VERSION 5.8 ;
BUSBITCHARS "[]" ;
DIVIDERCHAR "/" ;
UNITS
    DATABASE MICRONS 1000 ;
END UNITS

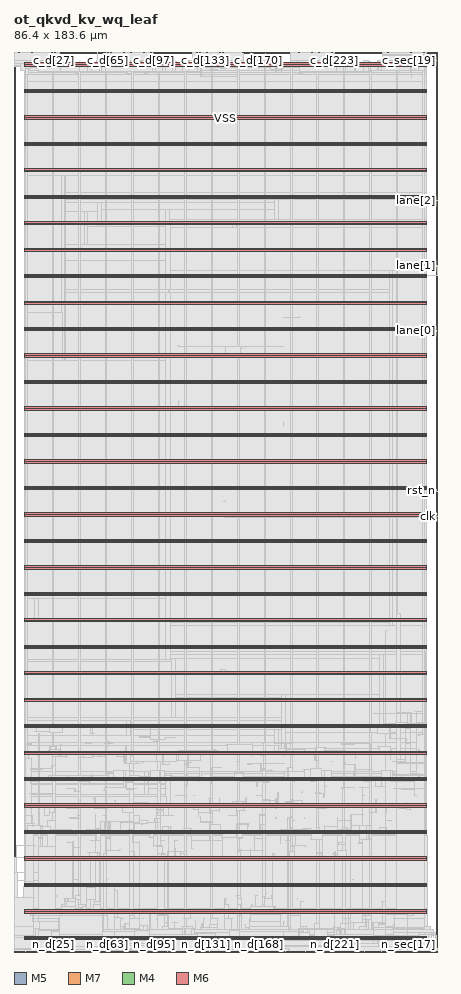
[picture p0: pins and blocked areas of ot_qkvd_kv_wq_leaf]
MACRO ot_qkvd_kv_wq_leaf
  FOREIGN ot_qkvd_kv_wq_leaf 0 0 ;
  CLASS BLOCK ;
  SIZE 86.4 BY 183.6 ;
  PIN c_d[0]
    DIRECTION INPUT ;
    USE SIGNAL ;
    PORT
      LAYER M5 ;
        RECT  0.144 183.516 0.168 183.6 ;
    END
  END c_d[0]
  PIN c_d[100]
    DIRECTION INPUT ;
    USE SIGNAL ;
    PORT
      LAYER M7 ;
        RECT  29.44 183.53 29.472 183.6 ;
    END
  END c_d[100]
  PIN c_d[101]
    DIRECTION INPUT ;
    USE SIGNAL ;
    PORT
      LAYER M7 ;
        RECT  29.696 183.53 29.728 183.6 ;
    END
  END c_d[101]
  PIN c_d[102]
    DIRECTION INPUT ;
    USE SIGNAL ;
    PORT
      LAYER M7 ;
        RECT  30.016 183.53 30.048 183.6 ;
    END
  END c_d[102]
  PIN c_d[103]
    DIRECTION INPUT ;
    USE SIGNAL ;
    PORT
      LAYER M7 ;
        RECT  30.272 183.53 30.304 183.6 ;
    END
  END c_d[103]
  PIN c_d[104]
    DIRECTION INPUT ;
    USE SIGNAL ;
    PORT
      LAYER M7 ;
        RECT  30.592 183.53 30.624 183.6 ;
    END
  END c_d[104]
  PIN c_d[105]
    DIRECTION INPUT ;
    USE SIGNAL ;
    PORT
      LAYER M7 ;
        RECT  30.912 183.53 30.944 183.6 ;
    END
  END c_d[105]
  PIN c_d[106]
    DIRECTION INPUT ;
    USE SIGNAL ;
    PORT
      LAYER M7 ;
        RECT  31.168 183.53 31.2 183.6 ;
    END
  END c_d[106]
  PIN c_d[107]
    DIRECTION INPUT ;
    USE SIGNAL ;
    PORT
      LAYER M7 ;
        RECT  31.488 183.53 31.52 183.6 ;
    END
  END c_d[107]
  PIN c_d[108]
    DIRECTION INPUT ;
    USE SIGNAL ;
    PORT
      LAYER M7 ;
        RECT  31.744 183.53 31.776 183.6 ;
    END
  END c_d[108]
  PIN c_d[109]
    DIRECTION INPUT ;
    USE SIGNAL ;
    PORT
      LAYER M7 ;
        RECT  32.064 183.53 32.096 183.6 ;
    END
  END c_d[109]
  PIN c_d[10]
    DIRECTION INPUT ;
    USE SIGNAL ;
    PORT
      LAYER M5 ;
        RECT  3.072 183.516 3.096 183.6 ;
    END
  END c_d[10]
  PIN c_d[110]
    DIRECTION INPUT ;
    USE SIGNAL ;
    PORT
      LAYER M7 ;
        RECT  32.32 183.53 32.352 183.6 ;
    END
  END c_d[110]
  PIN c_d[111]
    DIRECTION INPUT ;
    USE SIGNAL ;
    PORT
      LAYER M7 ;
        RECT  32.64 183.53 32.672 183.6 ;
    END
  END c_d[111]
  PIN c_d[112]
    DIRECTION INPUT ;
    USE SIGNAL ;
    PORT
      LAYER M7 ;
        RECT  32.96 183.53 32.992 183.6 ;
    END
  END c_d[112]
  PIN c_d[113]
    DIRECTION INPUT ;
    USE SIGNAL ;
    PORT
      LAYER M7 ;
        RECT  33.216 183.53 33.248 183.6 ;
    END
  END c_d[113]
  PIN c_d[114]
    DIRECTION INPUT ;
    USE SIGNAL ;
    PORT
      LAYER M7 ;
        RECT  33.536 183.53 33.568 183.6 ;
    END
  END c_d[114]
  PIN c_d[115]
    DIRECTION INPUT ;
    USE SIGNAL ;
    PORT
      LAYER M7 ;
        RECT  33.792 183.53 33.824 183.6 ;
    END
  END c_d[115]
  PIN c_d[116]
    DIRECTION INPUT ;
    USE SIGNAL ;
    PORT
      LAYER M7 ;
        RECT  34.112 183.53 34.144 183.6 ;
    END
  END c_d[116]
  PIN c_d[117]
    DIRECTION INPUT ;
    USE SIGNAL ;
    PORT
      LAYER M7 ;
        RECT  34.368 183.53 34.4 183.6 ;
    END
  END c_d[117]
  PIN c_d[118]
    DIRECTION INPUT ;
    USE SIGNAL ;
    PORT
      LAYER M7 ;
        RECT  34.688 183.53 34.72 183.6 ;
    END
  END c_d[118]
  PIN c_d[119]
    DIRECTION INPUT ;
    USE SIGNAL ;
    PORT
      LAYER M7 ;
        RECT  35.008 183.53 35.04 183.6 ;
    END
  END c_d[119]
  PIN c_d[11]
    DIRECTION INPUT ;
    USE SIGNAL ;
    PORT
      LAYER M5 ;
        RECT  3.36 183.516 3.384 183.6 ;
    END
  END c_d[11]
  PIN c_d[120]
    DIRECTION INPUT ;
    USE SIGNAL ;
    PORT
      LAYER M7 ;
        RECT  35.264 183.53 35.296 183.6 ;
    END
  END c_d[120]
  PIN c_d[121]
    DIRECTION INPUT ;
    USE SIGNAL ;
    PORT
      LAYER M7 ;
        RECT  35.584 183.53 35.616 183.6 ;
    END
  END c_d[121]
  PIN c_d[122]
    DIRECTION INPUT ;
    USE SIGNAL ;
    PORT
      LAYER M7 ;
        RECT  35.84 183.53 35.872 183.6 ;
    END
  END c_d[122]
  PIN c_d[123]
    DIRECTION INPUT ;
    USE SIGNAL ;
    PORT
      LAYER M7 ;
        RECT  36.16 183.53 36.192 183.6 ;
    END
  END c_d[123]
  PIN c_d[124]
    DIRECTION INPUT ;
    USE SIGNAL ;
    PORT
      LAYER M7 ;
        RECT  36.48 183.53 36.512 183.6 ;
    END
  END c_d[124]
  PIN c_d[125]
    DIRECTION INPUT ;
    USE SIGNAL ;
    PORT
      LAYER M7 ;
        RECT  36.736 183.53 36.768 183.6 ;
    END
  END c_d[125]
  PIN c_d[126]
    DIRECTION INPUT ;
    USE SIGNAL ;
    PORT
      LAYER M7 ;
        RECT  37.056 183.53 37.088 183.6 ;
    END
  END c_d[126]
  PIN c_d[127]
    DIRECTION INPUT ;
    USE SIGNAL ;
    PORT
      LAYER M7 ;
        RECT  37.312 183.53 37.344 183.6 ;
    END
  END c_d[127]
  PIN c_d[128]
    DIRECTION INPUT ;
    USE SIGNAL ;
    PORT
      LAYER M5 ;
        RECT  37.632 183.516 37.656 183.6 ;
    END
  END c_d[128]
  PIN c_d[129]
    DIRECTION INPUT ;
    USE SIGNAL ;
    PORT
      LAYER M5 ;
        RECT  37.92 183.516 37.944 183.6 ;
    END
  END c_d[129]
  PIN c_d[12]
    DIRECTION INPUT ;
    USE SIGNAL ;
    PORT
      LAYER M5 ;
        RECT  3.648 183.516 3.672 183.6 ;
    END
  END c_d[12]
  PIN c_d[130]
    DIRECTION INPUT ;
    USE SIGNAL ;
    PORT
      LAYER M5 ;
        RECT  38.208 183.516 38.232 183.6 ;
    END
  END c_d[130]
  PIN c_d[131]
    DIRECTION INPUT ;
    USE SIGNAL ;
    PORT
      LAYER M5 ;
        RECT  38.496 183.516 38.52 183.6 ;
    END
  END c_d[131]
  PIN c_d[132]
    DIRECTION INPUT ;
    USE SIGNAL ;
    PORT
      LAYER M5 ;
        RECT  38.784 183.516 38.808 183.6 ;
    END
  END c_d[132]
  PIN c_d[133]
    DIRECTION INPUT ;
    USE SIGNAL ;
    PORT
      LAYER M5 ;
        RECT  39.072 183.516 39.096 183.6 ;
    END
  END c_d[133]
  PIN c_d[134]
    DIRECTION INPUT ;
    USE SIGNAL ;
    PORT
      LAYER M5 ;
        RECT  39.36 183.516 39.384 183.6 ;
    END
  END c_d[134]
  PIN c_d[135]
    DIRECTION INPUT ;
    USE SIGNAL ;
    PORT
      LAYER M5 ;
        RECT  39.696 183.516 39.72 183.6 ;
    END
  END c_d[135]
  PIN c_d[136]
    DIRECTION INPUT ;
    USE SIGNAL ;
    PORT
      LAYER M5 ;
        RECT  39.984 183.516 40.008 183.6 ;
    END
  END c_d[136]
  PIN c_d[137]
    DIRECTION INPUT ;
    USE SIGNAL ;
    PORT
      LAYER M5 ;
        RECT  40.272 183.516 40.296 183.6 ;
    END
  END c_d[137]
  PIN c_d[138]
    DIRECTION INPUT ;
    USE SIGNAL ;
    PORT
      LAYER M5 ;
        RECT  40.56 183.516 40.584 183.6 ;
    END
  END c_d[138]
  PIN c_d[139]
    DIRECTION INPUT ;
    USE SIGNAL ;
    PORT
      LAYER M5 ;
        RECT  40.848 183.516 40.872 183.6 ;
    END
  END c_d[139]
  PIN c_d[13]
    DIRECTION INPUT ;
    USE SIGNAL ;
    PORT
      LAYER M5 ;
        RECT  3.936 183.516 3.96 183.6 ;
    END
  END c_d[13]
  PIN c_d[140]
    DIRECTION INPUT ;
    USE SIGNAL ;
    PORT
      LAYER M5 ;
        RECT  41.136 183.516 41.16 183.6 ;
    END
  END c_d[140]
  PIN c_d[141]
    DIRECTION INPUT ;
    USE SIGNAL ;
    PORT
      LAYER M5 ;
        RECT  41.424 183.516 41.448 183.6 ;
    END
  END c_d[141]
  PIN c_d[142]
    DIRECTION INPUT ;
    USE SIGNAL ;
    PORT
      LAYER M5 ;
        RECT  41.712 183.516 41.736 183.6 ;
    END
  END c_d[142]
  PIN c_d[143]
    DIRECTION INPUT ;
    USE SIGNAL ;
    PORT
      LAYER M5 ;
        RECT  42 183.516 42.024 183.6 ;
    END
  END c_d[143]
  PIN c_d[144]
    DIRECTION INPUT ;
    USE SIGNAL ;
    PORT
      LAYER M5 ;
        RECT  42.288 183.516 42.312 183.6 ;
    END
  END c_d[144]
  PIN c_d[145]
    DIRECTION INPUT ;
    USE SIGNAL ;
    PORT
      LAYER M5 ;
        RECT  42.624 183.516 42.648 183.6 ;
    END
  END c_d[145]
  PIN c_d[146]
    DIRECTION INPUT ;
    USE SIGNAL ;
    PORT
      LAYER M5 ;
        RECT  42.912 183.516 42.936 183.6 ;
    END
  END c_d[146]
  PIN c_d[147]
    DIRECTION INPUT ;
    USE SIGNAL ;
    PORT
      LAYER M5 ;
        RECT  43.2 183.516 43.224 183.6 ;
    END
  END c_d[147]
  PIN c_d[148]
    DIRECTION INPUT ;
    USE SIGNAL ;
    PORT
      LAYER M5 ;
        RECT  43.488 183.516 43.512 183.6 ;
    END
  END c_d[148]
  PIN c_d[149]
    DIRECTION INPUT ;
    USE SIGNAL ;
    PORT
      LAYER M5 ;
        RECT  43.776 183.516 43.8 183.6 ;
    END
  END c_d[149]
  PIN c_d[14]
    DIRECTION INPUT ;
    USE SIGNAL ;
    PORT
      LAYER M5 ;
        RECT  4.224 183.516 4.248 183.6 ;
    END
  END c_d[14]
  PIN c_d[150]
    DIRECTION INPUT ;
    USE SIGNAL ;
    PORT
      LAYER M5 ;
        RECT  44.064 183.516 44.088 183.6 ;
    END
  END c_d[150]
  PIN c_d[151]
    DIRECTION INPUT ;
    USE SIGNAL ;
    PORT
      LAYER M5 ;
        RECT  44.352 183.516 44.376 183.6 ;
    END
  END c_d[151]
  PIN c_d[152]
    DIRECTION INPUT ;
    USE SIGNAL ;
    PORT
      LAYER M5 ;
        RECT  44.64 183.516 44.664 183.6 ;
    END
  END c_d[152]
  PIN c_d[153]
    DIRECTION INPUT ;
    USE SIGNAL ;
    PORT
      LAYER M5 ;
        RECT  44.928 183.516 44.952 183.6 ;
    END
  END c_d[153]
  PIN c_d[154]
    DIRECTION INPUT ;
    USE SIGNAL ;
    PORT
      LAYER M5 ;
        RECT  45.216 183.516 45.24 183.6 ;
    END
  END c_d[154]
  PIN c_d[155]
    DIRECTION INPUT ;
    USE SIGNAL ;
    PORT
      LAYER M5 ;
        RECT  45.552 183.516 45.576 183.6 ;
    END
  END c_d[155]
  PIN c_d[156]
    DIRECTION INPUT ;
    USE SIGNAL ;
    PORT
      LAYER M5 ;
        RECT  45.84 183.516 45.864 183.6 ;
    END
  END c_d[156]
  PIN c_d[157]
    DIRECTION INPUT ;
    USE SIGNAL ;
    PORT
      LAYER M5 ;
        RECT  46.128 183.516 46.152 183.6 ;
    END
  END c_d[157]
  PIN c_d[158]
    DIRECTION INPUT ;
    USE SIGNAL ;
    PORT
      LAYER M5 ;
        RECT  46.416 183.516 46.44 183.6 ;
    END
  END c_d[158]
  PIN c_d[159]
    DIRECTION INPUT ;
    USE SIGNAL ;
    PORT
      LAYER M5 ;
        RECT  46.704 183.516 46.728 183.6 ;
    END
  END c_d[159]
  PIN c_d[15]
    DIRECTION INPUT ;
    USE SIGNAL ;
    PORT
      LAYER M5 ;
        RECT  4.512 183.516 4.536 183.6 ;
    END
  END c_d[15]
  PIN c_d[160]
    DIRECTION INPUT ;
    USE SIGNAL ;
    PORT
      LAYER M7 ;
        RECT  46.976 183.53 47.008 183.6 ;
    END
  END c_d[160]
  PIN c_d[161]
    DIRECTION INPUT ;
    USE SIGNAL ;
    PORT
      LAYER M7 ;
        RECT  47.296 183.53 47.328 183.6 ;
    END
  END c_d[161]
  PIN c_d[162]
    DIRECTION INPUT ;
    USE SIGNAL ;
    PORT
      LAYER M7 ;
        RECT  47.552 183.53 47.584 183.6 ;
    END
  END c_d[162]
  PIN c_d[163]
    DIRECTION INPUT ;
    USE SIGNAL ;
    PORT
      LAYER M7 ;
        RECT  47.872 183.53 47.904 183.6 ;
    END
  END c_d[163]
  PIN c_d[164]
    DIRECTION INPUT ;
    USE SIGNAL ;
    PORT
      LAYER M7 ;
        RECT  48.192 183.53 48.224 183.6 ;
    END
  END c_d[164]
  PIN c_d[165]
    DIRECTION INPUT ;
    USE SIGNAL ;
    PORT
      LAYER M7 ;
        RECT  48.448 183.53 48.48 183.6 ;
    END
  END c_d[165]
  PIN c_d[166]
    DIRECTION INPUT ;
    USE SIGNAL ;
    PORT
      LAYER M7 ;
        RECT  48.768 183.53 48.8 183.6 ;
    END
  END c_d[166]
  PIN c_d[167]
    DIRECTION INPUT ;
    USE SIGNAL ;
    PORT
      LAYER M7 ;
        RECT  49.024 183.53 49.056 183.6 ;
    END
  END c_d[167]
  PIN c_d[168]
    DIRECTION INPUT ;
    USE SIGNAL ;
    PORT
      LAYER M7 ;
        RECT  49.344 183.53 49.376 183.6 ;
    END
  END c_d[168]
  PIN c_d[169]
    DIRECTION INPUT ;
    USE SIGNAL ;
    PORT
      LAYER M7 ;
        RECT  49.6 183.53 49.632 183.6 ;
    END
  END c_d[169]
  PIN c_d[16]
    DIRECTION INPUT ;
    USE SIGNAL ;
    PORT
      LAYER M5 ;
        RECT  4.8 183.516 4.824 183.6 ;
    END
  END c_d[16]
  PIN c_d[170]
    DIRECTION INPUT ;
    USE SIGNAL ;
    PORT
      LAYER M7 ;
        RECT  49.92 183.53 49.952 183.6 ;
    END
  END c_d[170]
  PIN c_d[171]
    DIRECTION INPUT ;
    USE SIGNAL ;
    PORT
      LAYER M7 ;
        RECT  50.24 183.53 50.272 183.6 ;
    END
  END c_d[171]
  PIN c_d[172]
    DIRECTION INPUT ;
    USE SIGNAL ;
    PORT
      LAYER M7 ;
        RECT  50.496 183.53 50.528 183.6 ;
    END
  END c_d[172]
  PIN c_d[173]
    DIRECTION INPUT ;
    USE SIGNAL ;
    PORT
      LAYER M7 ;
        RECT  50.816 183.53 50.848 183.6 ;
    END
  END c_d[173]
  PIN c_d[174]
    DIRECTION INPUT ;
    USE SIGNAL ;
    PORT
      LAYER M7 ;
        RECT  51.072 183.53 51.104 183.6 ;
    END
  END c_d[174]
  PIN c_d[175]
    DIRECTION INPUT ;
    USE SIGNAL ;
    PORT
      LAYER M7 ;
        RECT  51.392 183.53 51.424 183.6 ;
    END
  END c_d[175]
  PIN c_d[176]
    DIRECTION INPUT ;
    USE SIGNAL ;
    PORT
      LAYER M7 ;
        RECT  51.648 183.53 51.68 183.6 ;
    END
  END c_d[176]
  PIN c_d[177]
    DIRECTION INPUT ;
    USE SIGNAL ;
    PORT
      LAYER M7 ;
        RECT  51.968 183.53 52 183.6 ;
    END
  END c_d[177]
  PIN c_d[178]
    DIRECTION INPUT ;
    USE SIGNAL ;
    PORT
      LAYER M7 ;
        RECT  52.288 183.53 52.32 183.6 ;
    END
  END c_d[178]
  PIN c_d[179]
    DIRECTION INPUT ;
    USE SIGNAL ;
    PORT
      LAYER M7 ;
        RECT  52.544 183.53 52.576 183.6 ;
    END
  END c_d[179]
  PIN c_d[17]
    DIRECTION INPUT ;
    USE SIGNAL ;
    PORT
      LAYER M5 ;
        RECT  5.136 183.516 5.16 183.6 ;
    END
  END c_d[17]
  PIN c_d[180]
    DIRECTION INPUT ;
    USE SIGNAL ;
    PORT
      LAYER M7 ;
        RECT  52.864 183.53 52.896 183.6 ;
    END
  END c_d[180]
  PIN c_d[181]
    DIRECTION INPUT ;
    USE SIGNAL ;
    PORT
      LAYER M7 ;
        RECT  53.12 183.53 53.152 183.6 ;
    END
  END c_d[181]
  PIN c_d[182]
    DIRECTION INPUT ;
    USE SIGNAL ;
    PORT
      LAYER M7 ;
        RECT  53.44 183.53 53.472 183.6 ;
    END
  END c_d[182]
  PIN c_d[183]
    DIRECTION INPUT ;
    USE SIGNAL ;
    PORT
      LAYER M7 ;
        RECT  53.76 183.53 53.792 183.6 ;
    END
  END c_d[183]
  PIN c_d[184]
    DIRECTION INPUT ;
    USE SIGNAL ;
    PORT
      LAYER M7 ;
        RECT  54.016 183.53 54.048 183.6 ;
    END
  END c_d[184]
  PIN c_d[185]
    DIRECTION INPUT ;
    USE SIGNAL ;
    PORT
      LAYER M7 ;
        RECT  54.336 183.53 54.368 183.6 ;
    END
  END c_d[185]
  PIN c_d[186]
    DIRECTION INPUT ;
    USE SIGNAL ;
    PORT
      LAYER M7 ;
        RECT  54.592 183.53 54.624 183.6 ;
    END
  END c_d[186]
  PIN c_d[187]
    DIRECTION INPUT ;
    USE SIGNAL ;
    PORT
      LAYER M7 ;
        RECT  54.912 183.53 54.944 183.6 ;
    END
  END c_d[187]
  PIN c_d[188]
    DIRECTION INPUT ;
    USE SIGNAL ;
    PORT
      LAYER M7 ;
        RECT  55.168 183.53 55.2 183.6 ;
    END
  END c_d[188]
  PIN c_d[189]
    DIRECTION INPUT ;
    USE SIGNAL ;
    PORT
      LAYER M7 ;
        RECT  55.488 183.53 55.52 183.6 ;
    END
  END c_d[189]
  PIN c_d[18]
    DIRECTION INPUT ;
    USE SIGNAL ;
    PORT
      LAYER M5 ;
        RECT  5.424 183.516 5.448 183.6 ;
    END
  END c_d[18]
  PIN c_d[190]
    DIRECTION INPUT ;
    USE SIGNAL ;
    PORT
      LAYER M7 ;
        RECT  55.808 183.53 55.84 183.6 ;
    END
  END c_d[190]
  PIN c_d[191]
    DIRECTION INPUT ;
    USE SIGNAL ;
    PORT
      LAYER M7 ;
        RECT  56.064 183.53 56.096 183.6 ;
    END
  END c_d[191]
  PIN c_d[192]
    DIRECTION INPUT ;
    USE SIGNAL ;
    PORT
      LAYER M5 ;
        RECT  56.352 183.516 56.376 183.6 ;
    END
  END c_d[192]
  PIN c_d[193]
    DIRECTION INPUT ;
    USE SIGNAL ;
    PORT
      LAYER M5 ;
        RECT  56.64 183.516 56.664 183.6 ;
    END
  END c_d[193]
  PIN c_d[194]
    DIRECTION INPUT ;
    USE SIGNAL ;
    PORT
      LAYER M5 ;
        RECT  56.976 183.516 57 183.6 ;
    END
  END c_d[194]
  PIN c_d[195]
    DIRECTION INPUT ;
    USE SIGNAL ;
    PORT
      LAYER M5 ;
        RECT  57.264 183.516 57.288 183.6 ;
    END
  END c_d[195]
  PIN c_d[196]
    DIRECTION INPUT ;
    USE SIGNAL ;
    PORT
      LAYER M5 ;
        RECT  57.552 183.516 57.576 183.6 ;
    END
  END c_d[196]
  PIN c_d[197]
    DIRECTION INPUT ;
    USE SIGNAL ;
    PORT
      LAYER M5 ;
        RECT  57.84 183.516 57.864 183.6 ;
    END
  END c_d[197]
  PIN c_d[198]
    DIRECTION INPUT ;
    USE SIGNAL ;
    PORT
      LAYER M5 ;
        RECT  58.128 183.516 58.152 183.6 ;
    END
  END c_d[198]
  PIN c_d[199]
    DIRECTION INPUT ;
    USE SIGNAL ;
    PORT
      LAYER M5 ;
        RECT  58.416 183.516 58.44 183.6 ;
    END
  END c_d[199]
  PIN c_d[19]
    DIRECTION INPUT ;
    USE SIGNAL ;
    PORT
      LAYER M5 ;
        RECT  5.712 183.516 5.736 183.6 ;
    END
  END c_d[19]
  PIN c_d[1]
    DIRECTION INPUT ;
    USE SIGNAL ;
    PORT
      LAYER M5 ;
        RECT  0.432 183.516 0.456 183.6 ;
    END
  END c_d[1]
  PIN c_d[200]
    DIRECTION INPUT ;
    USE SIGNAL ;
    PORT
      LAYER M5 ;
        RECT  58.704 183.516 58.728 183.6 ;
    END
  END c_d[200]
  PIN c_d[201]
    DIRECTION INPUT ;
    USE SIGNAL ;
    PORT
      LAYER M5 ;
        RECT  58.992 183.516 59.016 183.6 ;
    END
  END c_d[201]
  PIN c_d[202]
    DIRECTION INPUT ;
    USE SIGNAL ;
    PORT
      LAYER M5 ;
        RECT  59.28 183.516 59.304 183.6 ;
    END
  END c_d[202]
  PIN c_d[203]
    DIRECTION INPUT ;
    USE SIGNAL ;
    PORT
      LAYER M5 ;
        RECT  59.568 183.516 59.592 183.6 ;
    END
  END c_d[203]
  PIN c_d[204]
    DIRECTION INPUT ;
    USE SIGNAL ;
    PORT
      LAYER M5 ;
        RECT  59.904 183.516 59.928 183.6 ;
    END
  END c_d[204]
  PIN c_d[205]
    DIRECTION INPUT ;
    USE SIGNAL ;
    PORT
      LAYER M5 ;
        RECT  60.192 183.516 60.216 183.6 ;
    END
  END c_d[205]
  PIN c_d[206]
    DIRECTION INPUT ;
    USE SIGNAL ;
    PORT
      LAYER M5 ;
        RECT  60.48 183.516 60.504 183.6 ;
    END
  END c_d[206]
  PIN c_d[207]
    DIRECTION INPUT ;
    USE SIGNAL ;
    PORT
      LAYER M5 ;
        RECT  60.768 183.516 60.792 183.6 ;
    END
  END c_d[207]
  PIN c_d[208]
    DIRECTION INPUT ;
    USE SIGNAL ;
    PORT
      LAYER M5 ;
        RECT  61.056 183.516 61.08 183.6 ;
    END
  END c_d[208]
  PIN c_d[209]
    DIRECTION INPUT ;
    USE SIGNAL ;
    PORT
      LAYER M5 ;
        RECT  61.344 183.516 61.368 183.6 ;
    END
  END c_d[209]
  PIN c_d[20]
    DIRECTION INPUT ;
    USE SIGNAL ;
    PORT
      LAYER M5 ;
        RECT  6 183.516 6.024 183.6 ;
    END
  END c_d[20]
  PIN c_d[210]
    DIRECTION INPUT ;
    USE SIGNAL ;
    PORT
      LAYER M5 ;
        RECT  61.632 183.516 61.656 183.6 ;
    END
  END c_d[210]
  PIN c_d[211]
    DIRECTION INPUT ;
    USE SIGNAL ;
    PORT
      LAYER M5 ;
        RECT  61.92 183.516 61.944 183.6 ;
    END
  END c_d[211]
  PIN c_d[212]
    DIRECTION INPUT ;
    USE SIGNAL ;
    PORT
      LAYER M5 ;
        RECT  62.208 183.516 62.232 183.6 ;
    END
  END c_d[212]
  PIN c_d[213]
    DIRECTION INPUT ;
    USE SIGNAL ;
    PORT
      LAYER M5 ;
        RECT  62.496 183.516 62.52 183.6 ;
    END
  END c_d[213]
  PIN c_d[214]
    DIRECTION INPUT ;
    USE SIGNAL ;
    PORT
      LAYER M5 ;
        RECT  62.832 183.516 62.856 183.6 ;
    END
  END c_d[214]
  PIN c_d[215]
    DIRECTION INPUT ;
    USE SIGNAL ;
    PORT
      LAYER M5 ;
        RECT  63.12 183.516 63.144 183.6 ;
    END
  END c_d[215]
  PIN c_d[216]
    DIRECTION INPUT ;
    USE SIGNAL ;
    PORT
      LAYER M5 ;
        RECT  63.408 183.516 63.432 183.6 ;
    END
  END c_d[216]
  PIN c_d[217]
    DIRECTION INPUT ;
    USE SIGNAL ;
    PORT
      LAYER M5 ;
        RECT  63.696 183.516 63.72 183.6 ;
    END
  END c_d[217]
  PIN c_d[218]
    DIRECTION INPUT ;
    USE SIGNAL ;
    PORT
      LAYER M5 ;
        RECT  63.984 183.516 64.008 183.6 ;
    END
  END c_d[218]
  PIN c_d[219]
    DIRECTION INPUT ;
    USE SIGNAL ;
    PORT
      LAYER M5 ;
        RECT  64.272 183.516 64.296 183.6 ;
    END
  END c_d[219]
  PIN c_d[21]
    DIRECTION INPUT ;
    USE SIGNAL ;
    PORT
      LAYER M5 ;
        RECT  6.288 183.516 6.312 183.6 ;
    END
  END c_d[21]
  PIN c_d[220]
    DIRECTION INPUT ;
    USE SIGNAL ;
    PORT
      LAYER M5 ;
        RECT  64.56 183.516 64.584 183.6 ;
    END
  END c_d[220]
  PIN c_d[221]
    DIRECTION INPUT ;
    USE SIGNAL ;
    PORT
      LAYER M5 ;
        RECT  64.848 183.516 64.872 183.6 ;
    END
  END c_d[221]
  PIN c_d[222]
    DIRECTION INPUT ;
    USE SIGNAL ;
    PORT
      LAYER M5 ;
        RECT  65.136 183.516 65.16 183.6 ;
    END
  END c_d[222]
  PIN c_d[223]
    DIRECTION INPUT ;
    USE SIGNAL ;
    PORT
      LAYER M5 ;
        RECT  65.424 183.516 65.448 183.6 ;
    END
  END c_d[223]
  PIN c_d[224]
    DIRECTION INPUT ;
    USE SIGNAL ;
    PORT
      LAYER M7 ;
        RECT  65.728 183.53 65.76 183.6 ;
    END
  END c_d[224]
  PIN c_d[225]
    DIRECTION INPUT ;
    USE SIGNAL ;
    PORT
      LAYER M7 ;
        RECT  66.048 183.53 66.08 183.6 ;
    END
  END c_d[225]
  PIN c_d[226]
    DIRECTION INPUT ;
    USE SIGNAL ;
    PORT
      LAYER M7 ;
        RECT  66.304 183.53 66.336 183.6 ;
    END
  END c_d[226]
  PIN c_d[227]
    DIRECTION INPUT ;
    USE SIGNAL ;
    PORT
      LAYER M7 ;
        RECT  66.624 183.53 66.656 183.6 ;
    END
  END c_d[227]
  PIN c_d[228]
    DIRECTION INPUT ;
    USE SIGNAL ;
    PORT
      LAYER M7 ;
        RECT  66.88 183.53 66.912 183.6 ;
    END
  END c_d[228]
  PIN c_d[229]
    DIRECTION INPUT ;
    USE SIGNAL ;
    PORT
      LAYER M7 ;
        RECT  67.2 183.53 67.232 183.6 ;
    END
  END c_d[229]
  PIN c_d[22]
    DIRECTION INPUT ;
    USE SIGNAL ;
    PORT
      LAYER M5 ;
        RECT  6.576 183.516 6.6 183.6 ;
    END
  END c_d[22]
  PIN c_d[230]
    DIRECTION INPUT ;
    USE SIGNAL ;
    PORT
      LAYER M7 ;
        RECT  67.52 183.53 67.552 183.6 ;
    END
  END c_d[230]
  PIN c_d[231]
    DIRECTION INPUT ;
    USE SIGNAL ;
    PORT
      LAYER M7 ;
        RECT  67.776 183.53 67.808 183.6 ;
    END
  END c_d[231]
  PIN c_d[232]
    DIRECTION INPUT ;
    USE SIGNAL ;
    PORT
      LAYER M7 ;
        RECT  68.096 183.53 68.128 183.6 ;
    END
  END c_d[232]
  PIN c_d[233]
    DIRECTION INPUT ;
    USE SIGNAL ;
    PORT
      LAYER M7 ;
        RECT  68.352 183.53 68.384 183.6 ;
    END
  END c_d[233]
  PIN c_d[234]
    DIRECTION INPUT ;
    USE SIGNAL ;
    PORT
      LAYER M7 ;
        RECT  68.672 183.53 68.704 183.6 ;
    END
  END c_d[234]
  PIN c_d[235]
    DIRECTION INPUT ;
    USE SIGNAL ;
    PORT
      LAYER M7 ;
        RECT  68.928 183.53 68.96 183.6 ;
    END
  END c_d[235]
  PIN c_d[236]
    DIRECTION INPUT ;
    USE SIGNAL ;
    PORT
      LAYER M7 ;
        RECT  69.248 183.53 69.28 183.6 ;
    END
  END c_d[236]
  PIN c_d[237]
    DIRECTION INPUT ;
    USE SIGNAL ;
    PORT
      LAYER M7 ;
        RECT  69.568 183.53 69.6 183.6 ;
    END
  END c_d[237]
  PIN c_d[238]
    DIRECTION INPUT ;
    USE SIGNAL ;
    PORT
      LAYER M7 ;
        RECT  69.824 183.53 69.856 183.6 ;
    END
  END c_d[238]
  PIN c_d[239]
    DIRECTION INPUT ;
    USE SIGNAL ;
    PORT
      LAYER M7 ;
        RECT  70.144 183.53 70.176 183.6 ;
    END
  END c_d[239]
  PIN c_d[23]
    DIRECTION INPUT ;
    USE SIGNAL ;
    PORT
      LAYER M5 ;
        RECT  6.864 183.516 6.888 183.6 ;
    END
  END c_d[23]
  PIN c_d[240]
    DIRECTION INPUT ;
    USE SIGNAL ;
    PORT
      LAYER M7 ;
        RECT  70.4 183.53 70.432 183.6 ;
    END
  END c_d[240]
  PIN c_d[241]
    DIRECTION INPUT ;
    USE SIGNAL ;
    PORT
      LAYER M7 ;
        RECT  70.72 183.53 70.752 183.6 ;
    END
  END c_d[241]
  PIN c_d[242]
    DIRECTION INPUT ;
    USE SIGNAL ;
    PORT
      LAYER M7 ;
        RECT  71.04 183.53 71.072 183.6 ;
    END
  END c_d[242]
  PIN c_d[243]
    DIRECTION INPUT ;
    USE SIGNAL ;
    PORT
      LAYER M7 ;
        RECT  71.296 183.53 71.328 183.6 ;
    END
  END c_d[243]
  PIN c_d[244]
    DIRECTION INPUT ;
    USE SIGNAL ;
    PORT
      LAYER M7 ;
        RECT  71.616 183.53 71.648 183.6 ;
    END
  END c_d[244]
  PIN c_d[245]
    DIRECTION INPUT ;
    USE SIGNAL ;
    PORT
      LAYER M7 ;
        RECT  71.872 183.53 71.904 183.6 ;
    END
  END c_d[245]
  PIN c_d[246]
    DIRECTION INPUT ;
    USE SIGNAL ;
    PORT
      LAYER M7 ;
        RECT  72.192 183.53 72.224 183.6 ;
    END
  END c_d[246]
  PIN c_d[247]
    DIRECTION INPUT ;
    USE SIGNAL ;
    PORT
      LAYER M7 ;
        RECT  72.448 183.53 72.48 183.6 ;
    END
  END c_d[247]
  PIN c_d[248]
    DIRECTION INPUT ;
    USE SIGNAL ;
    PORT
      LAYER M7 ;
        RECT  72.768 183.53 72.8 183.6 ;
    END
  END c_d[248]
  PIN c_d[249]
    DIRECTION INPUT ;
    USE SIGNAL ;
    PORT
      LAYER M7 ;
        RECT  73.088 183.53 73.12 183.6 ;
    END
  END c_d[249]
  PIN c_d[24]
    DIRECTION INPUT ;
    USE SIGNAL ;
    PORT
      LAYER M5 ;
        RECT  7.152 183.516 7.176 183.6 ;
    END
  END c_d[24]
  PIN c_d[250]
    DIRECTION INPUT ;
    USE SIGNAL ;
    PORT
      LAYER M7 ;
        RECT  73.344 183.53 73.376 183.6 ;
    END
  END c_d[250]
  PIN c_d[251]
    DIRECTION INPUT ;
    USE SIGNAL ;
    PORT
      LAYER M7 ;
        RECT  73.664 183.53 73.696 183.6 ;
    END
  END c_d[251]
  PIN c_d[252]
    DIRECTION INPUT ;
    USE SIGNAL ;
    PORT
      LAYER M7 ;
        RECT  73.92 183.53 73.952 183.6 ;
    END
  END c_d[252]
  PIN c_d[253]
    DIRECTION INPUT ;
    USE SIGNAL ;
    PORT
      LAYER M7 ;
        RECT  74.24 183.53 74.272 183.6 ;
    END
  END c_d[253]
  PIN c_d[254]
    DIRECTION INPUT ;
    USE SIGNAL ;
    PORT
      LAYER M7 ;
        RECT  74.496 183.53 74.528 183.6 ;
    END
  END c_d[254]
  PIN c_d[255]
    DIRECTION INPUT ;
    USE SIGNAL ;
    PORT
      LAYER M7 ;
        RECT  74.816 183.53 74.848 183.6 ;
    END
  END c_d[255]
  PIN c_d[25]
    DIRECTION INPUT ;
    USE SIGNAL ;
    PORT
      LAYER M5 ;
        RECT  7.44 183.516 7.464 183.6 ;
    END
  END c_d[25]
  PIN c_d[26]
    DIRECTION INPUT ;
    USE SIGNAL ;
    PORT
      LAYER M5 ;
        RECT  7.728 183.516 7.752 183.6 ;
    END
  END c_d[26]
  PIN c_d[27]
    DIRECTION INPUT ;
    USE SIGNAL ;
    PORT
      LAYER M5 ;
        RECT  8.064 183.516 8.088 183.6 ;
    END
  END c_d[27]
  PIN c_d[28]
    DIRECTION INPUT ;
    USE SIGNAL ;
    PORT
      LAYER M5 ;
        RECT  8.352 183.516 8.376 183.6 ;
    END
  END c_d[28]
  PIN c_d[29]
    DIRECTION INPUT ;
    USE SIGNAL ;
    PORT
      LAYER M5 ;
        RECT  8.64 183.516 8.664 183.6 ;
    END
  END c_d[29]
  PIN c_d[2]
    DIRECTION INPUT ;
    USE SIGNAL ;
    PORT
      LAYER M5 ;
        RECT  0.72 183.516 0.744 183.6 ;
    END
  END c_d[2]
  PIN c_d[30]
    DIRECTION INPUT ;
    USE SIGNAL ;
    PORT
      LAYER M5 ;
        RECT  8.928 183.516 8.952 183.6 ;
    END
  END c_d[30]
  PIN c_d[31]
    DIRECTION INPUT ;
    USE SIGNAL ;
    PORT
      LAYER M5 ;
        RECT  9.216 183.516 9.24 183.6 ;
    END
  END c_d[31]
  PIN c_d[32]
    DIRECTION INPUT ;
    USE SIGNAL ;
    PORT
      LAYER M7 ;
        RECT  9.472 183.53 9.504 183.6 ;
    END
  END c_d[32]
  PIN c_d[33]
    DIRECTION INPUT ;
    USE SIGNAL ;
    PORT
      LAYER M7 ;
        RECT  9.792 183.53 9.824 183.6 ;
    END
  END c_d[33]
  PIN c_d[34]
    DIRECTION INPUT ;
    USE SIGNAL ;
    PORT
      LAYER M7 ;
        RECT  10.112 183.53 10.144 183.6 ;
    END
  END c_d[34]
  PIN c_d[35]
    DIRECTION INPUT ;
    USE SIGNAL ;
    PORT
      LAYER M7 ;
        RECT  10.368 183.53 10.4 183.6 ;
    END
  END c_d[35]
  PIN c_d[36]
    DIRECTION INPUT ;
    USE SIGNAL ;
    PORT
      LAYER M7 ;
        RECT  10.688 183.53 10.72 183.6 ;
    END
  END c_d[36]
  PIN c_d[37]
    DIRECTION INPUT ;
    USE SIGNAL ;
    PORT
      LAYER M7 ;
        RECT  10.944 183.53 10.976 183.6 ;
    END
  END c_d[37]
  PIN c_d[38]
    DIRECTION INPUT ;
    USE SIGNAL ;
    PORT
      LAYER M7 ;
        RECT  11.264 183.53 11.296 183.6 ;
    END
  END c_d[38]
  PIN c_d[39]
    DIRECTION INPUT ;
    USE SIGNAL ;
    PORT
      LAYER M7 ;
        RECT  11.584 183.53 11.616 183.6 ;
    END
  END c_d[39]
  PIN c_d[3]
    DIRECTION INPUT ;
    USE SIGNAL ;
    PORT
      LAYER M5 ;
        RECT  1.008 183.516 1.032 183.6 ;
    END
  END c_d[3]
  PIN c_d[40]
    DIRECTION INPUT ;
    USE SIGNAL ;
    PORT
      LAYER M7 ;
        RECT  11.84 183.53 11.872 183.6 ;
    END
  END c_d[40]
  PIN c_d[41]
    DIRECTION INPUT ;
    USE SIGNAL ;
    PORT
      LAYER M7 ;
        RECT  12.16 183.53 12.192 183.6 ;
    END
  END c_d[41]
  PIN c_d[42]
    DIRECTION INPUT ;
    USE SIGNAL ;
    PORT
      LAYER M7 ;
        RECT  12.416 183.53 12.448 183.6 ;
    END
  END c_d[42]
  PIN c_d[43]
    DIRECTION INPUT ;
    USE SIGNAL ;
    PORT
      LAYER M7 ;
        RECT  12.736 183.53 12.768 183.6 ;
    END
  END c_d[43]
  PIN c_d[44]
    DIRECTION INPUT ;
    USE SIGNAL ;
    PORT
      LAYER M7 ;
        RECT  12.992 183.53 13.024 183.6 ;
    END
  END c_d[44]
  PIN c_d[45]
    DIRECTION INPUT ;
    USE SIGNAL ;
    PORT
      LAYER M7 ;
        RECT  13.312 183.53 13.344 183.6 ;
    END
  END c_d[45]
  PIN c_d[46]
    DIRECTION INPUT ;
    USE SIGNAL ;
    PORT
      LAYER M7 ;
        RECT  13.632 183.53 13.664 183.6 ;
    END
  END c_d[46]
  PIN c_d[47]
    DIRECTION INPUT ;
    USE SIGNAL ;
    PORT
      LAYER M7 ;
        RECT  13.888 183.53 13.92 183.6 ;
    END
  END c_d[47]
  PIN c_d[48]
    DIRECTION INPUT ;
    USE SIGNAL ;
    PORT
      LAYER M7 ;
        RECT  14.208 183.53 14.24 183.6 ;
    END
  END c_d[48]
  PIN c_d[49]
    DIRECTION INPUT ;
    USE SIGNAL ;
    PORT
      LAYER M7 ;
        RECT  14.464 183.53 14.496 183.6 ;
    END
  END c_d[49]
  PIN c_d[4]
    DIRECTION INPUT ;
    USE SIGNAL ;
    PORT
      LAYER M5 ;
        RECT  1.296 183.516 1.32 183.6 ;
    END
  END c_d[4]
  PIN c_d[50]
    DIRECTION INPUT ;
    USE SIGNAL ;
    PORT
      LAYER M7 ;
        RECT  14.784 183.53 14.816 183.6 ;
    END
  END c_d[50]
  PIN c_d[51]
    DIRECTION INPUT ;
    USE SIGNAL ;
    PORT
      LAYER M7 ;
        RECT  15.04 183.53 15.072 183.6 ;
    END
  END c_d[51]
  PIN c_d[52]
    DIRECTION INPUT ;
    USE SIGNAL ;
    PORT
      LAYER M7 ;
        RECT  15.36 183.53 15.392 183.6 ;
    END
  END c_d[52]
  PIN c_d[53]
    DIRECTION INPUT ;
    USE SIGNAL ;
    PORT
      LAYER M7 ;
        RECT  15.68 183.53 15.712 183.6 ;
    END
  END c_d[53]
  PIN c_d[54]
    DIRECTION INPUT ;
    USE SIGNAL ;
    PORT
      LAYER M7 ;
        RECT  15.936 183.53 15.968 183.6 ;
    END
  END c_d[54]
  PIN c_d[55]
    DIRECTION INPUT ;
    USE SIGNAL ;
    PORT
      LAYER M7 ;
        RECT  16.256 183.53 16.288 183.6 ;
    END
  END c_d[55]
  PIN c_d[56]
    DIRECTION INPUT ;
    USE SIGNAL ;
    PORT
      LAYER M7 ;
        RECT  16.512 183.53 16.544 183.6 ;
    END
  END c_d[56]
  PIN c_d[57]
    DIRECTION INPUT ;
    USE SIGNAL ;
    PORT
      LAYER M7 ;
        RECT  16.832 183.53 16.864 183.6 ;
    END
  END c_d[57]
  PIN c_d[58]
    DIRECTION INPUT ;
    USE SIGNAL ;
    PORT
      LAYER M7 ;
        RECT  17.088 183.53 17.12 183.6 ;
    END
  END c_d[58]
  PIN c_d[59]
    DIRECTION INPUT ;
    USE SIGNAL ;
    PORT
      LAYER M7 ;
        RECT  17.408 183.53 17.44 183.6 ;
    END
  END c_d[59]
  PIN c_d[5]
    DIRECTION INPUT ;
    USE SIGNAL ;
    PORT
      LAYER M5 ;
        RECT  1.584 183.516 1.608 183.6 ;
    END
  END c_d[5]
  PIN c_d[60]
    DIRECTION INPUT ;
    USE SIGNAL ;
    PORT
      LAYER M7 ;
        RECT  17.728 183.53 17.76 183.6 ;
    END
  END c_d[60]
  PIN c_d[61]
    DIRECTION INPUT ;
    USE SIGNAL ;
    PORT
      LAYER M7 ;
        RECT  17.984 183.53 18.016 183.6 ;
    END
  END c_d[61]
  PIN c_d[62]
    DIRECTION INPUT ;
    USE SIGNAL ;
    PORT
      LAYER M7 ;
        RECT  18.304 183.53 18.336 183.6 ;
    END
  END c_d[62]
  PIN c_d[63]
    DIRECTION INPUT ;
    USE SIGNAL ;
    PORT
      LAYER M7 ;
        RECT  18.56 183.53 18.592 183.6 ;
    END
  END c_d[63]
  PIN c_d[64]
    DIRECTION INPUT ;
    USE SIGNAL ;
    PORT
      LAYER M5 ;
        RECT  18.864 183.516 18.888 183.6 ;
    END
  END c_d[64]
  PIN c_d[65]
    DIRECTION INPUT ;
    USE SIGNAL ;
    PORT
      LAYER M5 ;
        RECT  19.152 183.516 19.176 183.6 ;
    END
  END c_d[65]
  PIN c_d[66]
    DIRECTION INPUT ;
    USE SIGNAL ;
    PORT
      LAYER M5 ;
        RECT  19.488 183.516 19.512 183.6 ;
    END
  END c_d[66]
  PIN c_d[67]
    DIRECTION INPUT ;
    USE SIGNAL ;
    PORT
      LAYER M5 ;
        RECT  19.776 183.516 19.8 183.6 ;
    END
  END c_d[67]
  PIN c_d[68]
    DIRECTION INPUT ;
    USE SIGNAL ;
    PORT
      LAYER M5 ;
        RECT  20.064 183.516 20.088 183.6 ;
    END
  END c_d[68]
  PIN c_d[69]
    DIRECTION INPUT ;
    USE SIGNAL ;
    PORT
      LAYER M5 ;
        RECT  20.352 183.516 20.376 183.6 ;
    END
  END c_d[69]
  PIN c_d[6]
    DIRECTION INPUT ;
    USE SIGNAL ;
    PORT
      LAYER M5 ;
        RECT  1.872 183.516 1.896 183.6 ;
    END
  END c_d[6]
  PIN c_d[70]
    DIRECTION INPUT ;
    USE SIGNAL ;
    PORT
      LAYER M5 ;
        RECT  20.64 183.516 20.664 183.6 ;
    END
  END c_d[70]
  PIN c_d[71]
    DIRECTION INPUT ;
    USE SIGNAL ;
    PORT
      LAYER M5 ;
        RECT  20.928 183.516 20.952 183.6 ;
    END
  END c_d[71]
  PIN c_d[72]
    DIRECTION INPUT ;
    USE SIGNAL ;
    PORT
      LAYER M5 ;
        RECT  21.216 183.516 21.24 183.6 ;
    END
  END c_d[72]
  PIN c_d[73]
    DIRECTION INPUT ;
    USE SIGNAL ;
    PORT
      LAYER M5 ;
        RECT  21.504 183.516 21.528 183.6 ;
    END
  END c_d[73]
  PIN c_d[74]
    DIRECTION INPUT ;
    USE SIGNAL ;
    PORT
      LAYER M5 ;
        RECT  21.792 183.516 21.816 183.6 ;
    END
  END c_d[74]
  PIN c_d[75]
    DIRECTION INPUT ;
    USE SIGNAL ;
    PORT
      LAYER M5 ;
        RECT  22.08 183.516 22.104 183.6 ;
    END
  END c_d[75]
  PIN c_d[76]
    DIRECTION INPUT ;
    USE SIGNAL ;
    PORT
      LAYER M5 ;
        RECT  22.416 183.516 22.44 183.6 ;
    END
  END c_d[76]
  PIN c_d[77]
    DIRECTION INPUT ;
    USE SIGNAL ;
    PORT
      LAYER M5 ;
        RECT  22.704 183.516 22.728 183.6 ;
    END
  END c_d[77]
  PIN c_d[78]
    DIRECTION INPUT ;
    USE SIGNAL ;
    PORT
      LAYER M5 ;
        RECT  22.992 183.516 23.016 183.6 ;
    END
  END c_d[78]
  PIN c_d[79]
    DIRECTION INPUT ;
    USE SIGNAL ;
    PORT
      LAYER M5 ;
        RECT  23.28 183.516 23.304 183.6 ;
    END
  END c_d[79]
  PIN c_d[7]
    DIRECTION INPUT ;
    USE SIGNAL ;
    PORT
      LAYER M5 ;
        RECT  2.208 183.516 2.232 183.6 ;
    END
  END c_d[7]
  PIN c_d[80]
    DIRECTION INPUT ;
    USE SIGNAL ;
    PORT
      LAYER M5 ;
        RECT  23.568 183.516 23.592 183.6 ;
    END
  END c_d[80]
  PIN c_d[81]
    DIRECTION INPUT ;
    USE SIGNAL ;
    PORT
      LAYER M5 ;
        RECT  23.856 183.516 23.88 183.6 ;
    END
  END c_d[81]
  PIN c_d[82]
    DIRECTION INPUT ;
    USE SIGNAL ;
    PORT
      LAYER M5 ;
        RECT  24.144 183.516 24.168 183.6 ;
    END
  END c_d[82]
  PIN c_d[83]
    DIRECTION INPUT ;
    USE SIGNAL ;
    PORT
      LAYER M5 ;
        RECT  24.432 183.516 24.456 183.6 ;
    END
  END c_d[83]
  PIN c_d[84]
    DIRECTION INPUT ;
    USE SIGNAL ;
    PORT
      LAYER M5 ;
        RECT  24.72 183.516 24.744 183.6 ;
    END
  END c_d[84]
  PIN c_d[85]
    DIRECTION INPUT ;
    USE SIGNAL ;
    PORT
      LAYER M5 ;
        RECT  25.008 183.516 25.032 183.6 ;
    END
  END c_d[85]
  PIN c_d[86]
    DIRECTION INPUT ;
    USE SIGNAL ;
    PORT
      LAYER M5 ;
        RECT  25.344 183.516 25.368 183.6 ;
    END
  END c_d[86]
  PIN c_d[87]
    DIRECTION INPUT ;
    USE SIGNAL ;
    PORT
      LAYER M5 ;
        RECT  25.632 183.516 25.656 183.6 ;
    END
  END c_d[87]
  PIN c_d[88]
    DIRECTION INPUT ;
    USE SIGNAL ;
    PORT
      LAYER M5 ;
        RECT  25.92 183.516 25.944 183.6 ;
    END
  END c_d[88]
  PIN c_d[89]
    DIRECTION INPUT ;
    USE SIGNAL ;
    PORT
      LAYER M5 ;
        RECT  26.208 183.516 26.232 183.6 ;
    END
  END c_d[89]
  PIN c_d[8]
    DIRECTION INPUT ;
    USE SIGNAL ;
    PORT
      LAYER M5 ;
        RECT  2.496 183.516 2.52 183.6 ;
    END
  END c_d[8]
  PIN c_d[90]
    DIRECTION INPUT ;
    USE SIGNAL ;
    PORT
      LAYER M5 ;
        RECT  26.496 183.516 26.52 183.6 ;
    END
  END c_d[90]
  PIN c_d[91]
    DIRECTION INPUT ;
    USE SIGNAL ;
    PORT
      LAYER M5 ;
        RECT  26.784 183.516 26.808 183.6 ;
    END
  END c_d[91]
  PIN c_d[92]
    DIRECTION INPUT ;
    USE SIGNAL ;
    PORT
      LAYER M5 ;
        RECT  27.072 183.516 27.096 183.6 ;
    END
  END c_d[92]
  PIN c_d[93]
    DIRECTION INPUT ;
    USE SIGNAL ;
    PORT
      LAYER M5 ;
        RECT  27.36 183.516 27.384 183.6 ;
    END
  END c_d[93]
  PIN c_d[94]
    DIRECTION INPUT ;
    USE SIGNAL ;
    PORT
      LAYER M5 ;
        RECT  27.648 183.516 27.672 183.6 ;
    END
  END c_d[94]
  PIN c_d[95]
    DIRECTION INPUT ;
    USE SIGNAL ;
    PORT
      LAYER M5 ;
        RECT  27.936 183.516 27.96 183.6 ;
    END
  END c_d[95]
  PIN c_d[96]
    DIRECTION INPUT ;
    USE SIGNAL ;
    PORT
      LAYER M7 ;
        RECT  28.224 183.53 28.256 183.6 ;
    END
  END c_d[96]
  PIN c_d[97]
    DIRECTION INPUT ;
    USE SIGNAL ;
    PORT
      LAYER M7 ;
        RECT  28.544 183.53 28.576 183.6 ;
    END
  END c_d[97]
  PIN c_d[98]
    DIRECTION INPUT ;
    USE SIGNAL ;
    PORT
      LAYER M7 ;
        RECT  28.864 183.53 28.896 183.6 ;
    END
  END c_d[98]
  PIN c_d[99]
    DIRECTION INPUT ;
    USE SIGNAL ;
    PORT
      LAYER M7 ;
        RECT  29.12 183.53 29.152 183.6 ;
    END
  END c_d[99]
  PIN c_d[9]
    DIRECTION INPUT ;
    USE SIGNAL ;
    PORT
      LAYER M5 ;
        RECT  2.784 183.516 2.808 183.6 ;
    END
  END c_d[9]
  PIN c_lane[0]
    DIRECTION INPUT ;
    USE SIGNAL ;
    PORT
      LAYER M5 ;
        RECT  75.12 183.516 75.144 183.6 ;
    END
  END c_lane[0]
  PIN c_lane[1]
    DIRECTION INPUT ;
    USE SIGNAL ;
    PORT
      LAYER M5 ;
        RECT  75.408 183.516 75.432 183.6 ;
    END
  END c_lane[1]
  PIN c_lane[2]
    DIRECTION INPUT ;
    USE SIGNAL ;
    PORT
      LAYER M5 ;
        RECT  75.696 183.516 75.72 183.6 ;
    END
  END c_lane[2]
  PIN c_sec[0]
    DIRECTION INPUT ;
    USE SIGNAL ;
    PORT
      LAYER M5 ;
        RECT  75.984 183.516 76.008 183.6 ;
    END
  END c_sec[0]
  PIN c_sec[10]
    DIRECTION INPUT ;
    USE SIGNAL ;
    PORT
      LAYER M5 ;
        RECT  78.912 183.516 78.936 183.6 ;
    END
  END c_sec[10]
  PIN c_sec[11]
    DIRECTION INPUT ;
    USE SIGNAL ;
    PORT
      LAYER M5 ;
        RECT  79.2 183.516 79.224 183.6 ;
    END
  END c_sec[11]
  PIN c_sec[12]
    DIRECTION INPUT ;
    USE SIGNAL ;
    PORT
      LAYER M5 ;
        RECT  79.488 183.516 79.512 183.6 ;
    END
  END c_sec[12]
  PIN c_sec[13]
    DIRECTION INPUT ;
    USE SIGNAL ;
    PORT
      LAYER M5 ;
        RECT  79.776 183.516 79.8 183.6 ;
    END
  END c_sec[13]
  PIN c_sec[14]
    DIRECTION INPUT ;
    USE SIGNAL ;
    PORT
      LAYER M5 ;
        RECT  80.112 183.516 80.136 183.6 ;
    END
  END c_sec[14]
  PIN c_sec[15]
    DIRECTION INPUT ;
    USE SIGNAL ;
    PORT
      LAYER M5 ;
        RECT  80.4 183.516 80.424 183.6 ;
    END
  END c_sec[15]
  PIN c_sec[16]
    DIRECTION INPUT ;
    USE SIGNAL ;
    PORT
      LAYER M5 ;
        RECT  80.688 183.516 80.712 183.6 ;
    END
  END c_sec[16]
  PIN c_sec[17]
    DIRECTION INPUT ;
    USE SIGNAL ;
    PORT
      LAYER M5 ;
        RECT  80.976 183.516 81 183.6 ;
    END
  END c_sec[17]
  PIN c_sec[18]
    DIRECTION INPUT ;
    USE SIGNAL ;
    PORT
      LAYER M5 ;
        RECT  81.264 183.516 81.288 183.6 ;
    END
  END c_sec[18]
  PIN c_sec[19]
    DIRECTION INPUT ;
    USE SIGNAL ;
    PORT
      LAYER M5 ;
        RECT  81.552 183.516 81.576 183.6 ;
    END
  END c_sec[19]
  PIN c_sec[1]
    DIRECTION INPUT ;
    USE SIGNAL ;
    PORT
      LAYER M5 ;
        RECT  76.272 183.516 76.296 183.6 ;
    END
  END c_sec[1]
  PIN c_sec[20]
    DIRECTION INPUT ;
    USE SIGNAL ;
    PORT
      LAYER M5 ;
        RECT  81.84 183.516 81.864 183.6 ;
    END
  END c_sec[20]
  PIN c_sec[21]
    DIRECTION INPUT ;
    USE SIGNAL ;
    PORT
      LAYER M5 ;
        RECT  82.128 183.516 82.152 183.6 ;
    END
  END c_sec[21]
  PIN c_sec[22]
    DIRECTION INPUT ;
    USE SIGNAL ;
    PORT
      LAYER M5 ;
        RECT  82.416 183.516 82.44 183.6 ;
    END
  END c_sec[22]
  PIN c_sec[23]
    DIRECTION INPUT ;
    USE SIGNAL ;
    PORT
      LAYER M5 ;
        RECT  82.704 183.516 82.728 183.6 ;
    END
  END c_sec[23]
  PIN c_sec[2]
    DIRECTION INPUT ;
    USE SIGNAL ;
    PORT
      LAYER M5 ;
        RECT  76.56 183.516 76.584 183.6 ;
    END
  END c_sec[2]
  PIN c_sec[3]
    DIRECTION INPUT ;
    USE SIGNAL ;
    PORT
      LAYER M5 ;
        RECT  76.848 183.516 76.872 183.6 ;
    END
  END c_sec[3]
  PIN c_sec[4]
    DIRECTION INPUT ;
    USE SIGNAL ;
    PORT
      LAYER M5 ;
        RECT  77.184 183.516 77.208 183.6 ;
    END
  END c_sec[4]
  PIN c_sec[5]
    DIRECTION INPUT ;
    USE SIGNAL ;
    PORT
      LAYER M5 ;
        RECT  77.472 183.516 77.496 183.6 ;
    END
  END c_sec[5]
  PIN c_sec[6]
    DIRECTION INPUT ;
    USE SIGNAL ;
    PORT
      LAYER M5 ;
        RECT  77.76 183.516 77.784 183.6 ;
    END
  END c_sec[6]
  PIN c_sec[7]
    DIRECTION INPUT ;
    USE SIGNAL ;
    PORT
      LAYER M5 ;
        RECT  78.048 183.516 78.072 183.6 ;
    END
  END c_sec[7]
  PIN c_sec[8]
    DIRECTION INPUT ;
    USE SIGNAL ;
    PORT
      LAYER M5 ;
        RECT  78.336 183.516 78.36 183.6 ;
    END
  END c_sec[8]
  PIN c_sec[9]
    DIRECTION INPUT ;
    USE SIGNAL ;
    PORT
      LAYER M5 ;
        RECT  78.624 183.516 78.648 183.6 ;
    END
  END c_sec[9]
  PIN c_tag[0]
    DIRECTION INPUT ;
    USE SIGNAL ;
    PORT
      LAYER M5 ;
        RECT  83.04 183.516 83.064 183.6 ;
    END
  END c_tag[0]
  PIN c_tag[1]
    DIRECTION INPUT ;
    USE SIGNAL ;
    PORT
      LAYER M5 ;
        RECT  83.328 183.516 83.352 183.6 ;
    END
  END c_tag[1]
  PIN c_tag[2]
    DIRECTION INPUT ;
    USE SIGNAL ;
    PORT
      LAYER M5 ;
        RECT  83.616 183.516 83.64 183.6 ;
    END
  END c_tag[2]
  PIN c_tag[3]
    DIRECTION INPUT ;
    USE SIGNAL ;
    PORT
      LAYER M5 ;
        RECT  83.904 183.516 83.928 183.6 ;
    END
  END c_tag[3]
  PIN c_tag[4]
    DIRECTION INPUT ;
    USE SIGNAL ;
    PORT
      LAYER M5 ;
        RECT  84.192 183.516 84.216 183.6 ;
    END
  END c_tag[4]
  PIN c_tag[5]
    DIRECTION INPUT ;
    USE SIGNAL ;
    PORT
      LAYER M7 ;
        RECT  84.48 183.53 84.512 183.6 ;
    END
  END c_tag[5]
  PIN c_tag[6]
    DIRECTION INPUT ;
    USE SIGNAL ;
    PORT
      LAYER M7 ;
        RECT  84.8 183.53 84.832 183.6 ;
    END
  END c_tag[6]
  PIN c_tag[7]
    DIRECTION INPUT ;
    USE SIGNAL ;
    PORT
      LAYER M7 ;
        RECT  85.056 183.53 85.088 183.6 ;
    END
  END c_tag[7]
  PIN c_tag[8]
    DIRECTION INPUT ;
    USE SIGNAL ;
    PORT
      LAYER M7 ;
        RECT  85.376 183.53 85.408 183.6 ;
    END
  END c_tag[8]
  PIN c_v
    DIRECTION INPUT ;
    USE SIGNAL ;
    PORT
      LAYER M7 ;
        RECT  85.632 183.53 85.664 183.6 ;
    END
  END c_v
  PIN clk
    DIRECTION INPUT ;
    USE SIGNAL ;
    PORT
      LAYER M4 ;
        RECT  86.316 88.752 86.4 88.776 ;
    END
  END clk
  PIN dn_bad
    DIRECTION INPUT ;
    USE SIGNAL ;
    PORT
      LAYER M5 ;
        RECT  0.192 0 0.216 0.084 ;
    END
  END dn_bad
  PIN dn_v
    DIRECTION INPUT ;
    USE SIGNAL ;
    PORT
      LAYER M5 ;
        RECT  0.48 0 0.504 0.084 ;
    END
  END dn_v
  PIN dp_bad
    DIRECTION OUTPUT ;
    USE SIGNAL ;
    PORT
      LAYER M7 ;
        RECT  85.952 183.53 85.984 183.6 ;
    END
  END dp_bad
  PIN dp_v
    DIRECTION OUTPUT ;
    USE SIGNAL ;
    PORT
      LAYER M7 ;
        RECT  86.208 183.53 86.24 183.6 ;
    END
  END dp_v
  PIN lane[0]
    DIRECTION INPUT ;
    USE SIGNAL ;
    PORT
      LAYER M4 ;
        RECT  86.316 126.672 86.4 126.696 ;
    END
  END lane[0]
  PIN lane[1]
    DIRECTION INPUT ;
    USE SIGNAL ;
    PORT
      LAYER M4 ;
        RECT  86.316 139.968 86.4 139.992 ;
    END
  END lane[1]
  PIN lane[2]
    DIRECTION INPUT ;
    USE SIGNAL ;
    PORT
      LAYER M4 ;
        RECT  86.316 153.312 86.4 153.336 ;
    END
  END lane[2]
  PIN n_d[0]
    DIRECTION OUTPUT ;
    USE SIGNAL ;
    PORT
      LAYER M5 ;
        RECT  0.768 0 0.792 0.084 ;
    END
  END n_d[0]
  PIN n_d[100]
    DIRECTION OUTPUT ;
    USE SIGNAL ;
    PORT
      LAYER M7 ;
        RECT  30.016 0 30.048 0.07 ;
    END
  END n_d[100]
  PIN n_d[101]
    DIRECTION OUTPUT ;
    USE SIGNAL ;
    PORT
      LAYER M7 ;
        RECT  30.336 0 30.368 0.07 ;
    END
  END n_d[101]
  PIN n_d[102]
    DIRECTION OUTPUT ;
    USE SIGNAL ;
    PORT
      LAYER M7 ;
        RECT  30.592 0 30.624 0.07 ;
    END
  END n_d[102]
  PIN n_d[103]
    DIRECTION OUTPUT ;
    USE SIGNAL ;
    PORT
      LAYER M7 ;
        RECT  30.912 0 30.944 0.07 ;
    END
  END n_d[103]
  PIN n_d[104]
    DIRECTION OUTPUT ;
    USE SIGNAL ;
    PORT
      LAYER M7 ;
        RECT  31.168 0 31.2 0.07 ;
    END
  END n_d[104]
  PIN n_d[105]
    DIRECTION OUTPUT ;
    USE SIGNAL ;
    PORT
      LAYER M7 ;
        RECT  31.488 0 31.52 0.07 ;
    END
  END n_d[105]
  PIN n_d[106]
    DIRECTION OUTPUT ;
    USE SIGNAL ;
    PORT
      LAYER M7 ;
        RECT  31.744 0 31.776 0.07 ;
    END
  END n_d[106]
  PIN n_d[107]
    DIRECTION OUTPUT ;
    USE SIGNAL ;
    PORT
      LAYER M7 ;
        RECT  32.064 0 32.096 0.07 ;
    END
  END n_d[107]
  PIN n_d[108]
    DIRECTION OUTPUT ;
    USE SIGNAL ;
    PORT
      LAYER M7 ;
        RECT  32.32 0 32.352 0.07 ;
    END
  END n_d[108]
  PIN n_d[109]
    DIRECTION OUTPUT ;
    USE SIGNAL ;
    PORT
      LAYER M7 ;
        RECT  32.64 0 32.672 0.07 ;
    END
  END n_d[109]
  PIN n_d[10]
    DIRECTION OUTPUT ;
    USE SIGNAL ;
    PORT
      LAYER M5 ;
        RECT  3.648 0 3.672 0.084 ;
    END
  END n_d[10]
  PIN n_d[110]
    DIRECTION OUTPUT ;
    USE SIGNAL ;
    PORT
      LAYER M7 ;
        RECT  32.96 0 32.992 0.07 ;
    END
  END n_d[110]
  PIN n_d[111]
    DIRECTION OUTPUT ;
    USE SIGNAL ;
    PORT
      LAYER M7 ;
        RECT  33.216 0 33.248 0.07 ;
    END
  END n_d[111]
  PIN n_d[112]
    DIRECTION OUTPUT ;
    USE SIGNAL ;
    PORT
      LAYER M7 ;
        RECT  33.536 0 33.568 0.07 ;
    END
  END n_d[112]
  PIN n_d[113]
    DIRECTION OUTPUT ;
    USE SIGNAL ;
    PORT
      LAYER M7 ;
        RECT  33.792 0 33.824 0.07 ;
    END
  END n_d[113]
  PIN n_d[114]
    DIRECTION OUTPUT ;
    USE SIGNAL ;
    PORT
      LAYER M7 ;
        RECT  34.112 0 34.144 0.07 ;
    END
  END n_d[114]
  PIN n_d[115]
    DIRECTION OUTPUT ;
    USE SIGNAL ;
    PORT
      LAYER M7 ;
        RECT  34.368 0 34.4 0.07 ;
    END
  END n_d[115]
  PIN n_d[116]
    DIRECTION OUTPUT ;
    USE SIGNAL ;
    PORT
      LAYER M7 ;
        RECT  34.688 0 34.72 0.07 ;
    END
  END n_d[116]
  PIN n_d[117]
    DIRECTION OUTPUT ;
    USE SIGNAL ;
    PORT
      LAYER M7 ;
        RECT  35.008 0 35.04 0.07 ;
    END
  END n_d[117]
  PIN n_d[118]
    DIRECTION OUTPUT ;
    USE SIGNAL ;
    PORT
      LAYER M7 ;
        RECT  35.264 0 35.296 0.07 ;
    END
  END n_d[118]
  PIN n_d[119]
    DIRECTION OUTPUT ;
    USE SIGNAL ;
    PORT
      LAYER M7 ;
        RECT  35.584 0 35.616 0.07 ;
    END
  END n_d[119]
  PIN n_d[11]
    DIRECTION OUTPUT ;
    USE SIGNAL ;
    PORT
      LAYER M5 ;
        RECT  3.936 0 3.96 0.084 ;
    END
  END n_d[11]
  PIN n_d[120]
    DIRECTION OUTPUT ;
    USE SIGNAL ;
    PORT
      LAYER M7 ;
        RECT  35.84 0 35.872 0.07 ;
    END
  END n_d[120]
  PIN n_d[121]
    DIRECTION OUTPUT ;
    USE SIGNAL ;
    PORT
      LAYER M7 ;
        RECT  36.16 0 36.192 0.07 ;
    END
  END n_d[121]
  PIN n_d[122]
    DIRECTION OUTPUT ;
    USE SIGNAL ;
    PORT
      LAYER M7 ;
        RECT  36.48 0 36.512 0.07 ;
    END
  END n_d[122]
  PIN n_d[123]
    DIRECTION OUTPUT ;
    USE SIGNAL ;
    PORT
      LAYER M7 ;
        RECT  36.736 0 36.768 0.07 ;
    END
  END n_d[123]
  PIN n_d[124]
    DIRECTION OUTPUT ;
    USE SIGNAL ;
    PORT
      LAYER M7 ;
        RECT  37.056 0 37.088 0.07 ;
    END
  END n_d[124]
  PIN n_d[125]
    DIRECTION OUTPUT ;
    USE SIGNAL ;
    PORT
      LAYER M7 ;
        RECT  37.312 0 37.344 0.07 ;
    END
  END n_d[125]
  PIN n_d[126]
    DIRECTION OUTPUT ;
    USE SIGNAL ;
    PORT
      LAYER M5 ;
        RECT  37.632 0 37.656 0.084 ;
    END
  END n_d[126]
  PIN n_d[127]
    DIRECTION OUTPUT ;
    USE SIGNAL ;
    PORT
      LAYER M5 ;
        RECT  37.92 0 37.944 0.084 ;
    END
  END n_d[127]
  PIN n_d[128]
    DIRECTION OUTPUT ;
    USE SIGNAL ;
    PORT
      LAYER M5 ;
        RECT  38.208 0 38.232 0.084 ;
    END
  END n_d[128]
  PIN n_d[129]
    DIRECTION OUTPUT ;
    USE SIGNAL ;
    PORT
      LAYER M5 ;
        RECT  38.496 0 38.52 0.084 ;
    END
  END n_d[129]
  PIN n_d[12]
    DIRECTION OUTPUT ;
    USE SIGNAL ;
    PORT
      LAYER M5 ;
        RECT  4.224 0 4.248 0.084 ;
    END
  END n_d[12]
  PIN n_d[130]
    DIRECTION OUTPUT ;
    USE SIGNAL ;
    PORT
      LAYER M5 ;
        RECT  38.784 0 38.808 0.084 ;
    END
  END n_d[130]
  PIN n_d[131]
    DIRECTION OUTPUT ;
    USE SIGNAL ;
    PORT
      LAYER M5 ;
        RECT  39.072 0 39.096 0.084 ;
    END
  END n_d[131]
  PIN n_d[132]
    DIRECTION OUTPUT ;
    USE SIGNAL ;
    PORT
      LAYER M5 ;
        RECT  39.36 0 39.384 0.084 ;
    END
  END n_d[132]
  PIN n_d[133]
    DIRECTION OUTPUT ;
    USE SIGNAL ;
    PORT
      LAYER M5 ;
        RECT  39.696 0 39.72 0.084 ;
    END
  END n_d[133]
  PIN n_d[134]
    DIRECTION OUTPUT ;
    USE SIGNAL ;
    PORT
      LAYER M5 ;
        RECT  39.984 0 40.008 0.084 ;
    END
  END n_d[134]
  PIN n_d[135]
    DIRECTION OUTPUT ;
    USE SIGNAL ;
    PORT
      LAYER M5 ;
        RECT  40.272 0 40.296 0.084 ;
    END
  END n_d[135]
  PIN n_d[136]
    DIRECTION OUTPUT ;
    USE SIGNAL ;
    PORT
      LAYER M5 ;
        RECT  40.56 0 40.584 0.084 ;
    END
  END n_d[136]
  PIN n_d[137]
    DIRECTION OUTPUT ;
    USE SIGNAL ;
    PORT
      LAYER M5 ;
        RECT  40.848 0 40.872 0.084 ;
    END
  END n_d[137]
  PIN n_d[138]
    DIRECTION OUTPUT ;
    USE SIGNAL ;
    PORT
      LAYER M5 ;
        RECT  41.136 0 41.16 0.084 ;
    END
  END n_d[138]
  PIN n_d[139]
    DIRECTION OUTPUT ;
    USE SIGNAL ;
    PORT
      LAYER M5 ;
        RECT  41.424 0 41.448 0.084 ;
    END
  END n_d[139]
  PIN n_d[13]
    DIRECTION OUTPUT ;
    USE SIGNAL ;
    PORT
      LAYER M5 ;
        RECT  4.512 0 4.536 0.084 ;
    END
  END n_d[13]
  PIN n_d[140]
    DIRECTION OUTPUT ;
    USE SIGNAL ;
    PORT
      LAYER M5 ;
        RECT  41.712 0 41.736 0.084 ;
    END
  END n_d[140]
  PIN n_d[141]
    DIRECTION OUTPUT ;
    USE SIGNAL ;
    PORT
      LAYER M5 ;
        RECT  42 0 42.024 0.084 ;
    END
  END n_d[141]
  PIN n_d[142]
    DIRECTION OUTPUT ;
    USE SIGNAL ;
    PORT
      LAYER M5 ;
        RECT  42.288 0 42.312 0.084 ;
    END
  END n_d[142]
  PIN n_d[143]
    DIRECTION OUTPUT ;
    USE SIGNAL ;
    PORT
      LAYER M5 ;
        RECT  42.672 0 42.696 0.084 ;
    END
  END n_d[143]
  PIN n_d[144]
    DIRECTION OUTPUT ;
    USE SIGNAL ;
    PORT
      LAYER M5 ;
        RECT  42.96 0 42.984 0.084 ;
    END
  END n_d[144]
  PIN n_d[145]
    DIRECTION OUTPUT ;
    USE SIGNAL ;
    PORT
      LAYER M5 ;
        RECT  43.248 0 43.272 0.084 ;
    END
  END n_d[145]
  PIN n_d[146]
    DIRECTION OUTPUT ;
    USE SIGNAL ;
    PORT
      LAYER M5 ;
        RECT  43.536 0 43.56 0.084 ;
    END
  END n_d[146]
  PIN n_d[147]
    DIRECTION OUTPUT ;
    USE SIGNAL ;
    PORT
      LAYER M5 ;
        RECT  43.824 0 43.848 0.084 ;
    END
  END n_d[147]
  PIN n_d[148]
    DIRECTION OUTPUT ;
    USE SIGNAL ;
    PORT
      LAYER M5 ;
        RECT  44.112 0 44.136 0.084 ;
    END
  END n_d[148]
  PIN n_d[149]
    DIRECTION OUTPUT ;
    USE SIGNAL ;
    PORT
      LAYER M5 ;
        RECT  44.4 0 44.424 0.084 ;
    END
  END n_d[149]
  PIN n_d[14]
    DIRECTION OUTPUT ;
    USE SIGNAL ;
    PORT
      LAYER M5 ;
        RECT  4.8 0 4.824 0.084 ;
    END
  END n_d[14]
  PIN n_d[150]
    DIRECTION OUTPUT ;
    USE SIGNAL ;
    PORT
      LAYER M5 ;
        RECT  44.688 0 44.712 0.084 ;
    END
  END n_d[150]
  PIN n_d[151]
    DIRECTION OUTPUT ;
    USE SIGNAL ;
    PORT
      LAYER M5 ;
        RECT  44.976 0 45 0.084 ;
    END
  END n_d[151]
  PIN n_d[152]
    DIRECTION OUTPUT ;
    USE SIGNAL ;
    PORT
      LAYER M5 ;
        RECT  45.264 0 45.288 0.084 ;
    END
  END n_d[152]
  PIN n_d[153]
    DIRECTION OUTPUT ;
    USE SIGNAL ;
    PORT
      LAYER M5 ;
        RECT  45.552 0 45.576 0.084 ;
    END
  END n_d[153]
  PIN n_d[154]
    DIRECTION OUTPUT ;
    USE SIGNAL ;
    PORT
      LAYER M5 ;
        RECT  45.84 0 45.864 0.084 ;
    END
  END n_d[154]
  PIN n_d[155]
    DIRECTION OUTPUT ;
    USE SIGNAL ;
    PORT
      LAYER M5 ;
        RECT  46.128 0 46.152 0.084 ;
    END
  END n_d[155]
  PIN n_d[156]
    DIRECTION OUTPUT ;
    USE SIGNAL ;
    PORT
      LAYER M5 ;
        RECT  46.416 0 46.44 0.084 ;
    END
  END n_d[156]
  PIN n_d[157]
    DIRECTION OUTPUT ;
    USE SIGNAL ;
    PORT
      LAYER M5 ;
        RECT  46.704 0 46.728 0.084 ;
    END
  END n_d[157]
  PIN n_d[158]
    DIRECTION OUTPUT ;
    USE SIGNAL ;
    PORT
      LAYER M7 ;
        RECT  46.976 0 47.008 0.07 ;
    END
  END n_d[158]
  PIN n_d[159]
    DIRECTION OUTPUT ;
    USE SIGNAL ;
    PORT
      LAYER M7 ;
        RECT  47.296 0 47.328 0.07 ;
    END
  END n_d[159]
  PIN n_d[15]
    DIRECTION OUTPUT ;
    USE SIGNAL ;
    PORT
      LAYER M5 ;
        RECT  5.136 0 5.16 0.084 ;
    END
  END n_d[15]
  PIN n_d[160]
    DIRECTION OUTPUT ;
    USE SIGNAL ;
    PORT
      LAYER M7 ;
        RECT  47.552 0 47.584 0.07 ;
    END
  END n_d[160]
  PIN n_d[161]
    DIRECTION OUTPUT ;
    USE SIGNAL ;
    PORT
      LAYER M7 ;
        RECT  47.872 0 47.904 0.07 ;
    END
  END n_d[161]
  PIN n_d[162]
    DIRECTION OUTPUT ;
    USE SIGNAL ;
    PORT
      LAYER M7 ;
        RECT  48.192 0 48.224 0.07 ;
    END
  END n_d[162]
  PIN n_d[163]
    DIRECTION OUTPUT ;
    USE SIGNAL ;
    PORT
      LAYER M7 ;
        RECT  48.448 0 48.48 0.07 ;
    END
  END n_d[163]
  PIN n_d[164]
    DIRECTION OUTPUT ;
    USE SIGNAL ;
    PORT
      LAYER M7 ;
        RECT  48.768 0 48.8 0.07 ;
    END
  END n_d[164]
  PIN n_d[165]
    DIRECTION OUTPUT ;
    USE SIGNAL ;
    PORT
      LAYER M7 ;
        RECT  49.024 0 49.056 0.07 ;
    END
  END n_d[165]
  PIN n_d[166]
    DIRECTION OUTPUT ;
    USE SIGNAL ;
    PORT
      LAYER M7 ;
        RECT  49.344 0 49.376 0.07 ;
    END
  END n_d[166]
  PIN n_d[167]
    DIRECTION OUTPUT ;
    USE SIGNAL ;
    PORT
      LAYER M7 ;
        RECT  49.6 0 49.632 0.07 ;
    END
  END n_d[167]
  PIN n_d[168]
    DIRECTION OUTPUT ;
    USE SIGNAL ;
    PORT
      LAYER M7 ;
        RECT  49.92 0 49.952 0.07 ;
    END
  END n_d[168]
  PIN n_d[169]
    DIRECTION OUTPUT ;
    USE SIGNAL ;
    PORT
      LAYER M7 ;
        RECT  50.24 0 50.272 0.07 ;
    END
  END n_d[169]
  PIN n_d[16]
    DIRECTION OUTPUT ;
    USE SIGNAL ;
    PORT
      LAYER M5 ;
        RECT  5.424 0 5.448 0.084 ;
    END
  END n_d[16]
  PIN n_d[170]
    DIRECTION OUTPUT ;
    USE SIGNAL ;
    PORT
      LAYER M7 ;
        RECT  50.496 0 50.528 0.07 ;
    END
  END n_d[170]
  PIN n_d[171]
    DIRECTION OUTPUT ;
    USE SIGNAL ;
    PORT
      LAYER M7 ;
        RECT  50.816 0 50.848 0.07 ;
    END
  END n_d[171]
  PIN n_d[172]
    DIRECTION OUTPUT ;
    USE SIGNAL ;
    PORT
      LAYER M7 ;
        RECT  51.072 0 51.104 0.07 ;
    END
  END n_d[172]
  PIN n_d[173]
    DIRECTION OUTPUT ;
    USE SIGNAL ;
    PORT
      LAYER M7 ;
        RECT  51.392 0 51.424 0.07 ;
    END
  END n_d[173]
  PIN n_d[174]
    DIRECTION OUTPUT ;
    USE SIGNAL ;
    PORT
      LAYER M7 ;
        RECT  51.648 0 51.68 0.07 ;
    END
  END n_d[174]
  PIN n_d[175]
    DIRECTION OUTPUT ;
    USE SIGNAL ;
    PORT
      LAYER M7 ;
        RECT  51.968 0 52 0.07 ;
    END
  END n_d[175]
  PIN n_d[176]
    DIRECTION OUTPUT ;
    USE SIGNAL ;
    PORT
      LAYER M7 ;
        RECT  52.288 0 52.32 0.07 ;
    END
  END n_d[176]
  PIN n_d[177]
    DIRECTION OUTPUT ;
    USE SIGNAL ;
    PORT
      LAYER M7 ;
        RECT  52.544 0 52.576 0.07 ;
    END
  END n_d[177]
  PIN n_d[178]
    DIRECTION OUTPUT ;
    USE SIGNAL ;
    PORT
      LAYER M7 ;
        RECT  52.864 0 52.896 0.07 ;
    END
  END n_d[178]
  PIN n_d[179]
    DIRECTION OUTPUT ;
    USE SIGNAL ;
    PORT
      LAYER M7 ;
        RECT  53.12 0 53.152 0.07 ;
    END
  END n_d[179]
  PIN n_d[17]
    DIRECTION OUTPUT ;
    USE SIGNAL ;
    PORT
      LAYER M5 ;
        RECT  5.712 0 5.736 0.084 ;
    END
  END n_d[17]
  PIN n_d[180]
    DIRECTION OUTPUT ;
    USE SIGNAL ;
    PORT
      LAYER M7 ;
        RECT  53.44 0 53.472 0.07 ;
    END
  END n_d[180]
  PIN n_d[181]
    DIRECTION OUTPUT ;
    USE SIGNAL ;
    PORT
      LAYER M7 ;
        RECT  53.76 0 53.792 0.07 ;
    END
  END n_d[181]
  PIN n_d[182]
    DIRECTION OUTPUT ;
    USE SIGNAL ;
    PORT
      LAYER M7 ;
        RECT  54.016 0 54.048 0.07 ;
    END
  END n_d[182]
  PIN n_d[183]
    DIRECTION OUTPUT ;
    USE SIGNAL ;
    PORT
      LAYER M7 ;
        RECT  54.336 0 54.368 0.07 ;
    END
  END n_d[183]
  PIN n_d[184]
    DIRECTION OUTPUT ;
    USE SIGNAL ;
    PORT
      LAYER M7 ;
        RECT  54.592 0 54.624 0.07 ;
    END
  END n_d[184]
  PIN n_d[185]
    DIRECTION OUTPUT ;
    USE SIGNAL ;
    PORT
      LAYER M7 ;
        RECT  54.912 0 54.944 0.07 ;
    END
  END n_d[185]
  PIN n_d[186]
    DIRECTION OUTPUT ;
    USE SIGNAL ;
    PORT
      LAYER M7 ;
        RECT  55.168 0 55.2 0.07 ;
    END
  END n_d[186]
  PIN n_d[187]
    DIRECTION OUTPUT ;
    USE SIGNAL ;
    PORT
      LAYER M7 ;
        RECT  55.488 0 55.52 0.07 ;
    END
  END n_d[187]
  PIN n_d[188]
    DIRECTION OUTPUT ;
    USE SIGNAL ;
    PORT
      LAYER M7 ;
        RECT  55.808 0 55.84 0.07 ;
    END
  END n_d[188]
  PIN n_d[189]
    DIRECTION OUTPUT ;
    USE SIGNAL ;
    PORT
      LAYER M7 ;
        RECT  56.064 0 56.096 0.07 ;
    END
  END n_d[189]
  PIN n_d[18]
    DIRECTION OUTPUT ;
    USE SIGNAL ;
    PORT
      LAYER M5 ;
        RECT  6 0 6.024 0.084 ;
    END
  END n_d[18]
  PIN n_d[190]
    DIRECTION OUTPUT ;
    USE SIGNAL ;
    PORT
      LAYER M5 ;
        RECT  56.352 0 56.376 0.084 ;
    END
  END n_d[190]
  PIN n_d[191]
    DIRECTION OUTPUT ;
    USE SIGNAL ;
    PORT
      LAYER M5 ;
        RECT  56.64 0 56.664 0.084 ;
    END
  END n_d[191]
  PIN n_d[192]
    DIRECTION OUTPUT ;
    USE SIGNAL ;
    PORT
      LAYER M5 ;
        RECT  57.024 0 57.048 0.084 ;
    END
  END n_d[192]
  PIN n_d[193]
    DIRECTION OUTPUT ;
    USE SIGNAL ;
    PORT
      LAYER M5 ;
        RECT  57.312 0 57.336 0.084 ;
    END
  END n_d[193]
  PIN n_d[194]
    DIRECTION OUTPUT ;
    USE SIGNAL ;
    PORT
      LAYER M5 ;
        RECT  57.6 0 57.624 0.084 ;
    END
  END n_d[194]
  PIN n_d[195]
    DIRECTION OUTPUT ;
    USE SIGNAL ;
    PORT
      LAYER M5 ;
        RECT  57.888 0 57.912 0.084 ;
    END
  END n_d[195]
  PIN n_d[196]
    DIRECTION OUTPUT ;
    USE SIGNAL ;
    PORT
      LAYER M5 ;
        RECT  58.176 0 58.2 0.084 ;
    END
  END n_d[196]
  PIN n_d[197]
    DIRECTION OUTPUT ;
    USE SIGNAL ;
    PORT
      LAYER M5 ;
        RECT  58.464 0 58.488 0.084 ;
    END
  END n_d[197]
  PIN n_d[198]
    DIRECTION OUTPUT ;
    USE SIGNAL ;
    PORT
      LAYER M5 ;
        RECT  58.752 0 58.776 0.084 ;
    END
  END n_d[198]
  PIN n_d[199]
    DIRECTION OUTPUT ;
    USE SIGNAL ;
    PORT
      LAYER M5 ;
        RECT  59.04 0 59.064 0.084 ;
    END
  END n_d[199]
  PIN n_d[19]
    DIRECTION OUTPUT ;
    USE SIGNAL ;
    PORT
      LAYER M5 ;
        RECT  6.288 0 6.312 0.084 ;
    END
  END n_d[19]
  PIN n_d[1]
    DIRECTION OUTPUT ;
    USE SIGNAL ;
    PORT
      LAYER M5 ;
        RECT  1.056 0 1.08 0.084 ;
    END
  END n_d[1]
  PIN n_d[200]
    DIRECTION OUTPUT ;
    USE SIGNAL ;
    PORT
      LAYER M5 ;
        RECT  59.328 0 59.352 0.084 ;
    END
  END n_d[200]
  PIN n_d[201]
    DIRECTION OUTPUT ;
    USE SIGNAL ;
    PORT
      LAYER M5 ;
        RECT  59.616 0 59.64 0.084 ;
    END
  END n_d[201]
  PIN n_d[202]
    DIRECTION OUTPUT ;
    USE SIGNAL ;
    PORT
      LAYER M5 ;
        RECT  59.904 0 59.928 0.084 ;
    END
  END n_d[202]
  PIN n_d[203]
    DIRECTION OUTPUT ;
    USE SIGNAL ;
    PORT
      LAYER M5 ;
        RECT  60.192 0 60.216 0.084 ;
    END
  END n_d[203]
  PIN n_d[204]
    DIRECTION OUTPUT ;
    USE SIGNAL ;
    PORT
      LAYER M5 ;
        RECT  60.48 0 60.504 0.084 ;
    END
  END n_d[204]
  PIN n_d[205]
    DIRECTION OUTPUT ;
    USE SIGNAL ;
    PORT
      LAYER M5 ;
        RECT  60.768 0 60.792 0.084 ;
    END
  END n_d[205]
  PIN n_d[206]
    DIRECTION OUTPUT ;
    USE SIGNAL ;
    PORT
      LAYER M5 ;
        RECT  61.056 0 61.08 0.084 ;
    END
  END n_d[206]
  PIN n_d[207]
    DIRECTION OUTPUT ;
    USE SIGNAL ;
    PORT
      LAYER M5 ;
        RECT  61.344 0 61.368 0.084 ;
    END
  END n_d[207]
  PIN n_d[208]
    DIRECTION OUTPUT ;
    USE SIGNAL ;
    PORT
      LAYER M5 ;
        RECT  61.632 0 61.656 0.084 ;
    END
  END n_d[208]
  PIN n_d[209]
    DIRECTION OUTPUT ;
    USE SIGNAL ;
    PORT
      LAYER M5 ;
        RECT  61.92 0 61.944 0.084 ;
    END
  END n_d[209]
  PIN n_d[20]
    DIRECTION OUTPUT ;
    USE SIGNAL ;
    PORT
      LAYER M5 ;
        RECT  6.576 0 6.6 0.084 ;
    END
  END n_d[20]
  PIN n_d[210]
    DIRECTION OUTPUT ;
    USE SIGNAL ;
    PORT
      LAYER M5 ;
        RECT  62.208 0 62.232 0.084 ;
    END
  END n_d[210]
  PIN n_d[211]
    DIRECTION OUTPUT ;
    USE SIGNAL ;
    PORT
      LAYER M5 ;
        RECT  62.496 0 62.52 0.084 ;
    END
  END n_d[211]
  PIN n_d[212]
    DIRECTION OUTPUT ;
    USE SIGNAL ;
    PORT
      LAYER M5 ;
        RECT  62.832 0 62.856 0.084 ;
    END
  END n_d[212]
  PIN n_d[213]
    DIRECTION OUTPUT ;
    USE SIGNAL ;
    PORT
      LAYER M5 ;
        RECT  63.12 0 63.144 0.084 ;
    END
  END n_d[213]
  PIN n_d[214]
    DIRECTION OUTPUT ;
    USE SIGNAL ;
    PORT
      LAYER M5 ;
        RECT  63.408 0 63.432 0.084 ;
    END
  END n_d[214]
  PIN n_d[215]
    DIRECTION OUTPUT ;
    USE SIGNAL ;
    PORT
      LAYER M5 ;
        RECT  63.696 0 63.72 0.084 ;
    END
  END n_d[215]
  PIN n_d[216]
    DIRECTION OUTPUT ;
    USE SIGNAL ;
    PORT
      LAYER M5 ;
        RECT  63.984 0 64.008 0.084 ;
    END
  END n_d[216]
  PIN n_d[217]
    DIRECTION OUTPUT ;
    USE SIGNAL ;
    PORT
      LAYER M5 ;
        RECT  64.272 0 64.296 0.084 ;
    END
  END n_d[217]
  PIN n_d[218]
    DIRECTION OUTPUT ;
    USE SIGNAL ;
    PORT
      LAYER M5 ;
        RECT  64.56 0 64.584 0.084 ;
    END
  END n_d[218]
  PIN n_d[219]
    DIRECTION OUTPUT ;
    USE SIGNAL ;
    PORT
      LAYER M5 ;
        RECT  64.848 0 64.872 0.084 ;
    END
  END n_d[219]
  PIN n_d[21]
    DIRECTION OUTPUT ;
    USE SIGNAL ;
    PORT
      LAYER M5 ;
        RECT  6.864 0 6.888 0.084 ;
    END
  END n_d[21]
  PIN n_d[220]
    DIRECTION OUTPUT ;
    USE SIGNAL ;
    PORT
      LAYER M5 ;
        RECT  65.136 0 65.16 0.084 ;
    END
  END n_d[220]
  PIN n_d[221]
    DIRECTION OUTPUT ;
    USE SIGNAL ;
    PORT
      LAYER M5 ;
        RECT  65.424 0 65.448 0.084 ;
    END
  END n_d[221]
  PIN n_d[222]
    DIRECTION OUTPUT ;
    USE SIGNAL ;
    PORT
      LAYER M7 ;
        RECT  65.728 0 65.76 0.07 ;
    END
  END n_d[222]
  PIN n_d[223]
    DIRECTION OUTPUT ;
    USE SIGNAL ;
    PORT
      LAYER M7 ;
        RECT  66.048 0 66.08 0.07 ;
    END
  END n_d[223]
  PIN n_d[224]
    DIRECTION OUTPUT ;
    USE SIGNAL ;
    PORT
      LAYER M7 ;
        RECT  66.304 0 66.336 0.07 ;
    END
  END n_d[224]
  PIN n_d[225]
    DIRECTION OUTPUT ;
    USE SIGNAL ;
    PORT
      LAYER M7 ;
        RECT  66.624 0 66.656 0.07 ;
    END
  END n_d[225]
  PIN n_d[226]
    DIRECTION OUTPUT ;
    USE SIGNAL ;
    PORT
      LAYER M7 ;
        RECT  66.88 0 66.912 0.07 ;
    END
  END n_d[226]
  PIN n_d[227]
    DIRECTION OUTPUT ;
    USE SIGNAL ;
    PORT
      LAYER M7 ;
        RECT  67.2 0 67.232 0.07 ;
    END
  END n_d[227]
  PIN n_d[228]
    DIRECTION OUTPUT ;
    USE SIGNAL ;
    PORT
      LAYER M7 ;
        RECT  67.52 0 67.552 0.07 ;
    END
  END n_d[228]
  PIN n_d[229]
    DIRECTION OUTPUT ;
    USE SIGNAL ;
    PORT
      LAYER M7 ;
        RECT  67.776 0 67.808 0.07 ;
    END
  END n_d[229]
  PIN n_d[22]
    DIRECTION OUTPUT ;
    USE SIGNAL ;
    PORT
      LAYER M5 ;
        RECT  7.152 0 7.176 0.084 ;
    END
  END n_d[22]
  PIN n_d[230]
    DIRECTION OUTPUT ;
    USE SIGNAL ;
    PORT
      LAYER M7 ;
        RECT  68.096 0 68.128 0.07 ;
    END
  END n_d[230]
  PIN n_d[231]
    DIRECTION OUTPUT ;
    USE SIGNAL ;
    PORT
      LAYER M7 ;
        RECT  68.352 0 68.384 0.07 ;
    END
  END n_d[231]
  PIN n_d[232]
    DIRECTION OUTPUT ;
    USE SIGNAL ;
    PORT
      LAYER M7 ;
        RECT  68.672 0 68.704 0.07 ;
    END
  END n_d[232]
  PIN n_d[233]
    DIRECTION OUTPUT ;
    USE SIGNAL ;
    PORT
      LAYER M7 ;
        RECT  68.928 0 68.96 0.07 ;
    END
  END n_d[233]
  PIN n_d[234]
    DIRECTION OUTPUT ;
    USE SIGNAL ;
    PORT
      LAYER M7 ;
        RECT  69.248 0 69.28 0.07 ;
    END
  END n_d[234]
  PIN n_d[235]
    DIRECTION OUTPUT ;
    USE SIGNAL ;
    PORT
      LAYER M7 ;
        RECT  69.632 0 69.664 0.07 ;
    END
  END n_d[235]
  PIN n_d[236]
    DIRECTION OUTPUT ;
    USE SIGNAL ;
    PORT
      LAYER M7 ;
        RECT  69.824 0 69.856 0.07 ;
    END
  END n_d[236]
  PIN n_d[237]
    DIRECTION OUTPUT ;
    USE SIGNAL ;
    PORT
      LAYER M7 ;
        RECT  70.208 0 70.24 0.07 ;
    END
  END n_d[237]
  PIN n_d[238]
    DIRECTION OUTPUT ;
    USE SIGNAL ;
    PORT
      LAYER M7 ;
        RECT  70.4 0 70.432 0.07 ;
    END
  END n_d[238]
  PIN n_d[239]
    DIRECTION OUTPUT ;
    USE SIGNAL ;
    PORT
      LAYER M7 ;
        RECT  70.784 0 70.816 0.07 ;
    END
  END n_d[239]
  PIN n_d[23]
    DIRECTION OUTPUT ;
    USE SIGNAL ;
    PORT
      LAYER M5 ;
        RECT  7.44 0 7.464 0.084 ;
    END
  END n_d[23]
  PIN n_d[240]
    DIRECTION OUTPUT ;
    USE SIGNAL ;
    PORT
      LAYER M7 ;
        RECT  71.104 0 71.136 0.07 ;
    END
  END n_d[240]
  PIN n_d[241]
    DIRECTION OUTPUT ;
    USE SIGNAL ;
    PORT
      LAYER M7 ;
        RECT  71.36 0 71.392 0.07 ;
    END
  END n_d[241]
  PIN n_d[242]
    DIRECTION OUTPUT ;
    USE SIGNAL ;
    PORT
      LAYER M7 ;
        RECT  71.68 0 71.712 0.07 ;
    END
  END n_d[242]
  PIN n_d[243]
    DIRECTION OUTPUT ;
    USE SIGNAL ;
    PORT
      LAYER M7 ;
        RECT  71.936 0 71.968 0.07 ;
    END
  END n_d[243]
  PIN n_d[244]
    DIRECTION OUTPUT ;
    USE SIGNAL ;
    PORT
      LAYER M7 ;
        RECT  72.256 0 72.288 0.07 ;
    END
  END n_d[244]
  PIN n_d[245]
    DIRECTION OUTPUT ;
    USE SIGNAL ;
    PORT
      LAYER M7 ;
        RECT  72.512 0 72.544 0.07 ;
    END
  END n_d[245]
  PIN n_d[246]
    DIRECTION OUTPUT ;
    USE SIGNAL ;
    PORT
      LAYER M7 ;
        RECT  72.832 0 72.864 0.07 ;
    END
  END n_d[246]
  PIN n_d[247]
    DIRECTION OUTPUT ;
    USE SIGNAL ;
    PORT
      LAYER M7 ;
        RECT  73.088 0 73.12 0.07 ;
    END
  END n_d[247]
  PIN n_d[248]
    DIRECTION OUTPUT ;
    USE SIGNAL ;
    PORT
      LAYER M7 ;
        RECT  73.408 0 73.44 0.07 ;
    END
  END n_d[248]
  PIN n_d[249]
    DIRECTION OUTPUT ;
    USE SIGNAL ;
    PORT
      LAYER M7 ;
        RECT  73.664 0 73.696 0.07 ;
    END
  END n_d[249]
  PIN n_d[24]
    DIRECTION OUTPUT ;
    USE SIGNAL ;
    PORT
      LAYER M5 ;
        RECT  7.728 0 7.752 0.084 ;
    END
  END n_d[24]
  PIN n_d[250]
    DIRECTION OUTPUT ;
    USE SIGNAL ;
    PORT
      LAYER M7 ;
        RECT  73.92 0 73.952 0.07 ;
    END
  END n_d[250]
  PIN n_d[251]
    DIRECTION OUTPUT ;
    USE SIGNAL ;
    PORT
      LAYER M7 ;
        RECT  74.24 0 74.272 0.07 ;
    END
  END n_d[251]
  PIN n_d[252]
    DIRECTION OUTPUT ;
    USE SIGNAL ;
    PORT
      LAYER M7 ;
        RECT  74.496 0 74.528 0.07 ;
    END
  END n_d[252]
  PIN n_d[253]
    DIRECTION OUTPUT ;
    USE SIGNAL ;
    PORT
      LAYER M7 ;
        RECT  74.816 0 74.848 0.07 ;
    END
  END n_d[253]
  PIN n_d[254]
    DIRECTION OUTPUT ;
    USE SIGNAL ;
    PORT
      LAYER M5 ;
        RECT  75.12 0 75.144 0.084 ;
    END
  END n_d[254]
  PIN n_d[255]
    DIRECTION OUTPUT ;
    USE SIGNAL ;
    PORT
      LAYER M5 ;
        RECT  75.408 0 75.432 0.084 ;
    END
  END n_d[255]
  PIN n_d[25]
    DIRECTION OUTPUT ;
    USE SIGNAL ;
    PORT
      LAYER M5 ;
        RECT  8.064 0 8.088 0.084 ;
    END
  END n_d[25]
  PIN n_d[26]
    DIRECTION OUTPUT ;
    USE SIGNAL ;
    PORT
      LAYER M5 ;
        RECT  8.352 0 8.376 0.084 ;
    END
  END n_d[26]
  PIN n_d[27]
    DIRECTION OUTPUT ;
    USE SIGNAL ;
    PORT
      LAYER M5 ;
        RECT  8.64 0 8.664 0.084 ;
    END
  END n_d[27]
  PIN n_d[28]
    DIRECTION OUTPUT ;
    USE SIGNAL ;
    PORT
      LAYER M5 ;
        RECT  8.928 0 8.952 0.084 ;
    END
  END n_d[28]
  PIN n_d[29]
    DIRECTION OUTPUT ;
    USE SIGNAL ;
    PORT
      LAYER M5 ;
        RECT  9.216 0 9.24 0.084 ;
    END
  END n_d[29]
  PIN n_d[2]
    DIRECTION OUTPUT ;
    USE SIGNAL ;
    PORT
      LAYER M5 ;
        RECT  1.344 0 1.368 0.084 ;
    END
  END n_d[2]
  PIN n_d[30]
    DIRECTION OUTPUT ;
    USE SIGNAL ;
    PORT
      LAYER M7 ;
        RECT  9.472 0 9.504 0.07 ;
    END
  END n_d[30]
  PIN n_d[31]
    DIRECTION OUTPUT ;
    USE SIGNAL ;
    PORT
      LAYER M7 ;
        RECT  9.792 0 9.824 0.07 ;
    END
  END n_d[31]
  PIN n_d[32]
    DIRECTION OUTPUT ;
    USE SIGNAL ;
    PORT
      LAYER M7 ;
        RECT  10.112 0 10.144 0.07 ;
    END
  END n_d[32]
  PIN n_d[33]
    DIRECTION OUTPUT ;
    USE SIGNAL ;
    PORT
      LAYER M7 ;
        RECT  10.368 0 10.4 0.07 ;
    END
  END n_d[33]
  PIN n_d[34]
    DIRECTION OUTPUT ;
    USE SIGNAL ;
    PORT
      LAYER M7 ;
        RECT  10.688 0 10.72 0.07 ;
    END
  END n_d[34]
  PIN n_d[35]
    DIRECTION OUTPUT ;
    USE SIGNAL ;
    PORT
      LAYER M7 ;
        RECT  10.944 0 10.976 0.07 ;
    END
  END n_d[35]
  PIN n_d[36]
    DIRECTION OUTPUT ;
    USE SIGNAL ;
    PORT
      LAYER M7 ;
        RECT  11.264 0 11.296 0.07 ;
    END
  END n_d[36]
  PIN n_d[37]
    DIRECTION OUTPUT ;
    USE SIGNAL ;
    PORT
      LAYER M7 ;
        RECT  11.648 0 11.68 0.07 ;
    END
  END n_d[37]
  PIN n_d[38]
    DIRECTION OUTPUT ;
    USE SIGNAL ;
    PORT
      LAYER M7 ;
        RECT  11.84 0 11.872 0.07 ;
    END
  END n_d[38]
  PIN n_d[39]
    DIRECTION OUTPUT ;
    USE SIGNAL ;
    PORT
      LAYER M7 ;
        RECT  12.224 0 12.256 0.07 ;
    END
  END n_d[39]
  PIN n_d[3]
    DIRECTION OUTPUT ;
    USE SIGNAL ;
    PORT
      LAYER M5 ;
        RECT  1.632 0 1.656 0.084 ;
    END
  END n_d[3]
  PIN n_d[40]
    DIRECTION OUTPUT ;
    USE SIGNAL ;
    PORT
      LAYER M7 ;
        RECT  12.416 0 12.448 0.07 ;
    END
  END n_d[40]
  PIN n_d[41]
    DIRECTION OUTPUT ;
    USE SIGNAL ;
    PORT
      LAYER M7 ;
        RECT  12.8 0 12.832 0.07 ;
    END
  END n_d[41]
  PIN n_d[42]
    DIRECTION OUTPUT ;
    USE SIGNAL ;
    PORT
      LAYER M7 ;
        RECT  12.992 0 13.024 0.07 ;
    END
  END n_d[42]
  PIN n_d[43]
    DIRECTION OUTPUT ;
    USE SIGNAL ;
    PORT
      LAYER M7 ;
        RECT  13.376 0 13.408 0.07 ;
    END
  END n_d[43]
  PIN n_d[44]
    DIRECTION OUTPUT ;
    USE SIGNAL ;
    PORT
      LAYER M7 ;
        RECT  13.696 0 13.728 0.07 ;
    END
  END n_d[44]
  PIN n_d[45]
    DIRECTION OUTPUT ;
    USE SIGNAL ;
    PORT
      LAYER M7 ;
        RECT  13.952 0 13.984 0.07 ;
    END
  END n_d[45]
  PIN n_d[46]
    DIRECTION OUTPUT ;
    USE SIGNAL ;
    PORT
      LAYER M7 ;
        RECT  14.272 0 14.304 0.07 ;
    END
  END n_d[46]
  PIN n_d[47]
    DIRECTION OUTPUT ;
    USE SIGNAL ;
    PORT
      LAYER M7 ;
        RECT  14.528 0 14.56 0.07 ;
    END
  END n_d[47]
  PIN n_d[48]
    DIRECTION OUTPUT ;
    USE SIGNAL ;
    PORT
      LAYER M7 ;
        RECT  14.848 0 14.88 0.07 ;
    END
  END n_d[48]
  PIN n_d[49]
    DIRECTION OUTPUT ;
    USE SIGNAL ;
    PORT
      LAYER M7 ;
        RECT  15.104 0 15.136 0.07 ;
    END
  END n_d[49]
  PIN n_d[4]
    DIRECTION OUTPUT ;
    USE SIGNAL ;
    PORT
      LAYER M5 ;
        RECT  1.92 0 1.944 0.084 ;
    END
  END n_d[4]
  PIN n_d[50]
    DIRECTION OUTPUT ;
    USE SIGNAL ;
    PORT
      LAYER M7 ;
        RECT  15.424 0 15.456 0.07 ;
    END
  END n_d[50]
  PIN n_d[51]
    DIRECTION OUTPUT ;
    USE SIGNAL ;
    PORT
      LAYER M7 ;
        RECT  15.68 0 15.712 0.07 ;
    END
  END n_d[51]
  PIN n_d[52]
    DIRECTION OUTPUT ;
    USE SIGNAL ;
    PORT
      LAYER M7 ;
        RECT  16 0 16.032 0.07 ;
    END
  END n_d[52]
  PIN n_d[53]
    DIRECTION OUTPUT ;
    USE SIGNAL ;
    PORT
      LAYER M7 ;
        RECT  16.256 0 16.288 0.07 ;
    END
  END n_d[53]
  PIN n_d[54]
    DIRECTION OUTPUT ;
    USE SIGNAL ;
    PORT
      LAYER M7 ;
        RECT  16.576 0 16.608 0.07 ;
    END
  END n_d[54]
  PIN n_d[55]
    DIRECTION OUTPUT ;
    USE SIGNAL ;
    PORT
      LAYER M7 ;
        RECT  16.832 0 16.864 0.07 ;
    END
  END n_d[55]
  PIN n_d[56]
    DIRECTION OUTPUT ;
    USE SIGNAL ;
    PORT
      LAYER M7 ;
        RECT  17.152 0 17.184 0.07 ;
    END
  END n_d[56]
  PIN n_d[57]
    DIRECTION OUTPUT ;
    USE SIGNAL ;
    PORT
      LAYER M7 ;
        RECT  17.408 0 17.44 0.07 ;
    END
  END n_d[57]
  PIN n_d[58]
    DIRECTION OUTPUT ;
    USE SIGNAL ;
    PORT
      LAYER M7 ;
        RECT  17.728 0 17.76 0.07 ;
    END
  END n_d[58]
  PIN n_d[59]
    DIRECTION OUTPUT ;
    USE SIGNAL ;
    PORT
      LAYER M7 ;
        RECT  17.984 0 18.016 0.07 ;
    END
  END n_d[59]
  PIN n_d[5]
    DIRECTION OUTPUT ;
    USE SIGNAL ;
    PORT
      LAYER M5 ;
        RECT  2.208 0 2.232 0.084 ;
    END
  END n_d[5]
  PIN n_d[60]
    DIRECTION OUTPUT ;
    USE SIGNAL ;
    PORT
      LAYER M7 ;
        RECT  18.304 0 18.336 0.07 ;
    END
  END n_d[60]
  PIN n_d[61]
    DIRECTION OUTPUT ;
    USE SIGNAL ;
    PORT
      LAYER M7 ;
        RECT  18.56 0 18.592 0.07 ;
    END
  END n_d[61]
  PIN n_d[62]
    DIRECTION OUTPUT ;
    USE SIGNAL ;
    PORT
      LAYER M5 ;
        RECT  18.864 0 18.888 0.084 ;
    END
  END n_d[62]
  PIN n_d[63]
    DIRECTION OUTPUT ;
    USE SIGNAL ;
    PORT
      LAYER M5 ;
        RECT  19.152 0 19.176 0.084 ;
    END
  END n_d[63]
  PIN n_d[64]
    DIRECTION OUTPUT ;
    USE SIGNAL ;
    PORT
      LAYER M5 ;
        RECT  19.488 0 19.512 0.084 ;
    END
  END n_d[64]
  PIN n_d[65]
    DIRECTION OUTPUT ;
    USE SIGNAL ;
    PORT
      LAYER M5 ;
        RECT  19.776 0 19.8 0.084 ;
    END
  END n_d[65]
  PIN n_d[66]
    DIRECTION OUTPUT ;
    USE SIGNAL ;
    PORT
      LAYER M5 ;
        RECT  20.064 0 20.088 0.084 ;
    END
  END n_d[66]
  PIN n_d[67]
    DIRECTION OUTPUT ;
    USE SIGNAL ;
    PORT
      LAYER M5 ;
        RECT  20.352 0 20.376 0.084 ;
    END
  END n_d[67]
  PIN n_d[68]
    DIRECTION OUTPUT ;
    USE SIGNAL ;
    PORT
      LAYER M5 ;
        RECT  20.64 0 20.664 0.084 ;
    END
  END n_d[68]
  PIN n_d[69]
    DIRECTION OUTPUT ;
    USE SIGNAL ;
    PORT
      LAYER M5 ;
        RECT  20.928 0 20.952 0.084 ;
    END
  END n_d[69]
  PIN n_d[6]
    DIRECTION OUTPUT ;
    USE SIGNAL ;
    PORT
      LAYER M5 ;
        RECT  2.496 0 2.52 0.084 ;
    END
  END n_d[6]
  PIN n_d[70]
    DIRECTION OUTPUT ;
    USE SIGNAL ;
    PORT
      LAYER M5 ;
        RECT  21.216 0 21.24 0.084 ;
    END
  END n_d[70]
  PIN n_d[71]
    DIRECTION OUTPUT ;
    USE SIGNAL ;
    PORT
      LAYER M5 ;
        RECT  21.504 0 21.528 0.084 ;
    END
  END n_d[71]
  PIN n_d[72]
    DIRECTION OUTPUT ;
    USE SIGNAL ;
    PORT
      LAYER M5 ;
        RECT  21.792 0 21.816 0.084 ;
    END
  END n_d[72]
  PIN n_d[73]
    DIRECTION OUTPUT ;
    USE SIGNAL ;
    PORT
      LAYER M5 ;
        RECT  22.08 0 22.104 0.084 ;
    END
  END n_d[73]
  PIN n_d[74]
    DIRECTION OUTPUT ;
    USE SIGNAL ;
    PORT
      LAYER M5 ;
        RECT  22.416 0 22.44 0.084 ;
    END
  END n_d[74]
  PIN n_d[75]
    DIRECTION OUTPUT ;
    USE SIGNAL ;
    PORT
      LAYER M5 ;
        RECT  22.704 0 22.728 0.084 ;
    END
  END n_d[75]
  PIN n_d[76]
    DIRECTION OUTPUT ;
    USE SIGNAL ;
    PORT
      LAYER M5 ;
        RECT  22.992 0 23.016 0.084 ;
    END
  END n_d[76]
  PIN n_d[77]
    DIRECTION OUTPUT ;
    USE SIGNAL ;
    PORT
      LAYER M5 ;
        RECT  23.28 0 23.304 0.084 ;
    END
  END n_d[77]
  PIN n_d[78]
    DIRECTION OUTPUT ;
    USE SIGNAL ;
    PORT
      LAYER M5 ;
        RECT  23.568 0 23.592 0.084 ;
    END
  END n_d[78]
  PIN n_d[79]
    DIRECTION OUTPUT ;
    USE SIGNAL ;
    PORT
      LAYER M5 ;
        RECT  23.856 0 23.88 0.084 ;
    END
  END n_d[79]
  PIN n_d[7]
    DIRECTION OUTPUT ;
    USE SIGNAL ;
    PORT
      LAYER M5 ;
        RECT  2.784 0 2.808 0.084 ;
    END
  END n_d[7]
  PIN n_d[80]
    DIRECTION OUTPUT ;
    USE SIGNAL ;
    PORT
      LAYER M5 ;
        RECT  24.144 0 24.168 0.084 ;
    END
  END n_d[80]
  PIN n_d[81]
    DIRECTION OUTPUT ;
    USE SIGNAL ;
    PORT
      LAYER M5 ;
        RECT  24.432 0 24.456 0.084 ;
    END
  END n_d[81]
  PIN n_d[82]
    DIRECTION OUTPUT ;
    USE SIGNAL ;
    PORT
      LAYER M5 ;
        RECT  24.72 0 24.744 0.084 ;
    END
  END n_d[82]
  PIN n_d[83]
    DIRECTION OUTPUT ;
    USE SIGNAL ;
    PORT
      LAYER M5 ;
        RECT  25.008 0 25.032 0.084 ;
    END
  END n_d[83]
  PIN n_d[84]
    DIRECTION OUTPUT ;
    USE SIGNAL ;
    PORT
      LAYER M5 ;
        RECT  25.344 0 25.368 0.084 ;
    END
  END n_d[84]
  PIN n_d[85]
    DIRECTION OUTPUT ;
    USE SIGNAL ;
    PORT
      LAYER M5 ;
        RECT  25.632 0 25.656 0.084 ;
    END
  END n_d[85]
  PIN n_d[86]
    DIRECTION OUTPUT ;
    USE SIGNAL ;
    PORT
      LAYER M5 ;
        RECT  25.92 0 25.944 0.084 ;
    END
  END n_d[86]
  PIN n_d[87]
    DIRECTION OUTPUT ;
    USE SIGNAL ;
    PORT
      LAYER M5 ;
        RECT  26.208 0 26.232 0.084 ;
    END
  END n_d[87]
  PIN n_d[88]
    DIRECTION OUTPUT ;
    USE SIGNAL ;
    PORT
      LAYER M5 ;
        RECT  26.496 0 26.52 0.084 ;
    END
  END n_d[88]
  PIN n_d[89]
    DIRECTION OUTPUT ;
    USE SIGNAL ;
    PORT
      LAYER M5 ;
        RECT  26.784 0 26.808 0.084 ;
    END
  END n_d[89]
  PIN n_d[8]
    DIRECTION OUTPUT ;
    USE SIGNAL ;
    PORT
      LAYER M5 ;
        RECT  3.072 0 3.096 0.084 ;
    END
  END n_d[8]
  PIN n_d[90]
    DIRECTION OUTPUT ;
    USE SIGNAL ;
    PORT
      LAYER M5 ;
        RECT  27.072 0 27.096 0.084 ;
    END
  END n_d[90]
  PIN n_d[91]
    DIRECTION OUTPUT ;
    USE SIGNAL ;
    PORT
      LAYER M5 ;
        RECT  27.36 0 27.384 0.084 ;
    END
  END n_d[91]
  PIN n_d[92]
    DIRECTION OUTPUT ;
    USE SIGNAL ;
    PORT
      LAYER M5 ;
        RECT  27.648 0 27.672 0.084 ;
    END
  END n_d[92]
  PIN n_d[93]
    DIRECTION OUTPUT ;
    USE SIGNAL ;
    PORT
      LAYER M5 ;
        RECT  27.936 0 27.96 0.084 ;
    END
  END n_d[93]
  PIN n_d[94]
    DIRECTION OUTPUT ;
    USE SIGNAL ;
    PORT
      LAYER M7 ;
        RECT  28.224 0 28.256 0.07 ;
    END
  END n_d[94]
  PIN n_d[95]
    DIRECTION OUTPUT ;
    USE SIGNAL ;
    PORT
      LAYER M7 ;
        RECT  28.608 0 28.64 0.07 ;
    END
  END n_d[95]
  PIN n_d[96]
    DIRECTION OUTPUT ;
    USE SIGNAL ;
    PORT
      LAYER M7 ;
        RECT  28.928 0 28.96 0.07 ;
    END
  END n_d[96]
  PIN n_d[97]
    DIRECTION OUTPUT ;
    USE SIGNAL ;
    PORT
      LAYER M7 ;
        RECT  29.184 0 29.216 0.07 ;
    END
  END n_d[97]
  PIN n_d[98]
    DIRECTION OUTPUT ;
    USE SIGNAL ;
    PORT
      LAYER M7 ;
        RECT  29.44 0 29.472 0.07 ;
    END
  END n_d[98]
  PIN n_d[99]
    DIRECTION OUTPUT ;
    USE SIGNAL ;
    PORT
      LAYER M7 ;
        RECT  29.76 0 29.792 0.07 ;
    END
  END n_d[99]
  PIN n_d[9]
    DIRECTION OUTPUT ;
    USE SIGNAL ;
    PORT
      LAYER M5 ;
        RECT  3.36 0 3.384 0.084 ;
    END
  END n_d[9]
  PIN n_lane[0]
    DIRECTION OUTPUT ;
    USE SIGNAL ;
    PORT
      LAYER M5 ;
        RECT  75.696 0 75.72 0.084 ;
    END
  END n_lane[0]
  PIN n_lane[1]
    DIRECTION OUTPUT ;
    USE SIGNAL ;
    PORT
      LAYER M5 ;
        RECT  75.984 0 76.008 0.084 ;
    END
  END n_lane[1]
  PIN n_lane[2]
    DIRECTION OUTPUT ;
    USE SIGNAL ;
    PORT
      LAYER M5 ;
        RECT  76.272 0 76.296 0.084 ;
    END
  END n_lane[2]
  PIN n_sec[0]
    DIRECTION OUTPUT ;
    USE SIGNAL ;
    PORT
      LAYER M5 ;
        RECT  76.56 0 76.584 0.084 ;
    END
  END n_sec[0]
  PIN n_sec[10]
    DIRECTION OUTPUT ;
    USE SIGNAL ;
    PORT
      LAYER M5 ;
        RECT  79.488 0 79.512 0.084 ;
    END
  END n_sec[10]
  PIN n_sec[11]
    DIRECTION OUTPUT ;
    USE SIGNAL ;
    PORT
      LAYER M5 ;
        RECT  79.776 0 79.8 0.084 ;
    END
  END n_sec[11]
  PIN n_sec[12]
    DIRECTION OUTPUT ;
    USE SIGNAL ;
    PORT
      LAYER M5 ;
        RECT  80.112 0 80.136 0.084 ;
    END
  END n_sec[12]
  PIN n_sec[13]
    DIRECTION OUTPUT ;
    USE SIGNAL ;
    PORT
      LAYER M5 ;
        RECT  80.4 0 80.424 0.084 ;
    END
  END n_sec[13]
  PIN n_sec[14]
    DIRECTION OUTPUT ;
    USE SIGNAL ;
    PORT
      LAYER M5 ;
        RECT  80.688 0 80.712 0.084 ;
    END
  END n_sec[14]
  PIN n_sec[15]
    DIRECTION OUTPUT ;
    USE SIGNAL ;
    PORT
      LAYER M5 ;
        RECT  80.976 0 81 0.084 ;
    END
  END n_sec[15]
  PIN n_sec[16]
    DIRECTION OUTPUT ;
    USE SIGNAL ;
    PORT
      LAYER M5 ;
        RECT  81.264 0 81.288 0.084 ;
    END
  END n_sec[16]
  PIN n_sec[17]
    DIRECTION OUTPUT ;
    USE SIGNAL ;
    PORT
      LAYER M5 ;
        RECT  81.552 0 81.576 0.084 ;
    END
  END n_sec[17]
  PIN n_sec[18]
    DIRECTION OUTPUT ;
    USE SIGNAL ;
    PORT
      LAYER M5 ;
        RECT  81.84 0 81.864 0.084 ;
    END
  END n_sec[18]
  PIN n_sec[19]
    DIRECTION OUTPUT ;
    USE SIGNAL ;
    PORT
      LAYER M5 ;
        RECT  82.128 0 82.152 0.084 ;
    END
  END n_sec[19]
  PIN n_sec[1]
    DIRECTION OUTPUT ;
    USE SIGNAL ;
    PORT
      LAYER M5 ;
        RECT  76.848 0 76.872 0.084 ;
    END
  END n_sec[1]
  PIN n_sec[20]
    DIRECTION OUTPUT ;
    USE SIGNAL ;
    PORT
      LAYER M5 ;
        RECT  82.416 0 82.44 0.084 ;
    END
  END n_sec[20]
  PIN n_sec[21]
    DIRECTION OUTPUT ;
    USE SIGNAL ;
    PORT
      LAYER M5 ;
        RECT  82.704 0 82.728 0.084 ;
    END
  END n_sec[21]
  PIN n_sec[22]
    DIRECTION OUTPUT ;
    USE SIGNAL ;
    PORT
      LAYER M5 ;
        RECT  83.04 0 83.064 0.084 ;
    END
  END n_sec[22]
  PIN n_sec[23]
    DIRECTION OUTPUT ;
    USE SIGNAL ;
    PORT
      LAYER M5 ;
        RECT  83.328 0 83.352 0.084 ;
    END
  END n_sec[23]
  PIN n_sec[2]
    DIRECTION OUTPUT ;
    USE SIGNAL ;
    PORT
      LAYER M5 ;
        RECT  77.184 0 77.208 0.084 ;
    END
  END n_sec[2]
  PIN n_sec[3]
    DIRECTION OUTPUT ;
    USE SIGNAL ;
    PORT
      LAYER M5 ;
        RECT  77.472 0 77.496 0.084 ;
    END
  END n_sec[3]
  PIN n_sec[4]
    DIRECTION OUTPUT ;
    USE SIGNAL ;
    PORT
      LAYER M5 ;
        RECT  77.76 0 77.784 0.084 ;
    END
  END n_sec[4]
  PIN n_sec[5]
    DIRECTION OUTPUT ;
    USE SIGNAL ;
    PORT
      LAYER M5 ;
        RECT  78.048 0 78.072 0.084 ;
    END
  END n_sec[5]
  PIN n_sec[6]
    DIRECTION OUTPUT ;
    USE SIGNAL ;
    PORT
      LAYER M5 ;
        RECT  78.336 0 78.36 0.084 ;
    END
  END n_sec[6]
  PIN n_sec[7]
    DIRECTION OUTPUT ;
    USE SIGNAL ;
    PORT
      LAYER M5 ;
        RECT  78.624 0 78.648 0.084 ;
    END
  END n_sec[7]
  PIN n_sec[8]
    DIRECTION OUTPUT ;
    USE SIGNAL ;
    PORT
      LAYER M5 ;
        RECT  78.912 0 78.936 0.084 ;
    END
  END n_sec[8]
  PIN n_sec[9]
    DIRECTION OUTPUT ;
    USE SIGNAL ;
    PORT
      LAYER M5 ;
        RECT  79.2 0 79.224 0.084 ;
    END
  END n_sec[9]
  PIN n_tag[0]
    DIRECTION OUTPUT ;
    USE SIGNAL ;
    PORT
      LAYER M5 ;
        RECT  83.616 0 83.64 0.084 ;
    END
  END n_tag[0]
  PIN n_tag[1]
    DIRECTION OUTPUT ;
    USE SIGNAL ;
    PORT
      LAYER M5 ;
        RECT  83.904 0 83.928 0.084 ;
    END
  END n_tag[1]
  PIN n_tag[2]
    DIRECTION OUTPUT ;
    USE SIGNAL ;
    PORT
      LAYER M5 ;
        RECT  84.192 0 84.216 0.084 ;
    END
  END n_tag[2]
  PIN n_tag[3]
    DIRECTION OUTPUT ;
    USE SIGNAL ;
    PORT
      LAYER M7 ;
        RECT  84.48 0 84.512 0.07 ;
    END
  END n_tag[3]
  PIN n_tag[4]
    DIRECTION OUTPUT ;
    USE SIGNAL ;
    PORT
      LAYER M7 ;
        RECT  84.864 0 84.896 0.07 ;
    END
  END n_tag[4]
  PIN n_tag[5]
    DIRECTION OUTPUT ;
    USE SIGNAL ;
    PORT
      LAYER M7 ;
        RECT  85.056 0 85.088 0.07 ;
    END
  END n_tag[5]
  PIN n_tag[6]
    DIRECTION OUTPUT ;
    USE SIGNAL ;
    PORT
      LAYER M7 ;
        RECT  85.44 0 85.472 0.07 ;
    END
  END n_tag[6]
  PIN n_tag[7]
    DIRECTION OUTPUT ;
    USE SIGNAL ;
    PORT
      LAYER M7 ;
        RECT  85.632 0 85.664 0.07 ;
    END
  END n_tag[7]
  PIN n_tag[8]
    DIRECTION OUTPUT ;
    USE SIGNAL ;
    PORT
      LAYER M7 ;
        RECT  86.016 0 86.048 0.07 ;
    END
  END n_tag[8]
  PIN n_v
    DIRECTION OUTPUT ;
    USE SIGNAL ;
    PORT
      LAYER M7 ;
        RECT  86.208 0 86.24 0.07 ;
    END
  END n_v
  PIN rst_n
    DIRECTION INPUT ;
    USE SIGNAL ;
    PORT
      LAYER M4 ;
        RECT  86.316 94.224 86.4 94.248 ;
    END
  END rst_n
  PIN w_data[0]
    DIRECTION OUTPUT ;
    USE SIGNAL ;
    PORT
      LAYER M5 ;
        RECT  0.144 0 0.168 0.084 ;
    END
  END w_data[0]
  PIN w_data[100]
    DIRECTION OUTPUT ;
    USE SIGNAL ;
    PORT
      LAYER M7 ;
        RECT  28.864 0 28.896 0.07 ;
    END
  END w_data[100]
  PIN w_data[101]
    DIRECTION OUTPUT ;
    USE SIGNAL ;
    PORT
      LAYER M7 ;
        RECT  29.12 0 29.152 0.07 ;
    END
  END w_data[101]
  PIN w_data[102]
    DIRECTION OUTPUT ;
    USE SIGNAL ;
    PORT
      LAYER M7 ;
        RECT  29.376 0 29.408 0.07 ;
    END
  END w_data[102]
  PIN w_data[103]
    DIRECTION OUTPUT ;
    USE SIGNAL ;
    PORT
      LAYER M7 ;
        RECT  29.696 0 29.728 0.07 ;
    END
  END w_data[103]
  PIN w_data[104]
    DIRECTION OUTPUT ;
    USE SIGNAL ;
    PORT
      LAYER M7 ;
        RECT  29.952 0 29.984 0.07 ;
    END
  END w_data[104]
  PIN w_data[105]
    DIRECTION OUTPUT ;
    USE SIGNAL ;
    PORT
      LAYER M7 ;
        RECT  30.272 0 30.304 0.07 ;
    END
  END w_data[105]
  PIN w_data[106]
    DIRECTION OUTPUT ;
    USE SIGNAL ;
    PORT
      LAYER M7 ;
        RECT  30.528 0 30.56 0.07 ;
    END
  END w_data[106]
  PIN w_data[107]
    DIRECTION OUTPUT ;
    USE SIGNAL ;
    PORT
      LAYER M7 ;
        RECT  30.848 0 30.88 0.07 ;
    END
  END w_data[107]
  PIN w_data[108]
    DIRECTION OUTPUT ;
    USE SIGNAL ;
    PORT
      LAYER M7 ;
        RECT  31.104 0 31.136 0.07 ;
    END
  END w_data[108]
  PIN w_data[109]
    DIRECTION OUTPUT ;
    USE SIGNAL ;
    PORT
      LAYER M7 ;
        RECT  31.424 0 31.456 0.07 ;
    END
  END w_data[109]
  PIN w_data[10]
    DIRECTION OUTPUT ;
    USE SIGNAL ;
    PORT
      LAYER M5 ;
        RECT  3.024 0 3.048 0.084 ;
    END
  END w_data[10]
  PIN w_data[110]
    DIRECTION OUTPUT ;
    USE SIGNAL ;
    PORT
      LAYER M7 ;
        RECT  31.68 0 31.712 0.07 ;
    END
  END w_data[110]
  PIN w_data[111]
    DIRECTION OUTPUT ;
    USE SIGNAL ;
    PORT
      LAYER M7 ;
        RECT  32 0 32.032 0.07 ;
    END
  END w_data[111]
  PIN w_data[112]
    DIRECTION OUTPUT ;
    USE SIGNAL ;
    PORT
      LAYER M7 ;
        RECT  32.256 0 32.288 0.07 ;
    END
  END w_data[112]
  PIN w_data[113]
    DIRECTION OUTPUT ;
    USE SIGNAL ;
    PORT
      LAYER M7 ;
        RECT  32.576 0 32.608 0.07 ;
    END
  END w_data[113]
  PIN w_data[114]
    DIRECTION OUTPUT ;
    USE SIGNAL ;
    PORT
      LAYER M7 ;
        RECT  32.832 0 32.864 0.07 ;
    END
  END w_data[114]
  PIN w_data[115]
    DIRECTION OUTPUT ;
    USE SIGNAL ;
    PORT
      LAYER M7 ;
        RECT  33.152 0 33.184 0.07 ;
    END
  END w_data[115]
  PIN w_data[116]
    DIRECTION OUTPUT ;
    USE SIGNAL ;
    PORT
      LAYER M7 ;
        RECT  33.408 0 33.44 0.07 ;
    END
  END w_data[116]
  PIN w_data[117]
    DIRECTION OUTPUT ;
    USE SIGNAL ;
    PORT
      LAYER M7 ;
        RECT  33.728 0 33.76 0.07 ;
    END
  END w_data[117]
  PIN w_data[118]
    DIRECTION OUTPUT ;
    USE SIGNAL ;
    PORT
      LAYER M7 ;
        RECT  33.984 0 34.016 0.07 ;
    END
  END w_data[118]
  PIN w_data[119]
    DIRECTION OUTPUT ;
    USE SIGNAL ;
    PORT
      LAYER M7 ;
        RECT  34.304 0 34.336 0.07 ;
    END
  END w_data[119]
  PIN w_data[11]
    DIRECTION OUTPUT ;
    USE SIGNAL ;
    PORT
      LAYER M5 ;
        RECT  3.312 0 3.336 0.084 ;
    END
  END w_data[11]
  PIN w_data[120]
    DIRECTION OUTPUT ;
    USE SIGNAL ;
    PORT
      LAYER M7 ;
        RECT  34.56 0 34.592 0.07 ;
    END
  END w_data[120]
  PIN w_data[121]
    DIRECTION OUTPUT ;
    USE SIGNAL ;
    PORT
      LAYER M7 ;
        RECT  34.88 0 34.912 0.07 ;
    END
  END w_data[121]
  PIN w_data[122]
    DIRECTION OUTPUT ;
    USE SIGNAL ;
    PORT
      LAYER M7 ;
        RECT  35.136 0 35.168 0.07 ;
    END
  END w_data[122]
  PIN w_data[123]
    DIRECTION OUTPUT ;
    USE SIGNAL ;
    PORT
      LAYER M7 ;
        RECT  35.456 0 35.488 0.07 ;
    END
  END w_data[123]
  PIN w_data[124]
    DIRECTION OUTPUT ;
    USE SIGNAL ;
    PORT
      LAYER M7 ;
        RECT  35.712 0 35.744 0.07 ;
    END
  END w_data[124]
  PIN w_data[125]
    DIRECTION OUTPUT ;
    USE SIGNAL ;
    PORT
      LAYER M7 ;
        RECT  36.032 0 36.064 0.07 ;
    END
  END w_data[125]
  PIN w_data[126]
    DIRECTION OUTPUT ;
    USE SIGNAL ;
    PORT
      LAYER M7 ;
        RECT  36.288 0 36.32 0.07 ;
    END
  END w_data[126]
  PIN w_data[127]
    DIRECTION OUTPUT ;
    USE SIGNAL ;
    PORT
      LAYER M7 ;
        RECT  36.608 0 36.64 0.07 ;
    END
  END w_data[127]
  PIN w_data[128]
    DIRECTION OUTPUT ;
    USE SIGNAL ;
    PORT
      LAYER M5 ;
        RECT  36.864 0 36.888 0.084 ;
    END
  END w_data[128]
  PIN w_data[129]
    DIRECTION OUTPUT ;
    USE SIGNAL ;
    PORT
      LAYER M5 ;
        RECT  37.152 0 37.176 0.084 ;
    END
  END w_data[129]
  PIN w_data[12]
    DIRECTION OUTPUT ;
    USE SIGNAL ;
    PORT
      LAYER M5 ;
        RECT  3.6 0 3.624 0.084 ;
    END
  END w_data[12]
  PIN w_data[130]
    DIRECTION OUTPUT ;
    USE SIGNAL ;
    PORT
      LAYER M5 ;
        RECT  37.44 0 37.464 0.084 ;
    END
  END w_data[130]
  PIN w_data[131]
    DIRECTION OUTPUT ;
    USE SIGNAL ;
    PORT
      LAYER M5 ;
        RECT  37.728 0 37.752 0.084 ;
    END
  END w_data[131]
  PIN w_data[132]
    DIRECTION OUTPUT ;
    USE SIGNAL ;
    PORT
      LAYER M5 ;
        RECT  38.016 0 38.04 0.084 ;
    END
  END w_data[132]
  PIN w_data[133]
    DIRECTION OUTPUT ;
    USE SIGNAL ;
    PORT
      LAYER M5 ;
        RECT  38.304 0 38.328 0.084 ;
    END
  END w_data[133]
  PIN w_data[134]
    DIRECTION OUTPUT ;
    USE SIGNAL ;
    PORT
      LAYER M5 ;
        RECT  38.592 0 38.616 0.084 ;
    END
  END w_data[134]
  PIN w_data[135]
    DIRECTION OUTPUT ;
    USE SIGNAL ;
    PORT
      LAYER M5 ;
        RECT  38.88 0 38.904 0.084 ;
    END
  END w_data[135]
  PIN w_data[136]
    DIRECTION OUTPUT ;
    USE SIGNAL ;
    PORT
      LAYER M5 ;
        RECT  39.168 0 39.192 0.084 ;
    END
  END w_data[136]
  PIN w_data[137]
    DIRECTION OUTPUT ;
    USE SIGNAL ;
    PORT
      LAYER M5 ;
        RECT  39.456 0 39.48 0.084 ;
    END
  END w_data[137]
  PIN w_data[138]
    DIRECTION OUTPUT ;
    USE SIGNAL ;
    PORT
      LAYER M5 ;
        RECT  39.744 0 39.768 0.084 ;
    END
  END w_data[138]
  PIN w_data[139]
    DIRECTION OUTPUT ;
    USE SIGNAL ;
    PORT
      LAYER M5 ;
        RECT  40.032 0 40.056 0.084 ;
    END
  END w_data[139]
  PIN w_data[13]
    DIRECTION OUTPUT ;
    USE SIGNAL ;
    PORT
      LAYER M5 ;
        RECT  3.84 0 3.864 0.084 ;
    END
  END w_data[13]
  PIN w_data[140]
    DIRECTION OUTPUT ;
    USE SIGNAL ;
    PORT
      LAYER M5 ;
        RECT  40.32 0 40.344 0.084 ;
    END
  END w_data[140]
  PIN w_data[141]
    DIRECTION OUTPUT ;
    USE SIGNAL ;
    PORT
      LAYER M5 ;
        RECT  40.608 0 40.632 0.084 ;
    END
  END w_data[141]
  PIN w_data[142]
    DIRECTION OUTPUT ;
    USE SIGNAL ;
    PORT
      LAYER M5 ;
        RECT  40.896 0 40.92 0.084 ;
    END
  END w_data[142]
  PIN w_data[143]
    DIRECTION OUTPUT ;
    USE SIGNAL ;
    PORT
      LAYER M5 ;
        RECT  41.184 0 41.208 0.084 ;
    END
  END w_data[143]
  PIN w_data[144]
    DIRECTION OUTPUT ;
    USE SIGNAL ;
    PORT
      LAYER M5 ;
        RECT  41.472 0 41.496 0.084 ;
    END
  END w_data[144]
  PIN w_data[145]
    DIRECTION OUTPUT ;
    USE SIGNAL ;
    PORT
      LAYER M5 ;
        RECT  41.76 0 41.784 0.084 ;
    END
  END w_data[145]
  PIN w_data[146]
    DIRECTION OUTPUT ;
    USE SIGNAL ;
    PORT
      LAYER M5 ;
        RECT  42.048 0 42.072 0.084 ;
    END
  END w_data[146]
  PIN w_data[147]
    DIRECTION OUTPUT ;
    USE SIGNAL ;
    PORT
      LAYER M5 ;
        RECT  42.336 0 42.36 0.084 ;
    END
  END w_data[147]
  PIN w_data[148]
    DIRECTION OUTPUT ;
    USE SIGNAL ;
    PORT
      LAYER M5 ;
        RECT  42.624 0 42.648 0.084 ;
    END
  END w_data[148]
  PIN w_data[149]
    DIRECTION OUTPUT ;
    USE SIGNAL ;
    PORT
      LAYER M5 ;
        RECT  42.912 0 42.936 0.084 ;
    END
  END w_data[149]
  PIN w_data[14]
    DIRECTION OUTPUT ;
    USE SIGNAL ;
    PORT
      LAYER M5 ;
        RECT  4.128 0 4.152 0.084 ;
    END
  END w_data[14]
  PIN w_data[150]
    DIRECTION OUTPUT ;
    USE SIGNAL ;
    PORT
      LAYER M5 ;
        RECT  43.2 0 43.224 0.084 ;
    END
  END w_data[150]
  PIN w_data[151]
    DIRECTION OUTPUT ;
    USE SIGNAL ;
    PORT
      LAYER M5 ;
        RECT  43.488 0 43.512 0.084 ;
    END
  END w_data[151]
  PIN w_data[152]
    DIRECTION OUTPUT ;
    USE SIGNAL ;
    PORT
      LAYER M5 ;
        RECT  43.776 0 43.8 0.084 ;
    END
  END w_data[152]
  PIN w_data[153]
    DIRECTION OUTPUT ;
    USE SIGNAL ;
    PORT
      LAYER M5 ;
        RECT  44.064 0 44.088 0.084 ;
    END
  END w_data[153]
  PIN w_data[154]
    DIRECTION OUTPUT ;
    USE SIGNAL ;
    PORT
      LAYER M5 ;
        RECT  44.352 0 44.376 0.084 ;
    END
  END w_data[154]
  PIN w_data[155]
    DIRECTION OUTPUT ;
    USE SIGNAL ;
    PORT
      LAYER M5 ;
        RECT  44.64 0 44.664 0.084 ;
    END
  END w_data[155]
  PIN w_data[156]
    DIRECTION OUTPUT ;
    USE SIGNAL ;
    PORT
      LAYER M5 ;
        RECT  44.928 0 44.952 0.084 ;
    END
  END w_data[156]
  PIN w_data[157]
    DIRECTION OUTPUT ;
    USE SIGNAL ;
    PORT
      LAYER M5 ;
        RECT  45.216 0 45.24 0.084 ;
    END
  END w_data[157]
  PIN w_data[158]
    DIRECTION OUTPUT ;
    USE SIGNAL ;
    PORT
      LAYER M5 ;
        RECT  45.504 0 45.528 0.084 ;
    END
  END w_data[158]
  PIN w_data[159]
    DIRECTION OUTPUT ;
    USE SIGNAL ;
    PORT
      LAYER M5 ;
        RECT  45.792 0 45.816 0.084 ;
    END
  END w_data[159]
  PIN w_data[15]
    DIRECTION OUTPUT ;
    USE SIGNAL ;
    PORT
      LAYER M5 ;
        RECT  4.416 0 4.44 0.084 ;
    END
  END w_data[15]
  PIN w_data[160]
    DIRECTION OUTPUT ;
    USE SIGNAL ;
    PORT
      LAYER M7 ;
        RECT  46.08 0 46.112 0.07 ;
    END
  END w_data[160]
  PIN w_data[161]
    DIRECTION OUTPUT ;
    USE SIGNAL ;
    PORT
      LAYER M7 ;
        RECT  46.336 0 46.368 0.07 ;
    END
  END w_data[161]
  PIN w_data[162]
    DIRECTION OUTPUT ;
    USE SIGNAL ;
    PORT
      LAYER M7 ;
        RECT  46.656 0 46.688 0.07 ;
    END
  END w_data[162]
  PIN w_data[163]
    DIRECTION OUTPUT ;
    USE SIGNAL ;
    PORT
      LAYER M7 ;
        RECT  46.912 0 46.944 0.07 ;
    END
  END w_data[163]
  PIN w_data[164]
    DIRECTION OUTPUT ;
    USE SIGNAL ;
    PORT
      LAYER M7 ;
        RECT  47.232 0 47.264 0.07 ;
    END
  END w_data[164]
  PIN w_data[165]
    DIRECTION OUTPUT ;
    USE SIGNAL ;
    PORT
      LAYER M7 ;
        RECT  47.488 0 47.52 0.07 ;
    END
  END w_data[165]
  PIN w_data[166]
    DIRECTION OUTPUT ;
    USE SIGNAL ;
    PORT
      LAYER M7 ;
        RECT  47.808 0 47.84 0.07 ;
    END
  END w_data[166]
  PIN w_data[167]
    DIRECTION OUTPUT ;
    USE SIGNAL ;
    PORT
      LAYER M7 ;
        RECT  48.064 0 48.096 0.07 ;
    END
  END w_data[167]
  PIN w_data[168]
    DIRECTION OUTPUT ;
    USE SIGNAL ;
    PORT
      LAYER M7 ;
        RECT  48.32 0 48.352 0.07 ;
    END
  END w_data[168]
  PIN w_data[169]
    DIRECTION OUTPUT ;
    USE SIGNAL ;
    PORT
      LAYER M7 ;
        RECT  48.64 0 48.672 0.07 ;
    END
  END w_data[169]
  PIN w_data[16]
    DIRECTION OUTPUT ;
    USE SIGNAL ;
    PORT
      LAYER M5 ;
        RECT  4.704 0 4.728 0.084 ;
    END
  END w_data[16]
  PIN w_data[170]
    DIRECTION OUTPUT ;
    USE SIGNAL ;
    PORT
      LAYER M7 ;
        RECT  48.896 0 48.928 0.07 ;
    END
  END w_data[170]
  PIN w_data[171]
    DIRECTION OUTPUT ;
    USE SIGNAL ;
    PORT
      LAYER M7 ;
        RECT  49.216 0 49.248 0.07 ;
    END
  END w_data[171]
  PIN w_data[172]
    DIRECTION OUTPUT ;
    USE SIGNAL ;
    PORT
      LAYER M7 ;
        RECT  49.472 0 49.504 0.07 ;
    END
  END w_data[172]
  PIN w_data[173]
    DIRECTION OUTPUT ;
    USE SIGNAL ;
    PORT
      LAYER M7 ;
        RECT  49.792 0 49.824 0.07 ;
    END
  END w_data[173]
  PIN w_data[174]
    DIRECTION OUTPUT ;
    USE SIGNAL ;
    PORT
      LAYER M7 ;
        RECT  50.048 0 50.08 0.07 ;
    END
  END w_data[174]
  PIN w_data[175]
    DIRECTION OUTPUT ;
    USE SIGNAL ;
    PORT
      LAYER M7 ;
        RECT  50.368 0 50.4 0.07 ;
    END
  END w_data[175]
  PIN w_data[176]
    DIRECTION OUTPUT ;
    USE SIGNAL ;
    PORT
      LAYER M7 ;
        RECT  50.624 0 50.656 0.07 ;
    END
  END w_data[176]
  PIN w_data[177]
    DIRECTION OUTPUT ;
    USE SIGNAL ;
    PORT
      LAYER M7 ;
        RECT  50.944 0 50.976 0.07 ;
    END
  END w_data[177]
  PIN w_data[178]
    DIRECTION OUTPUT ;
    USE SIGNAL ;
    PORT
      LAYER M7 ;
        RECT  51.2 0 51.232 0.07 ;
    END
  END w_data[178]
  PIN w_data[179]
    DIRECTION OUTPUT ;
    USE SIGNAL ;
    PORT
      LAYER M7 ;
        RECT  51.52 0 51.552 0.07 ;
    END
  END w_data[179]
  PIN w_data[17]
    DIRECTION OUTPUT ;
    USE SIGNAL ;
    PORT
      LAYER M5 ;
        RECT  4.992 0 5.016 0.084 ;
    END
  END w_data[17]
  PIN w_data[180]
    DIRECTION OUTPUT ;
    USE SIGNAL ;
    PORT
      LAYER M7 ;
        RECT  51.776 0 51.808 0.07 ;
    END
  END w_data[180]
  PIN w_data[181]
    DIRECTION OUTPUT ;
    USE SIGNAL ;
    PORT
      LAYER M7 ;
        RECT  52.096 0 52.128 0.07 ;
    END
  END w_data[181]
  PIN w_data[182]
    DIRECTION OUTPUT ;
    USE SIGNAL ;
    PORT
      LAYER M7 ;
        RECT  52.352 0 52.384 0.07 ;
    END
  END w_data[182]
  PIN w_data[183]
    DIRECTION OUTPUT ;
    USE SIGNAL ;
    PORT
      LAYER M7 ;
        RECT  52.672 0 52.704 0.07 ;
    END
  END w_data[183]
  PIN w_data[184]
    DIRECTION OUTPUT ;
    USE SIGNAL ;
    PORT
      LAYER M7 ;
        RECT  52.928 0 52.96 0.07 ;
    END
  END w_data[184]
  PIN w_data[185]
    DIRECTION OUTPUT ;
    USE SIGNAL ;
    PORT
      LAYER M7 ;
        RECT  53.248 0 53.28 0.07 ;
    END
  END w_data[185]
  PIN w_data[186]
    DIRECTION OUTPUT ;
    USE SIGNAL ;
    PORT
      LAYER M7 ;
        RECT  53.504 0 53.536 0.07 ;
    END
  END w_data[186]
  PIN w_data[187]
    DIRECTION OUTPUT ;
    USE SIGNAL ;
    PORT
      LAYER M7 ;
        RECT  53.824 0 53.856 0.07 ;
    END
  END w_data[187]
  PIN w_data[188]
    DIRECTION OUTPUT ;
    USE SIGNAL ;
    PORT
      LAYER M7 ;
        RECT  54.08 0 54.112 0.07 ;
    END
  END w_data[188]
  PIN w_data[189]
    DIRECTION OUTPUT ;
    USE SIGNAL ;
    PORT
      LAYER M7 ;
        RECT  54.4 0 54.432 0.07 ;
    END
  END w_data[189]
  PIN w_data[18]
    DIRECTION OUTPUT ;
    USE SIGNAL ;
    PORT
      LAYER M5 ;
        RECT  5.28 0 5.304 0.084 ;
    END
  END w_data[18]
  PIN w_data[190]
    DIRECTION OUTPUT ;
    USE SIGNAL ;
    PORT
      LAYER M7 ;
        RECT  54.656 0 54.688 0.07 ;
    END
  END w_data[190]
  PIN w_data[191]
    DIRECTION OUTPUT ;
    USE SIGNAL ;
    PORT
      LAYER M7 ;
        RECT  54.976 0 55.008 0.07 ;
    END
  END w_data[191]
  PIN w_data[192]
    DIRECTION OUTPUT ;
    USE SIGNAL ;
    PORT
      LAYER M5 ;
        RECT  55.248 0 55.272 0.084 ;
    END
  END w_data[192]
  PIN w_data[193]
    DIRECTION OUTPUT ;
    USE SIGNAL ;
    PORT
      LAYER M5 ;
        RECT  55.536 0 55.56 0.084 ;
    END
  END w_data[193]
  PIN w_data[194]
    DIRECTION OUTPUT ;
    USE SIGNAL ;
    PORT
      LAYER M5 ;
        RECT  55.824 0 55.848 0.084 ;
    END
  END w_data[194]
  PIN w_data[195]
    DIRECTION OUTPUT ;
    USE SIGNAL ;
    PORT
      LAYER M5 ;
        RECT  56.112 0 56.136 0.084 ;
    END
  END w_data[195]
  PIN w_data[196]
    DIRECTION OUTPUT ;
    USE SIGNAL ;
    PORT
      LAYER M5 ;
        RECT  56.4 0 56.424 0.084 ;
    END
  END w_data[196]
  PIN w_data[197]
    DIRECTION OUTPUT ;
    USE SIGNAL ;
    PORT
      LAYER M5 ;
        RECT  56.688 0 56.712 0.084 ;
    END
  END w_data[197]
  PIN w_data[198]
    DIRECTION OUTPUT ;
    USE SIGNAL ;
    PORT
      LAYER M5 ;
        RECT  56.976 0 57 0.084 ;
    END
  END w_data[198]
  PIN w_data[199]
    DIRECTION OUTPUT ;
    USE SIGNAL ;
    PORT
      LAYER M5 ;
        RECT  57.264 0 57.288 0.084 ;
    END
  END w_data[199]
  PIN w_data[19]
    DIRECTION OUTPUT ;
    USE SIGNAL ;
    PORT
      LAYER M5 ;
        RECT  5.568 0 5.592 0.084 ;
    END
  END w_data[19]
  PIN w_data[1]
    DIRECTION OUTPUT ;
    USE SIGNAL ;
    PORT
      LAYER M5 ;
        RECT  0.432 0 0.456 0.084 ;
    END
  END w_data[1]
  PIN w_data[200]
    DIRECTION OUTPUT ;
    USE SIGNAL ;
    PORT
      LAYER M5 ;
        RECT  57.552 0 57.576 0.084 ;
    END
  END w_data[200]
  PIN w_data[201]
    DIRECTION OUTPUT ;
    USE SIGNAL ;
    PORT
      LAYER M5 ;
        RECT  57.84 0 57.864 0.084 ;
    END
  END w_data[201]
  PIN w_data[202]
    DIRECTION OUTPUT ;
    USE SIGNAL ;
    PORT
      LAYER M5 ;
        RECT  58.128 0 58.152 0.084 ;
    END
  END w_data[202]
  PIN w_data[203]
    DIRECTION OUTPUT ;
    USE SIGNAL ;
    PORT
      LAYER M5 ;
        RECT  58.416 0 58.44 0.084 ;
    END
  END w_data[203]
  PIN w_data[204]
    DIRECTION OUTPUT ;
    USE SIGNAL ;
    PORT
      LAYER M5 ;
        RECT  58.704 0 58.728 0.084 ;
    END
  END w_data[204]
  PIN w_data[205]
    DIRECTION OUTPUT ;
    USE SIGNAL ;
    PORT
      LAYER M5 ;
        RECT  58.992 0 59.016 0.084 ;
    END
  END w_data[205]
  PIN w_data[206]
    DIRECTION OUTPUT ;
    USE SIGNAL ;
    PORT
      LAYER M5 ;
        RECT  59.28 0 59.304 0.084 ;
    END
  END w_data[206]
  PIN w_data[207]
    DIRECTION OUTPUT ;
    USE SIGNAL ;
    PORT
      LAYER M5 ;
        RECT  59.568 0 59.592 0.084 ;
    END
  END w_data[207]
  PIN w_data[208]
    DIRECTION OUTPUT ;
    USE SIGNAL ;
    PORT
      LAYER M5 ;
        RECT  59.856 0 59.88 0.084 ;
    END
  END w_data[208]
  PIN w_data[209]
    DIRECTION OUTPUT ;
    USE SIGNAL ;
    PORT
      LAYER M5 ;
        RECT  60.144 0 60.168 0.084 ;
    END
  END w_data[209]
  PIN w_data[20]
    DIRECTION OUTPUT ;
    USE SIGNAL ;
    PORT
      LAYER M5 ;
        RECT  5.856 0 5.88 0.084 ;
    END
  END w_data[20]
  PIN w_data[210]
    DIRECTION OUTPUT ;
    USE SIGNAL ;
    PORT
      LAYER M5 ;
        RECT  60.432 0 60.456 0.084 ;
    END
  END w_data[210]
  PIN w_data[211]
    DIRECTION OUTPUT ;
    USE SIGNAL ;
    PORT
      LAYER M5 ;
        RECT  60.72 0 60.744 0.084 ;
    END
  END w_data[211]
  PIN w_data[212]
    DIRECTION OUTPUT ;
    USE SIGNAL ;
    PORT
      LAYER M5 ;
        RECT  61.008 0 61.032 0.084 ;
    END
  END w_data[212]
  PIN w_data[213]
    DIRECTION OUTPUT ;
    USE SIGNAL ;
    PORT
      LAYER M5 ;
        RECT  61.296 0 61.32 0.084 ;
    END
  END w_data[213]
  PIN w_data[214]
    DIRECTION OUTPUT ;
    USE SIGNAL ;
    PORT
      LAYER M5 ;
        RECT  61.536 0 61.56 0.084 ;
    END
  END w_data[214]
  PIN w_data[215]
    DIRECTION OUTPUT ;
    USE SIGNAL ;
    PORT
      LAYER M5 ;
        RECT  61.824 0 61.848 0.084 ;
    END
  END w_data[215]
  PIN w_data[216]
    DIRECTION OUTPUT ;
    USE SIGNAL ;
    PORT
      LAYER M5 ;
        RECT  62.112 0 62.136 0.084 ;
    END
  END w_data[216]
  PIN w_data[217]
    DIRECTION OUTPUT ;
    USE SIGNAL ;
    PORT
      LAYER M5 ;
        RECT  62.4 0 62.424 0.084 ;
    END
  END w_data[217]
  PIN w_data[218]
    DIRECTION OUTPUT ;
    USE SIGNAL ;
    PORT
      LAYER M5 ;
        RECT  62.688 0 62.712 0.084 ;
    END
  END w_data[218]
  PIN w_data[219]
    DIRECTION OUTPUT ;
    USE SIGNAL ;
    PORT
      LAYER M5 ;
        RECT  62.976 0 63 0.084 ;
    END
  END w_data[219]
  PIN w_data[21]
    DIRECTION OUTPUT ;
    USE SIGNAL ;
    PORT
      LAYER M5 ;
        RECT  6.144 0 6.168 0.084 ;
    END
  END w_data[21]
  PIN w_data[220]
    DIRECTION OUTPUT ;
    USE SIGNAL ;
    PORT
      LAYER M5 ;
        RECT  63.264 0 63.288 0.084 ;
    END
  END w_data[220]
  PIN w_data[221]
    DIRECTION OUTPUT ;
    USE SIGNAL ;
    PORT
      LAYER M5 ;
        RECT  63.552 0 63.576 0.084 ;
    END
  END w_data[221]
  PIN w_data[222]
    DIRECTION OUTPUT ;
    USE SIGNAL ;
    PORT
      LAYER M5 ;
        RECT  63.84 0 63.864 0.084 ;
    END
  END w_data[222]
  PIN w_data[223]
    DIRECTION OUTPUT ;
    USE SIGNAL ;
    PORT
      LAYER M5 ;
        RECT  64.128 0 64.152 0.084 ;
    END
  END w_data[223]
  PIN w_data[224]
    DIRECTION OUTPUT ;
    USE SIGNAL ;
    PORT
      LAYER M7 ;
        RECT  64.448 0 64.48 0.07 ;
    END
  END w_data[224]
  PIN w_data[225]
    DIRECTION OUTPUT ;
    USE SIGNAL ;
    PORT
      LAYER M7 ;
        RECT  64.704 0 64.736 0.07 ;
    END
  END w_data[225]
  PIN w_data[226]
    DIRECTION OUTPUT ;
    USE SIGNAL ;
    PORT
      LAYER M7 ;
        RECT  65.024 0 65.056 0.07 ;
    END
  END w_data[226]
  PIN w_data[227]
    DIRECTION OUTPUT ;
    USE SIGNAL ;
    PORT
      LAYER M7 ;
        RECT  65.28 0 65.312 0.07 ;
    END
  END w_data[227]
  PIN w_data[228]
    DIRECTION OUTPUT ;
    USE SIGNAL ;
    PORT
      LAYER M7 ;
        RECT  65.6 0 65.632 0.07 ;
    END
  END w_data[228]
  PIN w_data[229]
    DIRECTION OUTPUT ;
    USE SIGNAL ;
    PORT
      LAYER M7 ;
        RECT  65.856 0 65.888 0.07 ;
    END
  END w_data[229]
  PIN w_data[22]
    DIRECTION OUTPUT ;
    USE SIGNAL ;
    PORT
      LAYER M5 ;
        RECT  6.432 0 6.456 0.084 ;
    END
  END w_data[22]
  PIN w_data[230]
    DIRECTION OUTPUT ;
    USE SIGNAL ;
    PORT
      LAYER M7 ;
        RECT  66.176 0 66.208 0.07 ;
    END
  END w_data[230]
  PIN w_data[231]
    DIRECTION OUTPUT ;
    USE SIGNAL ;
    PORT
      LAYER M7 ;
        RECT  66.432 0 66.464 0.07 ;
    END
  END w_data[231]
  PIN w_data[232]
    DIRECTION OUTPUT ;
    USE SIGNAL ;
    PORT
      LAYER M7 ;
        RECT  66.752 0 66.784 0.07 ;
    END
  END w_data[232]
  PIN w_data[233]
    DIRECTION OUTPUT ;
    USE SIGNAL ;
    PORT
      LAYER M7 ;
        RECT  67.008 0 67.04 0.07 ;
    END
  END w_data[233]
  PIN w_data[234]
    DIRECTION OUTPUT ;
    USE SIGNAL ;
    PORT
      LAYER M7 ;
        RECT  67.328 0 67.36 0.07 ;
    END
  END w_data[234]
  PIN w_data[235]
    DIRECTION OUTPUT ;
    USE SIGNAL ;
    PORT
      LAYER M7 ;
        RECT  67.584 0 67.616 0.07 ;
    END
  END w_data[235]
  PIN w_data[236]
    DIRECTION OUTPUT ;
    USE SIGNAL ;
    PORT
      LAYER M7 ;
        RECT  67.84 0 67.872 0.07 ;
    END
  END w_data[236]
  PIN w_data[237]
    DIRECTION OUTPUT ;
    USE SIGNAL ;
    PORT
      LAYER M7 ;
        RECT  68.16 0 68.192 0.07 ;
    END
  END w_data[237]
  PIN w_data[238]
    DIRECTION OUTPUT ;
    USE SIGNAL ;
    PORT
      LAYER M7 ;
        RECT  68.416 0 68.448 0.07 ;
    END
  END w_data[238]
  PIN w_data[239]
    DIRECTION OUTPUT ;
    USE SIGNAL ;
    PORT
      LAYER M7 ;
        RECT  68.736 0 68.768 0.07 ;
    END
  END w_data[239]
  PIN w_data[23]
    DIRECTION OUTPUT ;
    USE SIGNAL ;
    PORT
      LAYER M5 ;
        RECT  6.72 0 6.744 0.084 ;
    END
  END w_data[23]
  PIN w_data[240]
    DIRECTION OUTPUT ;
    USE SIGNAL ;
    PORT
      LAYER M7 ;
        RECT  68.992 0 69.024 0.07 ;
    END
  END w_data[240]
  PIN w_data[241]
    DIRECTION OUTPUT ;
    USE SIGNAL ;
    PORT
      LAYER M7 ;
        RECT  69.312 0 69.344 0.07 ;
    END
  END w_data[241]
  PIN w_data[242]
    DIRECTION OUTPUT ;
    USE SIGNAL ;
    PORT
      LAYER M7 ;
        RECT  69.568 0 69.6 0.07 ;
    END
  END w_data[242]
  PIN w_data[243]
    DIRECTION OUTPUT ;
    USE SIGNAL ;
    PORT
      LAYER M7 ;
        RECT  69.888 0 69.92 0.07 ;
    END
  END w_data[243]
  PIN w_data[244]
    DIRECTION OUTPUT ;
    USE SIGNAL ;
    PORT
      LAYER M7 ;
        RECT  70.144 0 70.176 0.07 ;
    END
  END w_data[244]
  PIN w_data[245]
    DIRECTION OUTPUT ;
    USE SIGNAL ;
    PORT
      LAYER M7 ;
        RECT  70.464 0 70.496 0.07 ;
    END
  END w_data[245]
  PIN w_data[246]
    DIRECTION OUTPUT ;
    USE SIGNAL ;
    PORT
      LAYER M7 ;
        RECT  70.72 0 70.752 0.07 ;
    END
  END w_data[246]
  PIN w_data[247]
    DIRECTION OUTPUT ;
    USE SIGNAL ;
    PORT
      LAYER M7 ;
        RECT  71.04 0 71.072 0.07 ;
    END
  END w_data[247]
  PIN w_data[248]
    DIRECTION OUTPUT ;
    USE SIGNAL ;
    PORT
      LAYER M7 ;
        RECT  71.296 0 71.328 0.07 ;
    END
  END w_data[248]
  PIN w_data[249]
    DIRECTION OUTPUT ;
    USE SIGNAL ;
    PORT
      LAYER M7 ;
        RECT  71.616 0 71.648 0.07 ;
    END
  END w_data[249]
  PIN w_data[24]
    DIRECTION OUTPUT ;
    USE SIGNAL ;
    PORT
      LAYER M5 ;
        RECT  7.008 0 7.032 0.084 ;
    END
  END w_data[24]
  PIN w_data[250]
    DIRECTION OUTPUT ;
    USE SIGNAL ;
    PORT
      LAYER M7 ;
        RECT  71.872 0 71.904 0.07 ;
    END
  END w_data[250]
  PIN w_data[251]
    DIRECTION OUTPUT ;
    USE SIGNAL ;
    PORT
      LAYER M7 ;
        RECT  72.192 0 72.224 0.07 ;
    END
  END w_data[251]
  PIN w_data[252]
    DIRECTION OUTPUT ;
    USE SIGNAL ;
    PORT
      LAYER M7 ;
        RECT  72.448 0 72.48 0.07 ;
    END
  END w_data[252]
  PIN w_data[253]
    DIRECTION OUTPUT ;
    USE SIGNAL ;
    PORT
      LAYER M7 ;
        RECT  72.768 0 72.8 0.07 ;
    END
  END w_data[253]
  PIN w_data[254]
    DIRECTION OUTPUT ;
    USE SIGNAL ;
    PORT
      LAYER M7 ;
        RECT  73.024 0 73.056 0.07 ;
    END
  END w_data[254]
  PIN w_data[255]
    DIRECTION OUTPUT ;
    USE SIGNAL ;
    PORT
      LAYER M7 ;
        RECT  73.344 0 73.376 0.07 ;
    END
  END w_data[255]
  PIN w_data[25]
    DIRECTION OUTPUT ;
    USE SIGNAL ;
    PORT
      LAYER M5 ;
        RECT  7.296 0 7.32 0.084 ;
    END
  END w_data[25]
  PIN w_data[26]
    DIRECTION OUTPUT ;
    USE SIGNAL ;
    PORT
      LAYER M5 ;
        RECT  7.584 0 7.608 0.084 ;
    END
  END w_data[26]
  PIN w_data[27]
    DIRECTION OUTPUT ;
    USE SIGNAL ;
    PORT
      LAYER M5 ;
        RECT  7.872 0 7.896 0.084 ;
    END
  END w_data[27]
  PIN w_data[28]
    DIRECTION OUTPUT ;
    USE SIGNAL ;
    PORT
      LAYER M5 ;
        RECT  8.16 0 8.184 0.084 ;
    END
  END w_data[28]
  PIN w_data[29]
    DIRECTION OUTPUT ;
    USE SIGNAL ;
    PORT
      LAYER M5 ;
        RECT  8.448 0 8.472 0.084 ;
    END
  END w_data[29]
  PIN w_data[2]
    DIRECTION OUTPUT ;
    USE SIGNAL ;
    PORT
      LAYER M5 ;
        RECT  0.72 0 0.744 0.084 ;
    END
  END w_data[2]
  PIN w_data[30]
    DIRECTION OUTPUT ;
    USE SIGNAL ;
    PORT
      LAYER M5 ;
        RECT  8.736 0 8.76 0.084 ;
    END
  END w_data[30]
  PIN w_data[31]
    DIRECTION OUTPUT ;
    USE SIGNAL ;
    PORT
      LAYER M5 ;
        RECT  9.024 0 9.048 0.084 ;
    END
  END w_data[31]
  PIN w_data[32]
    DIRECTION OUTPUT ;
    USE SIGNAL ;
    PORT
      LAYER M7 ;
        RECT  9.344 0 9.376 0.07 ;
    END
  END w_data[32]
  PIN w_data[33]
    DIRECTION OUTPUT ;
    USE SIGNAL ;
    PORT
      LAYER M7 ;
        RECT  9.6 0 9.632 0.07 ;
    END
  END w_data[33]
  PIN w_data[34]
    DIRECTION OUTPUT ;
    USE SIGNAL ;
    PORT
      LAYER M7 ;
        RECT  9.856 0 9.888 0.07 ;
    END
  END w_data[34]
  PIN w_data[35]
    DIRECTION OUTPUT ;
    USE SIGNAL ;
    PORT
      LAYER M7 ;
        RECT  10.176 0 10.208 0.07 ;
    END
  END w_data[35]
  PIN w_data[36]
    DIRECTION OUTPUT ;
    USE SIGNAL ;
    PORT
      LAYER M7 ;
        RECT  10.432 0 10.464 0.07 ;
    END
  END w_data[36]
  PIN w_data[37]
    DIRECTION OUTPUT ;
    USE SIGNAL ;
    PORT
      LAYER M7 ;
        RECT  10.752 0 10.784 0.07 ;
    END
  END w_data[37]
  PIN w_data[38]
    DIRECTION OUTPUT ;
    USE SIGNAL ;
    PORT
      LAYER M7 ;
        RECT  11.008 0 11.04 0.07 ;
    END
  END w_data[38]
  PIN w_data[39]
    DIRECTION OUTPUT ;
    USE SIGNAL ;
    PORT
      LAYER M7 ;
        RECT  11.328 0 11.36 0.07 ;
    END
  END w_data[39]
  PIN w_data[3]
    DIRECTION OUTPUT ;
    USE SIGNAL ;
    PORT
      LAYER M5 ;
        RECT  1.008 0 1.032 0.084 ;
    END
  END w_data[3]
  PIN w_data[40]
    DIRECTION OUTPUT ;
    USE SIGNAL ;
    PORT
      LAYER M7 ;
        RECT  11.584 0 11.616 0.07 ;
    END
  END w_data[40]
  PIN w_data[41]
    DIRECTION OUTPUT ;
    USE SIGNAL ;
    PORT
      LAYER M7 ;
        RECT  11.904 0 11.936 0.07 ;
    END
  END w_data[41]
  PIN w_data[42]
    DIRECTION OUTPUT ;
    USE SIGNAL ;
    PORT
      LAYER M7 ;
        RECT  12.16 0 12.192 0.07 ;
    END
  END w_data[42]
  PIN w_data[43]
    DIRECTION OUTPUT ;
    USE SIGNAL ;
    PORT
      LAYER M7 ;
        RECT  12.48 0 12.512 0.07 ;
    END
  END w_data[43]
  PIN w_data[44]
    DIRECTION OUTPUT ;
    USE SIGNAL ;
    PORT
      LAYER M7 ;
        RECT  12.736 0 12.768 0.07 ;
    END
  END w_data[44]
  PIN w_data[45]
    DIRECTION OUTPUT ;
    USE SIGNAL ;
    PORT
      LAYER M7 ;
        RECT  13.056 0 13.088 0.07 ;
    END
  END w_data[45]
  PIN w_data[46]
    DIRECTION OUTPUT ;
    USE SIGNAL ;
    PORT
      LAYER M7 ;
        RECT  13.312 0 13.344 0.07 ;
    END
  END w_data[46]
  PIN w_data[47]
    DIRECTION OUTPUT ;
    USE SIGNAL ;
    PORT
      LAYER M7 ;
        RECT  13.632 0 13.664 0.07 ;
    END
  END w_data[47]
  PIN w_data[48]
    DIRECTION OUTPUT ;
    USE SIGNAL ;
    PORT
      LAYER M7 ;
        RECT  13.888 0 13.92 0.07 ;
    END
  END w_data[48]
  PIN w_data[49]
    DIRECTION OUTPUT ;
    USE SIGNAL ;
    PORT
      LAYER M7 ;
        RECT  14.208 0 14.24 0.07 ;
    END
  END w_data[49]
  PIN w_data[4]
    DIRECTION OUTPUT ;
    USE SIGNAL ;
    PORT
      LAYER M5 ;
        RECT  1.296 0 1.32 0.084 ;
    END
  END w_data[4]
  PIN w_data[50]
    DIRECTION OUTPUT ;
    USE SIGNAL ;
    PORT
      LAYER M7 ;
        RECT  14.464 0 14.496 0.07 ;
    END
  END w_data[50]
  PIN w_data[51]
    DIRECTION OUTPUT ;
    USE SIGNAL ;
    PORT
      LAYER M7 ;
        RECT  14.784 0 14.816 0.07 ;
    END
  END w_data[51]
  PIN w_data[52]
    DIRECTION OUTPUT ;
    USE SIGNAL ;
    PORT
      LAYER M7 ;
        RECT  15.04 0 15.072 0.07 ;
    END
  END w_data[52]
  PIN w_data[53]
    DIRECTION OUTPUT ;
    USE SIGNAL ;
    PORT
      LAYER M7 ;
        RECT  15.36 0 15.392 0.07 ;
    END
  END w_data[53]
  PIN w_data[54]
    DIRECTION OUTPUT ;
    USE SIGNAL ;
    PORT
      LAYER M7 ;
        RECT  15.616 0 15.648 0.07 ;
    END
  END w_data[54]
  PIN w_data[55]
    DIRECTION OUTPUT ;
    USE SIGNAL ;
    PORT
      LAYER M7 ;
        RECT  15.936 0 15.968 0.07 ;
    END
  END w_data[55]
  PIN w_data[56]
    DIRECTION OUTPUT ;
    USE SIGNAL ;
    PORT
      LAYER M7 ;
        RECT  16.192 0 16.224 0.07 ;
    END
  END w_data[56]
  PIN w_data[57]
    DIRECTION OUTPUT ;
    USE SIGNAL ;
    PORT
      LAYER M7 ;
        RECT  16.512 0 16.544 0.07 ;
    END
  END w_data[57]
  PIN w_data[58]
    DIRECTION OUTPUT ;
    USE SIGNAL ;
    PORT
      LAYER M7 ;
        RECT  16.768 0 16.8 0.07 ;
    END
  END w_data[58]
  PIN w_data[59]
    DIRECTION OUTPUT ;
    USE SIGNAL ;
    PORT
      LAYER M7 ;
        RECT  17.088 0 17.12 0.07 ;
    END
  END w_data[59]
  PIN w_data[5]
    DIRECTION OUTPUT ;
    USE SIGNAL ;
    PORT
      LAYER M5 ;
        RECT  1.584 0 1.608 0.084 ;
    END
  END w_data[5]
  PIN w_data[60]
    DIRECTION OUTPUT ;
    USE SIGNAL ;
    PORT
      LAYER M7 ;
        RECT  17.344 0 17.376 0.07 ;
    END
  END w_data[60]
  PIN w_data[61]
    DIRECTION OUTPUT ;
    USE SIGNAL ;
    PORT
      LAYER M7 ;
        RECT  17.664 0 17.696 0.07 ;
    END
  END w_data[61]
  PIN w_data[62]
    DIRECTION OUTPUT ;
    USE SIGNAL ;
    PORT
      LAYER M7 ;
        RECT  17.92 0 17.952 0.07 ;
    END
  END w_data[62]
  PIN w_data[63]
    DIRECTION OUTPUT ;
    USE SIGNAL ;
    PORT
      LAYER M7 ;
        RECT  18.24 0 18.272 0.07 ;
    END
  END w_data[63]
  PIN w_data[64]
    DIRECTION OUTPUT ;
    USE SIGNAL ;
    PORT
      LAYER M5 ;
        RECT  18.48 0 18.504 0.084 ;
    END
  END w_data[64]
  PIN w_data[65]
    DIRECTION OUTPUT ;
    USE SIGNAL ;
    PORT
      LAYER M5 ;
        RECT  18.768 0 18.792 0.084 ;
    END
  END w_data[65]
  PIN w_data[66]
    DIRECTION OUTPUT ;
    USE SIGNAL ;
    PORT
      LAYER M5 ;
        RECT  19.056 0 19.08 0.084 ;
    END
  END w_data[66]
  PIN w_data[67]
    DIRECTION OUTPUT ;
    USE SIGNAL ;
    PORT
      LAYER M5 ;
        RECT  19.344 0 19.368 0.084 ;
    END
  END w_data[67]
  PIN w_data[68]
    DIRECTION OUTPUT ;
    USE SIGNAL ;
    PORT
      LAYER M5 ;
        RECT  19.632 0 19.656 0.084 ;
    END
  END w_data[68]
  PIN w_data[69]
    DIRECTION OUTPUT ;
    USE SIGNAL ;
    PORT
      LAYER M5 ;
        RECT  19.92 0 19.944 0.084 ;
    END
  END w_data[69]
  PIN w_data[6]
    DIRECTION OUTPUT ;
    USE SIGNAL ;
    PORT
      LAYER M5 ;
        RECT  1.872 0 1.896 0.084 ;
    END
  END w_data[6]
  PIN w_data[70]
    DIRECTION OUTPUT ;
    USE SIGNAL ;
    PORT
      LAYER M5 ;
        RECT  20.208 0 20.232 0.084 ;
    END
  END w_data[70]
  PIN w_data[71]
    DIRECTION OUTPUT ;
    USE SIGNAL ;
    PORT
      LAYER M5 ;
        RECT  20.496 0 20.52 0.084 ;
    END
  END w_data[71]
  PIN w_data[72]
    DIRECTION OUTPUT ;
    USE SIGNAL ;
    PORT
      LAYER M5 ;
        RECT  20.784 0 20.808 0.084 ;
    END
  END w_data[72]
  PIN w_data[73]
    DIRECTION OUTPUT ;
    USE SIGNAL ;
    PORT
      LAYER M5 ;
        RECT  21.072 0 21.096 0.084 ;
    END
  END w_data[73]
  PIN w_data[74]
    DIRECTION OUTPUT ;
    USE SIGNAL ;
    PORT
      LAYER M5 ;
        RECT  21.36 0 21.384 0.084 ;
    END
  END w_data[74]
  PIN w_data[75]
    DIRECTION OUTPUT ;
    USE SIGNAL ;
    PORT
      LAYER M5 ;
        RECT  21.648 0 21.672 0.084 ;
    END
  END w_data[75]
  PIN w_data[76]
    DIRECTION OUTPUT ;
    USE SIGNAL ;
    PORT
      LAYER M5 ;
        RECT  21.936 0 21.96 0.084 ;
    END
  END w_data[76]
  PIN w_data[77]
    DIRECTION OUTPUT ;
    USE SIGNAL ;
    PORT
      LAYER M5 ;
        RECT  22.224 0 22.248 0.084 ;
    END
  END w_data[77]
  PIN w_data[78]
    DIRECTION OUTPUT ;
    USE SIGNAL ;
    PORT
      LAYER M5 ;
        RECT  22.512 0 22.536 0.084 ;
    END
  END w_data[78]
  PIN w_data[79]
    DIRECTION OUTPUT ;
    USE SIGNAL ;
    PORT
      LAYER M5 ;
        RECT  22.8 0 22.824 0.084 ;
    END
  END w_data[79]
  PIN w_data[7]
    DIRECTION OUTPUT ;
    USE SIGNAL ;
    PORT
      LAYER M5 ;
        RECT  2.16 0 2.184 0.084 ;
    END
  END w_data[7]
  PIN w_data[80]
    DIRECTION OUTPUT ;
    USE SIGNAL ;
    PORT
      LAYER M5 ;
        RECT  23.088 0 23.112 0.084 ;
    END
  END w_data[80]
  PIN w_data[81]
    DIRECTION OUTPUT ;
    USE SIGNAL ;
    PORT
      LAYER M5 ;
        RECT  23.376 0 23.4 0.084 ;
    END
  END w_data[81]
  PIN w_data[82]
    DIRECTION OUTPUT ;
    USE SIGNAL ;
    PORT
      LAYER M5 ;
        RECT  23.664 0 23.688 0.084 ;
    END
  END w_data[82]
  PIN w_data[83]
    DIRECTION OUTPUT ;
    USE SIGNAL ;
    PORT
      LAYER M5 ;
        RECT  23.952 0 23.976 0.084 ;
    END
  END w_data[83]
  PIN w_data[84]
    DIRECTION OUTPUT ;
    USE SIGNAL ;
    PORT
      LAYER M5 ;
        RECT  24.24 0 24.264 0.084 ;
    END
  END w_data[84]
  PIN w_data[85]
    DIRECTION OUTPUT ;
    USE SIGNAL ;
    PORT
      LAYER M5 ;
        RECT  24.528 0 24.552 0.084 ;
    END
  END w_data[85]
  PIN w_data[86]
    DIRECTION OUTPUT ;
    USE SIGNAL ;
    PORT
      LAYER M5 ;
        RECT  24.816 0 24.84 0.084 ;
    END
  END w_data[86]
  PIN w_data[87]
    DIRECTION OUTPUT ;
    USE SIGNAL ;
    PORT
      LAYER M5 ;
        RECT  25.104 0 25.128 0.084 ;
    END
  END w_data[87]
  PIN w_data[88]
    DIRECTION OUTPUT ;
    USE SIGNAL ;
    PORT
      LAYER M5 ;
        RECT  25.392 0 25.416 0.084 ;
    END
  END w_data[88]
  PIN w_data[89]
    DIRECTION OUTPUT ;
    USE SIGNAL ;
    PORT
      LAYER M5 ;
        RECT  25.68 0 25.704 0.084 ;
    END
  END w_data[89]
  PIN w_data[8]
    DIRECTION OUTPUT ;
    USE SIGNAL ;
    PORT
      LAYER M5 ;
        RECT  2.448 0 2.472 0.084 ;
    END
  END w_data[8]
  PIN w_data[90]
    DIRECTION OUTPUT ;
    USE SIGNAL ;
    PORT
      LAYER M5 ;
        RECT  25.968 0 25.992 0.084 ;
    END
  END w_data[90]
  PIN w_data[91]
    DIRECTION OUTPUT ;
    USE SIGNAL ;
    PORT
      LAYER M5 ;
        RECT  26.256 0 26.28 0.084 ;
    END
  END w_data[91]
  PIN w_data[92]
    DIRECTION OUTPUT ;
    USE SIGNAL ;
    PORT
      LAYER M5 ;
        RECT  26.544 0 26.568 0.084 ;
    END
  END w_data[92]
  PIN w_data[93]
    DIRECTION OUTPUT ;
    USE SIGNAL ;
    PORT
      LAYER M5 ;
        RECT  26.832 0 26.856 0.084 ;
    END
  END w_data[93]
  PIN w_data[94]
    DIRECTION OUTPUT ;
    USE SIGNAL ;
    PORT
      LAYER M5 ;
        RECT  27.12 0 27.144 0.084 ;
    END
  END w_data[94]
  PIN w_data[95]
    DIRECTION OUTPUT ;
    USE SIGNAL ;
    PORT
      LAYER M5 ;
        RECT  27.408 0 27.432 0.084 ;
    END
  END w_data[95]
  PIN w_data[96]
    DIRECTION OUTPUT ;
    USE SIGNAL ;
    PORT
      LAYER M7 ;
        RECT  27.712 0 27.744 0.07 ;
    END
  END w_data[96]
  PIN w_data[97]
    DIRECTION OUTPUT ;
    USE SIGNAL ;
    PORT
      LAYER M7 ;
        RECT  27.968 0 28 0.07 ;
    END
  END w_data[97]
  PIN w_data[98]
    DIRECTION OUTPUT ;
    USE SIGNAL ;
    PORT
      LAYER M7 ;
        RECT  28.288 0 28.32 0.07 ;
    END
  END w_data[98]
  PIN w_data[99]
    DIRECTION OUTPUT ;
    USE SIGNAL ;
    PORT
      LAYER M7 ;
        RECT  28.544 0 28.576 0.07 ;
    END
  END w_data[99]
  PIN w_data[9]
    DIRECTION OUTPUT ;
    USE SIGNAL ;
    PORT
      LAYER M5 ;
        RECT  2.736 0 2.76 0.084 ;
    END
  END w_data[9]
  PIN w_room
    DIRECTION INPUT ;
    USE SIGNAL ;
    PORT
      LAYER M5 ;
        RECT  73.632 0 73.656 0.084 ;
    END
  END w_room
  PIN w_sec[0]
    DIRECTION OUTPUT ;
    USE SIGNAL ;
    PORT
      LAYER M5 ;
        RECT  73.92 0 73.944 0.084 ;
    END
  END w_sec[0]
  PIN w_sec[10]
    DIRECTION OUTPUT ;
    USE SIGNAL ;
    PORT
      LAYER M5 ;
        RECT  76.752 0 76.776 0.084 ;
    END
  END w_sec[10]
  PIN w_sec[11]
    DIRECTION OUTPUT ;
    USE SIGNAL ;
    PORT
      LAYER M5 ;
        RECT  77.04 0 77.064 0.084 ;
    END
  END w_sec[11]
  PIN w_sec[12]
    DIRECTION OUTPUT ;
    USE SIGNAL ;
    PORT
      LAYER M5 ;
        RECT  77.328 0 77.352 0.084 ;
    END
  END w_sec[12]
  PIN w_sec[13]
    DIRECTION OUTPUT ;
    USE SIGNAL ;
    PORT
      LAYER M5 ;
        RECT  77.616 0 77.64 0.084 ;
    END
  END w_sec[13]
  PIN w_sec[14]
    DIRECTION OUTPUT ;
    USE SIGNAL ;
    PORT
      LAYER M5 ;
        RECT  77.904 0 77.928 0.084 ;
    END
  END w_sec[14]
  PIN w_sec[15]
    DIRECTION OUTPUT ;
    USE SIGNAL ;
    PORT
      LAYER M5 ;
        RECT  78.192 0 78.216 0.084 ;
    END
  END w_sec[15]
  PIN w_sec[16]
    DIRECTION OUTPUT ;
    USE SIGNAL ;
    PORT
      LAYER M5 ;
        RECT  78.48 0 78.504 0.084 ;
    END
  END w_sec[16]
  PIN w_sec[17]
    DIRECTION OUTPUT ;
    USE SIGNAL ;
    PORT
      LAYER M5 ;
        RECT  78.768 0 78.792 0.084 ;
    END
  END w_sec[17]
  PIN w_sec[18]
    DIRECTION OUTPUT ;
    USE SIGNAL ;
    PORT
      LAYER M5 ;
        RECT  79.056 0 79.08 0.084 ;
    END
  END w_sec[18]
  PIN w_sec[19]
    DIRECTION OUTPUT ;
    USE SIGNAL ;
    PORT
      LAYER M5 ;
        RECT  79.344 0 79.368 0.084 ;
    END
  END w_sec[19]
  PIN w_sec[1]
    DIRECTION OUTPUT ;
    USE SIGNAL ;
    PORT
      LAYER M5 ;
        RECT  74.208 0 74.232 0.084 ;
    END
  END w_sec[1]
  PIN w_sec[20]
    DIRECTION OUTPUT ;
    USE SIGNAL ;
    PORT
      LAYER M5 ;
        RECT  79.632 0 79.656 0.084 ;
    END
  END w_sec[20]
  PIN w_sec[21]
    DIRECTION OUTPUT ;
    USE SIGNAL ;
    PORT
      LAYER M5 ;
        RECT  79.92 0 79.944 0.084 ;
    END
  END w_sec[21]
  PIN w_sec[22]
    DIRECTION OUTPUT ;
    USE SIGNAL ;
    PORT
      LAYER M5 ;
        RECT  80.208 0 80.232 0.084 ;
    END
  END w_sec[22]
  PIN w_sec[23]
    DIRECTION OUTPUT ;
    USE SIGNAL ;
    PORT
      LAYER M5 ;
        RECT  80.496 0 80.52 0.084 ;
    END
  END w_sec[23]
  PIN w_sec[2]
    DIRECTION OUTPUT ;
    USE SIGNAL ;
    PORT
      LAYER M5 ;
        RECT  74.496 0 74.52 0.084 ;
    END
  END w_sec[2]
  PIN w_sec[3]
    DIRECTION OUTPUT ;
    USE SIGNAL ;
    PORT
      LAYER M5 ;
        RECT  74.784 0 74.808 0.084 ;
    END
  END w_sec[3]
  PIN w_sec[4]
    DIRECTION OUTPUT ;
    USE SIGNAL ;
    PORT
      LAYER M5 ;
        RECT  75.072 0 75.096 0.084 ;
    END
  END w_sec[4]
  PIN w_sec[5]
    DIRECTION OUTPUT ;
    USE SIGNAL ;
    PORT
      LAYER M5 ;
        RECT  75.36 0 75.384 0.084 ;
    END
  END w_sec[5]
  PIN w_sec[6]
    DIRECTION OUTPUT ;
    USE SIGNAL ;
    PORT
      LAYER M5 ;
        RECT  75.648 0 75.672 0.084 ;
    END
  END w_sec[6]
  PIN w_sec[7]
    DIRECTION OUTPUT ;
    USE SIGNAL ;
    PORT
      LAYER M5 ;
        RECT  75.888 0 75.912 0.084 ;
    END
  END w_sec[7]
  PIN w_sec[8]
    DIRECTION OUTPUT ;
    USE SIGNAL ;
    PORT
      LAYER M5 ;
        RECT  76.176 0 76.2 0.084 ;
    END
  END w_sec[8]
  PIN w_sec[9]
    DIRECTION OUTPUT ;
    USE SIGNAL ;
    PORT
      LAYER M5 ;
        RECT  76.464 0 76.488 0.084 ;
    END
  END w_sec[9]
  PIN w_tag[0]
    DIRECTION OUTPUT ;
    USE SIGNAL ;
    PORT
      LAYER M5 ;
        RECT  80.784 0 80.808 0.084 ;
    END
  END w_tag[0]
  PIN w_tag[1]
    DIRECTION OUTPUT ;
    USE SIGNAL ;
    PORT
      LAYER M5 ;
        RECT  81.072 0 81.096 0.084 ;
    END
  END w_tag[1]
  PIN w_tag[2]
    DIRECTION OUTPUT ;
    USE SIGNAL ;
    PORT
      LAYER M5 ;
        RECT  81.36 0 81.384 0.084 ;
    END
  END w_tag[2]
  PIN w_tag[3]
    DIRECTION OUTPUT ;
    USE SIGNAL ;
    PORT
      LAYER M5 ;
        RECT  81.648 0 81.672 0.084 ;
    END
  END w_tag[3]
  PIN w_tag[4]
    DIRECTION OUTPUT ;
    USE SIGNAL ;
    PORT
      LAYER M5 ;
        RECT  81.936 0 81.96 0.084 ;
    END
  END w_tag[4]
  PIN w_tag[5]
    DIRECTION OUTPUT ;
    USE SIGNAL ;
    PORT
      LAYER M5 ;
        RECT  82.224 0 82.248 0.084 ;
    END
  END w_tag[5]
  PIN w_tag[6]
    DIRECTION OUTPUT ;
    USE SIGNAL ;
    PORT
      LAYER M5 ;
        RECT  82.512 0 82.536 0.084 ;
    END
  END w_tag[6]
  PIN w_tag[7]
    DIRECTION OUTPUT ;
    USE SIGNAL ;
    PORT
      LAYER M7 ;
        RECT  82.816 0 82.848 0.07 ;
    END
  END w_tag[7]
  PIN w_tag[8]
    DIRECTION OUTPUT ;
    USE SIGNAL ;
    PORT
      LAYER M7 ;
        RECT  83.072 0 83.104 0.07 ;
    END
  END w_tag[8]
  PIN w_v
    DIRECTION OUTPUT ;
    USE SIGNAL ;
    PORT
      LAYER M7 ;
        RECT  83.392 0 83.424 0.07 ;
    END
  END w_v
  PIN wd_tag[0]
    DIRECTION INPUT ;
    USE SIGNAL ;
    PORT
      LAYER M7 ;
        RECT  83.648 0 83.68 0.07 ;
    END
  END wd_tag[0]
  PIN wd_tag[1]
    DIRECTION INPUT ;
    USE SIGNAL ;
    PORT
      LAYER M7 ;
        RECT  83.968 0 84 0.07 ;
    END
  END wd_tag[1]
  PIN wd_tag[2]
    DIRECTION INPUT ;
    USE SIGNAL ;
    PORT
      LAYER M7 ;
        RECT  84.224 0 84.256 0.07 ;
    END
  END wd_tag[2]
  PIN wd_tag[3]
    DIRECTION INPUT ;
    USE SIGNAL ;
    PORT
      LAYER M7 ;
        RECT  84.544 0 84.576 0.07 ;
    END
  END wd_tag[3]
  PIN wd_tag[4]
    DIRECTION INPUT ;
    USE SIGNAL ;
    PORT
      LAYER M7 ;
        RECT  84.8 0 84.832 0.07 ;
    END
  END wd_tag[4]
  PIN wd_tag[5]
    DIRECTION INPUT ;
    USE SIGNAL ;
    PORT
      LAYER M7 ;
        RECT  85.12 0 85.152 0.07 ;
    END
  END wd_tag[5]
  PIN wd_tag[6]
    DIRECTION INPUT ;
    USE SIGNAL ;
    PORT
      LAYER M7 ;
        RECT  85.376 0 85.408 0.07 ;
    END
  END wd_tag[6]
  PIN wd_tag[7]
    DIRECTION INPUT ;
    USE SIGNAL ;
    PORT
      LAYER M7 ;
        RECT  85.696 0 85.728 0.07 ;
    END
  END wd_tag[7]
  PIN wd_tag[8]
    DIRECTION INPUT ;
    USE SIGNAL ;
    PORT
      LAYER M7 ;
        RECT  85.952 0 85.984 0.07 ;
    END
  END wd_tag[8]
  PIN wd_v
    DIRECTION INPUT ;
    USE SIGNAL ;
    PORT
      LAYER M7 ;
        RECT  86.272 0 86.304 0.07 ;
    END
  END wd_v
  PIN VDD
    DIRECTION INOUT ;
    USE POWER ;
    PORT
      LAYER M6 ;
        RECT  2.16 181.113 84.24 181.401 ;
        RECT  2.16 175.713 84.24 176.001 ;
        RECT  2.16 170.313 84.24 170.601 ;
        RECT  2.16 164.913 84.24 165.201 ;
        RECT  2.16 159.513 84.24 159.801 ;
        RECT  2.16 154.113 84.24 154.401 ;
        RECT  2.16 148.713 84.24 149.001 ;
        RECT  2.16 143.313 84.24 143.601 ;
        RECT  2.16 137.913 84.24 138.201 ;
        RECT  2.16 132.513 84.24 132.801 ;
        RECT  2.16 127.113 84.24 127.401 ;
        RECT  2.16 121.713 84.24 122.001 ;
        RECT  2.16 116.313 84.24 116.601 ;
        RECT  2.16 110.913 84.24 111.201 ;
        RECT  2.16 105.513 84.24 105.801 ;
        RECT  2.16 100.113 84.24 100.401 ;
        RECT  2.16 94.713 84.24 95.001 ;
        RECT  2.16 89.313 84.24 89.601 ;
        RECT  2.16 83.913 84.24 84.201 ;
        RECT  2.16 78.513 84.24 78.801 ;
        RECT  2.16 73.113 84.24 73.401 ;
        RECT  2.16 67.713 84.24 68.001 ;
        RECT  2.16 62.313 84.24 62.601 ;
        RECT  2.16 56.913 84.24 57.201 ;
        RECT  2.16 51.513 84.24 51.801 ;
        RECT  2.16 46.113 84.24 46.401 ;
        RECT  2.16 40.713 84.24 41.001 ;
        RECT  2.16 35.313 84.24 35.601 ;
        RECT  2.16 29.913 84.24 30.201 ;
        RECT  2.16 24.513 84.24 24.801 ;
        RECT  2.16 19.113 84.24 19.401 ;
        RECT  2.16 13.713 84.24 14.001 ;
        RECT  2.16 8.313 84.24 8.601 ;
        RECT  2.16 2.913 84.24 3.201 ;
    END
  END VDD
  PIN VSS
    DIRECTION INOUT ;
    USE GROUND ;
    PORT
      LAYER M6 ;
        RECT  2.16 180.729 84.24 181.017 ;
        RECT  2.16 175.329 84.24 175.617 ;
        RECT  2.16 169.929 84.24 170.217 ;
        RECT  2.16 164.529 84.24 164.817 ;
        RECT  2.16 159.129 84.24 159.417 ;
        RECT  2.16 153.729 84.24 154.017 ;
        RECT  2.16 148.329 84.24 148.617 ;
        RECT  2.16 142.929 84.24 143.217 ;
        RECT  2.16 137.529 84.24 137.817 ;
        RECT  2.16 132.129 84.24 132.417 ;
        RECT  2.16 126.729 84.24 127.017 ;
        RECT  2.16 121.329 84.24 121.617 ;
        RECT  2.16 115.929 84.24 116.217 ;
        RECT  2.16 110.529 84.24 110.817 ;
        RECT  2.16 105.129 84.24 105.417 ;
        RECT  2.16 99.729 84.24 100.017 ;
        RECT  2.16 94.329 84.24 94.617 ;
        RECT  2.16 88.929 84.24 89.217 ;
        RECT  2.16 83.529 84.24 83.817 ;
        RECT  2.16 78.129 84.24 78.417 ;
        RECT  2.16 72.729 84.24 73.017 ;
        RECT  2.16 67.329 84.24 67.617 ;
        RECT  2.16 61.929 84.24 62.217 ;
        RECT  2.16 56.529 84.24 56.817 ;
        RECT  2.16 51.129 84.24 51.417 ;
        RECT  2.16 45.729 84.24 46.017 ;
        RECT  2.16 40.329 84.24 40.617 ;
        RECT  2.16 34.929 84.24 35.217 ;
        RECT  2.16 29.529 84.24 29.817 ;
        RECT  2.16 24.129 84.24 24.417 ;
        RECT  2.16 18.729 84.24 19.017 ;
        RECT  2.16 13.329 84.24 13.617 ;
        RECT  2.16 7.929 84.24 8.217 ;
        RECT  2.16 2.529 84.24 2.817 ;
    END
  END VSS
  OBS
    LAYER RVTN ;
     RECT  2.16 2.16 84.24 2.295 ;
     RECT  2.16 2.565 84.24 2.835 ;
     RECT  2.16 3.105 84.24 3.375 ;
     RECT  2.16 3.645 84.24 3.915 ;
     RECT  2.16 4.185 84.24 4.455 ;
     RECT  2.16 4.725 84.24 4.995 ;
     RECT  2.16 5.265 84.24 5.535 ;
     RECT  2.16 5.805 84.24 6.075 ;
     RECT  2.16 6.345 84.24 6.615 ;
     RECT  2.16 6.885 84.24 7.155 ;
     RECT  2.16 7.425 84.24 7.695 ;
     RECT  2.16 7.965 84.24 8.235 ;
     RECT  2.16 8.505 84.24 8.775 ;
     RECT  2.16 9.045 84.24 9.315 ;
     RECT  2.16 9.585 84.24 9.855 ;
     RECT  2.16 10.125 84.24 10.395 ;
     RECT  2.16 10.665 84.24 10.935 ;
     RECT  2.16 11.205 84.24 11.475 ;
     RECT  2.16 11.745 84.24 12.015 ;
     RECT  2.16 12.285 84.24 12.555 ;
     RECT  2.16 12.825 84.24 13.095 ;
     RECT  2.16 13.365 84.24 13.635 ;
     RECT  2.16 13.905 84.24 14.175 ;
     RECT  2.16 14.445 84.24 14.715 ;
     RECT  2.16 14.985 84.24 15.255 ;
     RECT  2.16 15.525 84.24 15.795 ;
     RECT  2.16 16.065 84.24 16.335 ;
     RECT  2.16 16.605 84.24 16.875 ;
     RECT  2.16 17.145 84.24 17.415 ;
     RECT  2.16 17.685 84.24 17.955 ;
     RECT  2.16 18.225 84.24 18.495 ;
     RECT  2.16 18.765 84.24 19.035 ;
     RECT  2.16 19.305 84.24 19.575 ;
     RECT  2.16 19.845 84.24 20.115 ;
     RECT  2.16 20.385 84.24 20.655 ;
     RECT  2.16 20.925 84.24 21.195 ;
     RECT  2.16 21.465 84.24 21.735 ;
     RECT  2.16 22.005 84.24 22.275 ;
     RECT  2.16 22.545 84.24 22.815 ;
     RECT  2.16 23.085 84.24 23.355 ;
     RECT  2.16 23.625 84.24 23.895 ;
     RECT  2.16 24.165 84.24 24.435 ;
     RECT  2.16 24.705 84.24 24.975 ;
     RECT  2.16 25.245 84.24 25.515 ;
     RECT  2.16 25.785 84.24 26.055 ;
     RECT  2.16 26.325 84.24 26.595 ;
     RECT  2.16 26.865 84.24 27.135 ;
     RECT  2.16 27.405 84.24 27.675 ;
     RECT  2.16 27.945 84.24 28.215 ;
     RECT  2.16 28.485 84.24 28.755 ;
     RECT  2.16 29.025 84.24 29.295 ;
     RECT  2.16 29.565 84.24 29.835 ;
     RECT  2.16 30.105 84.24 30.375 ;
     RECT  2.16 30.645 84.24 30.915 ;
     RECT  2.16 31.185 84.24 31.455 ;
     RECT  2.16 31.725 84.24 31.995 ;
     RECT  2.16 32.265 84.24 32.535 ;
     RECT  2.16 32.805 84.24 33.075 ;
     RECT  2.16 33.345 84.24 33.615 ;
     RECT  2.16 33.885 84.24 34.155 ;
     RECT  2.16 34.425 84.24 34.695 ;
     RECT  2.16 34.965 84.24 35.235 ;
     RECT  2.16 35.505 84.24 35.775 ;
     RECT  2.16 36.045 84.24 36.315 ;
     RECT  2.16 36.585 84.24 36.855 ;
     RECT  2.16 37.125 84.24 37.395 ;
     RECT  2.16 37.665 84.24 37.935 ;
     RECT  2.16 38.205 84.24 38.475 ;
     RECT  2.16 38.745 84.24 39.015 ;
     RECT  2.16 39.285 84.24 39.555 ;
     RECT  2.16 39.825 84.24 40.095 ;
     RECT  2.16 40.365 84.24 40.635 ;
     RECT  2.16 40.905 84.24 41.175 ;
     RECT  2.16 41.445 84.24 41.715 ;
     RECT  2.16 41.985 84.24 42.255 ;
     RECT  2.16 42.525 84.24 42.795 ;
     RECT  2.16 43.065 84.24 43.335 ;
     RECT  2.16 43.605 84.24 43.875 ;
     RECT  2.16 44.145 84.24 44.415 ;
     RECT  2.16 44.685 84.24 44.955 ;
     RECT  2.16 45.225 84.24 45.495 ;
     RECT  2.16 45.765 84.24 46.035 ;
     RECT  2.16 46.305 84.24 46.575 ;
     RECT  2.16 46.845 84.24 47.115 ;
     RECT  2.16 47.385 84.24 47.655 ;
     RECT  2.16 47.925 84.24 48.195 ;
     RECT  2.16 48.465 84.24 48.735 ;
     RECT  2.16 49.005 84.24 49.275 ;
     RECT  2.16 49.545 84.24 49.815 ;
     RECT  2.16 50.085 84.24 50.355 ;
     RECT  2.16 50.625 84.24 50.895 ;
     RECT  2.16 51.165 84.24 51.435 ;
     RECT  2.16 51.705 84.24 51.975 ;
     RECT  2.16 52.245 84.24 52.515 ;
     RECT  2.16 52.785 84.24 53.055 ;
     RECT  2.16 53.325 84.24 53.595 ;
     RECT  2.16 53.865 84.24 54.135 ;
     RECT  2.16 54.405 84.24 54.675 ;
     RECT  2.16 54.945 84.24 55.215 ;
     RECT  2.16 55.485 84.24 55.755 ;
     RECT  2.16 56.025 84.24 56.295 ;
     RECT  2.16 56.565 84.24 56.835 ;
     RECT  2.16 57.105 84.24 57.375 ;
     RECT  2.16 57.645 84.24 57.915 ;
     RECT  2.16 58.185 84.24 58.455 ;
     RECT  2.16 58.725 84.24 58.995 ;
     RECT  2.16 59.265 84.24 59.535 ;
     RECT  2.16 59.805 84.24 60.075 ;
     RECT  2.16 60.345 84.24 60.615 ;
     RECT  2.16 60.885 84.24 61.155 ;
     RECT  2.16 61.425 84.24 61.695 ;
     RECT  2.16 61.965 84.24 62.235 ;
     RECT  2.16 62.505 84.24 62.775 ;
     RECT  2.16 63.045 84.24 63.315 ;
     RECT  2.16 63.585 84.24 63.855 ;
     RECT  2.16 64.125 84.24 64.395 ;
     RECT  2.16 64.665 84.24 64.935 ;
     RECT  2.16 65.205 84.24 65.475 ;
     RECT  2.16 65.745 84.24 66.015 ;
     RECT  2.16 66.285 84.24 66.555 ;
     RECT  2.16 66.825 84.24 67.095 ;
     RECT  2.16 67.365 84.24 67.635 ;
     RECT  2.16 67.905 84.24 68.175 ;
     RECT  2.16 68.445 84.24 68.715 ;
     RECT  2.16 68.985 84.24 69.255 ;
     RECT  2.16 69.525 84.24 69.795 ;
     RECT  2.16 70.065 84.24 70.335 ;
     RECT  2.16 70.605 84.24 70.875 ;
     RECT  2.16 71.145 84.24 71.415 ;
     RECT  2.16 71.685 84.24 71.955 ;
     RECT  2.16 72.225 84.24 72.495 ;
     RECT  2.16 72.765 84.24 73.035 ;
     RECT  2.16 73.305 84.24 73.575 ;
     RECT  2.16 73.845 84.24 74.115 ;
     RECT  2.16 74.385 84.24 74.655 ;
     RECT  2.16 74.925 84.24 75.195 ;
     RECT  2.16 75.465 84.24 75.735 ;
     RECT  2.16 76.005 84.24 76.275 ;
     RECT  2.16 76.545 84.24 76.815 ;
     RECT  2.16 77.085 84.24 77.355 ;
     RECT  2.16 77.625 84.24 77.895 ;
     RECT  2.16 78.165 84.24 78.435 ;
     RECT  2.16 78.705 84.24 78.975 ;
     RECT  2.16 79.245 84.24 79.515 ;
     RECT  2.16 79.785 84.24 80.055 ;
     RECT  2.16 80.325 84.24 80.595 ;
     RECT  2.16 80.865 84.24 81.135 ;
     RECT  2.16 81.405 84.24 81.675 ;
     RECT  2.16 81.945 84.24 82.215 ;
     RECT  2.16 82.485 84.24 82.755 ;
     RECT  2.16 83.025 84.24 83.295 ;
     RECT  2.16 83.565 84.24 83.835 ;
     RECT  2.16 84.105 84.24 84.375 ;
     RECT  2.16 84.645 84.24 84.915 ;
     RECT  2.16 85.185 84.24 85.455 ;
     RECT  2.16 85.725 84.24 85.995 ;
     RECT  2.16 86.265 84.24 86.535 ;
     RECT  2.16 86.805 84.24 87.075 ;
     RECT  2.16 87.345 84.24 87.615 ;
     RECT  2.16 87.885 84.24 88.155 ;
     RECT  2.16 88.425 84.24 88.695 ;
     RECT  2.16 88.965 84.24 89.235 ;
     RECT  2.16 89.505 84.24 89.775 ;
     RECT  2.16 90.045 84.24 90.315 ;
     RECT  2.16 90.585 84.24 90.855 ;
     RECT  2.16 91.125 84.24 91.395 ;
     RECT  2.16 91.665 84.24 91.935 ;
     RECT  2.16 92.205 84.24 92.475 ;
     RECT  2.16 92.745 84.24 93.015 ;
     RECT  2.16 93.285 84.24 93.555 ;
     RECT  2.16 93.825 84.24 94.095 ;
     RECT  2.16 94.365 84.24 94.635 ;
     RECT  2.16 94.905 84.24 95.175 ;
     RECT  2.16 95.445 84.24 95.715 ;
     RECT  2.16 95.985 84.24 96.255 ;
     RECT  2.16 96.525 84.24 96.795 ;
     RECT  2.16 97.065 84.24 97.335 ;
     RECT  2.16 97.605 84.24 97.875 ;
     RECT  2.16 98.145 84.24 98.415 ;
     RECT  2.16 98.685 84.24 98.955 ;
     RECT  2.16 99.225 84.24 99.495 ;
     RECT  2.16 99.765 84.24 100.035 ;
     RECT  2.16 100.305 84.24 100.575 ;
     RECT  2.16 100.845 84.24 101.115 ;
     RECT  2.16 101.385 84.24 101.655 ;
     RECT  2.16 101.925 84.24 102.195 ;
     RECT  2.16 102.465 84.24 102.735 ;
     RECT  2.16 103.005 84.24 103.275 ;
     RECT  2.16 103.545 84.24 103.815 ;
     RECT  2.16 104.085 84.24 104.355 ;
     RECT  2.16 104.625 84.24 104.895 ;
     RECT  2.16 105.165 84.24 105.435 ;
     RECT  2.16 105.705 84.24 105.975 ;
     RECT  2.16 106.245 84.24 106.515 ;
     RECT  2.16 106.785 84.24 107.055 ;
     RECT  2.16 107.325 84.24 107.595 ;
     RECT  2.16 107.865 84.24 108.135 ;
     RECT  2.16 108.405 84.24 108.675 ;
     RECT  2.16 108.945 84.24 109.215 ;
     RECT  2.16 109.485 84.24 109.755 ;
     RECT  2.16 110.025 84.24 110.295 ;
     RECT  2.16 110.565 84.24 110.835 ;
     RECT  2.16 111.105 84.24 111.375 ;
     RECT  2.16 111.645 84.24 111.915 ;
     RECT  2.16 112.185 84.24 112.455 ;
     RECT  2.16 112.725 84.24 112.995 ;
     RECT  2.16 113.265 84.24 113.535 ;
     RECT  2.16 113.805 84.24 114.075 ;
     RECT  2.16 114.345 84.24 114.615 ;
     RECT  2.16 114.885 84.24 115.155 ;
     RECT  2.16 115.425 84.24 115.695 ;
     RECT  2.16 115.965 84.24 116.235 ;
     RECT  2.16 116.505 84.24 116.775 ;
     RECT  2.16 117.045 84.24 117.315 ;
     RECT  2.16 117.585 84.24 117.855 ;
     RECT  2.16 118.125 84.24 118.395 ;
     RECT  2.16 118.665 84.24 118.935 ;
     RECT  2.16 119.205 84.24 119.475 ;
     RECT  2.16 119.745 84.24 120.015 ;
     RECT  2.16 120.285 84.24 120.555 ;
     RECT  2.16 120.825 84.24 121.095 ;
     RECT  2.16 121.365 84.24 121.635 ;
     RECT  2.16 121.905 84.24 122.175 ;
     RECT  2.16 122.445 84.24 122.715 ;
     RECT  2.16 122.985 84.24 123.255 ;
     RECT  2.16 123.525 84.24 123.795 ;
     RECT  2.16 124.065 84.24 124.335 ;
     RECT  2.16 124.605 84.24 124.875 ;
     RECT  2.16 125.145 84.24 125.415 ;
     RECT  2.16 125.685 84.24 125.955 ;
     RECT  2.16 126.225 84.24 126.495 ;
     RECT  2.16 126.765 84.24 127.035 ;
     RECT  2.16 127.305 84.24 127.575 ;
     RECT  2.16 127.845 84.24 128.115 ;
     RECT  2.16 128.385 84.24 128.655 ;
     RECT  2.16 128.925 84.24 129.195 ;
     RECT  2.16 129.465 84.24 129.735 ;
     RECT  2.16 130.005 84.24 130.275 ;
     RECT  2.16 130.545 84.24 130.815 ;
     RECT  2.16 131.085 84.24 131.355 ;
     RECT  2.16 131.625 84.24 131.895 ;
     RECT  2.16 132.165 84.24 132.435 ;
     RECT  2.16 132.705 84.24 132.975 ;
     RECT  2.16 133.245 84.24 133.515 ;
     RECT  2.16 133.785 84.24 134.055 ;
     RECT  2.16 134.325 84.24 134.595 ;
     RECT  2.16 134.865 84.24 135.135 ;
     RECT  2.16 135.405 84.24 135.675 ;
     RECT  2.16 135.945 84.24 136.215 ;
     RECT  2.16 136.485 84.24 136.755 ;
     RECT  2.16 137.025 84.24 137.295 ;
     RECT  2.16 137.565 84.24 137.835 ;
     RECT  2.16 138.105 84.24 138.375 ;
     RECT  2.16 138.645 84.24 138.915 ;
     RECT  2.16 139.185 84.24 139.455 ;
     RECT  2.16 139.725 84.24 139.995 ;
     RECT  2.16 140.265 84.24 140.535 ;
     RECT  2.16 140.805 84.24 141.075 ;
     RECT  2.16 141.345 84.24 141.615 ;
     RECT  2.16 141.885 84.24 142.155 ;
     RECT  2.16 142.425 84.24 142.695 ;
     RECT  2.16 142.965 84.24 143.235 ;
     RECT  2.16 143.505 84.24 143.775 ;
     RECT  2.16 144.045 84.24 144.315 ;
     RECT  2.16 144.585 84.24 144.855 ;
     RECT  2.16 145.125 84.24 145.395 ;
     RECT  2.16 145.665 84.24 145.935 ;
     RECT  2.16 146.205 84.24 146.475 ;
     RECT  2.16 146.745 84.24 147.015 ;
     RECT  2.16 147.285 84.24 147.555 ;
     RECT  2.16 147.825 84.24 148.095 ;
     RECT  2.16 148.365 84.24 148.635 ;
     RECT  2.16 148.905 84.24 149.175 ;
     RECT  2.16 149.445 84.24 149.715 ;
     RECT  2.16 149.985 84.24 150.255 ;
     RECT  2.16 150.525 84.24 150.795 ;
     RECT  2.16 151.065 84.24 151.335 ;
     RECT  2.16 151.605 84.24 151.875 ;
     RECT  2.16 152.145 84.24 152.415 ;
     RECT  2.16 152.685 84.24 152.955 ;
     RECT  2.16 153.225 84.24 153.495 ;
     RECT  2.16 153.765 84.24 154.035 ;
     RECT  2.16 154.305 84.24 154.575 ;
     RECT  2.16 154.845 84.24 155.115 ;
     RECT  2.16 155.385 84.24 155.655 ;
     RECT  2.16 155.925 84.24 156.195 ;
     RECT  2.16 156.465 84.24 156.735 ;
     RECT  2.16 157.005 84.24 157.275 ;
     RECT  2.16 157.545 84.24 157.815 ;
     RECT  2.16 158.085 84.24 158.355 ;
     RECT  2.16 158.625 84.24 158.895 ;
     RECT  2.16 159.165 84.24 159.435 ;
     RECT  2.16 159.705 84.24 159.975 ;
     RECT  2.16 160.245 84.24 160.515 ;
     RECT  2.16 160.785 84.24 161.055 ;
     RECT  2.16 161.325 84.24 161.595 ;
     RECT  2.16 161.865 84.24 162.135 ;
     RECT  2.16 162.405 84.24 162.675 ;
     RECT  2.16 162.945 84.24 163.215 ;
     RECT  2.16 163.485 84.24 163.755 ;
     RECT  2.16 164.025 84.24 164.295 ;
     RECT  2.16 164.565 84.24 164.835 ;
     RECT  2.16 165.105 84.24 165.375 ;
     RECT  2.16 165.645 84.24 165.915 ;
     RECT  2.16 166.185 84.24 166.455 ;
     RECT  2.16 166.725 84.24 166.995 ;
     RECT  2.16 167.265 84.24 167.535 ;
     RECT  2.16 167.805 84.24 168.075 ;
     RECT  2.16 168.345 84.24 168.615 ;
     RECT  2.16 168.885 84.24 169.155 ;
     RECT  2.16 169.425 84.24 169.695 ;
     RECT  2.16 169.965 84.24 170.235 ;
     RECT  2.16 170.505 84.24 170.775 ;
     RECT  2.16 171.045 84.24 171.315 ;
     RECT  2.16 171.585 84.24 171.855 ;
     RECT  2.16 172.125 84.24 172.395 ;
     RECT  2.16 172.665 84.24 172.935 ;
     RECT  2.16 173.205 84.24 173.475 ;
     RECT  2.16 173.745 84.24 174.015 ;
     RECT  2.16 174.285 84.24 174.555 ;
     RECT  2.16 174.825 84.24 175.095 ;
     RECT  2.16 175.365 84.24 175.635 ;
     RECT  2.16 175.905 84.24 176.175 ;
     RECT  2.16 176.445 84.24 176.715 ;
     RECT  2.16 176.985 84.24 177.255 ;
     RECT  2.16 177.525 84.24 177.795 ;
     RECT  2.16 178.065 84.24 178.335 ;
     RECT  2.16 178.605 84.24 178.875 ;
     RECT  2.16 179.145 84.24 179.415 ;
     RECT  2.16 179.685 84.24 179.955 ;
     RECT  2.16 180.225 84.24 180.495 ;
     RECT  2.16 180.765 84.24 181.035 ;
     RECT  2.16 181.305 84.24 181.44 ;
    LAYER RVTP ;
     RECT  2.16 2.295 84.24 2.565 ;
     RECT  2.16 2.835 84.24 3.105 ;
     RECT  2.16 3.375 84.24 3.645 ;
     RECT  2.16 3.915 84.24 4.185 ;
     RECT  2.16 4.455 84.24 4.725 ;
     RECT  2.16 4.995 84.24 5.265 ;
     RECT  2.16 5.535 84.24 5.805 ;
     RECT  2.16 6.075 84.24 6.345 ;
     RECT  2.16 6.615 84.24 6.885 ;
     RECT  2.16 7.155 84.24 7.425 ;
     RECT  2.16 7.695 84.24 7.965 ;
     RECT  2.16 8.235 84.24 8.505 ;
     RECT  2.16 8.775 84.24 9.045 ;
     RECT  2.16 9.315 84.24 9.585 ;
     RECT  2.16 9.855 84.24 10.125 ;
     RECT  2.16 10.395 84.24 10.665 ;
     RECT  2.16 10.935 84.24 11.205 ;
     RECT  2.16 11.475 84.24 11.745 ;
     RECT  2.16 12.015 84.24 12.285 ;
     RECT  2.16 12.555 84.24 12.825 ;
     RECT  2.16 13.095 84.24 13.365 ;
     RECT  2.16 13.635 84.24 13.905 ;
     RECT  2.16 14.175 84.24 14.445 ;
     RECT  2.16 14.715 84.24 14.985 ;
     RECT  2.16 15.255 84.24 15.525 ;
     RECT  2.16 15.795 84.24 16.065 ;
     RECT  2.16 16.335 84.24 16.605 ;
     RECT  2.16 16.875 84.24 17.145 ;
     RECT  2.16 17.415 84.24 17.685 ;
     RECT  2.16 17.955 84.24 18.225 ;
     RECT  2.16 18.495 84.24 18.765 ;
     RECT  2.16 19.035 84.24 19.305 ;
     RECT  2.16 19.575 84.24 19.845 ;
     RECT  2.16 20.115 84.24 20.385 ;
     RECT  2.16 20.655 84.24 20.925 ;
     RECT  2.16 21.195 84.24 21.465 ;
     RECT  2.16 21.735 84.24 22.005 ;
     RECT  2.16 22.275 84.24 22.545 ;
     RECT  2.16 22.815 84.24 23.085 ;
     RECT  2.16 23.355 84.24 23.625 ;
     RECT  2.16 23.895 84.24 24.165 ;
     RECT  2.16 24.435 84.24 24.705 ;
     RECT  2.16 24.975 84.24 25.245 ;
     RECT  2.16 25.515 84.24 25.785 ;
     RECT  2.16 26.055 84.24 26.325 ;
     RECT  2.16 26.595 84.24 26.865 ;
     RECT  2.16 27.135 84.24 27.405 ;
     RECT  2.16 27.675 84.24 27.945 ;
     RECT  2.16 28.215 84.24 28.485 ;
     RECT  2.16 28.755 84.24 29.025 ;
     RECT  2.16 29.295 84.24 29.565 ;
     RECT  2.16 29.835 84.24 30.105 ;
     RECT  2.16 30.375 84.24 30.645 ;
     RECT  2.16 30.915 84.24 31.185 ;
     RECT  2.16 31.455 84.24 31.725 ;
     RECT  2.16 31.995 84.24 32.265 ;
     RECT  2.16 32.535 84.24 32.805 ;
     RECT  2.16 33.075 84.24 33.345 ;
     RECT  2.16 33.615 84.24 33.885 ;
     RECT  2.16 34.155 84.24 34.425 ;
     RECT  2.16 34.695 84.24 34.965 ;
     RECT  2.16 35.235 84.24 35.505 ;
     RECT  2.16 35.775 84.24 36.045 ;
     RECT  2.16 36.315 84.24 36.585 ;
     RECT  2.16 36.855 84.24 37.125 ;
     RECT  2.16 37.395 84.24 37.665 ;
     RECT  2.16 37.935 84.24 38.205 ;
     RECT  2.16 38.475 84.24 38.745 ;
     RECT  2.16 39.015 84.24 39.285 ;
     RECT  2.16 39.555 84.24 39.825 ;
     RECT  2.16 40.095 84.24 40.365 ;
     RECT  2.16 40.635 84.24 40.905 ;
     RECT  2.16 41.175 84.24 41.445 ;
     RECT  2.16 41.715 84.24 41.985 ;
     RECT  2.16 42.255 84.24 42.525 ;
     RECT  2.16 42.795 84.24 43.065 ;
     RECT  2.16 43.335 84.24 43.605 ;
     RECT  2.16 43.875 84.24 44.145 ;
     RECT  2.16 44.415 84.24 44.685 ;
     RECT  2.16 44.955 84.24 45.225 ;
     RECT  2.16 45.495 84.24 45.765 ;
     RECT  2.16 46.035 84.24 46.305 ;
     RECT  2.16 46.575 84.24 46.845 ;
     RECT  2.16 47.115 84.24 47.385 ;
     RECT  2.16 47.655 84.24 47.925 ;
     RECT  2.16 48.195 84.24 48.465 ;
     RECT  2.16 48.735 84.24 49.005 ;
     RECT  2.16 49.275 84.24 49.545 ;
     RECT  2.16 49.815 84.24 50.085 ;
     RECT  2.16 50.355 84.24 50.625 ;
     RECT  2.16 50.895 84.24 51.165 ;
     RECT  2.16 51.435 84.24 51.705 ;
     RECT  2.16 51.975 84.24 52.245 ;
     RECT  2.16 52.515 84.24 52.785 ;
     RECT  2.16 53.055 84.24 53.325 ;
     RECT  2.16 53.595 84.24 53.865 ;
     RECT  2.16 54.135 84.24 54.405 ;
     RECT  2.16 54.675 84.24 54.945 ;
     RECT  2.16 55.215 84.24 55.485 ;
     RECT  2.16 55.755 84.24 56.025 ;
     RECT  2.16 56.295 84.24 56.565 ;
     RECT  2.16 56.835 84.24 57.105 ;
     RECT  2.16 57.375 84.24 57.645 ;
     RECT  2.16 57.915 84.24 58.185 ;
     RECT  2.16 58.455 84.24 58.725 ;
     RECT  2.16 58.995 84.24 59.265 ;
     RECT  2.16 59.535 84.24 59.805 ;
     RECT  2.16 60.075 84.24 60.345 ;
     RECT  2.16 60.615 84.24 60.885 ;
     RECT  2.16 61.155 84.24 61.425 ;
     RECT  2.16 61.695 84.24 61.965 ;
     RECT  2.16 62.235 84.24 62.505 ;
     RECT  2.16 62.775 84.24 63.045 ;
     RECT  2.16 63.315 84.24 63.585 ;
     RECT  2.16 63.855 84.24 64.125 ;
     RECT  2.16 64.395 84.24 64.665 ;
     RECT  2.16 64.935 84.24 65.205 ;
     RECT  2.16 65.475 84.24 65.745 ;
     RECT  2.16 66.015 84.24 66.285 ;
     RECT  2.16 66.555 84.24 66.825 ;
     RECT  2.16 67.095 84.24 67.365 ;
     RECT  2.16 67.635 84.24 67.905 ;
     RECT  2.16 68.175 84.24 68.445 ;
     RECT  2.16 68.715 84.24 68.985 ;
     RECT  2.16 69.255 84.24 69.525 ;
     RECT  2.16 69.795 84.24 70.065 ;
     RECT  2.16 70.335 84.24 70.605 ;
     RECT  2.16 70.875 84.24 71.145 ;
     RECT  2.16 71.415 84.24 71.685 ;
     RECT  2.16 71.955 84.24 72.225 ;
     RECT  2.16 72.495 84.24 72.765 ;
     RECT  2.16 73.035 84.24 73.305 ;
     RECT  2.16 73.575 84.24 73.845 ;
     RECT  2.16 74.115 84.24 74.385 ;
     RECT  2.16 74.655 84.24 74.925 ;
     RECT  2.16 75.195 84.24 75.465 ;
     RECT  2.16 75.735 84.24 76.005 ;
     RECT  2.16 76.275 84.24 76.545 ;
     RECT  2.16 76.815 84.24 77.085 ;
     RECT  2.16 77.355 84.24 77.625 ;
     RECT  2.16 77.895 84.24 78.165 ;
     RECT  2.16 78.435 84.24 78.705 ;
     RECT  2.16 78.975 84.24 79.245 ;
     RECT  2.16 79.515 84.24 79.785 ;
     RECT  2.16 80.055 84.24 80.325 ;
     RECT  2.16 80.595 84.24 80.865 ;
     RECT  2.16 81.135 84.24 81.405 ;
     RECT  2.16 81.675 84.24 81.945 ;
     RECT  2.16 82.215 84.24 82.485 ;
     RECT  2.16 82.755 84.24 83.025 ;
     RECT  2.16 83.295 84.24 83.565 ;
     RECT  2.16 83.835 84.24 84.105 ;
     RECT  2.16 84.375 84.24 84.645 ;
     RECT  2.16 84.915 84.24 85.185 ;
     RECT  2.16 85.455 84.24 85.725 ;
     RECT  2.16 85.995 84.24 86.265 ;
     RECT  2.16 86.535 84.24 86.805 ;
     RECT  2.16 87.075 84.24 87.345 ;
     RECT  2.16 87.615 84.24 87.885 ;
     RECT  2.16 88.155 84.24 88.425 ;
     RECT  2.16 88.695 84.24 88.965 ;
     RECT  2.16 89.235 84.24 89.505 ;
     RECT  2.16 89.775 84.24 90.045 ;
     RECT  2.16 90.315 84.24 90.585 ;
     RECT  2.16 90.855 84.24 91.125 ;
     RECT  2.16 91.395 84.24 91.665 ;
     RECT  2.16 91.935 84.24 92.205 ;
     RECT  2.16 92.475 84.24 92.745 ;
     RECT  2.16 93.015 84.24 93.285 ;
     RECT  2.16 93.555 84.24 93.825 ;
     RECT  2.16 94.095 84.24 94.365 ;
     RECT  2.16 94.635 84.24 94.905 ;
     RECT  2.16 95.175 84.24 95.445 ;
     RECT  2.16 95.715 84.24 95.985 ;
     RECT  2.16 96.255 84.24 96.525 ;
     RECT  2.16 96.795 84.24 97.065 ;
     RECT  2.16 97.335 84.24 97.605 ;
     RECT  2.16 97.875 84.24 98.145 ;
     RECT  2.16 98.415 84.24 98.685 ;
     RECT  2.16 98.955 84.24 99.225 ;
     RECT  2.16 99.495 84.24 99.765 ;
     RECT  2.16 100.035 84.24 100.305 ;
     RECT  2.16 100.575 84.24 100.845 ;
     RECT  2.16 101.115 84.24 101.385 ;
     RECT  2.16 101.655 84.24 101.925 ;
     RECT  2.16 102.195 84.24 102.465 ;
     RECT  2.16 102.735 84.24 103.005 ;
     RECT  2.16 103.275 84.24 103.545 ;
     RECT  2.16 103.815 84.24 104.085 ;
     RECT  2.16 104.355 84.24 104.625 ;
     RECT  2.16 104.895 84.24 105.165 ;
     RECT  2.16 105.435 84.24 105.705 ;
     RECT  2.16 105.975 84.24 106.245 ;
     RECT  2.16 106.515 84.24 106.785 ;
     RECT  2.16 107.055 84.24 107.325 ;
     RECT  2.16 107.595 84.24 107.865 ;
     RECT  2.16 108.135 84.24 108.405 ;
     RECT  2.16 108.675 84.24 108.945 ;
     RECT  2.16 109.215 84.24 109.485 ;
     RECT  2.16 109.755 84.24 110.025 ;
     RECT  2.16 110.295 84.24 110.565 ;
     RECT  2.16 110.835 84.24 111.105 ;
     RECT  2.16 111.375 84.24 111.645 ;
     RECT  2.16 111.915 84.24 112.185 ;
     RECT  2.16 112.455 84.24 112.725 ;
     RECT  2.16 112.995 84.24 113.265 ;
     RECT  2.16 113.535 84.24 113.805 ;
     RECT  2.16 114.075 84.24 114.345 ;
     RECT  2.16 114.615 84.24 114.885 ;
     RECT  2.16 115.155 84.24 115.425 ;
     RECT  2.16 115.695 84.24 115.965 ;
     RECT  2.16 116.235 84.24 116.505 ;
     RECT  2.16 116.775 84.24 117.045 ;
     RECT  2.16 117.315 84.24 117.585 ;
     RECT  2.16 117.855 84.24 118.125 ;
     RECT  2.16 118.395 84.24 118.665 ;
     RECT  2.16 118.935 84.24 119.205 ;
     RECT  2.16 119.475 84.24 119.745 ;
     RECT  2.16 120.015 84.24 120.285 ;
     RECT  2.16 120.555 84.24 120.825 ;
     RECT  2.16 121.095 84.24 121.365 ;
     RECT  2.16 121.635 84.24 121.905 ;
     RECT  2.16 122.175 84.24 122.445 ;
     RECT  2.16 122.715 84.24 122.985 ;
     RECT  2.16 123.255 84.24 123.525 ;
     RECT  2.16 123.795 84.24 124.065 ;
     RECT  2.16 124.335 84.24 124.605 ;
     RECT  2.16 124.875 84.24 125.145 ;
     RECT  2.16 125.415 84.24 125.685 ;
     RECT  2.16 125.955 84.24 126.225 ;
     RECT  2.16 126.495 84.24 126.765 ;
     RECT  2.16 127.035 84.24 127.305 ;
     RECT  2.16 127.575 84.24 127.845 ;
     RECT  2.16 128.115 84.24 128.385 ;
     RECT  2.16 128.655 84.24 128.925 ;
     RECT  2.16 129.195 84.24 129.465 ;
     RECT  2.16 129.735 84.24 130.005 ;
     RECT  2.16 130.275 84.24 130.545 ;
     RECT  2.16 130.815 84.24 131.085 ;
     RECT  2.16 131.355 84.24 131.625 ;
     RECT  2.16 131.895 84.24 132.165 ;
     RECT  2.16 132.435 84.24 132.705 ;
     RECT  2.16 132.975 84.24 133.245 ;
     RECT  2.16 133.515 84.24 133.785 ;
     RECT  2.16 134.055 84.24 134.325 ;
     RECT  2.16 134.595 84.24 134.865 ;
     RECT  2.16 135.135 84.24 135.405 ;
     RECT  2.16 135.675 84.24 135.945 ;
     RECT  2.16 136.215 84.24 136.485 ;
     RECT  2.16 136.755 84.24 137.025 ;
     RECT  2.16 137.295 84.24 137.565 ;
     RECT  2.16 137.835 84.24 138.105 ;
     RECT  2.16 138.375 84.24 138.645 ;
     RECT  2.16 138.915 84.24 139.185 ;
     RECT  2.16 139.455 84.24 139.725 ;
     RECT  2.16 139.995 84.24 140.265 ;
     RECT  2.16 140.535 84.24 140.805 ;
     RECT  2.16 141.075 84.24 141.345 ;
     RECT  2.16 141.615 84.24 141.885 ;
     RECT  2.16 142.155 84.24 142.425 ;
     RECT  2.16 142.695 84.24 142.965 ;
     RECT  2.16 143.235 84.24 143.505 ;
     RECT  2.16 143.775 84.24 144.045 ;
     RECT  2.16 144.315 84.24 144.585 ;
     RECT  2.16 144.855 84.24 145.125 ;
     RECT  2.16 145.395 84.24 145.665 ;
     RECT  2.16 145.935 84.24 146.205 ;
     RECT  2.16 146.475 84.24 146.745 ;
     RECT  2.16 147.015 84.24 147.285 ;
     RECT  2.16 147.555 84.24 147.825 ;
     RECT  2.16 148.095 84.24 148.365 ;
     RECT  2.16 148.635 84.24 148.905 ;
     RECT  2.16 149.175 84.24 149.445 ;
     RECT  2.16 149.715 84.24 149.985 ;
     RECT  2.16 150.255 84.24 150.525 ;
     RECT  2.16 150.795 84.24 151.065 ;
     RECT  2.16 151.335 84.24 151.605 ;
     RECT  2.16 151.875 84.24 152.145 ;
     RECT  2.16 152.415 84.24 152.685 ;
     RECT  2.16 152.955 84.24 153.225 ;
     RECT  2.16 153.495 84.24 153.765 ;
     RECT  2.16 154.035 84.24 154.305 ;
     RECT  2.16 154.575 84.24 154.845 ;
     RECT  2.16 155.115 84.24 155.385 ;
     RECT  2.16 155.655 84.24 155.925 ;
     RECT  2.16 156.195 84.24 156.465 ;
     RECT  2.16 156.735 84.24 157.005 ;
     RECT  2.16 157.275 84.24 157.545 ;
     RECT  2.16 157.815 84.24 158.085 ;
     RECT  2.16 158.355 84.24 158.625 ;
     RECT  2.16 158.895 84.24 159.165 ;
     RECT  2.16 159.435 84.24 159.705 ;
     RECT  2.16 159.975 84.24 160.245 ;
     RECT  2.16 160.515 84.24 160.785 ;
     RECT  2.16 161.055 84.24 161.325 ;
     RECT  2.16 161.595 84.24 161.865 ;
     RECT  2.16 162.135 84.24 162.405 ;
     RECT  2.16 162.675 84.24 162.945 ;
     RECT  2.16 163.215 84.24 163.485 ;
     RECT  2.16 163.755 84.24 164.025 ;
     RECT  2.16 164.295 84.24 164.565 ;
     RECT  2.16 164.835 84.24 165.105 ;
     RECT  2.16 165.375 84.24 165.645 ;
     RECT  2.16 165.915 84.24 166.185 ;
     RECT  2.16 166.455 84.24 166.725 ;
     RECT  2.16 166.995 84.24 167.265 ;
     RECT  2.16 167.535 84.24 167.805 ;
     RECT  2.16 168.075 84.24 168.345 ;
     RECT  2.16 168.615 84.24 168.885 ;
     RECT  2.16 169.155 84.24 169.425 ;
     RECT  2.16 169.695 84.24 169.965 ;
     RECT  2.16 170.235 84.24 170.505 ;
     RECT  2.16 170.775 84.24 171.045 ;
     RECT  2.16 171.315 84.24 171.585 ;
     RECT  2.16 171.855 84.24 172.125 ;
     RECT  2.16 172.395 84.24 172.665 ;
     RECT  2.16 172.935 84.24 173.205 ;
     RECT  2.16 173.475 84.24 173.745 ;
     RECT  2.16 174.015 84.24 174.285 ;
     RECT  2.16 174.555 84.24 174.825 ;
     RECT  2.16 175.095 84.24 175.365 ;
     RECT  2.16 175.635 84.24 175.905 ;
     RECT  2.16 176.175 84.24 176.445 ;
     RECT  2.16 176.715 84.24 176.985 ;
     RECT  2.16 177.255 84.24 177.525 ;
     RECT  2.16 177.795 84.24 178.065 ;
     RECT  2.16 178.335 84.24 178.605 ;
     RECT  2.16 178.875 84.24 179.145 ;
     RECT  2.16 179.415 84.24 179.685 ;
     RECT  2.16 179.955 84.24 180.225 ;
     RECT  2.16 180.495 84.24 180.765 ;
     RECT  2.16 181.035 84.24 181.305 ;
    LAYER M1 ;
     RECT  2.16 2.151 84.24 181.449 ;
    LAYER M2 ;
     RECT  1.075 181.242 1.111 181.26 ;
     RECT  0.787 2.646 1.939 2.664 ;
     RECT  1.939 2.106 2.16 2.664 ;
     RECT  1.111 180.846 2.16 181.26 ;
     RECT  2.16 2.106 5.711 181.449 ;
     RECT  5.711 2.151 7.195 181.449 ;
     RECT  7.195 2.034 8.339 181.449 ;
     RECT  8.339 2.106 9.347 181.449 ;
     RECT  9.347 2.151 10.255 181.449 ;
     RECT  10.255 2.106 10.787 181.449 ;
     RECT  10.787 2.151 19.795 181.449 ;
     RECT  19.795 2.106 20.255 181.449 ;
     RECT  20.255 2.151 24.727 181.449 ;
     RECT  24.727 2.106 25.403 181.449 ;
     RECT  25.403 2.151 41.647 181.449 ;
     RECT  41.647 2.106 41.855 181.449 ;
     RECT  41.855 2.151 42.691 181.449 ;
     RECT  42.691 2.106 45.571 181.449 ;
     RECT  45.571 2.034 45.923 181.449 ;
     RECT  45.923 2.106 46.931 181.449 ;
     RECT  46.931 2.151 56.371 181.449 ;
     RECT  56.371 2.106 56.651 181.449 ;
     RECT  56.651 2.151 57.919 181.449 ;
     RECT  57.919 2.106 60.071 181.449 ;
     RECT  60.071 2.151 62.527 181.449 ;
     RECT  62.527 2.106 63.455 181.449 ;
     RECT  63.455 2.151 64.867 181.449 ;
     RECT  64.867 2.106 65.723 181.449 ;
     RECT  65.723 2.151 76.279 181.449 ;
     RECT  76.279 2.106 76.703 181.449 ;
     RECT  76.703 2.151 79.051 181.449 ;
     RECT  79.051 2.106 79.231 181.449 ;
     RECT  79.231 2.07 79.735 181.449 ;
     RECT  79.735 1.998 80.959 181.449 ;
     RECT  80.959 1.962 81.715 181.449 ;
     RECT  81.715 1.926 83.623 181.449 ;
     RECT  83.623 1.881 83.911 181.449 ;
     RECT  83.911 1.152 84.011 181.449 ;
     RECT  84.011 1.881 84.24 181.449 ;
     RECT  84.24 4.626 84.263 5.094 ;
     RECT  84.24 23.706 84.263 23.724 ;
     RECT  84.24 8.856 84.407 8.874 ;
     RECT  84.263 4.626 84.479 4.644 ;
     RECT  84.24 3.006 84.515 3.744 ;
     RECT  84.515 3.042 84.551 3.744 ;
     RECT  84.24 1.881 84.875 2.124 ;
     RECT  84.875 1.881 84.911 1.899 ;
     RECT  84.24 181.044 84.911 181.134 ;
     RECT  84.551 3.726 85.631 3.744 ;
     RECT  84.911 181.044 85.919 181.062 ;
     RECT  84.24 94.032 86.315 94.05 ;
     RECT  84.24 137.916 86.387 137.934 ;
    LAYER M3 ;
     RECT  21.528 0.091 22.158 0.139 ;
     RECT  37.188 0.091 37.206 0.139 ;
     RECT  38.016 0.091 39.042 0.139 ;
     RECT  39.78 0.091 39.798 0.139 ;
     RECT  46.584 0.091 46.602 0.139 ;
     RECT  65.376 0.091 65.394 0.139 ;
     RECT  37.188 0.139 39.798 0.187 ;
     RECT  40.968 0.139 41.418 0.187 ;
     RECT  77.436 0.091 79.65 0.187 ;
     RECT  77.436 0.187 79.794 0.221 ;
     RECT  27.072 0.139 27.09 0.235 ;
     RECT  79.776 0.221 79.794 0.317 ;
     RECT  29.736 0.235 29.754 0.331 ;
     RECT  3.708 0.139 3.726 0.523 ;
     RECT  5.004 0.091 5.022 0.523 ;
     RECT  19.044 0.091 19.062 0.523 ;
     RECT  27.036 0.235 27.09 0.523 ;
     RECT  80.82 0.091 81.126 0.523 ;
     RECT  3.708 0.523 5.022 0.571 ;
     RECT  7.272 0.091 7.29 0.571 ;
     RECT  8.424 0.091 8.442 0.571 ;
     RECT  17.676 0.235 17.694 0.571 ;
     RECT  18.468 0.523 19.062 0.571 ;
     RECT  23.58 0.091 23.598 0.571 ;
     RECT  25.164 0.091 25.182 0.571 ;
     RECT  26.532 0.523 27.09 0.571 ;
     RECT  28.296 0.235 28.314 0.571 ;
     RECT  42.48 0.139 42.498 0.571 ;
     RECT  56.88 0.139 59.058 0.571 ;
     RECT  60.804 0.139 60.822 0.571 ;
     RECT  76.176 0.091 76.626 0.571 ;
     RECT  77.436 0.221 79.002 0.571 ;
     RECT  81.9 0.523 81.918 0.571 ;
     RECT  83.988 0.331 84.006 0.571 ;
     RECT  9.648 0.091 9.666 0.619 ;
     RECT  17.676 0.571 19.062 0.619 ;
     RECT  29.16 0.331 29.754 0.619 ;
     RECT  34.596 0.571 34.614 0.619 ;
     RECT  81.9 0.571 82.782 0.619 ;
     RECT  37.188 0.187 41.418 0.667 ;
     RECT  42.156 0.571 42.498 0.667 ;
     RECT  83.736 0.571 84.006 0.667 ;
     RECT  84.852 0.619 84.87 0.667 ;
     RECT  34.128 0.619 34.614 0.715 ;
     RECT  60.768 0.571 60.822 1.051 ;
     RECT  3.06 0.571 8.442 1.099 ;
     RECT  3.024 1.099 8.442 1.147 ;
     RECT  19.908 0.091 19.926 1.147 ;
     RECT  21.528 0.139 22.266 1.147 ;
     RECT  23.22 0.571 23.598 1.147 ;
     RECT  24.912 0.571 25.182 1.147 ;
     RECT  29.16 0.619 29.934 1.147 ;
     RECT  31.5 0.571 31.518 1.147 ;
     RECT  34.128 0.715 34.65 1.147 ;
     RECT  35.964 0.091 35.982 1.147 ;
     RECT  37.188 0.667 42.498 1.147 ;
     RECT  43.74 0.139 44.694 1.147 ;
     RECT  45.936 0.139 46.602 1.147 ;
     RECT  55.8 0.475 55.818 1.147 ;
     RECT  56.88 0.571 59.742 1.147 ;
     RECT  60.696 1.051 60.822 1.147 ;
     RECT  61.956 0.091 63.558 1.147 ;
     RECT  65.124 0.139 65.466 1.147 ;
     RECT  66.348 0.091 67.374 1.147 ;
     RECT  72.144 0.619 72.162 1.147 ;
     RECT  80.496 0.523 81.126 1.147 ;
     RECT  9.648 0.619 10.17 1.195 ;
     RECT  24.732 1.147 25.65 1.195 ;
     RECT  26.532 0.571 28.314 1.195 ;
     RECT  29.16 1.147 31.554 1.195 ;
     RECT  34.128 1.147 36.126 1.195 ;
     RECT  50.904 1.147 50.922 1.195 ;
     RECT  51.732 0.619 51.75 1.195 ;
     RECT  53.604 1.147 53.622 1.195 ;
     RECT  54.36 0.619 54.378 1.195 ;
     RECT  60.696 1.147 65.466 1.195 ;
     RECT  66.348 1.147 67.95 1.195 ;
     RECT  68.724 1.147 69.138 1.195 ;
     RECT  69.984 0.619 70.362 1.195 ;
     RECT  71.424 1.147 73.17 1.195 ;
     RECT  74.52 0.571 75.042 1.195 ;
     RECT  17.424 0.619 19.062 1.243 ;
     RECT  71.424 1.195 75.042 1.243 ;
     RECT  15.588 0.331 15.606 1.675 ;
     RECT  81.9 0.619 82.962 1.675 ;
     RECT  83.736 0.667 84.87 1.675 ;
     RECT  23.22 1.147 23.922 1.723 ;
     RECT  24.732 1.195 28.314 1.723 ;
     RECT  81.9 1.675 84.87 1.723 ;
     RECT  85.608 0.619 85.626 1.723 ;
     RECT  9.648 1.195 10.566 1.771 ;
     RECT  12.636 1.147 12.654 1.771 ;
     RECT  14.256 1.147 14.274 1.771 ;
     RECT  15.588 1.675 15.75 1.771 ;
     RECT  23.22 1.723 28.314 1.771 ;
     RECT  29.16 1.195 31.698 1.771 ;
     RECT  32.652 1.147 32.67 1.771 ;
     RECT  33.552 1.195 36.126 1.771 ;
     RECT  37.188 1.147 46.746 1.771 ;
     RECT  48.204 0.619 48.222 1.771 ;
     RECT  49.032 1.147 49.05 1.771 ;
     RECT  69.984 1.195 70.542 1.771 ;
     RECT  81.9 1.723 85.626 1.904 ;
     RECT  79.956 1.147 81.126 1.921 ;
     RECT  81.9 1.904 84.87 1.921 ;
     RECT  79.956 1.921 84.87 1.993 ;
     RECT  76.176 0.571 79.002 2.065 ;
     RECT  79.74 1.993 84.87 2.065 ;
     RECT  1.944 1.147 1.962 2.101 ;
     RECT  2.808 1.147 8.694 2.101 ;
     RECT  9.648 1.771 13.086 2.101 ;
     RECT  23.22 1.771 46.746 2.101 ;
     RECT  55.44 1.147 59.85 2.101 ;
     RECT  60.696 1.195 69.138 2.101 ;
     RECT  1.944 2.101 13.086 2.129 ;
     RECT  76.176 2.065 84.87 2.129 ;
     RECT  2.376 2.129 13.086 2.143 ;
     RECT  13.968 1.771 16.254 2.143 ;
     RECT  47.664 1.771 48.294 2.191 ;
     RECT  49.032 1.771 49.842 2.191 ;
     RECT  55.44 2.101 69.138 2.191 ;
     RECT  69.984 1.771 70.65 2.191 ;
     RECT  19.8 1.147 22.266 2.227 ;
     RECT  23.22 2.101 46.926 2.227 ;
     RECT  47.664 2.191 49.842 2.227 ;
     RECT  50.904 1.195 52.83 2.227 ;
     RECT  53.604 1.195 54.378 2.227 ;
     RECT  55.44 2.191 70.65 2.227 ;
     RECT  71.424 1.243 75.222 2.227 ;
     RECT  55.332 2.227 75.294 2.299 ;
     RECT  76.176 2.129 84.51 2.299 ;
     RECT  2.376 2.143 16.254 2.371 ;
     RECT  16.992 1.243 19.062 2.371 ;
     RECT  50.904 2.227 54.378 2.371 ;
     RECT  55.332 2.299 84.51 2.371 ;
     RECT  2.376 2.371 19.062 2.605 ;
     RECT  19.8 2.227 49.842 2.605 ;
     RECT  2.376 2.605 49.95 2.641 ;
     RECT  50.904 2.371 84.51 2.641 ;
     RECT  0.792 2.299 0.81 2.669 ;
     RECT  2.376 2.641 84.51 2.875 ;
     RECT  2.376 2.875 84.546 2.911 ;
     RECT  2.304 2.911 84.546 3.065 ;
     RECT  2.304 3.065 84.474 3.403 ;
     RECT  2.232 3.403 84.474 3.479 ;
     RECT  85.608 1.904 85.626 3.749 ;
     RECT  2.304 3.479 84.474 4.649 ;
     RECT  2.304 4.649 84.402 8.879 ;
     RECT  2.304 8.879 84.258 13.469 ;
     RECT  2.415 13.469 84.258 23.729 ;
     RECT  2.415 23.729 84.114 23.999 ;
     RECT  2.415 23.999 83.697 29.759 ;
     RECT  2.415 29.759 31.086 31.649 ;
     RECT  2.415 31.649 30.978 32.225 ;
     RECT  27.432 32.225 30.978 33.313 ;
     RECT  27.432 33.313 31.014 33.413 ;
     RECT  2.415 32.225 26.658 34.267 ;
     RECT  27.432 33.413 30.978 34.267 ;
     RECT  2.415 34.267 30.978 34.349 ;
     RECT  27.432 34.349 30.978 36.481 ;
     RECT  31.932 29.759 83.697 36.481 ;
     RECT  2.415 34.349 26.658 36.859 ;
     RECT  27.432 36.481 83.697 36.859 ;
     RECT  2.415 36.859 83.697 40.559 ;
     RECT  53.964 40.559 83.697 41.549 ;
     RECT  2.415 40.559 53.226 42.187 ;
     RECT  53.964 41.549 54.522 42.187 ;
     RECT  2.415 42.187 54.522 42.827 ;
     RECT  55.26 41.549 83.697 42.827 ;
     RECT  2.415 42.827 53.19 44.141 ;
     RECT  55.296 42.827 83.697 44.753 ;
     RECT  23.688 44.141 53.19 45.301 ;
     RECT  53.964 42.827 54.522 45.301 ;
     RECT  75.6 44.753 83.697 46.651 ;
     RECT  75.456 46.651 83.697 46.679 ;
     RECT  2.415 44.141 22.95 47.317 ;
     RECT  23.688 45.301 54.522 47.317 ;
     RECT  2.415 47.317 54.522 47.921 ;
     RECT  75.456 46.679 80.37 48.619 ;
     RECT  81.18 46.679 83.697 48.619 ;
     RECT  32.976 47.921 54.522 51.871 ;
     RECT  32.976 51.871 54.558 52.591 ;
     RECT  55.296 44.753 74.61 52.591 ;
     RECT  2.415 47.921 32.058 59.269 ;
     RECT  2.415 59.269 32.094 59.729 ;
     RECT  31.932 59.729 32.094 59.809 ;
     RECT  32.976 52.591 74.61 59.809 ;
     RECT  31.932 59.809 74.61 60.691 ;
     RECT  75.456 48.619 83.697 60.691 ;
     RECT  31.932 60.691 83.697 61.321 ;
     RECT  31.932 61.321 84.114 66.659 ;
     RECT  31.932 66.659 76.518 67.171 ;
     RECT  2.415 59.729 30.978 67.559 ;
     RECT  2.415 67.559 4.266 72.031 ;
     RECT  5.04 67.559 30.978 72.031 ;
     RECT  86.22 88.747 86.238 88.877 ;
     RECT  86.292 94.027 86.31 94.253 ;
     RECT  2.415 72.031 30.978 120.749 ;
     RECT  2.415 120.749 9.81 130.469 ;
     RECT  10.548 120.749 30.978 134.539 ;
     RECT  31.824 67.171 76.518 134.539 ;
     RECT  10.548 134.539 76.518 135.053 ;
     RECT  31.824 135.053 76.518 138.955 ;
     RECT  77.256 66.659 84.114 138.955 ;
     RECT  86.364 137.911 86.382 139.867 ;
     RECT  86.292 139.867 86.382 139.901 ;
     RECT  86.292 139.901 86.31 139.997 ;
     RECT  10.548 135.053 30.978 140.999 ;
     RECT  10.548 140.999 30.87 144.239 ;
     RECT  31.824 138.955 84.114 147.749 ;
     RECT  15.084 144.239 30.87 148.019 ;
     RECT  10.548 144.239 14.346 148.675 ;
     RECT  31.824 147.749 44.55 148.675 ;
     RECT  31.68 148.675 44.55 148.945 ;
     RECT  45.324 147.749 84.114 148.945 ;
     RECT  31.68 148.945 84.114 149.369 ;
     RECT  10.512 148.675 14.346 151.033 ;
     RECT  15.084 148.019 16.974 151.033 ;
     RECT  17.784 148.019 30.87 151.375 ;
     RECT  31.68 149.369 53.082 151.375 ;
     RECT  10.512 151.033 16.974 152.995 ;
     RECT  17.784 151.375 53.082 152.995 ;
     RECT  10.512 152.995 53.082 153.535 ;
     RECT  53.856 149.369 84.114 153.535 ;
     RECT  10.512 153.535 84.114 155.039 ;
     RECT  2.415 130.469 9.774 158.395 ;
     RECT  10.512 155.039 84.078 158.395 ;
     RECT  2.415 158.395 84.078 177.601 ;
     RECT  2.376 177.601 84.078 178.915 ;
     RECT  2.34 178.915 84.078 179.455 ;
     RECT  2.304 179.455 84.078 179.725 ;
     RECT  2.268 179.725 84.078 179.789 ;
     RECT  2.304 179.789 84.078 180.535 ;
     RECT  2.268 180.535 84.078 180.689 ;
     RECT  2.268 180.689 83.97 181.229 ;
     RECT  1.116 180.841 1.134 181.237 ;
     RECT  2.268 181.229 83.862 181.237 ;
     RECT  1.08 181.237 1.134 181.277 ;
     RECT  2.232 181.237 83.862 181.277 ;
     RECT  2.232 181.277 9.27 181.373 ;
     RECT  2.415 181.373 9.27 181.457 ;
     RECT  13.215 181.277 13.374 181.457 ;
     RECT  18.615 181.277 30.942 181.457 ;
     RECT  18.864 181.457 30.942 181.517 ;
     RECT  72.18 181.277 72.774 181.565 ;
     RECT  13.356 181.457 13.374 181.613 ;
     RECT  18.864 181.517 29.394 181.613 ;
     RECT  15.048 181.277 15.714 181.757 ;
     RECT  16.92 181.277 17.766 181.757 ;
     RECT  18.864 181.613 28.89 181.757 ;
     RECT  30.276 181.517 30.942 181.757 ;
     RECT  32.328 181.277 32.994 181.757 ;
     RECT  34.38 181.277 35.586 181.757 ;
     RECT  47.88 181.277 47.898 181.757 ;
     RECT  48.636 181.277 48.654 181.757 ;
     RECT  49.608 181.277 51.282 181.757 ;
     RECT  52.308 181.277 52.326 181.757 ;
     RECT  53.712 181.277 53.73 181.757 ;
     RECT  67.176 181.277 67.554 181.757 ;
     RECT  69.588 181.277 69.606 181.757 ;
     RECT  71.316 181.277 71.334 181.757 ;
     RECT  72.18 181.565 72.198 181.757 ;
     RECT  74.232 181.277 74.25 181.757 ;
     RECT  84.888 181.111 84.906 181.757 ;
     RECT  85.896 181.039 85.914 181.757 ;
     RECT  1.116 181.277 1.134 181.853 ;
     RECT  2.556 181.457 9.27 181.853 ;
     RECT  16.92 181.757 16.938 181.853 ;
     RECT  18.864 181.757 28.494 181.853 ;
     RECT  36.468 181.277 46.746 181.853 ;
     RECT  51.264 181.757 51.282 181.853 ;
     RECT  56.376 181.277 65.502 181.853 ;
     RECT  75.132 181.277 83.862 181.853 ;
     RECT  2.808 181.853 2.826 181.901 ;
     RECT  6.3 181.853 6.318 182.381 ;
     RECT  7.164 181.853 7.182 182.381 ;
     RECT  19.152 181.853 19.17 182.381 ;
     RECT  21.204 181.853 21.222 182.381 ;
     RECT  23.58 181.853 23.598 182.381 ;
     RECT  24.444 181.853 24.462 182.381 ;
     RECT  25.308 181.853 26.514 182.381 ;
     RECT  27.36 181.853 27.378 182.381 ;
     RECT  39.348 181.853 40.014 182.381 ;
     RECT  40.86 181.853 40.878 182.381 ;
     RECT  41.724 181.853 41.742 182.381 ;
     RECT  42.588 181.853 43.794 182.381 ;
     RECT  58.14 181.853 58.158 182.381 ;
     RECT  59.004 181.853 59.274 182.381 ;
     RECT  75.42 181.853 75.438 182.381 ;
     RECT  76.284 181.853 76.302 182.381 ;
     RECT  78.228 181.853 78.786 182.381 ;
     RECT  79.74 181.853 80.406 182.381 ;
     RECT  81.144 181.853 83.862 182.381 ;
     RECT  82.008 182.381 83.862 182.392 ;
     RECT  26.172 182.381 26.19 182.429 ;
     RECT  59.256 182.381 59.274 182.429 ;
     RECT  82.008 182.392 83.826 182.429 ;
     RECT  5.508 181.853 5.526 182.477 ;
     RECT  60.372 181.853 60.39 182.477 ;
     RECT  82.332 182.429 83.826 182.477 ;
     RECT  3.6 181.853 3.618 182.957 ;
     RECT  82.332 182.477 83.034 182.957 ;
     RECT  83.016 182.957 83.034 183.005 ;
     RECT  83.808 182.477 83.826 183.005 ;
    LAYER M4 ;
     RECT  0.133 180.576 0.709 180.6 ;
     RECT  0.421 181.824 0.709 181.848 ;
     RECT  0.709 180.576 1.145 181.848 ;
     RECT  0.997 7.44 1.285 7.464 ;
     RECT  1.145 180.576 1.285 181.272 ;
     RECT  0.737 2.304 1.333 2.328 ;
     RECT  1.333 2.304 1.621 2.376 ;
     RECT  1.045 0.576 1.889 0.6 ;
     RECT  1.621 1.968 1.889 2.376 ;
     RECT  1.285 6.864 2.149 7.464 ;
     RECT  1.889 0.576 2.293 2.376 ;
     RECT  0.421 14.496 2.293 14.52 ;
     RECT  2.293 0.144 2.329 2.376 ;
     RECT  2.177 3.408 2.329 3.432 ;
     RECT  2.329 0.144 2.408 3.432 ;
     RECT  0.133 5.184 2.408 5.208 ;
     RECT  2.149 6.864 2.408 8.04 ;
     RECT  1.573 11.136 2.408 11.16 ;
     RECT  1.861 13.344 2.408 13.368 ;
     RECT  2.293 14.4 2.408 14.52 ;
     RECT  0.709 16.272 2.408 16.296 ;
     RECT  0.181 19.248 2.408 19.272 ;
     RECT  0.469 21.696 2.408 21.72 ;
     RECT  1.285 179.76 2.408 181.272 ;
     RECT  2.408 0.144 2.485 181.452 ;
     RECT  2.485 0.144 2.704 181.848 ;
     RECT  2.704 181.824 2.753 181.848 ;
     RECT  2.704 178.992 2.819 180.744 ;
     RECT  2.704 14.4 2.837 14.52 ;
     RECT  2.704 25.776 2.867 26.232 ;
     RECT  2.819 178.992 2.867 179.016 ;
     RECT  2.819 180.144 2.867 180.744 ;
     RECT  2.753 181.824 2.87 181.896 ;
     RECT  2.704 0.144 2.873 8.52 ;
     RECT  2.704 21.696 2.873 21.72 ;
     RECT  2.704 29.76 2.953 30.024 ;
     RECT  2.704 39.36 2.963 40.2 ;
     RECT  2.873 8.496 3.059 8.52 ;
     RECT  2.704 11.088 3.161 11.16 ;
     RECT  2.704 12.528 3.233 13.368 ;
     RECT  2.704 32.256 3.251 32.28 ;
     RECT  2.873 0.144 3.377 7.368 ;
     RECT  2.704 34.32 3.436 34.728 ;
     RECT  2.867 180.144 3.436 180.696 ;
     RECT  3.377 1.968 3.443 7.368 ;
     RECT  2.953 29.76 3.443 29.784 ;
     RECT  2.704 37.296 3.443 37.32 ;
     RECT  3.436 34.704 3.457 34.728 ;
     RECT  1.861 182.928 3.629 182.952 ;
     RECT  2.963 39.36 3.635 39.384 ;
     RECT  2.704 42.432 3.635 42.456 ;
     RECT  3.377 0.144 3.737 0.552 ;
     RECT  3.443 1.968 3.779 7.32 ;
     RECT  3.779 6.192 3.827 7.32 ;
     RECT  3.74 27.84 3.827 27.864 ;
     RECT  3.827 6.24 3.881 7.32 ;
     RECT  3.436 180.672 3.971 180.696 ;
     RECT  3.973 24.624 4.06 25.08 ;
     RECT  3.161 11.136 4.169 11.16 ;
     RECT  2.867 26.208 4.241 26.232 ;
     RECT  4.021 21.648 4.349 21.672 ;
     RECT  3.779 1.968 4.364 4.728 ;
     RECT  4.364 1.68 4.451 4.728 ;
     RECT  4.093 44.976 4.547 45 ;
     RECT  4.06 24.624 4.565 24.648 ;
     RECT  3.737 0.528 4.693 0.552 ;
     RECT  4.652 40.272 4.739 40.296 ;
     RECT  2.837 14.496 4.889 14.52 ;
     RECT  4.693 0.528 4.949 0.6 ;
     RECT  3.881 6.24 4.961 6.792 ;
     RECT  4.949 0.096 5.033 0.6 ;
     RECT  4.597 180.144 5.075 180.168 ;
     RECT  4.961 6.24 5.123 6.696 ;
     RECT  5.036 44.544 5.123 44.568 ;
     RECT  5.123 6.672 5.141 6.696 ;
     RECT  5.125 30.192 5.212 30.216 ;
     RECT  4.451 1.968 5.249 4.728 ;
     RECT  2.704 16.272 5.249 16.296 ;
     RECT  5.125 34.848 5.285 34.872 ;
     RECT  5.228 32.256 5.315 32.28 ;
     RECT  5.033 0.576 5.413 0.6 ;
     RECT  5.317 25.68 5.42 25.704 ;
     RECT  2.87 181.824 5.497 181.848 ;
     RECT  5.42 25.44 5.507 25.704 ;
     RECT  5.497 181.824 5.747 182.472 ;
     RECT  5.507 25.68 5.781 25.704 ;
     RECT  5.701 37.296 5.788 37.32 ;
     RECT  5.708 23.232 5.795 23.256 ;
     RECT  5.249 2.256 5.845 4.728 ;
     RECT  5.269 9.696 5.933 9.72 ;
     RECT  5.845 45.408 5.933 45.432 ;
     RECT  5.9 21.36 5.987 21.384 ;
     RECT  5.845 2.256 6.149 4.776 ;
     RECT  6.149 2.88 6.181 4.776 ;
     RECT  6.217 27.888 6.301 28.44 ;
     RECT  5.413 0.576 6.421 0.648 ;
     RECT  6.373 21.408 6.46 21.432 ;
     RECT  6.181 2.88 6.517 5.112 ;
     RECT  6.421 0.576 6.545 1.176 ;
     RECT  6.505 10.224 6.755 10.248 ;
     RECT  6.829 1.68 6.913 1.704 ;
     RECT  6.545 0.576 6.997 0.6 ;
     RECT  6.517 2.88 7.045 5.352 ;
     RECT  7.045 41.088 7.148 41.112 ;
     RECT  5.747 181.824 7.193 182.376 ;
     RECT  7.045 2.88 7.513 6.168 ;
     RECT  7.429 25.584 7.58 25.608 ;
     RECT  6.853 26.736 7.58 26.76 ;
     RECT  7.58 25.584 7.765 26.76 ;
     RECT  7.513 2.148 7.808 6.168 ;
     RECT  3.233 13.344 7.808 13.368 ;
     RECT  2.704 19.248 7.808 19.272 ;
     RECT  7.765 25.2 7.808 26.76 ;
     RECT  7.669 35.328 7.808 35.352 ;
     RECT  7.669 38.064 7.808 38.088 ;
     RECT  7.148 41.088 7.808 41.928 ;
     RECT  7.196 44.784 7.808 44.808 ;
     RECT  7.765 179.472 7.808 179.496 ;
     RECT  7.193 181.824 7.808 181.848 ;
     RECT  7.808 2.148 7.912 181.848 ;
     RECT  7.912 2.256 8.104 181.848 ;
     RECT  8.104 21.456 8.243 21.48 ;
     RECT  8.104 32.304 8.243 32.328 ;
     RECT  8.104 28.416 8.281 28.44 ;
     RECT  8.104 2.256 8.339 3.48 ;
     RECT  8.104 34.992 8.339 35.016 ;
     RECT  6.997 0.096 8.381 0.6 ;
     RECT  8.104 24.24 8.387 25.224 ;
     RECT  8.381 0.096 8.435 0.168 ;
     RECT  8.104 179.472 8.453 179.592 ;
     RECT  8.339 2.832 8.561 3.48 ;
     RECT  8.104 6.768 8.561 6.984 ;
     RECT  8.104 11.424 8.633 11.448 ;
     RECT  8.104 41.28 8.675 41.88 ;
     RECT  8.621 1.152 8.705 1.176 ;
     RECT  8.104 4.512 8.705 5.592 ;
     RECT  8.675 41.856 8.741 41.88 ;
     RECT  9.164 40.176 9.251 40.2 ;
     RECT  8.104 181.824 9.292 181.848 ;
     RECT  8.561 6.864 9.349 6.984 ;
     RECT  8.561 3.408 9.485 3.48 ;
     RECT  8.705 4.512 9.485 4.584 ;
     RECT  9.485 3.408 9.569 4.584 ;
     RECT  9.5 42.336 9.587 42.36 ;
     RECT  9.569 3.408 9.637 3.528 ;
     RECT  8.435 0.096 9.677 0.12 ;
     RECT  9.349 6.864 9.677 7.464 ;
     RECT  9.829 44.88 9.916 44.904 ;
     RECT  9.569 4.56 9.929 4.584 ;
     RECT  9.685 9.696 9.965 9.72 ;
     RECT  9.677 6.864 10.109 6.888 ;
     RECT  9.829 0.624 10.181 0.648 ;
     RECT  9.637 2.88 10.289 3.528 ;
     RECT  10.213 10.272 10.357 10.296 ;
     RECT  10.357 10.272 10.433 10.824 ;
     RECT  10.405 1.776 10.453 1.8 ;
     RECT  10.453 1.2 10.577 1.8 ;
     RECT  10.597 39.6 10.684 39.624 ;
     RECT  8.453 179.568 10.721 179.592 ;
     RECT  10.289 3.504 10.757 3.528 ;
     RECT  10.573 29.424 10.835 29.448 ;
     RECT  10.609 33.264 10.835 33.288 ;
     RECT  10.433 10.32 10.873 10.824 ;
     RECT  10.837 179.616 10.924 179.64 ;
     RECT  10.837 36.048 10.973 36.072 ;
     RECT  10.988 22.416 11.075 22.44 ;
     RECT  10.997 7.44 11.081 7.464 ;
     RECT  10.577 1.776 11.249 1.8 ;
     RECT  11.249 1.776 11.333 1.848 ;
     RECT  11.269 6.192 11.356 6.216 ;
     RECT  10.873 10.8 11.393 10.824 ;
     RECT  11.365 27.312 11.449 27.336 ;
     RECT  11.393 10.8 11.477 10.872 ;
     RECT  11.605 24.768 11.692 24.792 ;
     RECT  11.257 4.272 11.852 4.296 ;
     RECT  11.477 10.8 11.909 10.824 ;
     RECT  11.852 3.408 11.981 4.296 ;
     RECT  11.981 3.408 11.989 3.864 ;
     RECT  11.977 9.168 12.061 9.192 ;
     RECT  11.996 6.432 12.083 6.456 ;
     RECT  11.333 1.776 12.229 1.8 ;
     RECT  11.989 2.976 12.229 3.864 ;
     RECT  12.229 1.152 12.665 1.8 ;
     RECT  12.517 7.968 12.757 7.992 ;
     RECT  12.229 2.88 12.997 3.864 ;
     RECT  12.757 7.968 13.021 8.76 ;
     RECT  12.445 179.184 13.057 179.208 ;
     RECT  13.093 5.568 13.201 5.592 ;
     RECT  12.665 1.776 13.208 1.8 ;
     RECT  12.997 2.88 13.208 4.008 ;
     RECT  13.201 5.184 13.208 5.592 ;
     RECT  13.021 7.44 13.208 8.76 ;
     RECT  12.517 11.424 13.208 11.448 ;
     RECT  12.193 14.832 13.208 14.856 ;
     RECT  8.104 19.248 13.208 19.272 ;
     RECT  12.277 21.36 13.208 21.384 ;
     RECT  13.052 27.84 13.208 27.864 ;
     RECT  12.38 32.736 13.208 32.76 ;
     RECT  12.913 35.952 13.208 35.976 ;
     RECT  13.057 179.184 13.208 180.168 ;
     RECT  9.493 181.248 13.208 181.272 ;
     RECT  13.208 1.776 13.333 181.452 ;
     RECT  13.333 1.776 13.42 181.608 ;
     RECT  13.42 1.776 13.504 181.272 ;
     RECT  13.504 2.88 13.529 6.36 ;
     RECT  13.529 3.936 13.619 6.36 ;
     RECT  13.619 3.936 13.645 6.264 ;
     RECT  13.645 3.936 13.667 6.12 ;
     RECT  13.504 11.616 13.667 11.64 ;
     RECT  13.529 2.88 13.745 2.904 ;
     RECT  13.504 30.336 13.9 30.36 ;
     RECT  13.504 180.144 13.925 180.168 ;
     RECT  13.504 1.776 13.957 1.8 ;
     RECT  13.504 39.648 14.243 39.672 ;
     RECT  13.667 3.936 14.249 5.256 ;
     RECT  13.957 1.152 14.285 1.8 ;
     RECT  13.504 35.952 14.339 35.976 ;
     RECT  13.504 9.168 14.537 9.72 ;
     RECT  14.249 3.936 14.573 3.96 ;
     RECT  14.537 9.168 14.609 9.192 ;
     RECT  13.504 34.848 14.749 34.872 ;
     RECT  13.504 24.864 14.819 24.888 ;
     RECT  14.641 42.624 14.819 42.648 ;
     RECT  13.504 181.248 14.819 181.272 ;
     RECT  14.749 34.848 14.821 34.92 ;
     RECT  14.741 13.104 14.825 13.128 ;
     RECT  14.249 5.04 14.897 5.064 ;
     RECT  14.285 1.776 15.001 1.8 ;
     RECT  14.821 2.88 15.001 2.904 ;
     RECT  14.821 34.8 15.257 34.92 ;
     RECT  15.061 8.736 15.293 8.76 ;
     RECT  15.037 20.304 15.395 20.328 ;
     RECT  15.317 3.984 15.401 4.008 ;
     RECT  15.397 34.656 15.545 34.68 ;
     RECT  15.577 0.336 15.661 0.36 ;
     RECT  15.605 19.968 15.689 19.992 ;
     RECT  15.001 1.776 15.692 2.904 ;
     RECT  15.644 22.704 15.731 22.728 ;
     RECT  14.993 181.728 15.769 181.752 ;
     RECT  15.692 1.68 15.779 2.904 ;
     RECT  14.569 179.328 15.833 179.352 ;
     RECT  15.788 36.144 15.875 36.168 ;
     RECT  15.884 40.272 15.901 40.296 ;
     RECT  15.901 40.128 15.971 40.296 ;
     RECT  15.577 5.136 16.013 5.4 ;
     RECT  15.932 38.016 16.019 38.04 ;
     RECT  15.971 40.128 16.085 40.152 ;
     RECT  15.779 1.776 16.265 2.904 ;
     RECT  16.265 2.64 16.373 2.904 ;
     RECT  16.213 9.744 16.373 9.768 ;
     RECT  16.289 13.104 16.373 13.128 ;
     RECT  15.973 44.496 16.409 44.52 ;
     RECT  16.081 31.392 16.547 31.416 ;
     RECT  16.373 2.832 16.577 2.904 ;
     RECT  16.577 2.832 16.597 2.952 ;
     RECT  16.597 2.832 16.645 3.528 ;
     RECT  16.645 2.832 16.661 4.344 ;
     RECT  16.549 27.936 16.661 27.96 ;
     RECT  16.597 25.104 16.697 25.128 ;
     RECT  16.661 3.36 16.732 4.344 ;
     RECT  16.741 22.704 16.828 22.728 ;
     RECT  16.789 29.376 16.876 29.4 ;
     RECT  15.925 181.248 16.892 181.272 ;
     RECT  16.892 181.248 16.979 181.848 ;
     RECT  16.837 1.248 17.021 1.272 ;
     RECT  16.933 20.304 17.021 20.328 ;
     RECT  16.979 181.248 17.021 181.752 ;
     RECT  16.513 180.24 17.381 180.264 ;
     RECT  17.365 2.352 17.525 2.376 ;
     RECT  17.493 24.816 17.603 25.08 ;
     RECT  17.173 0.624 17.621 0.648 ;
     RECT  17.621 0.24 17.705 0.648 ;
     RECT  17.021 181.728 17.821 181.752 ;
     RECT  17.705 0.528 18.325 0.648 ;
     RECT  16.732 3.36 18.325 4.008 ;
     RECT  18.325 0.528 18.515 1.224 ;
     RECT  18.515 1.104 18.605 1.224 ;
     RECT  18.325 2.784 18.608 4.008 ;
     RECT  16.621 5.424 18.608 5.448 ;
     RECT  18.421 6.768 18.608 6.792 ;
     RECT  17.941 7.968 18.608 7.992 ;
     RECT  18.565 12.048 18.608 12.072 ;
     RECT  18.313 19.968 18.608 19.992 ;
     RECT  17.603 24.816 18.608 24.84 ;
     RECT  18.373 27.888 18.608 27.912 ;
     RECT  18.277 33.024 18.608 33.048 ;
     RECT  17.653 39.888 18.608 39.912 ;
     RECT  18.469 42.528 18.608 42.552 ;
     RECT  17.701 179.568 18.608 180.024 ;
     RECT  18.037 181.248 18.608 181.452 ;
     RECT  18.608 2.148 18.712 181.452 ;
     RECT  18.605 1.104 18.803 1.128 ;
     RECT  18.712 2.418 18.812 181.452 ;
     RECT  18.812 2.418 18.904 181.848 ;
     RECT  18.904 14.736 19.001 14.76 ;
     RECT  18.904 11.952 19.037 11.976 ;
     RECT  18.904 29.664 19.043 29.688 ;
     RECT  18.904 6.624 19.109 7.464 ;
     RECT  18.904 24.816 19.139 25.56 ;
     RECT  18.904 181.824 19.141 181.848 ;
     RECT  18.904 33.504 19.187 33.528 ;
     RECT  19.109 6.624 19.217 6.648 ;
     RECT  19.141 181.824 19.225 182.376 ;
     RECT  18.904 41.952 19.325 42.888 ;
     RECT  18.904 36.336 19.379 36.36 ;
     RECT  19.139 25.152 19.397 25.56 ;
     RECT  19.325 42.768 19.397 42.888 ;
     RECT  18.904 2.64 19.577 3.432 ;
     RECT  18.904 23.232 19.619 23.256 ;
     RECT  19.397 25.152 19.649 25.176 ;
     RECT  18.904 20.736 19.757 20.76 ;
     RECT  18.853 0.096 19.937 0.12 ;
     RECT  19.397 42.768 20.117 42.792 ;
     RECT  19.909 4.56 20.153 4.584 ;
     RECT  19.577 2.64 20.197 2.904 ;
     RECT  20.197 2.304 20.297 2.904 ;
     RECT  20.293 36.48 20.38 36.504 ;
     RECT  20.485 13.68 20.585 13.704 ;
     RECT  20.588 30.816 20.675 30.84 ;
     RECT  20.533 4.128 20.909 4.536 ;
     RECT  18.904 180 20.909 180.024 ;
     RECT  20.297 2.88 20.917 2.904 ;
     RECT  19.745 1.152 21.089 1.176 ;
     RECT  20.977 39.84 21.107 39.864 ;
     RECT  21.049 12.528 21.133 12.552 ;
     RECT  19.225 181.824 21.193 181.848 ;
     RECT  20.917 2.88 21.233 2.952 ;
     RECT  21.193 181.824 21.277 182.376 ;
     RECT  21.205 0.096 21.349 0.12 ;
     RECT  21.277 181.824 21.493 181.848 ;
     RECT  20.909 4.512 21.625 4.536 ;
     RECT  21.541 20.832 21.628 20.856 ;
     RECT  21.349 0.096 21.629 0.6 ;
     RECT  20.773 6.864 21.637 6.888 ;
     RECT  21.637 6.864 21.665 6.936 ;
     RECT  21.493 181.248 21.701 181.848 ;
     RECT  21.733 25.536 21.82 25.56 ;
     RECT  21.233 2.88 21.844 2.904 ;
     RECT  21.844 2.832 22.021 2.904 ;
     RECT  21.629 0.096 22.169 0.168 ;
     RECT  22.165 28.416 22.249 28.44 ;
     RECT  22.169 0.144 22.277 0.168 ;
     RECT  21.625 4.512 22.313 5.208 ;
     RECT  21.665 6.912 22.313 6.936 ;
     RECT  22.268 34.752 22.355 34.776 ;
     RECT  22.021 2.64 22.405 2.904 ;
     RECT  22.313 4.56 22.525 5.208 ;
     RECT  22.405 2.304 22.637 2.904 ;
     RECT  22.604 34.56 22.691 34.584 ;
     RECT  22.525 4.56 22.709 5.88 ;
     RECT  22.381 42.192 22.787 42.216 ;
     RECT  22.892 33.264 22.979 33.288 ;
     RECT  22.637 2.304 23.033 2.376 ;
     RECT  22.921 179.184 23.245 179.208 ;
     RECT  22.981 0.576 23.365 0.6 ;
     RECT  22.693 3.408 23.509 3.432 ;
     RECT  22.709 4.56 23.509 4.728 ;
     RECT  21.701 181.824 23.525 181.848 ;
     RECT  23.365 0.096 23.557 0.6 ;
     RECT  23.557 0.096 23.609 1.176 ;
     RECT  23.509 40.56 23.653 40.584 ;
     RECT  23.365 36.912 23.929 36.936 ;
     RECT  23.509 3.408 23.965 4.728 ;
     RECT  22.709 5.856 23.965 5.88 ;
     RECT  23.033 2.352 24.008 2.376 ;
     RECT  23.965 3.408 24.008 5.88 ;
     RECT  23.929 7.392 24.008 7.416 ;
     RECT  23.713 12 24.008 12.024 ;
     RECT  23.42 24.912 24.008 24.936 ;
     RECT  23.857 32.784 24.008 32.808 ;
     RECT  23.893 35.712 24.008 35.736 ;
     RECT  23.929 36.816 24.008 36.936 ;
     RECT  23.653 40.272 24.008 40.584 ;
     RECT  23.245 179.184 24.008 180.168 ;
     RECT  23.525 181.824 24.008 182.376 ;
     RECT  23.609 0.144 24.229 1.176 ;
     RECT  24.008 2.148 24.229 182.376 ;
     RECT  24.229 0.144 24.304 182.376 ;
     RECT  24.304 0.144 24.365 5.112 ;
     RECT  24.304 22.32 24.419 22.44 ;
     RECT  24.304 30.432 24.419 30.456 ;
     RECT  24.365 0.144 24.437 1.752 ;
     RECT  24.304 36.912 24.467 36.936 ;
     RECT  24.304 27.888 24.473 27.912 ;
     RECT  24.365 2.832 24.481 5.112 ;
     RECT  24.304 6.816 24.515 7.416 ;
     RECT  24.304 179.568 24.515 180.168 ;
     RECT  24.304 20.448 24.617 20.472 ;
     RECT  24.515 180.144 24.869 180.168 ;
     RECT  24.437 0.144 24.941 1.176 ;
     RECT  24.304 33.264 25.013 33.288 ;
     RECT  24.515 6.816 25.036 6.84 ;
     RECT  24.304 35.616 25.049 35.784 ;
     RECT  25.093 0.096 25.193 0.12 ;
     RECT  25.049 35.616 25.228 35.64 ;
     RECT  24.481 2.832 25.445 5.064 ;
     RECT  25.297 9.552 25.589 9.576 ;
     RECT  24.419 22.416 25.619 22.44 ;
     RECT  24.941 1.152 25.66 1.176 ;
     RECT  24.304 38.496 25.661 38.52 ;
     RECT  25.513 43.824 25.667 43.848 ;
     RECT  25.445 2.88 25.693 5.064 ;
     RECT  25.66 1.152 25.877 1.224 ;
     RECT  26.053 26.112 26.14 26.136 ;
     RECT  24.304 181.824 26.156 182.376 ;
     RECT  26.108 30.48 26.195 30.504 ;
     RECT  26.156 181.824 26.243 182.424 ;
     RECT  26.161 6.768 26.345 6.792 ;
     RECT  25.981 38.736 26.453 38.76 ;
     RECT  25.693 2.88 26.485 5.352 ;
     RECT  26.197 0.576 26.492 0.6 ;
     RECT  26.492 0.528 26.633 0.6 ;
     RECT  26.521 179.184 27.061 179.208 ;
     RECT  26.773 0.144 27.101 0.264 ;
     RECT  26.485 2.304 27.137 5.352 ;
     RECT  27.061 179.184 27.173 180.168 ;
     RECT  27.164 26.592 27.205 26.616 ;
     RECT  27.205 26.592 27.251 26.712 ;
     RECT  27.251 26.688 27.292 26.712 ;
     RECT  27.137 2.64 27.317 5.352 ;
     RECT  27.173 180.144 27.317 180.168 ;
     RECT  27.269 34.272 27.353 34.296 ;
     RECT  27.317 2.64 27.389 4.584 ;
     RECT  26.243 181.824 27.433 182.376 ;
     RECT  27.389 2.64 27.605 4.392 ;
     RECT  27.605 4.224 27.713 4.392 ;
     RECT  27.74 44.544 27.827 44.568 ;
     RECT  27.713 4.368 27.875 4.392 ;
     RECT  27.745 36.96 27.923 36.984 ;
     RECT  27.637 0.576 27.925 0.6 ;
     RECT  27.457 23.328 27.965 23.352 ;
     RECT  27.925 7.968 28.073 7.992 ;
     RECT  27.925 0.576 28.145 1.176 ;
     RECT  27.433 181.824 28.213 181.848 ;
     RECT  27.605 2.64 28.261 3.096 ;
     RECT  28.241 0.24 28.325 0.36 ;
     RECT  28.261 1.776 28.469 3.096 ;
     RECT  28.213 181.248 28.54 181.848 ;
     RECT  28.54 181.248 28.901 181.752 ;
     RECT  28.469 2.148 28.933 3.096 ;
     RECT  28.885 4.56 28.933 4.584 ;
     RECT  28.46 42.96 28.969 42.984 ;
     RECT  26.773 40.464 29.077 40.488 ;
     RECT  28.748 26.448 29.185 26.472 ;
     RECT  28.325 0.336 29.221 0.36 ;
     RECT  28.933 2.148 29.269 4.584 ;
     RECT  29.113 6.576 29.269 6.6 ;
     RECT  29.221 0.336 29.365 0.648 ;
     RECT  29.269 2.148 29.408 6.6 ;
     RECT  29.036 21.648 29.408 21.672 ;
     RECT  29.185 26.448 29.408 26.808 ;
     RECT  28.997 28.992 29.408 29.016 ;
     RECT  29.077 40.176 29.408 40.488 ;
     RECT  28.969 42.96 29.408 43.32 ;
     RECT  28.753 179.376 29.408 179.4 ;
     RECT  28.901 181.248 29.408 181.608 ;
     RECT  29.365 0.336 29.681 0.696 ;
     RECT  29.408 2.148 29.704 181.608 ;
     RECT  29.681 0.24 29.765 0.696 ;
     RECT  29.704 32.976 29.843 33 ;
     RECT  29.704 34.368 29.843 34.392 ;
     RECT  29.704 27.216 29.884 27.24 ;
     RECT  29.704 40.56 29.939 40.584 ;
     RECT  29.765 0.624 29.945 0.696 ;
     RECT  29.704 2.148 30.025 5.928 ;
     RECT  29.704 38.928 30.131 39.192 ;
     RECT  29.704 19.872 30.179 19.992 ;
     RECT  29.704 21.648 30.227 21.672 ;
     RECT  29.704 181.248 30.265 181.608 ;
     RECT  29.704 24.096 30.364 24.12 ;
     RECT  30.037 1.152 30.373 1.176 ;
     RECT  29.704 10.8 30.413 10.824 ;
     RECT  29.704 36.912 30.413 36.936 ;
     RECT  29.704 28.848 30.565 29.016 ;
     RECT  30.025 3.312 30.659 5.928 ;
     RECT  30.179 19.968 30.709 19.992 ;
     RECT  30.659 3.312 30.72 5.064 ;
     RECT  29.704 22.8 30.737 22.824 ;
     RECT  30.72 3.312 30.748 4.584 ;
     RECT  30.748 3.408 30.845 4.584 ;
     RECT  30.565 28.848 30.881 28.872 ;
     RECT  30.805 43.776 30.889 43.8 ;
     RECT  30.265 181.248 30.953 181.752 ;
     RECT  30.841 26.832 30.989 26.856 ;
     RECT  29.704 179.376 31.196 179.4 ;
     RECT  31.196 179.376 31.283 179.592 ;
     RECT  31.273 134.544 31.357 134.568 ;
     RECT  31.34 7.488 31.427 7.656 ;
     RECT  30.373 1.152 31.429 1.8 ;
     RECT  31.429 0.576 31.529 1.8 ;
     RECT  31.589 135.024 31.673 135.048 ;
     RECT  31.621 38.736 31.708 38.76 ;
     RECT  30.845 3.408 32.005 3.432 ;
     RECT  32.005 3.408 32.033 3.528 ;
     RECT  30.953 181.248 32.099 181.272 ;
     RECT  31.909 25.44 32.141 25.464 ;
     RECT  32.245 6.768 32.357 6.792 ;
     RECT  31.909 35.952 32.393 35.976 ;
     RECT  32.453 27.84 32.537 27.864 ;
     RECT  32.389 6 32.677 6.024 ;
     RECT  31.529 1.152 32.681 1.8 ;
     RECT  32.677 5.664 32.771 6.024 ;
     RECT  32.485 43.68 32.897 43.704 ;
     RECT  32.821 21.12 32.908 21.144 ;
     RECT  32.681 1.2 33.049 1.8 ;
     RECT  32.273 181.728 33.049 181.752 ;
     RECT  32.993 31.872 33.077 31.896 ;
     RECT  32.771 6 33.437 6.024 ;
     RECT  33.061 22.704 33.437 22.728 ;
     RECT  33.461 112.272 33.544 112.296 ;
     RECT  33.544 112.272 33.545 112.344 ;
     RECT  33.049 1.2 33.581 1.224 ;
     RECT  32.033 3.504 33.605 3.528 ;
     RECT  33.548 40.992 33.635 41.016 ;
     RECT  33.545 112.32 33.661 112.344 ;
     RECT  33.605 2.88 33.689 3.528 ;
     RECT  30.845 4.56 33.793 4.584 ;
     RECT  33.793 4.512 33.925 4.584 ;
     RECT  33.689 3.504 34.225 3.528 ;
     RECT  33.925 4.512 34.225 4.68 ;
     RECT  34.225 3.504 34.309 4.68 ;
     RECT  33.253 181.248 34.325 181.272 ;
     RECT  33.733 0.624 34.405 1.176 ;
     RECT  34.405 0.576 34.625 1.176 ;
     RECT  34.625 0.72 34.661 1.176 ;
     RECT  31.283 179.376 34.693 179.4 ;
     RECT  34.309 3.504 34.808 5.16 ;
     RECT  34.652 6.816 34.808 6.84 ;
     RECT  33.925 20.16 34.808 20.184 ;
     RECT  34.549 25.104 34.808 25.128 ;
     RECT  34.508 30.192 34.808 30.216 ;
     RECT  34.693 179.376 34.808 179.496 ;
     RECT  34.325 181.248 34.808 181.752 ;
     RECT  34.661 1.152 34.885 1.176 ;
     RECT  34.808 2.148 34.885 181.752 ;
     RECT  34.885 1.152 35.104 181.752 ;
     RECT  35.104 10.08 35.201 10.104 ;
     RECT  35.104 36.24 35.219 36.264 ;
     RECT  35.104 2.832 35.26 4.008 ;
     RECT  35.104 1.152 35.273 1.8 ;
     RECT  35.104 33.792 35.308 33.816 ;
     RECT  35.104 38.4 35.5 38.712 ;
     RECT  35.26 2.832 35.921 3.432 ;
     RECT  35.921 2.832 35.965 2.952 ;
     RECT  35.104 6.768 35.993 6.792 ;
     RECT  35.953 0.096 36.037 0.12 ;
     RECT  35.273 1.152 36.137 1.224 ;
     RECT  35.5 38.64 36.137 38.712 ;
     RECT  36.137 38.688 36.209 38.712 ;
     RECT  35.104 5.184 36.325 5.208 ;
     RECT  36.325 4.56 36.353 5.208 ;
     RECT  36.277 24.096 36.364 24.12 ;
     RECT  35.104 181.248 36.421 181.752 ;
     RECT  36.373 21.12 36.461 21.144 ;
     RECT  36.353 4.56 36.613 4.632 ;
     RECT  36.613 4.08 36.749 4.632 ;
     RECT  36.709 28.992 36.793 29.016 ;
     RECT  36.709 31.968 36.793 31.992 ;
     RECT  36.709 41.184 36.805 41.208 ;
     RECT  36.805 41.136 36.893 41.208 ;
     RECT  36.749 4.56 36.899 4.632 ;
     RECT  36.893 41.184 37.001 41.208 ;
     RECT  35.104 179.472 37.001 179.496 ;
     RECT  36.949 6.384 37.037 6.408 ;
     RECT  36.517 1.776 37.289 1.8 ;
     RECT  35.965 2.832 37.313 2.904 ;
     RECT  36.421 181.248 37.379 181.848 ;
     RECT  37.525 37.584 37.612 37.608 ;
     RECT  37.621 27.648 37.708 27.672 ;
     RECT  37.133 0.096 37.717 0.12 ;
     RECT  37.313 2.832 37.717 3.528 ;
     RECT  36.899 4.56 37.717 4.584 ;
     RECT  37.717 2.832 37.721 4.584 ;
     RECT  37.813 34.896 37.901 34.92 ;
     RECT  38.053 179.616 38.14 179.64 ;
     RECT  38.005 4.896 38.149 4.92 ;
     RECT  37.957 36.672 38.333 36.696 ;
     RECT  38.3 40.224 38.387 40.248 ;
     RECT  37.721 2.832 38.405 3.624 ;
     RECT  38.149 4.896 38.405 5.736 ;
     RECT  38.293 1.728 38.473 1.752 ;
     RECT  38.405 2.832 38.473 3.576 ;
     RECT  38.405 4.992 38.621 5.736 ;
     RECT  38.473 1.728 38.657 3.576 ;
     RECT  38.657 2.496 38.801 3.576 ;
     RECT  38.621 4.992 38.801 5.064 ;
     RECT  38.761 22.704 38.845 22.728 ;
     RECT  38.581 6.864 38.873 6.888 ;
     RECT  39.109 26.448 39.197 26.472 ;
     RECT  37.379 181.824 39.337 181.848 ;
     RECT  38.801 2.496 39.625 2.952 ;
     RECT  37.717 0.096 39.685 0.168 ;
     RECT  38.801 4.992 39.788 5.016 ;
     RECT  39.625 2.256 39.805 2.952 ;
     RECT  39.685 0.096 39.809 0.216 ;
     RECT  39.829 25.392 39.841 25.416 ;
     RECT  39.229 179.808 39.949 179.832 ;
     RECT  39.809 0.144 39.973 0.216 ;
     RECT  39.805 2.256 39.973 3.432 ;
     RECT  39.788 4.992 39.973 5.592 ;
     RECT  39.973 0.144 40.013 0.312 ;
     RECT  39.973 2.256 40.208 5.592 ;
     RECT  39.841 25.392 40.208 26.328 ;
     RECT  39.932 28.32 40.208 28.344 ;
     RECT  39.589 31.296 40.208 31.32 ;
     RECT  40.069 34.464 40.208 34.488 ;
     RECT  40.069 37.584 40.208 37.608 ;
     RECT  39.769 40.368 40.208 40.392 ;
     RECT  39.949 179.808 40.208 180.024 ;
     RECT  39.337 181.824 40.208 182.376 ;
     RECT  40.208 2.148 40.312 182.376 ;
     RECT  40.312 2.304 40.504 182.376 ;
     RECT  40.013 0.144 40.597 0.6 ;
     RECT  40.504 2.304 40.645 6.888 ;
     RECT  40.645 2.304 40.684 5.736 ;
     RECT  40.597 0.144 40.889 1.176 ;
     RECT  40.684 5.712 40.997 5.736 ;
     RECT  40.684 2.304 41.069 4.536 ;
     RECT  40.504 180 41.429 180.024 ;
     RECT  40.504 41.136 41.537 41.16 ;
     RECT  41.069 2.88 41.573 4.536 ;
     RECT  41.573 4.512 41.645 4.536 ;
     RECT  40.645 6.864 41.645 6.888 ;
     RECT  41.9 28.8 41.987 28.824 ;
     RECT  41.929 31.392 42.013 31.416 ;
     RECT  40.889 0.144 42.185 0.696 ;
     RECT  42.101 57.552 42.185 57.576 ;
     RECT  42.133 25.872 42.22 25.896 ;
     RECT  42.173 22.656 42.257 22.68 ;
     RECT  42.109 37.68 42.365 37.704 ;
     RECT  42.185 0.144 42.509 0.168 ;
     RECT  42.469 19.92 42.553 19.944 ;
     RECT  42.325 23.376 42.755 23.4 ;
     RECT  41.573 2.88 42.797 3.432 ;
     RECT  42.037 4.56 42.833 4.584 ;
     RECT  42.829 91.824 42.913 91.848 ;
     RECT  43.148 92.016 43.235 92.04 ;
     RECT  42.797 2.88 43.373 2.904 ;
     RECT  42.893 10.848 43.373 10.872 ;
     RECT  42.181 180.144 43.373 180.168 ;
     RECT  43.436 42.288 43.523 42.312 ;
     RECT  43.693 57.312 43.777 57.336 ;
     RECT  43.724 27.888 43.811 27.912 ;
     RECT  43.757 9.696 43.841 9.72 ;
     RECT  40.504 181.824 43.849 182.376 ;
     RECT  43.868 4.272 43.945 4.296 ;
     RECT  43.945 4.272 43.955 4.68 ;
     RECT  42.641 1.152 44.053 1.176 ;
     RECT  44.156 41.424 44.243 41.448 ;
     RECT  43.801 2.832 44.449 2.856 ;
     RECT  44.341 6.864 44.489 6.888 ;
     RECT  43.525 0.144 44.705 0.168 ;
     RECT  44.449 2.736 44.809 2.856 ;
     RECT  44.053 1.152 45.029 1.752 ;
     RECT  44.809 2.736 45.205 2.904 ;
     RECT  45.205 2.148 45.253 2.904 ;
     RECT  43.849 181.824 45.541 181.848 ;
     RECT  45.253 2.148 45.608 3.096 ;
     RECT  43.955 4.656 45.608 4.68 ;
     RECT  45.485 11.424 45.608 11.448 ;
     RECT  45.601 20.592 45.608 20.952 ;
     RECT  45.404 25.44 45.608 25.464 ;
     RECT  44.588 30.72 45.608 30.744 ;
     RECT  44.701 36.48 45.608 36.504 ;
     RECT  45.413 38.832 45.608 38.856 ;
     RECT  44.437 178.56 45.608 178.584 ;
     RECT  45.541 181.584 45.608 181.848 ;
     RECT  45.608 2.148 45.712 181.848 ;
     RECT  45.029 1.152 45.781 1.176 ;
     RECT  45.781 0.24 45.829 1.176 ;
     RECT  45.712 2.418 45.904 181.848 ;
     RECT  45.829 0.144 46.073 1.176 ;
     RECT  45.904 2.832 46.115 3.432 ;
     RECT  46.115 3.264 46.163 3.432 ;
     RECT  45.904 20.592 46.163 20.952 ;
     RECT  46.163 3.36 46.181 3.432 ;
     RECT  45.904 7.44 46.189 7.464 ;
     RECT  46.163 20.928 46.361 20.952 ;
     RECT  45.904 10.848 46.433 10.872 ;
     RECT  45.904 123.168 46.541 123.192 ;
     RECT  45.904 42.288 46.547 42.312 ;
     RECT  46.405 0.096 46.613 0.12 ;
     RECT  45.904 23.136 46.636 23.16 ;
     RECT  46.073 1.152 46.757 1.176 ;
     RECT  45.904 4.56 46.757 4.584 ;
     RECT  45.904 181.824 46.757 181.848 ;
     RECT  45.904 36.48 46.873 36.504 ;
     RECT  46.181 3.408 46.925 3.432 ;
     RECT  45.904 28.848 47.189 28.872 ;
     RECT  46.925 3.408 47.293 4.392 ;
     RECT  47.077 5.664 47.315 5.688 ;
     RECT  45.904 34.848 47.315 34.872 ;
     RECT  47.228 123.456 47.315 123.48 ;
     RECT  47.365 1.776 47.509 1.8 ;
     RECT  47.293 2.928 47.509 4.392 ;
     RECT  47.317 31.392 47.513 31.416 ;
     RECT  47.413 26.112 47.653 26.136 ;
     RECT  47.653 25.584 47.737 26.136 ;
     RECT  47.509 1.776 47.789 4.392 ;
     RECT  47.789 1.776 47.843 5.016 ;
     RECT  46.981 181.248 47.869 181.272 ;
     RECT  47.843 4.992 47.873 5.016 ;
     RECT  47.737 26.112 47.873 26.136 ;
     RECT  48.14 20.784 48.227 20.808 ;
     RECT  47.893 0.624 48.233 0.648 ;
     RECT  48.085 6.72 48.233 6.744 ;
     RECT  48.181 38.352 48.467 38.376 ;
     RECT  47.843 1.776 48.469 3.528 ;
     RECT  48.469 1.152 48.521 3.528 ;
     RECT  48.469 9.696 48.701 9.72 ;
     RECT  48.62 42.72 48.707 42.744 ;
     RECT  48.668 40.176 48.755 40.2 ;
     RECT  48.409 5.04 48.953 5.064 ;
     RECT  48.521 2.832 48.989 3.528 ;
     RECT  48.521 1.152 49.061 1.8 ;
     RECT  48.989 2.832 49.097 2.904 ;
     RECT  47.869 181.248 49.379 181.752 ;
     RECT  49.525 33.744 49.612 33.768 ;
     RECT  49.237 11.472 49.637 11.496 ;
     RECT  49.705 3.936 49.811 3.96 ;
     RECT  49.061 1.776 49.853 1.8 ;
     RECT  49.097 2.88 50.137 2.904 ;
     RECT  50.437 37.056 50.461 37.08 ;
     RECT  49.379 181.728 50.485 181.752 ;
     RECT  48.997 7.968 50.629 7.992 ;
     RECT  50.053 9.168 50.629 9.192 ;
     RECT  50.461 37.056 50.713 37.176 ;
     RECT  50.713 42.528 50.725 42.552 ;
     RECT  50.245 1.152 50.821 1.176 ;
     RECT  50.629 7.968 50.869 9.192 ;
     RECT  50.137 2.88 50.965 3.912 ;
     RECT  50.821 1.152 51.008 1.224 ;
     RECT  50.965 2.88 51.008 4.488 ;
     RECT  50.713 5.616 51.008 5.64 ;
     RECT  50.869 7.824 51.008 9.192 ;
     RECT  50.869 12 51.008 12.024 ;
     RECT  50.869 20.736 51.008 20.76 ;
     RECT  49.007 23.184 51.008 23.208 ;
     RECT  50.149 25.968 51.008 25.992 ;
     RECT  50.029 27.984 51.008 28.008 ;
     RECT  49.573 31.872 51.008 31.896 ;
     RECT  50.713 37.056 51.008 37.464 ;
     RECT  50.204 40.272 51.008 40.296 ;
     RECT  50.725 42.528 51.008 42.792 ;
     RECT  50.485 181.248 51.008 181.752 ;
     RECT  51.008 1.152 51.112 181.752 ;
     RECT  51.112 2.418 51.212 181.752 ;
     RECT  51.212 2.418 51.299 181.848 ;
     RECT  51.299 2.418 51.304 181.272 ;
     RECT  51.304 12 51.437 12.024 ;
     RECT  51.112 1.152 51.445 1.224 ;
     RECT  51.304 5.712 51.509 5.736 ;
     RECT  51.304 6.768 51.509 6.84 ;
     RECT  51.509 6.816 51.581 6.84 ;
     RECT  51.445 0.624 51.761 1.224 ;
     RECT  51.304 42.816 52.013 42.84 ;
     RECT  51.304 34.704 52.121 34.728 ;
     RECT  51.304 30.96 52.163 30.984 ;
     RECT  51.304 180.816 52.297 181.272 ;
     RECT  51.304 9.696 52.337 9.72 ;
     RECT  51.304 2.88 52.357 4.296 ;
     RECT  52.297 180.816 52.369 181.752 ;
     RECT  52.369 180.096 52.381 181.752 ;
     RECT  52.453 11.424 52.553 11.448 ;
     RECT  52.453 37.104 52.661 37.128 ;
     RECT  52.645 6.192 52.732 6.216 ;
     RECT  52.357 2.88 52.805 4.584 ;
     RECT  52.805 4.272 53.057 4.584 ;
     RECT  51.761 1.2 53.125 1.224 ;
     RECT  53.029 20.016 53.129 20.04 ;
     RECT  53.084 42.624 53.171 42.648 ;
     RECT  53.029 9.168 53.273 9.192 ;
     RECT  52.381 180.096 53.372 181.272 ;
     RECT  53.324 27.312 53.411 27.336 ;
     RECT  53.372 179.472 53.459 181.272 ;
     RECT  53.42 29.424 53.507 29.448 ;
     RECT  53.057 4.56 53.509 4.584 ;
     RECT  52.805 2.88 53.557 2.904 ;
     RECT  53.509 4.56 53.597 5.016 ;
     RECT  53.612 7.968 53.699 7.992 ;
     RECT  53.459 180.096 53.701 181.272 ;
     RECT  53.701 180.096 53.795 181.752 ;
     RECT  53.804 32.448 53.891 32.472 ;
     RECT  53.557 2.256 53.957 2.904 ;
     RECT  53.125 1.152 54.029 1.224 ;
     RECT  53.957 2.88 54.133 2.904 ;
     RECT  54.029 1.152 54.305 1.176 ;
     RECT  54.236 24.336 54.323 24.36 ;
     RECT  54.284 22.128 54.371 22.152 ;
     RECT  54.305 0.624 54.389 1.176 ;
     RECT  54.133 2.88 54.457 2.952 ;
     RECT  54.421 7.632 54.505 7.656 ;
     RECT  53.795 180.096 54.524 181.272 ;
     RECT  54.469 35.76 54.556 35.784 ;
     RECT  54.457 2.88 54.565 3.432 ;
     RECT  53.597 4.56 54.565 4.68 ;
     RECT  54.524 179.472 54.611 181.272 ;
     RECT  54.565 2.88 54.652 4.68 ;
     RECT  54.652 4.56 54.661 4.68 ;
     RECT  54.652 2.88 54.821 3.432 ;
     RECT  54.821 2.88 54.857 3 ;
     RECT  54.611 180.096 54.857 181.272 ;
     RECT  54.661 4.56 54.929 5.112 ;
     RECT  54.889 107.232 54.973 108.216 ;
     RECT  55.1 40.176 55.187 40.2 ;
     RECT  54.997 6.288 55.217 6.312 ;
     RECT  55.333 36.528 55.436 36.552 ;
     RECT  54.389 1.152 55.525 1.176 ;
     RECT  55.525 0.48 55.669 1.176 ;
     RECT  55.429 30.72 55.813 30.744 ;
     RECT  55.669 0.144 55.829 1.176 ;
     RECT  55.436 36.528 55.861 36.84 ;
     RECT  55.829 0.144 56.101 0.168 ;
     RECT  55.829 1.152 56.185 1.176 ;
     RECT  54.929 4.56 56.221 4.584 ;
     RECT  56.101 0.096 56.243 0.168 ;
     RECT  54.857 180.816 56.341 181.272 ;
     RECT  56.185 1.152 56.408 1.752 ;
     RECT  54.857 2.88 56.408 2.904 ;
     RECT  56.221 4.56 56.408 5.064 ;
     RECT  56.293 7.392 56.408 7.416 ;
     RECT  56.041 20.496 56.408 20.52 ;
     RECT  55.357 22.752 56.408 22.776 ;
     RECT  56.293 25.296 56.408 25.32 ;
     RECT  55.861 27.408 56.408 27.432 ;
     RECT  55.813 30.528 56.408 30.744 ;
     RECT  55.861 36.528 56.408 37.608 ;
     RECT  55.573 42.672 56.408 42.696 ;
     RECT  55.753 179.472 56.408 179.496 ;
     RECT  56.341 180.816 56.408 181.848 ;
     RECT  56.408 1.152 56.512 181.848 ;
     RECT  56.512 1.152 56.585 1.224 ;
     RECT  56.512 2.418 56.704 181.848 ;
     RECT  56.704 5.04 56.819 5.16 ;
     RECT  56.704 26.784 56.829 27.72 ;
     RECT  56.704 40.224 56.86 40.248 ;
     RECT  56.704 6.96 56.909 7.416 ;
     RECT  56.585 1.2 56.981 1.224 ;
     RECT  56.704 30.96 57.011 30.984 ;
     RECT  56.909 6.96 57.269 6.984 ;
     RECT  56.829 26.784 57.269 26.808 ;
     RECT  56.704 34.752 57.269 34.776 ;
     RECT  56.704 21.696 57.34 21.72 ;
     RECT  56.704 23.856 57.436 23.88 ;
     RECT  56.704 3.888 57.521 4.008 ;
     RECT  56.704 179.472 57.557 179.496 ;
     RECT  56.704 8.544 57.601 8.568 ;
     RECT  56.704 180.816 57.629 181.848 ;
     RECT  57.805 10.8 57.917 10.824 ;
     RECT  57.869 1.152 57.953 1.176 ;
     RECT  57.788 2.832 58.057 2.856 ;
     RECT  57.629 181.824 58.085 181.848 ;
     RECT  56.243 0.144 58.117 0.168 ;
     RECT  58.117 129.456 58.165 129.48 ;
     RECT  57.629 180.816 58.169 180.84 ;
     RECT  58.165 129.456 58.205 129.576 ;
     RECT  58.205 129.552 58.252 129.576 ;
     RECT  58.021 179.28 58.556 179.304 ;
     RECT  58.556 179.28 58.561 179.592 ;
     RECT  58.561 179.28 58.645 180.216 ;
     RECT  58.057 2.832 58.741 3.432 ;
     RECT  58.705 24.816 58.789 24.84 ;
     RECT  58.741 32.544 58.835 32.568 ;
     RECT  58.645 179.28 58.889 179.544 ;
     RECT  58.405 10.272 58.961 10.296 ;
     RECT  56.819 5.136 58.981 5.16 ;
     RECT  58.117 0.144 59.021 0.6 ;
     RECT  59.021 0.144 59.069 1.176 ;
     RECT  59.132 37.248 59.219 37.272 ;
     RECT  58.085 181.824 59.228 182.376 ;
     RECT  59.228 181.824 59.315 182.424 ;
     RECT  59.269 41.376 59.353 41.4 ;
     RECT  59.269 27.312 59.356 27.336 ;
     RECT  59.353 41.376 59.465 41.496 ;
     RECT  59.269 29.904 59.501 29.928 ;
     RECT  59.069 0.576 59.557 1.176 ;
     RECT  58.741 2.304 59.557 3.432 ;
     RECT  59.509 21.552 59.596 21.576 ;
     RECT  58.981 4.56 59.645 5.16 ;
     RECT  59.557 0.576 59.813 3.432 ;
     RECT  59.645 4.56 59.813 4.584 ;
     RECT  59.813 0.576 59.825 4.584 ;
     RECT  59.825 2.304 59.897 4.584 ;
     RECT  58.889 179.52 60.005 179.544 ;
     RECT  59.825 0.576 60.133 1.176 ;
     RECT  59.897 2.304 60.221 3.048 ;
     RECT  59.465 41.472 60.257 41.496 ;
     RECT  59.315 181.824 60.361 181.848 ;
     RECT  60.221 2.304 60.473 2.904 ;
     RECT  60.361 181.824 60.515 182.472 ;
     RECT  60.421 34.848 60.517 34.872 ;
     RECT  59.897 4.56 60.617 4.584 ;
     RECT  60.421 25.152 60.617 25.176 ;
     RECT  60.572 22.944 60.659 22.968 ;
     RECT  60.473 2.304 60.937 2.808 ;
     RECT  60.133 0.144 60.997 1.176 ;
     RECT  61.285 5.712 61.516 5.736 ;
     RECT  61.405 32.544 61.549 32.568 ;
     RECT  61.573 4.656 61.585 4.68 ;
     RECT  61.516 5.712 61.585 5.784 ;
     RECT  60.997 0.144 61.621 1.272 ;
     RECT  61.585 4.656 61.669 5.784 ;
     RECT  61.621 0.096 61.808 1.272 ;
     RECT  60.937 2.256 61.808 2.808 ;
     RECT  61.669 4.656 61.808 6.264 ;
     RECT  61.621 8.736 61.808 8.76 ;
     RECT  61.621 29.424 61.808 29.448 ;
     RECT  61.549 32.4 61.808 32.568 ;
     RECT  60.517 34.848 61.808 35.64 ;
     RECT  61.292 39.072 61.808 39.096 ;
     RECT  61.58 41.616 61.808 41.64 ;
     RECT  60.515 181.824 61.808 181.848 ;
     RECT  61.808 0.096 61.912 181.848 ;
     RECT  61.912 2.418 62.104 181.848 ;
     RECT  61.912 0.096 62.147 1.272 ;
     RECT  62.104 3.936 62.165 4.68 ;
     RECT  62.104 25.44 62.387 25.464 ;
     RECT  62.165 3.936 62.425 4.584 ;
     RECT  62.147 1.152 62.525 1.272 ;
     RECT  62.104 32.544 62.597 32.568 ;
     RECT  62.425 4.512 62.777 4.584 ;
     RECT  62.104 20.208 62.819 20.232 ;
     RECT  62.104 37.056 62.819 37.08 ;
     RECT  62.104 22.944 62.993 22.968 ;
     RECT  63.164 31.536 63.251 31.56 ;
     RECT  62.147 0.096 63.253 0.12 ;
     RECT  63.253 0.096 63.398 0.168 ;
     RECT  63.356 25.68 63.443 25.704 ;
     RECT  62.525 1.152 63.541 1.176 ;
     RECT  63.398 0.096 63.569 0.12 ;
     RECT  63.5 35.616 63.587 35.64 ;
     RECT  62.104 2.88 63.637 2.904 ;
     RECT  63.665 29.376 63.749 29.4 ;
     RECT  62.777 4.56 63.781 4.584 ;
     RECT  63.253 41.616 63.785 41.64 ;
     RECT  63.301 33.696 63.821 33.72 ;
     RECT  63.637 2.832 64.261 2.904 ;
     RECT  63.541 1.152 64.453 1.224 ;
     RECT  64.261 2.304 64.453 2.904 ;
     RECT  64.453 1.152 64.505 2.904 ;
     RECT  64.505 1.152 64.541 2.616 ;
     RECT  64.652 36.672 64.681 36.696 ;
     RECT  64.681 35.76 64.739 36.696 ;
     RECT  64.739 35.76 64.765 35.784 ;
     RECT  64.541 2.304 64.829 2.616 ;
     RECT  64.541 1.152 64.901 1.176 ;
     RECT  64.961 38.832 65.045 38.856 ;
     RECT  64.829 2.352 65.081 2.616 ;
     RECT  65.029 0.144 65.125 0.168 ;
     RECT  64.969 20.064 65.221 20.088 ;
     RECT  63.781 3.984 65.269 4.584 ;
     RECT  62.104 180.144 65.269 180.168 ;
     RECT  65.269 3.984 65.276 5.16 ;
     RECT  65.221 19.92 65.317 20.088 ;
     RECT  65.269 179.616 65.356 180.168 ;
     RECT  65.276 3.888 65.363 5.16 ;
     RECT  65.363 3.984 65.405 5.16 ;
     RECT  65.125 0.096 65.477 0.168 ;
     RECT  62.104 181.824 65.513 181.848 ;
     RECT  65.317 19.92 65.555 20.52 ;
     RECT  65.555 20.496 65.657 20.52 ;
     RECT  65.356 179.76 65.657 180.168 ;
     RECT  65.081 2.592 65.945 2.616 ;
     RECT  65.996 24.912 66.083 24.936 ;
     RECT  65.749 1.2 66.085 1.224 ;
     RECT  65.989 27.408 66.089 27.432 ;
     RECT  66.037 21.936 66.124 21.96 ;
     RECT  65.405 4.464 66.469 5.016 ;
     RECT  66.085 1.152 66.485 1.224 ;
     RECT  66.469 2.784 66.517 5.016 ;
     RECT  66.485 1.2 66.581 1.224 ;
     RECT  66.908 33.456 66.997 33.48 ;
     RECT  65.701 181.248 67.165 181.272 ;
     RECT  66.581 1.2 67.208 1.8 ;
     RECT  66.517 2.784 67.208 5.784 ;
     RECT  67.045 6.864 67.208 6.888 ;
     RECT  66.997 32.832 67.208 33.48 ;
     RECT  66.841 42.432 67.208 42.456 ;
     RECT  65.657 179.76 67.208 179.784 ;
     RECT  67.165 181.248 67.208 181.752 ;
     RECT  67.208 1.2 67.312 181.752 ;
     RECT  65.477 0.096 67.385 0.12 ;
     RECT  67.312 2.418 67.504 181.752 ;
     RECT  67.504 181.248 67.609 181.752 ;
     RECT  67.504 4.464 67.619 5.784 ;
     RECT  67.504 26.88 67.619 26.904 ;
     RECT  67.504 35.28 67.619 35.304 ;
     RECT  67.504 38.256 67.673 38.664 ;
     RECT  67.312 1.2 67.765 1.224 ;
     RECT  67.673 38.256 67.811 38.28 ;
     RECT  67.619 5.76 67.859 5.784 ;
     RECT  67.504 20.592 67.889 20.616 ;
     RECT  67.504 24.48 68.003 25.32 ;
     RECT  67.765 1.152 68.177 1.224 ;
     RECT  67.504 6.864 68.195 6.888 ;
     RECT  67.504 2.736 68.669 3.384 ;
     RECT  67.619 4.464 68.669 4.584 ;
     RECT  68.629 25.392 68.716 25.416 ;
     RECT  68.177 1.152 69.149 1.176 ;
     RECT  69.073 14.832 69.185 14.856 ;
     RECT  69.116 30.336 69.203 30.36 ;
     RECT  69.212 36.672 69.299 36.696 ;
     RECT  68.669 2.736 69.509 4.584 ;
     RECT  69.445 33.504 69.532 33.528 ;
     RECT  69.013 42.432 69.539 42.456 ;
     RECT  67.609 181.248 69.577 181.272 ;
     RECT  69.493 25.632 69.58 25.656 ;
     RECT  69.577 181.248 69.661 181.752 ;
     RECT  69.644 39.6 69.731 39.624 ;
     RECT  69.509 3.408 69.857 4.584 ;
     RECT  69.325 180.096 69.877 180.12 ;
     RECT  69.877 179.472 69.964 180.12 ;
     RECT  69.98 24.912 70.067 24.936 ;
     RECT  69.637 0.624 70.165 0.648 ;
     RECT  69.829 1.776 70.165 1.8 ;
     RECT  70.165 0.624 70.373 1.8 ;
     RECT  70.225 22.176 70.403 22.2 ;
     RECT  69.857 3.408 70.501 4.632 ;
     RECT  70.501 3.408 70.625 5.16 ;
     RECT  70.373 1.152 70.661 1.8 ;
     RECT  70.585 34.752 70.697 34.776 ;
     RECT  70.625 3.408 70.877 4.584 ;
     RECT  69.964 179.616 70.981 180.12 ;
     RECT  70.877 3.696 71.075 4.584 ;
     RECT  70.789 2.352 71.165 2.376 ;
     RECT  71.075 4.128 71.165 4.584 ;
     RECT  69.661 181.248 71.305 181.272 ;
     RECT  70.981 179.52 71.309 180.12 ;
     RECT  71.269 28.08 71.353 28.104 ;
     RECT  71.305 31.872 71.389 31.896 ;
     RECT  70.661 1.152 71.633 1.32 ;
     RECT  71.377 6.672 71.653 6.696 ;
     RECT  71.653 6.672 71.893 7.464 ;
     RECT  71.633 1.152 71.941 1.224 ;
     RECT  71.941 0.624 72.173 1.224 ;
     RECT  71.305 181.248 72.181 181.752 ;
     RECT  71.165 4.128 72.197 4.152 ;
     RECT  72.181 180.624 72.253 181.752 ;
     RECT  72.197 4.128 72.421 4.584 ;
     RECT  71.893 5.712 72.421 7.464 ;
     RECT  67.504 40.704 72.469 40.728 ;
     RECT  71.797 34.848 72.601 34.872 ;
     RECT  72.173 1.152 72.608 1.224 ;
     RECT  72.421 4.128 72.608 7.464 ;
     RECT  72.469 20.064 72.608 20.088 ;
     RECT  72.373 23.04 72.608 23.064 ;
     RECT  71.797 25.728 72.608 25.752 ;
     RECT  70.513 33.6 72.608 33.624 ;
     RECT  72.601 34.704 72.608 34.872 ;
     RECT  71.66 37.248 72.608 37.272 ;
     RECT  72.469 40.704 72.608 41.304 ;
     RECT  72.037 42.48 72.608 42.504 ;
     RECT  71.309 179.52 72.608 179.544 ;
     RECT  72.253 180.624 72.608 181.56 ;
     RECT  72.608 1.152 72.803 181.56 ;
     RECT  72.803 1.152 72.904 181.272 ;
     RECT  72.904 23.04 72.965 23.064 ;
     RECT  72.904 28.416 73.043 28.44 ;
     RECT  72.904 44.88 73.324 44.904 ;
     RECT  72.904 1.152 73.433 5.736 ;
     RECT  73.433 1.152 73.475 4.008 ;
     RECT  73.475 1.152 73.516 3.864 ;
     RECT  73.433 5.04 73.523 5.736 ;
     RECT  72.904 180 73.649 180.024 ;
     RECT  73.516 3.024 73.685 3.864 ;
     RECT  73.909 31.104 73.996 31.128 ;
     RECT  74.041 44.688 74.125 44.712 ;
     RECT  73.516 1.152 74.197 1.8 ;
     RECT  72.904 181.248 74.221 181.272 ;
     RECT  74.197 0.576 74.297 1.8 ;
     RECT  73.523 5.088 74.341 5.736 ;
     RECT  74.341 5.088 74.428 5.928 ;
     RECT  74.588 25.392 74.675 25.416 ;
     RECT  74.185 41.904 74.675 41.928 ;
     RECT  74.428 5.088 74.729 5.688 ;
     RECT  74.221 181.248 74.867 181.752 ;
     RECT  74.821 33.744 74.908 33.768 ;
     RECT  75.02 36.912 75.107 36.936 ;
     RECT  75.061 10.272 75.197 10.296 ;
     RECT  74.297 0.576 75.233 1.272 ;
     RECT  73.685 3.84 75.269 3.864 ;
     RECT  75.109 2.304 75.337 2.328 ;
     RECT  75.109 181.824 75.365 181.848 ;
     RECT  74.149 179.472 75.377 179.496 ;
     RECT  75.349 4.56 75.697 4.776 ;
     RECT  75.685 21.12 75.772 21.144 ;
     RECT  75.697 4.56 75.881 5.16 ;
     RECT  75.337 2.304 75.989 3.144 ;
     RECT  75.913 28.56 75.997 28.584 ;
     RECT  75.973 44.832 76.061 44.856 ;
     RECT  75.233 0.576 76.165 0.6 ;
     RECT  76.165 0.096 76.229 0.6 ;
     RECT  75.781 65.568 76.241 65.592 ;
     RECT  76.229 0.096 76.313 1.176 ;
     RECT  75.365 181.824 76.313 182.376 ;
     RECT  75.989 2.736 76.741 3.144 ;
     RECT  76.741 2.736 76.853 3.432 ;
     RECT  76.805 39.408 76.889 39.432 ;
     RECT  76.693 40.992 76.925 41.016 ;
     RECT  76.313 0.096 76.961 0.6 ;
     RECT  76.913 26.736 76.997 26.76 ;
     RECT  76.853 2.736 77.029 2.76 ;
     RECT  75.881 5.136 77.221 5.16 ;
     RECT  77.221 4.896 77.353 5.16 ;
     RECT  77.353 4.896 77.453 5.688 ;
     RECT  76.313 181.824 77.461 181.848 ;
     RECT  77.029 2.304 78.008 2.76 ;
     RECT  77.453 3.936 78.008 5.688 ;
     RECT  77.509 6.768 78.008 6.792 ;
     RECT  77.605 7.968 78.008 7.992 ;
     RECT  77.389 33.36 78.008 33.384 ;
     RECT  77.269 36.096 78.008 36.12 ;
     RECT  77.209 38.832 78.008 38.856 ;
     RECT  76.705 44.592 78.008 44.616 ;
     RECT  77.749 46.752 78.008 46.776 ;
     RECT  75.949 180.144 78.008 180.168 ;
     RECT  77.461 181.248 78.008 181.848 ;
     RECT  78.008 2.148 78.112 181.848 ;
     RECT  78.112 2.418 78.217 181.848 ;
     RECT  78.217 2.418 78.304 182.376 ;
     RECT  78.304 2.688 78.329 6.84 ;
     RECT  78.304 10.464 78.581 10.488 ;
     RECT  78.304 179.472 78.581 180.168 ;
     RECT  78.304 29.232 78.659 29.256 ;
     RECT  76.961 0.096 78.721 0.168 ;
     RECT  78.581 179.472 78.725 180.12 ;
     RECT  78.329 2.688 78.755 5.928 ;
     RECT  78.721 0.096 78.757 0.552 ;
     RECT  78.304 68.976 78.769 69 ;
     RECT  78.304 46.752 78.797 46.776 ;
     RECT  78.304 43.536 78.851 43.56 ;
     RECT  78.755 2.736 78.869 5.928 ;
     RECT  78.304 48.768 78.947 48.792 ;
     RECT  78.304 35.712 79.013 35.736 ;
     RECT  78.304 38.928 79.139 39.336 ;
     RECT  79.139 39.312 79.193 39.336 ;
     RECT  78.869 2.736 79.373 3.432 ;
     RECT  78.869 4.416 79.405 5.928 ;
     RECT  79.333 7.392 79.445 7.416 ;
     RECT  79.333 10.8 79.445 10.824 ;
     RECT  79.405 4.416 79.525 6.264 ;
     RECT  78.757 0.096 79.667 1.176 ;
     RECT  79.573 30.816 79.697 30.84 ;
     RECT  79.525 4.416 79.733 6.888 ;
     RECT  79.733 4.416 79.813 6.264 ;
     RECT  79.765 46.752 79.849 46.776 ;
     RECT  79.909 26.736 80.003 26.76 ;
     RECT  79.373 2.736 80.005 3 ;
     RECT  80.005 33.216 80.012 33.24 ;
     RECT  79.813 5.616 80.057 6.264 ;
     RECT  80.005 2.688 80.093 3 ;
     RECT  80.012 30.576 80.099 30.6 ;
     RECT  80.012 33.024 80.099 33.24 ;
     RECT  80.099 33.216 80.129 33.24 ;
     RECT  80.108 45.888 80.195 45.912 ;
     RECT  79.813 4.416 80.252 4.584 ;
     RECT  80.252 4.272 80.339 4.584 ;
     RECT  80.3 38.592 80.387 38.616 ;
     RECT  79.667 0.192 80.531 1.176 ;
     RECT  80.389 42.72 80.589 42.744 ;
     RECT  80.531 1.152 80.597 1.176 ;
     RECT  80.093 2.832 80.665 3 ;
     RECT  80.057 5.616 80.666 5.64 ;
     RECT  78.725 180.096 80.809 180.12 ;
     RECT  80.773 6.864 80.885 6.888 ;
     RECT  80.809 4.848 80.893 5.208 ;
     RECT  80.377 48.624 80.909 48.648 ;
     RECT  80.909 48.624 80.928 48.792 ;
     RECT  80.917 28.992 80.953 29.016 ;
     RECT  80.809 179.616 80.965 180.12 ;
     RECT  80.928 48.768 80.993 48.792 ;
     RECT  80.953 28.992 81.065 29.256 ;
     RECT  80.965 179.616 81.065 180.6 ;
     RECT  81.02 178.368 81.107 178.392 ;
     RECT  80.677 0.096 81.137 0.168 ;
     RECT  81.137 0.144 81.299 0.168 ;
     RECT  80.665 2.832 81.493 3.48 ;
     RECT  80.581 38.64 81.533 38.664 ;
     RECT  81.493 2.784 81.587 3.48 ;
     RECT  81.587 2.832 81.629 3.48 ;
     RECT  80.917 34.848 81.644 34.872 ;
     RECT  81.644 34.08 81.673 34.872 ;
     RECT  81.629 2.832 81.713 4.008 ;
     RECT  81.673 34.08 81.731 35.064 ;
     RECT  81.74 38.592 81.827 38.616 ;
     RECT  81.713 2.832 81.865 3.768 ;
     RECT  81.781 36.24 81.893 36.264 ;
     RECT  81.829 9.12 81.929 9.144 ;
     RECT  81.884 0.528 81.971 0.552 ;
     RECT  78.304 181.824 81.997 182.376 ;
     RECT  81.065 29.232 82.028 29.256 ;
     RECT  80.893 5.184 82.117 5.208 ;
     RECT  82.069 46.32 82.117 46.344 ;
     RECT  82.028 28.896 82.145 29.256 ;
     RECT  81.865 3.216 82.156 3.768 ;
     RECT  82.117 46.32 82.163 46.728 ;
     RECT  82.117 5.184 82.204 5.4 ;
     RECT  81.493 7.344 82.211 7.464 ;
     RECT  82.069 1.776 82.213 1.8 ;
     RECT  81.647 27.888 82.217 27.912 ;
     RECT  82.204 5.184 82.321 5.208 ;
     RECT  82.177 180 82.321 180.024 ;
     RECT  81.997 181.824 82.321 182.424 ;
     RECT  82.145 28.896 82.433 28.92 ;
     RECT  82.213 1.728 82.501 1.8 ;
     RECT  82.321 180 82.501 180.696 ;
     RECT  82.565 41.328 82.693 41.352 ;
     RECT  82.385 7.968 82.709 7.992 ;
     RECT  82.681 8.976 82.709 9.096 ;
     RECT  82.213 6.816 82.717 6.84 ;
     RECT  81.731 35.04 82.717 35.064 ;
     RECT  82.501 1.68 82.837 1.8 ;
     RECT  82.645 44.208 82.844 44.232 ;
     RECT  82.156 3.744 82.885 3.768 ;
     RECT  82.321 5.088 82.885 5.208 ;
     RECT  82.117 0.576 82.933 0.6 ;
     RECT  82.321 181.824 83.005 182.952 ;
     RECT  82.717 6.768 83.149 6.84 ;
     RECT  82.933 0.576 83.221 0.648 ;
     RECT  82.163 46.512 83.221 46.728 ;
     RECT  83.221 0.096 83.363 0.648 ;
     RECT  82.837 1.68 83.408 2.76 ;
     RECT  82.885 3.744 83.408 5.208 ;
     RECT  83.149 6.288 83.408 6.84 ;
     RECT  82.709 7.968 83.408 9.096 ;
     RECT  82.069 31.872 83.408 31.896 ;
     RECT  82.717 34.176 83.408 35.064 ;
     RECT  82.412 36.384 83.408 36.408 ;
     RECT  82.753 38.4 83.408 38.424 ;
     RECT  82.693 41.328 83.408 41.64 ;
     RECT  82.844 44.208 83.408 44.328 ;
     RECT  83.221 46.224 83.408 46.728 ;
     RECT  81.925 49.008 83.408 49.032 ;
     RECT  83.329 127.056 83.408 127.08 ;
     RECT  82.501 179.808 83.408 180.696 ;
     RECT  83.005 181.824 83.408 183 ;
     RECT  83.408 1.68 83.704 183 ;
     RECT  83.363 0.336 83.797 0.648 ;
     RECT  83.704 1.68 83.797 3.528 ;
     RECT  83.704 126.672 83.801 127.08 ;
     RECT  83.797 0.336 84.323 3.528 ;
     RECT  83.704 181.248 84.371 183 ;
     RECT  84.323 0.624 84.529 3.528 ;
     RECT  84.529 0.624 84.601 2.904 ;
     RECT  83.704 4.512 84.899 5.112 ;
     RECT  84.601 0.624 84.947 2.376 ;
     RECT  84.371 181.728 84.995 183 ;
     RECT  84.899 4.512 85.523 4.536 ;
     RECT  84.995 181.728 85.667 182.52 ;
     RECT  84.947 0.624 85.681 0.696 ;
     RECT  84.947 1.728 85.955 1.752 ;
     RECT  85.667 181.728 85.969 181.752 ;
     RECT  86.197 88.848 86.209 88.872 ;
     RECT  86.209 88.752 86.284 88.872 ;
     RECT  85.681 0.672 86.291 0.696 ;
     RECT  86.284 88.752 86.364 88.776 ;
     RECT  86.281 94.224 86.364 94.248 ;
     RECT  83.801 126.672 86.364 126.696 ;
     RECT  86.281 139.872 86.364 139.992 ;
     RECT  83.704 153.312 86.364 153.336 ;
     RECT  86.364 139.872 86.393 139.896 ;
    LAYER M5 ;
     RECT  36.864 0.016 46.728 0.047 ;
     RECT  55.248 0.016 65.448 0.047 ;
     RECT  36 0.047 46.728 0.053 ;
     RECT  55.248 0.047 67.368 0.179 ;
     RECT  18.48 0.016 27.96 0.181 ;
     RECT  33.648 0.053 33.672 0.181 ;
     RECT  35.328 0.053 46.728 0.181 ;
     RECT  48.672 0.053 51.432 0.181 ;
     RECT  55.248 0.179 64.872 0.181 ;
     RECT  73.632 0.016 84.216 0.181 ;
     RECT  17.664 0.181 29.736 0.275 ;
     RECT  0.144 0.016 9.24 0.565 ;
     RECT  12 0.181 12.024 0.565 ;
     RECT  13.68 0.181 13.704 0.565 ;
     RECT  14.832 0.181 16.632 0.565 ;
     RECT  17.664 0.275 27.96 0.565 ;
     RECT  29.088 0.275 29.736 0.565 ;
     RECT  31.44 0.181 31.464 0.565 ;
     RECT  33.648 0.181 51.432 0.565 ;
     RECT  66.096 0.179 67.368 0.565 ;
     RECT  68.4 0.181 68.424 0.565 ;
     RECT  73.536 0.181 84.36 0.565 ;
     RECT  0.144 0.565 9.864 0.659 ;
     RECT  13.68 0.565 27.96 0.659 ;
     RECT  66.096 0.565 86.28 0.659 ;
     RECT  85.92 0.659 86.28 0.707 ;
     RECT  29.088 0.565 32.376 1.141 ;
     RECT  33.648 0.565 51.48 1.141 ;
     RECT  52.464 0.181 64.872 1.141 ;
     RECT  66.096 0.659 68.952 1.141 ;
     RECT  29.088 1.141 68.952 1.187 ;
     RECT  70.176 0.659 84.936 1.187 ;
     RECT  18.336 0.659 27.96 1.235 ;
     RECT  47.28 1.187 64.584 1.235 ;
     RECT  65.76 1.187 68.424 1.235 ;
     RECT  70.176 1.187 71.4 1.235 ;
     RECT  13.68 0.659 16.872 1.283 ;
     RECT  70.176 1.235 71.352 1.331 ;
     RECT  10.464 1.141 10.488 1.717 ;
     RECT  12 0.565 12.264 1.717 ;
     RECT  13.68 1.283 16.632 1.717 ;
     RECT  18.6 1.235 27.96 1.717 ;
     RECT  29.088 1.187 33.672 1.717 ;
     RECT  70.176 1.331 70.92 1.717 ;
     RECT  85.92 0.707 85.944 1.763 ;
     RECT  10.416 1.717 16.632 1.811 ;
     RECT  18.6 1.717 33.672 1.811 ;
     RECT  66.624 1.235 67.32 1.811 ;
     RECT  69.84 1.717 70.92 1.811 ;
     RECT  11.28 1.811 12.024 1.859 ;
     RECT  52.464 1.235 64.584 2.291 ;
     RECT  14.832 1.811 16.632 2.293 ;
     RECT  61.296 2.291 64.584 2.293 ;
     RECT  72.432 1.187 84.888 2.293 ;
     RECT  14.832 2.293 17.4 2.387 ;
     RECT  18.6 1.811 29.976 2.387 ;
     RECT  70.8 1.811 70.92 2.387 ;
     RECT  72.432 2.293 84.936 2.387 ;
     RECT  34.8 1.187 45.72 2.407 ;
     RECT  67.056 1.811 67.32 2.407 ;
     RECT  68.4 1.235 68.424 2.407 ;
     RECT  61.296 2.293 64.776 2.435 ;
     RECT  18.6 2.387 28.008 2.771 ;
     RECT  18.6 2.771 27.432 2.773 ;
     RECT  34.8 2.407 45.912 2.821 ;
     RECT  0.144 0.659 9.048 2.915 ;
     RECT  13.2 1.811 13.704 2.915 ;
     RECT  14.832 2.387 17.16 2.915 ;
     RECT  34.8 2.821 46.104 2.915 ;
     RECT  47.28 1.235 51.432 2.915 ;
     RECT  52.464 2.291 60.264 2.915 ;
     RECT  61.296 2.435 64.008 2.915 ;
     RECT  34.8 2.915 35.928 2.963 ;
     RECT  47.28 2.915 47.352 2.963 ;
     RECT  52.704 2.915 54.168 2.963 ;
     RECT  12 1.859 12.024 3.011 ;
     RECT  36.96 2.915 46.104 3.107 ;
     RECT  45.504 3.107 46.104 3.253 ;
     RECT  28.992 2.387 29.976 3.301 ;
     RECT  67.056 2.407 68.424 3.311 ;
     RECT  13.2 2.915 13.656 3.317 ;
     RECT  34.8 2.963 35.832 3.395 ;
     RECT  66.768 3.311 69.048 3.435 ;
     RECT  0.144 2.915 4.152 3.443 ;
     RECT  48.672 2.915 51.432 3.443 ;
     RECT  72.432 2.387 84.888 3.443 ;
     RECT  5.28 2.915 9.048 3.445 ;
     RECT  13.104 3.317 13.656 3.445 ;
     RECT  15.36 2.915 17.16 3.445 ;
     RECT  18.336 2.773 27.432 3.445 ;
     RECT  28.992 3.301 30.696 3.445 ;
     RECT  32.736 1.811 33.672 3.445 ;
     RECT  34.8 3.395 35.208 3.445 ;
     RECT  48.816 3.443 51.432 3.445 ;
     RECT  66.768 3.435 67.512 3.445 ;
     RECT  68.688 3.435 69.048 3.445 ;
     RECT  11.904 3.381 11.928 3.469 ;
     RECT  5.28 3.445 10.728 3.539 ;
     RECT  15.36 3.445 27.432 3.539 ;
     RECT  32.016 3.445 35.208 3.539 ;
     RECT  48.816 3.445 51.72 3.539 ;
     RECT  52.704 2.963 53.304 3.539 ;
     RECT  66.48 3.445 67.512 3.539 ;
     RECT  68.688 3.445 69.288 3.539 ;
     RECT  70.896 2.387 70.92 3.685 ;
     RECT  5.28 3.539 9.528 3.877 ;
     RECT  77.472 3.443 84.888 3.957 ;
     RECT  49.776 3.539 49.8 3.971 ;
     RECT  5.136 3.877 9.528 4.019 ;
     RECT  13.008 3.445 13.656 4.019 ;
     RECT  15.36 3.539 16.68 4.019 ;
     RECT  34.8 3.539 35.208 4.019 ;
     RECT  55.248 2.915 60.264 4.019 ;
     RECT  36.96 3.107 44.376 4.021 ;
     RECT  45.504 3.253 46.152 4.021 ;
     RECT  47.28 2.963 47.304 4.021 ;
     RECT  55.248 4.019 59.016 4.085 ;
     RECT  18.336 3.539 27.432 4.115 ;
     RECT  65.328 3.877 65.352 4.117 ;
     RECT  13.104 4.019 13.656 4.243 ;
     RECT  45.504 4.021 47.304 4.277 ;
     RECT  27.12 4.115 27.432 4.341 ;
     RECT  45.504 4.277 47.352 4.341 ;
     RECT  15.648 4.019 16.68 4.365 ;
     RECT  5.136 4.019 9.048 4.405 ;
     RECT  27.12 4.341 27.864 4.429 ;
     RECT  65.136 4.117 65.352 4.451 ;
     RECT  13.104 4.243 13.896 4.511 ;
     RECT  28.944 3.445 30.696 4.511 ;
     RECT  32.736 3.539 32.76 4.511 ;
     RECT  34.8 4.019 35.112 4.511 ;
     RECT  36.624 4.021 44.376 4.511 ;
     RECT  53.28 3.539 53.304 4.511 ;
     RECT  54.576 4.085 59.016 4.511 ;
     RECT  65.28 4.451 65.352 4.511 ;
     RECT  66.768 3.539 67.512 4.511 ;
     RECT  68.736 3.539 68.76 4.511 ;
     RECT  70.896 3.685 71.064 4.511 ;
     RECT  72.432 3.443 75.816 4.511 ;
     RECT  65.28 4.511 69.624 4.533 ;
     RECT  77.472 3.957 85.512 4.547 ;
     RECT  5.088 4.405 9.048 4.595 ;
     RECT  13.104 4.511 14.232 4.595 ;
     RECT  18.336 4.115 25.992 4.595 ;
     RECT  27.12 4.429 27.144 4.595 ;
     RECT  28.896 4.511 35.112 4.595 ;
     RECT  36.336 4.511 44.376 4.595 ;
     RECT  45.504 4.341 47.832 4.595 ;
     RECT  52.368 4.511 59.016 4.595 ;
     RECT  60.24 4.019 60.264 4.595 ;
     RECT  61.296 2.915 63.864 4.595 ;
     RECT  65.28 4.533 69.912 4.595 ;
     RECT  70.896 4.511 71.112 4.595 ;
     RECT  72.24 4.511 75.816 4.595 ;
     RECT  77.472 4.547 84.888 4.595 ;
     RECT  69.888 4.595 69.912 4.643 ;
     RECT  77.472 4.595 83.832 4.691 ;
     RECT  33.936 4.595 35.112 4.715 ;
     RECT  36.864 4.595 36.984 4.715 ;
     RECT  23.088 4.595 25.608 4.739 ;
     RECT  77.472 4.691 83.712 4.885 ;
     RECT  38.016 4.595 41.496 4.931 ;
     RECT  77.232 4.885 83.712 4.971 ;
     RECT  38.592 4.931 41.496 5.027 ;
     RECT  47.28 4.595 47.832 5.027 ;
     RECT  53.52 4.595 53.544 5.027 ;
     RECT  65.28 4.595 65.64 5.027 ;
     RECT  70.896 4.595 71.064 5.087 ;
     RECT  54.672 4.595 55.032 5.123 ;
     RECT  84.864 4.595 84.888 5.123 ;
     RECT  34.32 4.715 35.112 5.171 ;
     RECT  70.512 5.087 71.064 5.171 ;
     RECT  15.648 4.365 16.584 5.173 ;
     RECT  65.28 5.027 65.352 5.197 ;
     RECT  0.144 3.443 4.056 5.219 ;
     RECT  15.6 5.173 16.584 5.411 ;
     RECT  13.104 4.595 13.512 5.603 ;
     RECT  39.84 5.027 41.496 5.611 ;
     RECT  50.784 3.539 51.312 5.663 ;
     RECT  71.04 5.171 71.064 5.663 ;
     RECT  72.432 4.595 75.816 5.663 ;
     RECT  32.736 4.595 32.76 5.699 ;
     RECT  47.28 5.027 47.304 5.699 ;
     RECT  66.768 4.595 67.608 5.715 ;
     RECT  50.784 5.663 51.432 5.747 ;
     RECT  61.296 4.595 62.376 5.747 ;
     RECT  71.04 5.663 75.816 5.747 ;
     RECT  66.768 5.715 67.848 5.749 ;
     RECT  61.536 5.747 62.376 5.795 ;
     RECT  66.672 5.749 67.848 5.803 ;
     RECT  66.672 5.803 67.608 5.833 ;
     RECT  72.144 5.747 72.912 6.059 ;
     RECT  74.352 5.747 75.816 6.059 ;
     RECT  13.2 5.603 13.512 6.085 ;
     RECT  5.136 4.595 9.048 6.229 ;
     RECT  11.28 6.163 11.304 6.251 ;
     RECT  52.656 6.163 52.68 6.251 ;
     RECT  55.008 5.123 55.032 6.323 ;
     RECT  36.96 4.715 36.984 6.419 ;
     RECT  12.048 6.421 12.072 6.507 ;
     RECT  34.8 5.171 35.112 6.739 ;
     RECT  48.096 6.261 48.12 6.755 ;
     RECT  34.8 6.739 35.928 6.767 ;
     RECT  77.52 4.971 83.712 6.803 ;
     RECT  5.088 6.229 9.048 6.815 ;
     RECT  34.704 6.767 35.928 6.827 ;
     RECT  67.008 5.833 67.608 6.837 ;
     RECT  23.52 4.739 25.608 6.851 ;
     RECT  34.704 6.827 35.112 6.851 ;
     RECT  5.088 6.815 9.912 6.899 ;
     RECT  38.592 5.027 38.616 6.899 ;
     RECT  40.032 5.611 41.496 6.899 ;
     RECT  42.912 4.595 44.376 6.899 ;
     RECT  67.008 6.837 68.184 6.925 ;
     RECT  20.496 4.595 21.672 6.947 ;
     RECT  13.2 6.085 13.656 7.391 ;
     RECT  45.504 4.595 46.104 7.391 ;
     RECT  71.04 5.747 71.064 7.391 ;
     RECT  72.336 6.059 72.912 7.391 ;
     RECT  23.52 6.851 24.504 7.427 ;
     RECT  56.304 4.595 58.44 7.427 ;
     RECT  29.28 4.595 30.696 7.443 ;
     RECT  5.088 6.899 9.384 7.475 ;
     RECT  11.04 7.391 11.064 7.475 ;
     RECT  18.336 4.595 19.08 7.475 ;
     RECT  45.504 7.391 46.152 7.475 ;
     RECT  71.04 7.391 72.912 7.475 ;
     RECT  54.432 7.583 54.456 7.667 ;
     RECT  29.28 7.443 31.416 7.693 ;
     RECT  13.056 7.391 13.656 7.797 ;
     RECT  18.336 7.475 18.912 7.797 ;
     RECT  12.528 7.797 13.656 8.003 ;
     RECT  17.952 7.797 18.912 8.003 ;
     RECT  27.936 7.797 27.96 8.003 ;
     RECT  49.008 7.797 49.608 8.003 ;
     RECT  53.664 7.797 53.688 8.003 ;
     RECT  77.616 6.803 83.712 8.003 ;
     RECT  56.4 7.427 58.44 8.579 ;
     RECT  50.784 5.747 51.312 8.677 ;
     RECT  15.648 5.411 16.584 8.687 ;
     RECT  12.768 8.003 13.656 8.771 ;
     RECT  15.072 8.687 16.584 8.771 ;
     RECT  61.632 5.795 62.376 8.771 ;
     RECT  13.2 8.771 13.656 9.119 ;
     RECT  50.64 8.677 51.312 9.119 ;
     RECT  50.064 9.119 51.312 9.141 ;
     RECT  12 9.119 12.024 9.203 ;
     RECT  50.064 9.141 51.912 9.203 ;
     RECT  53.04 9.119 53.064 9.203 ;
     RECT  45.504 7.475 46.104 9.717 ;
     RECT  9.696 9.141 10.248 9.731 ;
     RECT  13.2 9.119 14.52 9.731 ;
     RECT  42.912 6.899 43.8 9.731 ;
     RECT  48.48 9.141 48.504 9.731 ;
     RECT  50.784 9.203 51.912 9.731 ;
     RECT  10.224 9.731 10.248 10.271 ;
     RECT  10.224 10.271 10.824 10.307 ;
     RECT  58.416 8.579 58.44 10.307 ;
     RECT  75.072 6.059 75.816 10.307 ;
     RECT  10.8 10.307 10.824 10.355 ;
     RECT  13.2 9.731 13.656 10.805 ;
     RECT  15.648 8.771 16.584 10.805 ;
     RECT  42.912 9.731 43.224 10.883 ;
     RECT  45.504 9.717 46.392 10.883 ;
     RECT  11.424 10.805 11.448 10.893 ;
     RECT  0.192 5.219 4.056 11.171 ;
     RECT  12.528 10.805 13.656 11.459 ;
     RECT  45.504 10.883 46.104 11.459 ;
     RECT  52.464 10.805 52.488 11.459 ;
     RECT  49.248 10.805 49.272 11.507 ;
     RECT  13.2 11.459 13.656 11.651 ;
     RECT  20.496 6.947 21.096 12.563 ;
     RECT  14.784 10.805 16.584 13.139 ;
     RECT  1.872 11.171 4.056 13.379 ;
     RECT  20.496 12.563 20.52 13.715 ;
     RECT  2.304 13.379 4.056 14.435 ;
     RECT  0.192 11.171 0.744 16.307 ;
     RECT  0.192 16.307 0.504 19.283 ;
     RECT  65.328 5.197 65.352 19.871 ;
     RECT  42.48 19.871 42.504 19.955 ;
     RECT  65.328 19.871 65.544 19.955 ;
     RECT  72.6 7.475 72.912 19.957 ;
     RECT  15.648 13.139 16.584 20.003 ;
     RECT  18.336 8.003 18.912 20.003 ;
     RECT  29.28 7.693 30.696 20.003 ;
     RECT  53.04 19.957 53.064 20.051 ;
     RECT  72.48 19.957 72.912 20.099 ;
     RECT  34.8 6.851 35.112 20.149 ;
     RECT  61.8 8.771 62.376 20.179 ;
     RECT  61.8 20.179 62.808 20.267 ;
     RECT  16.56 20.003 16.584 20.277 ;
     RECT  15.36 20.255 15.384 20.339 ;
     RECT  16.56 20.277 16.968 20.365 ;
     RECT  23.52 7.427 24.456 20.437 ;
     RECT  56.4 8.579 56.808 20.447 ;
     RECT  23.52 20.437 24.552 20.523 ;
     RECT  33.936 20.149 35.112 20.523 ;
     RECT  56.304 20.447 56.808 20.531 ;
     RECT  65.328 19.955 65.352 20.531 ;
     RECT  45.6 11.459 46.104 20.581 ;
     RECT  67.008 6.925 67.608 20.581 ;
     RECT  45.6 20.581 46.152 20.665 ;
     RECT  67.008 20.581 67.848 20.665 ;
     RECT  18.6 20.003 18.912 20.691 ;
     RECT  18.6 20.691 19.704 20.779 ;
     RECT  48.192 20.597 48.216 20.819 ;
     RECT  21.552 20.725 21.576 20.867 ;
     RECT  45.6 20.665 46.104 20.963 ;
     RECT  75.792 10.307 75.816 21.075 ;
     RECT  32.832 21.075 32.856 21.163 ;
     RECT  75.696 21.075 75.816 21.163 ;
     RECT  36.384 21.109 36.408 21.193 ;
     RECT  13.2 11.651 13.512 21.301 ;
     RECT  12.288 21.301 13.512 21.395 ;
     RECT  5.088 7.475 8.52 21.483 ;
     RECT  29.28 20.003 30.216 21.621 ;
     RECT  56.4 20.531 56.808 21.621 ;
     RECT  56.4 21.621 57.192 21.651 ;
     RECT  59.52 21.541 59.544 21.675 ;
     RECT  2.4 14.435 4.056 21.683 ;
     RECT  29.088 21.621 30.216 21.683 ;
     RECT  29.088 21.683 29.928 21.709 ;
     RECT  0.48 19.283 0.504 21.731 ;
     RECT  56.4 21.651 57.288 21.739 ;
     RECT  67.008 20.665 67.608 21.877 ;
     RECT  71.04 7.475 71.064 22.165 ;
     RECT  54.336 22.099 54.36 22.187 ;
     RECT  66.048 21.877 67.608 22.251 ;
     RECT  70.368 22.165 71.064 22.251 ;
     RECT  25.584 6.851 25.608 22.451 ;
     RECT  11.04 22.389 11.064 22.477 ;
     RECT  16.56 20.365 16.584 22.645 ;
     RECT  42.192 22.645 42.216 22.729 ;
     RECT  15.696 22.645 16.776 22.739 ;
     RECT  33.072 22.645 33.096 22.739 ;
     RECT  38.784 22.645 38.808 22.739 ;
     RECT  61.8 20.267 62.376 22.895 ;
     RECT  61.8 22.895 62.856 22.979 ;
     RECT  60.624 22.901 60.648 22.989 ;
     RECT  72.6 20.099 72.912 23.029 ;
     RECT  72.384 23.029 72.912 23.113 ;
     RECT  45.6 20.963 45.912 23.125 ;
     RECT  5.088 21.483 5.496 23.157 ;
     RECT  18.6 20.779 18.912 23.157 ;
     RECT  49.056 22.837 49.08 23.219 ;
     RECT  5.088 23.157 5.784 23.267 ;
     RECT  18.6 23.157 19.608 23.267 ;
     RECT  45.6 23.125 46.584 23.339 ;
     RECT  27.888 23.279 27.912 23.363 ;
     RECT  42.72 23.285 42.744 23.411 ;
     RECT  56.4 21.739 56.808 23.827 ;
     RECT  56.4 23.827 57.384 23.915 ;
     RECT  29.28 21.709 29.928 23.989 ;
     RECT  29.28 23.989 30.312 24.131 ;
     RECT  36.288 23.989 36.312 24.131 ;
     RECT  54.288 23.989 54.312 24.371 ;
     RECT  67.008 22.251 67.608 24.469 ;
     RECT  16.56 22.739 16.584 24.805 ;
     RECT  18.6 23.267 18.912 24.805 ;
     RECT  23.52 20.523 24.456 24.885 ;
     RECT  67.008 24.469 67.992 24.885 ;
     RECT  11.616 24.757 11.64 24.939 ;
     RECT  14.784 24.853 14.808 24.939 ;
     RECT  58.752 24.805 58.776 24.939 ;
     RECT  66.048 24.885 67.992 24.939 ;
     RECT  23.472 24.885 24.456 24.973 ;
     RECT  70.032 24.885 70.056 24.973 ;
     RECT  16.56 24.805 19.128 25.014 ;
     RECT  66.048 24.939 67.608 25.067 ;
     RECT  34.8 20.523 35.112 25.077 ;
     RECT  2.4 21.683 4.008 25.091 ;
     RECT  16.56 25.014 17.592 25.101 ;
     RECT  16.56 25.101 16.632 25.139 ;
     RECT  34.704 25.077 35.112 25.165 ;
     RECT  60.432 25.141 60.456 25.225 ;
     RECT  56.4 23.915 56.808 25.285 ;
     RECT  67.008 25.067 67.608 25.331 ;
     RECT  40.032 6.899 40.512 25.333 ;
     RECT  56.304 25.285 56.808 25.387 ;
     RECT  45.6 23.339 45.912 25.397 ;
     RECT  39.84 25.333 40.512 25.427 ;
     RECT  68.64 25.333 68.664 25.427 ;
     RECT  74.64 25.333 74.664 25.427 ;
     RECT  61.8 22.979 62.376 25.475 ;
     RECT  45.456 25.397 45.912 25.485 ;
     RECT  31.92 25.429 31.944 25.515 ;
     RECT  18.6 25.014 19.128 25.525 ;
     RECT  21.744 25.491 21.768 25.579 ;
     RECT  5.088 23.267 5.496 25.589 ;
     RECT  18.6 25.525 19.368 25.609 ;
     RECT  47.664 25.573 47.688 25.657 ;
     RECT  5.088 25.589 5.736 25.715 ;
     RECT  71.04 22.251 71.064 25.717 ;
     RECT  72.6 23.113 72.912 25.717 ;
     RECT  5.088 25.715 5.448 25.741 ;
     RECT  63.408 25.653 63.432 25.741 ;
     RECT  5.088 25.741 5.352 25.771 ;
     RECT  69.504 25.621 69.528 25.771 ;
     RECT  71.04 25.717 72.912 25.801 ;
     RECT  50.784 9.731 51.312 25.957 ;
     RECT  42.144 25.861 42.168 25.963 ;
     RECT  50.16 25.957 51.312 26.041 ;
     RECT  47.424 26.067 47.448 26.155 ;
     RECT  2.4 25.091 3.768 26.243 ;
     RECT  26.064 26.101 26.088 26.283 ;
     RECT  29.28 24.131 29.928 26.421 ;
     RECT  39.888 25.427 40.512 26.437 ;
     RECT  28.8 26.421 29.928 26.509 ;
     RECT  39.12 26.437 40.512 26.539 ;
     RECT  6.864 21.483 8.52 26.771 ;
     RECT  27.216 26.229 27.24 26.795 ;
     RECT  76.944 26.707 76.968 26.795 ;
     RECT  67.008 25.331 67.512 26.835 ;
     RECT  67.008 26.835 67.608 26.923 ;
     RECT  13.2 21.395 13.512 27.317 ;
     RECT  56.4 25.387 56.808 27.359 ;
     RECT  53.376 27.283 53.4 27.371 ;
     RECT  59.28 27.283 59.304 27.371 ;
     RECT  11.376 27.301 11.4 27.385 ;
     RECT  56.256 27.359 56.808 27.443 ;
     RECT  66 27.359 66.024 27.443 ;
     RECT  37.632 27.603 37.656 27.691 ;
     RECT  56.4 27.443 56.808 27.731 ;
     RECT  2.4 26.243 3.624 27.765 ;
     RECT  18.6 25.609 18.912 27.859 ;
     RECT  2.4 27.765 3.816 27.875 ;
     RECT  32.496 27.829 32.52 27.913 ;
     RECT  50.784 26.041 51.312 27.935 ;
     RECT  13.104 27.317 13.512 27.947 ;
     RECT  18.384 27.859 18.912 27.947 ;
     RECT  43.776 27.859 43.8 27.947 ;
     RECT  16.56 25.139 16.584 27.971 ;
     RECT  50.064 27.935 51.312 28.019 ;
     RECT  71.04 25.801 71.064 28.021 ;
     RECT  71.04 28.021 71.304 28.115 ;
     RECT  40.032 26.539 40.512 28.309 ;
     RECT  72.6 25.801 72.912 28.371 ;
     RECT  39.984 28.309 40.512 28.395 ;
     RECT  72.6 28.371 73.032 28.459 ;
     RECT  6.24 27.877 6.264 28.489 ;
     RECT  22.176 28.405 22.2 28.489 ;
     RECT  75.792 21.163 75.816 28.511 ;
     RECT  29.28 26.509 29.928 28.533 ;
     RECT  75.792 28.511 75.96 28.595 ;
     RECT  29.04 28.533 29.928 28.837 ;
     RECT  45.6 25.485 45.912 28.837 ;
     RECT  41.952 28.755 41.976 28.843 ;
     RECT  29.04 28.837 30.792 28.921 ;
     RECT  45.6 28.837 46.776 28.921 ;
     RECT  29.04 28.921 30.552 29.027 ;
     RECT  29.28 29.027 30.552 29.065 ;
     RECT  36.72 28.981 36.744 29.065 ;
     RECT  18.6 27.947 18.912 29.365 ;
     RECT  61.8 25.475 62.112 29.365 ;
     RECT  16.8 29.331 16.824 29.419 ;
     RECT  63.696 29.365 63.72 29.449 ;
     RECT  10.8 29.365 10.824 29.459 ;
     RECT  53.472 29.365 53.496 29.459 ;
     RECT  61.68 29.365 62.112 29.459 ;
     RECT  18.6 29.365 19.032 29.699 ;
     RECT  34.8 25.165 35.112 30.181 ;
     RECT  5.088 25.771 5.16 30.227 ;
     RECT  13.2 27.947 13.512 30.291 ;
     RECT  13.2 30.291 13.848 30.379 ;
     RECT  34.56 30.181 35.112 30.379 ;
     RECT  59.28 29.893 59.304 30.379 ;
     RECT  69.168 30.291 69.192 30.379 ;
     RECT  56.4 27.731 56.712 30.453 ;
     RECT  26.16 30.469 26.184 30.571 ;
     RECT  45.6 28.921 45.912 30.675 ;
     RECT  55.824 30.453 56.712 30.675 ;
     RECT  44.64 30.675 45.912 30.763 ;
     RECT  55.488 30.675 56.712 30.763 ;
     RECT  20.64 30.773 20.664 30.861 ;
     RECT  50.784 28.019 51.312 30.931 ;
     RECT  56.4 30.763 56.712 30.949 ;
     RECT  50.784 30.931 52.152 31.019 ;
     RECT  56.4 30.949 57 31.033 ;
     RECT  73.92 31.059 73.944 31.147 ;
     RECT  40.032 28.395 40.512 31.285 ;
     RECT  39.888 31.285 40.512 31.369 ;
     RECT  16.512 31.343 16.536 31.427 ;
     RECT  41.952 31.343 41.976 31.427 ;
     RECT  47.328 31.343 47.352 31.427 ;
     RECT  63.216 31.507 63.24 31.595 ;
     RECT  71.04 28.115 71.064 31.861 ;
     RECT  33.024 31.861 33.048 31.945 ;
     RECT  49.584 31.861 49.608 31.945 ;
     RECT  71.04 31.861 71.352 31.945 ;
     RECT  36.72 31.919 36.744 32.003 ;
     RECT  5.088 30.227 5.112 32.211 ;
     RECT  5.088 32.211 5.304 32.299 ;
     RECT  61.8 29.459 62.112 32.351 ;
     RECT  61.68 32.351 62.112 32.435 ;
     RECT  53.856 32.403 53.88 32.491 ;
     RECT  58.8 32.495 58.824 32.683 ;
     RECT  13.2 30.379 13.512 32.693 ;
     RECT  12.432 32.693 13.512 32.781 ;
     RECT  18.6 29.699 18.912 33.013 ;
     RECT  23.52 24.973 24.456 33.235 ;
     RECT  22.944 33.235 24.456 33.253 ;
     RECT  78 8.003 83.712 33.311 ;
     RECT  10.8 33.253 10.824 33.337 ;
     RECT  22.944 33.253 24.552 33.337 ;
     RECT  77.472 33.311 83.712 33.395 ;
     RECT  67.008 26.923 67.512 33.427 ;
     RECT  18.48 33.013 18.912 33.461 ;
     RECT  66.96 33.427 67.512 33.515 ;
     RECT  69.456 33.461 69.48 33.549 ;
     RECT  71.04 31.945 71.064 33.635 ;
     RECT  18.48 33.461 19.176 33.643 ;
     RECT  34.8 30.379 35.112 33.717 ;
     RECT  75.792 28.595 75.816 33.717 ;
     RECT  63.312 33.647 63.336 33.731 ;
     RECT  49.536 33.717 49.56 33.805 ;
     RECT  74.832 33.717 75.816 33.805 ;
     RECT  34.8 33.717 35.256 34.219 ;
     RECT  27.312 34.223 27.336 34.307 ;
     RECT  22.944 33.337 24.456 34.485 ;
     RECT  50.784 31.019 51.312 34.655 ;
     RECT  22.656 34.485 24.456 34.707 ;
     RECT  15.408 34.645 15.432 34.731 ;
     RECT  50.784 34.655 51.912 34.739 ;
     RECT  22.32 34.707 24.456 34.795 ;
     RECT  5.088 32.299 5.112 34.799 ;
     RECT  72.6 28.459 72.912 34.799 ;
     RECT  13.2 32.781 13.512 34.805 ;
     RECT  5.088 34.799 5.16 34.883 ;
     RECT  47.28 34.799 47.304 34.883 ;
     RECT  60.432 34.799 60.456 34.883 ;
     RECT  71.808 34.799 72.912 34.883 ;
     RECT  13.2 34.805 14.28 34.893 ;
     RECT  37.824 34.805 37.848 34.931 ;
     RECT  67.2 33.515 67.512 35.269 ;
     RECT  7.8 26.771 8.52 35.317 ;
     RECT  22.656 34.795 24.456 35.605 ;
     RECT  61.8 32.435 62.112 35.605 ;
     RECT  60.528 35.605 62.112 35.755 ;
     RECT  22.656 35.605 25.176 35.819 ;
     RECT  54.48 35.731 54.504 35.819 ;
     RECT  63.552 35.605 63.576 35.819 ;
     RECT  67.2 35.269 67.608 35.819 ;
     RECT  13.2 34.893 13.512 35.893 ;
     RECT  13.056 35.893 13.512 35.923 ;
     RECT  13.056 35.923 14.328 35.987 ;
     RECT  13.2 35.987 14.328 36.011 ;
     RECT  23.52 35.819 25.176 36.011 ;
     RECT  31.92 35.941 31.944 36.025 ;
     RECT  78 33.395 83.712 36.051 ;
     RECT  7.68 35.317 8.52 36.075 ;
     RECT  10.848 35.999 10.872 36.083 ;
     RECT  77.28 36.051 83.712 36.139 ;
     RECT  15.84 35.893 15.864 36.203 ;
     RECT  34.8 34.219 35.112 36.213 ;
     RECT  78 36.139 83.712 36.275 ;
     RECT  34.8 36.213 35.208 36.301 ;
     RECT  18.6 33.643 18.912 36.325 ;
     RECT  18.6 36.325 19.368 36.435 ;
     RECT  45.6 30.763 45.912 36.469 ;
     RECT  18.6 36.435 20.328 36.523 ;
     RECT  44.976 36.469 46.824 36.553 ;
     RECT  55.344 36.469 55.368 36.563 ;
     RECT  64.704 35.749 64.728 36.715 ;
     RECT  69.264 36.627 69.288 36.715 ;
     RECT  56.4 31.033 56.712 36.789 ;
     RECT  37.968 36.469 38.28 36.843 ;
     RECT  55.488 36.789 56.712 36.877 ;
     RECT  29.28 29.065 29.928 36.883 ;
     RECT  75.792 33.805 75.816 36.883 ;
     RECT  23.52 36.011 24.456 36.901 ;
     RECT  23.376 36.901 24.456 36.947 ;
     RECT  20.304 36.523 20.328 36.971 ;
     RECT  29.28 36.883 30.36 36.971 ;
     RECT  75.072 36.883 75.816 36.971 ;
     RECT  23.376 36.947 24.312 36.985 ;
     RECT  27.888 36.911 27.912 36.995 ;
     RECT  50.784 34.739 51.312 37.011 ;
     RECT  61.8 35.755 62.112 37.011 ;
     RECT  23.472 36.985 24.312 37.035 ;
     RECT  50.448 37.011 51.312 37.104 ;
     RECT  52.464 37.045 52.488 37.139 ;
     RECT  72.6 34.883 72.912 37.173 ;
     RECT  50.496 37.104 51.312 37.187 ;
     RECT  5.088 34.883 5.112 37.267 ;
     RECT  59.184 37.173 59.208 37.283 ;
     RECT  71.712 37.173 72.912 37.283 ;
     RECT  61.8 37.011 62.808 37.355 ;
     RECT  50.784 37.187 51.312 37.475 ;
     RECT  5.088 37.267 5.736 37.483 ;
     RECT  55.872 36.877 56.712 37.619 ;
     RECT  37.536 37.557 37.56 37.645 ;
     RECT  42.192 37.621 42.216 37.715 ;
     RECT  7.8 36.075 8.52 38.005 ;
     RECT  15.984 37.971 16.008 38.059 ;
     RECT  7.68 38.005 8.52 38.099 ;
     RECT  67.2 35.819 67.512 38.197 ;
     RECT  67.2 38.197 67.8 38.291 ;
     RECT  34.8 36.301 35.112 38.325 ;
     RECT  48.192 38.325 48.216 38.341 ;
     RECT  48.192 38.341 48.456 38.413 ;
     RECT  48.432 38.413 48.456 38.443 ;
     RECT  23.52 37.035 24.312 38.447 ;
     RECT  34.8 38.325 35.448 38.507 ;
     RECT  23.52 38.447 25.128 38.531 ;
     RECT  78 36.275 80.856 38.547 ;
     RECT  82.128 36.275 83.712 38.547 ;
     RECT  78 38.547 83.712 38.635 ;
     RECT  78 38.635 80.856 38.675 ;
     RECT  31.632 38.325 31.656 38.771 ;
     RECT  45.6 36.553 45.912 38.773 ;
     RECT  78 38.675 79.8 38.773 ;
     RECT  45.456 38.773 45.912 38.867 ;
     RECT  64.992 38.773 65.016 38.867 ;
     RECT  77.232 38.773 79.8 38.867 ;
     RECT  29.28 36.971 29.928 38.901 ;
     RECT  61.8 37.355 62.112 39.061 ;
     RECT  61.344 39.061 62.112 39.147 ;
     RECT  29.28 38.901 30.12 39.203 ;
     RECT  78 38.867 79.8 39.347 ;
     RECT  2.4 27.875 3.624 39.395 ;
     RECT  76.848 39.349 76.872 39.443 ;
     RECT  13.2 36.011 13.512 39.599 ;
     RECT  69.696 39.571 69.72 39.659 ;
     RECT  13.2 39.599 14.232 39.683 ;
     RECT  18.6 36.523 18.912 39.839 ;
     RECT  7.8 38.099 8.52 39.861 ;
     RECT  10.608 39.589 10.632 39.915 ;
     RECT  21.072 39.829 21.096 39.915 ;
     RECT  17.664 39.839 18.912 39.923 ;
     RECT  29.28 39.203 29.928 40.165 ;
     RECT  5.088 37.483 5.112 40.181 ;
     RECT  23.52 38.531 24.312 40.181 ;
     RECT  50.832 37.475 51.312 40.181 ;
     RECT  56.4 37.619 56.712 40.181 ;
     RECT  2.4 39.395 2.952 40.235 ;
     RECT  7.8 39.861 9.24 40.235 ;
     RECT  48.72 40.147 48.744 40.235 ;
     RECT  55.152 40.147 55.176 40.235 ;
     RECT  38.352 40.181 38.376 40.269 ;
     RECT  56.4 40.181 56.808 40.269 ;
     RECT  4.704 40.181 5.112 40.307 ;
     RECT  15.936 39.605 15.96 40.307 ;
     RECT  50.256 40.181 51.312 40.307 ;
     RECT  40.032 31.369 40.512 40.403 ;
     RECT  29.088 40.165 29.928 40.499 ;
     RECT  22.848 40.181 24.312 40.595 ;
     RECT  29.28 40.499 29.928 40.595 ;
     RECT  67.2 38.291 67.512 40.693 ;
     RECT  75.792 36.971 75.816 40.981 ;
     RECT  7.8 40.235 8.52 41.077 ;
     RECT  40.2 40.403 40.512 41.125 ;
     RECT  67.2 40.693 67.608 41.131 ;
     RECT  75.792 40.981 76.728 41.131 ;
     RECT  7.104 41.077 8.52 41.161 ;
     RECT  33.6 40.981 33.624 41.195 ;
     RECT  36.816 41.107 36.84 41.195 ;
     RECT  40.2 41.125 41.064 41.209 ;
     RECT  7.2 41.161 8.52 41.235 ;
     RECT  72.6 37.283 72.912 41.235 ;
     RECT  7.2 41.235 8.664 41.323 ;
     RECT  72.48 41.235 72.912 41.323 ;
     RECT  59.28 41.327 59.304 41.411 ;
     RECT  44.208 41.413 44.232 41.515 ;
     RECT  61.8 39.147 62.112 41.589 ;
     RECT  63.264 41.567 63.288 41.651 ;
     RECT  61.632 41.589 62.112 41.677 ;
     RECT  7.2 41.323 8.52 41.891 ;
     RECT  7.2 41.891 8.112 41.939 ;
     RECT  74.64 41.893 74.664 41.977 ;
     RECT  22.848 40.595 22.872 42.143 ;
     RECT  22.752 42.143 22.872 42.219 ;
     RECT  22.752 42.219 22.776 42.227 ;
     RECT  45.6 38.867 45.912 42.229 ;
     RECT  43.488 42.229 43.512 42.323 ;
     RECT  45.6 42.229 46.536 42.323 ;
     RECT  2.4 40.235 2.712 42.357 ;
     RECT  9.552 42.325 9.576 42.411 ;
     RECT  67.2 41.131 67.512 42.421 ;
     RECT  69.024 42.387 69.048 42.421 ;
     RECT  72.6 41.323 72.912 42.451 ;
     RECT  2.4 42.357 3.624 42.467 ;
     RECT  69.024 42.421 69.528 42.475 ;
     RECT  18.6 39.923 18.912 42.479 ;
     RECT  67.104 42.421 67.512 42.505 ;
     RECT  69.504 42.475 69.528 42.539 ;
     RECT  72.048 42.451 72.912 42.539 ;
     RECT  18.48 42.479 18.912 42.563 ;
     RECT  56.4 40.269 56.712 42.613 ;
     RECT  79.776 39.347 79.8 42.613 ;
     RECT  80.832 38.675 80.856 42.613 ;
     RECT  53.136 42.579 53.16 42.667 ;
     RECT  14.784 42.613 14.808 42.697 ;
     RECT  55.584 42.613 56.712 42.707 ;
     RECT  18.6 42.563 18.912 42.741 ;
     RECT  20.064 42.485 20.088 42.741 ;
     RECT  50.832 40.307 51.312 42.741 ;
     RECT  79.776 42.613 80.856 42.755 ;
     RECT  48.672 42.613 48.696 42.795 ;
     RECT  18.6 42.741 20.088 42.803 ;
     RECT  50.736 42.741 51.312 42.829 ;
     RECT  18.6 42.803 19.368 42.899 ;
     RECT  29.28 40.595 29.712 42.933 ;
     RECT  28.512 42.933 29.712 43.021 ;
     RECT  29.28 43.021 29.712 43.331 ;
     RECT  78 39.347 78.744 43.509 ;
     RECT  79.776 42.755 79.8 43.509 ;
     RECT  78 43.509 79.8 43.597 ;
     RECT  32.496 43.669 32.52 43.755 ;
     RECT  30.816 43.317 30.84 43.811 ;
     RECT  25.632 43.813 25.656 43.897 ;
     RECT  82.128 38.635 83.712 44.339 ;
     RECT  15.984 44.447 16.008 44.531 ;
     RECT  5.088 40.307 5.112 44.579 ;
     RECT  27.792 44.469 27.816 44.579 ;
     RECT  75.792 41.131 75.816 44.661 ;
     RECT  74.064 44.639 74.088 44.723 ;
     RECT  7.8 41.939 8.112 44.773 ;
     RECT  72.6 42.539 72.912 44.853 ;
     RECT  75.792 44.661 76.008 44.867 ;
     RECT  9.84 44.853 9.864 44.941 ;
     RECT  72.6 44.853 73.272 44.941 ;
     RECT  7.248 44.773 8.112 45.035 ;
     RECT  4.512 44.965 4.536 45.049 ;
     RECT  5.856 44.981 5.88 45.443 ;
     RECT  79.776 43.597 79.8 45.557 ;
     RECT  80.832 42.755 80.856 45.557 ;
     RECT  79.776 45.557 80.856 45.923 ;
     RECT  82.128 44.339 82.2 46.501 ;
     RECT  83.28 44.339 83.712 46.501 ;
     RECT  82.128 46.501 83.712 46.585 ;
     RECT  82.128 46.585 82.2 46.739 ;
     RECT  83.28 46.585 83.712 46.739 ;
     RECT  78 43.597 78.744 46.741 ;
     RECT  79.776 45.923 79.8 46.787 ;
     RECT  77.904 46.741 78.744 46.827 ;
     RECT  80.832 45.923 80.856 48.659 ;
     RECT  78 46.827 78.744 48.693 ;
     RECT  78 48.693 78.84 48.723 ;
     RECT  78 48.723 78.936 48.811 ;
     RECT  80.928 48.757 80.952 48.841 ;
     RECT  82.176 46.739 82.2 49.043 ;
     RECT  43.728 57.263 43.752 57.347 ;
     RECT  42.144 57.503 42.168 57.587 ;
     RECT  75.792 44.867 75.816 65.603 ;
     RECT  78 48.811 78.744 69.011 ;
     RECT  86.208 88.693 86.232 88.883 ;
     RECT  42.864 91.813 42.888 91.897 ;
     RECT  43.2 91.987 43.224 92.075 ;
     RECT  54.912 107.183 54.936 108.267 ;
     RECT  33.6 112.117 33.624 112.223 ;
     RECT  33.504 112.223 33.624 112.307 ;
     RECT  33.6 112.307 33.624 112.355 ;
     RECT  45.6 42.323 45.912 123.119 ;
     RECT  45.6 123.119 46.2 123.203 ;
     RECT  47.28 123.411 47.304 123.499 ;
     RECT  58.128 129.397 58.152 129.491 ;
     RECT  58.176 129.541 58.2 129.643 ;
     RECT  31.296 134.517 31.32 134.605 ;
     RECT  31.632 135.013 31.656 135.097 ;
     RECT  81.072 178.323 81.096 178.411 ;
     RECT  44.448 178.549 44.472 178.633 ;
     RECT  2.4 42.467 2.712 178.981 ;
     RECT  18.6 42.899 18.912 179.539 ;
     RECT  24 40.595 24.312 179.539 ;
     RECT  72.6 44.941 72.912 179.573 ;
     RECT  17.712 179.539 18.912 179.627 ;
     RECT  24 179.539 24.504 179.627 ;
     RECT  31.248 179.539 31.272 179.627 ;
     RECT  80.928 179.567 80.952 179.651 ;
     RECT  10.848 179.573 10.872 179.661 ;
     RECT  38.064 179.573 38.088 179.661 ;
     RECT  65.28 179.573 65.304 179.661 ;
     RECT  83.4 46.739 83.712 179.797 ;
     RECT  78 69.011 78.312 179.859 ;
     RECT  78 179.859 78.648 179.947 ;
     RECT  53.424 179.461 53.448 180.131 ;
     RECT  54.576 179.461 54.6 180.131 ;
     RECT  69.888 179.461 69.912 180.131 ;
     RECT  2.4 178.981 2.856 180.133 ;
     RECT  5.04 179.573 5.064 180.179 ;
     RECT  58.608 179.269 58.632 180.227 ;
     RECT  2.4 180.133 3.384 180.661 ;
     RECT  82.512 179.797 83.712 180.661 ;
     RECT  0.144 180.565 0.168 180.853 ;
     RECT  1.296 179.749 1.32 180.853 ;
     RECT  0.144 180.853 1.32 181.189 ;
     RECT  2.4 180.661 3.96 181.189 ;
     RECT  13.2 39.683 13.512 181.237 ;
     RECT  18.6 179.627 18.912 181.237 ;
     RECT  29.4 43.331 29.712 181.237 ;
     RECT  34.8 38.507 35.112 181.237 ;
     RECT  51 42.829 51.312 181.237 ;
     RECT  56.4 42.707 56.712 181.237 ;
     RECT  67.2 42.505 67.512 181.237 ;
     RECT  72.192 179.573 72.912 181.237 ;
     RECT  78 179.947 78.312 181.237 ;
     RECT  82.416 180.661 83.712 181.237 ;
     RECT  9.504 181.237 14.808 181.547 ;
     RECT  15.936 181.237 16.968 181.547 ;
     RECT  18.048 181.237 18.912 181.547 ;
     RECT  28.224 181.237 32.088 181.547 ;
     RECT  33.264 181.237 37.368 181.547 ;
     RECT  46.992 181.237 49.368 181.547 ;
     RECT  50.496 181.237 57.576 181.547 ;
     RECT  65.712 181.237 74.856 181.547 ;
     RECT  45.6 123.203 45.912 181.573 ;
     RECT  71.328 181.547 72.792 181.611 ;
     RECT  13.344 181.547 13.368 181.675 ;
     RECT  28.224 181.547 30.936 181.675 ;
     RECT  16.944 181.547 16.968 181.717 ;
     RECT  47.904 181.547 49.368 181.717 ;
     RECT  50.496 181.547 51.288 181.717 ;
     RECT  82.416 181.237 84.36 181.717 ;
     RECT  82.416 181.717 84.936 181.802 ;
     RECT  85.92 181.717 85.944 181.802 ;
     RECT  15.024 181.717 15.72 181.803 ;
     RECT  16.944 181.717 17.784 181.803 ;
     RECT  28.224 181.675 28.872 181.803 ;
     RECT  30.288 181.675 30.936 181.803 ;
     RECT  32.304 181.717 33 181.803 ;
     RECT  34.368 181.547 37.368 181.803 ;
     RECT  47.904 181.717 51.288 181.803 ;
     RECT  52.32 181.547 52.344 181.803 ;
     RECT  53.76 181.547 53.784 181.803 ;
     RECT  67.2 181.547 67.56 181.803 ;
     RECT  69.6 181.547 69.624 181.803 ;
     RECT  71.328 181.611 72.216 181.803 ;
     RECT  74.256 181.547 74.856 181.803 ;
     RECT  82.416 181.802 85.944 181.803 ;
     RECT  0.144 181.189 3.96 181.813 ;
     RECT  7.8 45.035 8.112 181.813 ;
     RECT  18.864 181.547 18.912 181.813 ;
     RECT  21.504 181.237 21.528 181.813 ;
     RECT  24 179.627 24.312 181.813 ;
     RECT  27.072 180.133 27.096 181.813 ;
     RECT  28.224 181.803 28.488 181.813 ;
     RECT  36.432 181.803 37.368 181.813 ;
     RECT  40.2 41.209 40.512 181.813 ;
     RECT  45.552 181.573 45.912 181.813 ;
     RECT  56.352 181.547 57.576 181.813 ;
     RECT  61.8 41.677 62.112 181.813 ;
     RECT  77.472 181.237 78.312 181.813 ;
     RECT  80.976 180.565 81 181.813 ;
     RECT  82.416 181.803 85.656 181.813 ;
     RECT  75.12 181.813 85.656 181.931 ;
     RECT  75.12 181.931 84.216 182.931 ;
     RECT  85.632 181.931 85.656 182.931 ;
     RECT  75.12 182.931 85.656 182.955 ;
     RECT  75.12 182.955 84.984 183.019 ;
     RECT  16.944 181.803 16.968 183.531 ;
     RECT  18.864 181.813 28.488 183.531 ;
     RECT  36.432 181.813 46.728 183.531 ;
     RECT  51.264 181.803 51.288 183.531 ;
     RECT  0.144 181.813 9.24 183.568 ;
     RECT  18.864 183.531 27.96 183.568 ;
     RECT  37.632 183.531 46.728 183.568 ;
     RECT  56.352 181.813 65.448 183.568 ;
     RECT  75.12 183.019 84.216 183.568 ;
    LAYER M6 ;
     RECT  2.16 24.129 2.821 24.801 ;
     RECT  2.16 40.329 2.917 41.001 ;
     RECT  2.16 34.929 3.317 35.601 ;
     RECT  3.317 34.304 3.395 35.601 ;
     RECT  2.16 7.929 3.397 8.601 ;
     RECT  2.16 29.529 3.397 30.201 ;
     RECT  3.397 29.376 3.499 30.201 ;
     RECT  3.573 42.368 3.646 42.4 ;
     RECT  3.397 7.36 3.781 8.601 ;
     RECT  3.445 27.776 3.838 27.808 ;
     RECT  3.781 6.208 3.883 8.601 ;
     RECT  3.883 7.296 3.898 8.601 ;
     RECT  2.16 45.729 4.501 46.401 ;
     RECT  2.16 180.729 5.029 181.401 ;
     RECT  2.16 2.529 5.077 3.201 ;
     RECT  3.395 34.816 5.171 35.601 ;
     RECT  2.821 24.129 5.363 25.76 ;
     RECT  3.397 37.312 5.701 37.344 ;
     RECT  5.363 24.129 5.73 25.696 ;
     RECT  5.701 37.312 5.747 37.472 ;
     RECT  5.73 23.168 5.803 25.696 ;
     RECT  3.499 29.529 6.229 30.201 ;
     RECT  5.171 34.929 7.093 35.601 ;
     RECT  2.917 40.192 7.093 41.001 ;
     RECT  6.229 27.904 7.147 30.201 ;
     RECT  7.093 40.192 7.189 41.12 ;
     RECT  4.501 44.992 7.237 46.401 ;
     RECT  7.189 40.192 7.467 41.888 ;
     RECT  5.803 24.129 7.475 25.632 ;
     RECT  5.747 37.44 7.65 37.472 ;
     RECT  7.093 34.929 7.654 36 ;
     RECT  5.077 2.529 7.715 4.448 ;
     RECT  7.65 37.44 7.723 38.048 ;
     RECT  7.723 38.016 7.979 38.048 ;
     RECT  5.749 21.44 8.243 21.472 ;
     RECT  7.147 28.416 8.243 30.201 ;
     RECT  3.205 32.256 8.243 32.288 ;
     RECT  8.245 0.128 8.483 0.16 ;
     RECT  7.467 40.192 9.205 41.312 ;
     RECT  5.029 179.584 9.461 181.401 ;
     RECT  9.205 39.872 9.525 41.312 ;
     RECT  9.525 39.872 9.579 42.4 ;
     RECT  3.898 7.36 9.589 8.601 ;
     RECT  9.579 42.368 9.598 42.4 ;
     RECT  9.589 7.36 9.845 9.184 ;
     RECT  9.781 0.576 9.875 0.608 ;
     RECT  7.237 44.864 9.875 46.401 ;
     RECT  9.845 6.848 9.923 9.184 ;
     RECT  9.923 7.36 10.259 9.184 ;
     RECT  7.715 2.529 10.357 4.128 ;
     RECT  10.357 1.152 10.499 4.128 ;
     RECT  9.579 39.872 10.643 41.001 ;
     RECT  8.243 29.529 10.789 30.201 ;
     RECT  10.741 10.304 10.835 10.336 ;
     RECT  7.654 34.929 10.883 36.064 ;
     RECT  10.499 1.728 11.253 4.128 ;
     RECT  10.259 7.36 11.253 8.601 ;
     RECT  11.253 6.208 11.307 8.601 ;
     RECT  11.307 6.208 11.326 6.496 ;
     RECT  11.307 7.808 11.573 8.601 ;
     RECT  7.475 24.129 11.651 24.928 ;
     RECT  11.029 22.4 12.021 22.432 ;
     RECT  11.189 0.192 12.035 0.224 ;
     RECT  11.573 7.808 12.035 9.184 ;
     RECT  12.021 21.312 12.075 22.432 ;
     RECT  11.326 6.464 12.094 6.496 ;
     RECT  11.253 1.728 12.206 4.32 ;
     RECT  12.206 0.576 12.275 4.32 ;
     RECT  12.075 21.312 12.323 21.344 ;
     RECT  10.789 33.28 12.421 33.312 ;
     RECT  10.789 29.376 12.469 30.201 ;
     RECT  12.421 32.704 12.523 33.312 ;
     RECT  11.189 10.816 12.563 10.848 ;
     RECT  12.035 7.808 13.026 8.736 ;
     RECT  11.365 27.328 13.093 27.36 ;
     RECT  13.026 7.424 13.099 8.736 ;
     RECT  13.093 27.328 13.139 27.936 ;
     RECT  13.139 27.904 13.163 27.936 ;
     RECT  12.469 29.376 13.163 30.368 ;
     RECT  9.461 179.584 13.301 181.536 ;
     RECT  13.301 179.584 13.379 181.664 ;
     RECT  13.163 29.529 13.859 30.368 ;
     RECT  13.099 7.929 13.877 8.736 ;
     RECT  13.365 0.192 13.934 0.224 ;
     RECT  12.275 1.728 13.934 4.32 ;
     RECT  13.934 0.192 14.003 4.32 ;
     RECT  14.003 1.728 14.197 4.32 ;
     RECT  10.643 40.329 14.197 41.001 ;
     RECT  10.883 34.929 14.245 36 ;
     RECT  14.245 34.816 14.261 36 ;
     RECT  14.197 1.728 14.266 4.576 ;
     RECT  13.877 7.929 14.531 9.184 ;
     RECT  11.651 24.129 14.773 24.801 ;
     RECT  14.754 10.816 14.827 10.848 ;
     RECT  13.379 179.584 15.013 181.536 ;
     RECT  2.16 18.729 15.349 19.401 ;
     RECT  14.261 34.688 15.443 36 ;
     RECT  14.003 0.192 15.589 0.224 ;
     RECT  9.875 45.729 15.669 46.401 ;
     RECT  14.773 42.624 15.723 42.656 ;
     RECT  15.013 179.584 15.731 181.792 ;
     RECT  15.589 0.192 15.733 0.352 ;
     RECT  14.266 1.728 15.733 4.32 ;
     RECT  15.443 34.929 15.829 36 ;
     RECT  15.669 44.48 16.019 46.401 ;
     RECT  15.829 34.929 16.043 36.192 ;
     RECT  15.973 38.016 16.043 38.048 ;
     RECT  14.197 39.616 16.043 41.001 ;
     RECT  14.531 7.929 16.181 8.736 ;
     RECT  16.181 7.929 16.259 9.76 ;
     RECT  13.859 29.529 16.501 30.201 ;
     RECT  16.309 10.24 16.555 10.272 ;
     RECT  16.501 29.376 16.57 31.392 ;
     RECT  15.733 0.192 16.691 4.32 ;
     RECT  15.685 22.656 16.875 22.688 ;
     RECT  16.691 0.192 16.883 4.192 ;
     RECT  15.349 18.729 16.979 20.32 ;
     RECT  16.933 183.488 17.131 183.52 ;
     RECT  15.731 179.584 17.39 181.536 ;
     RECT  16.883 2.304 17.411 4.192 ;
     RECT  14.773 24.129 17.557 24.928 ;
     RECT  16.043 39.872 17.699 41.001 ;
     RECT  17.39 179.584 17.795 181.792 ;
     RECT  16.259 7.929 17.909 8.601 ;
     RECT  17.909 7.808 17.987 8.601 ;
     RECT  16.883 0.192 18.283 0.608 ;
     RECT  18.283 0.512 18.293 0.608 ;
     RECT  18.293 0.512 18.371 1.184 ;
     RECT  18.357 27.904 18.43 27.936 ;
     RECT  17.795 179.584 18.603 181.536 ;
     RECT  18.371 0.512 19.043 0.544 ;
     RECT  16.57 29.376 19.043 30.201 ;
     RECT  18.469 33.6 19.141 33.632 ;
     RECT  19.141 33.472 19.187 33.632 ;
     RECT  17.557 24.129 19.333 25.056 ;
     RECT  17.589 26.496 19.333 26.528 ;
     RECT  16.043 34.929 19.333 36 ;
     RECT  18.469 42.496 19.333 42.528 ;
     RECT  19.333 24.129 19.554 26.528 ;
     RECT  19.554 23.168 19.627 26.528 ;
     RECT  19.333 42.496 20.099 42.784 ;
     RECT  19.333 34.929 20.293 36.512 ;
     RECT  17.411 2.529 20.579 4.192 ;
     RECT  19.043 29.529 20.629 30.201 ;
     RECT  19.187 33.472 20.661 33.504 ;
     RECT  20.629 29.529 20.715 30.816 ;
     RECT  20.661 33.472 20.715 33.632 ;
     RECT  17.699 40.329 21.061 41.001 ;
     RECT  19.573 20.736 21.587 20.768 ;
     RECT  19.627 24.129 21.779 26.528 ;
     RECT  20.715 29.529 22.165 30.201 ;
     RECT  20.715 33.6 22.309 33.632 ;
     RECT  20.293 34.929 22.309 36.96 ;
     RECT  21.061 39.872 22.325 41.001 ;
     RECT  20.099 42.752 22.507 42.784 ;
     RECT  22.325 38.784 22.517 41.001 ;
     RECT  22.309 33.6 22.699 36.96 ;
     RECT  22.699 34.929 22.709 36.96 ;
     RECT  22.517 38.464 22.741 41.001 ;
     RECT  22.741 38.464 22.883 42.208 ;
     RECT  22.699 33.6 22.933 33.632 ;
     RECT  22.933 33.28 22.979 33.632 ;
     RECT  21.779 24.129 23.461 24.801 ;
     RECT  22.709 34.929 23.507 37.024 ;
     RECT  22.883 38.464 23.699 41.001 ;
     RECT  22.165 28.416 24.354 30.201 ;
     RECT  24.354 27.904 24.358 30.201 ;
     RECT  16.979 18.729 24.373 19.401 ;
     RECT  21.779 26.496 24.373 26.528 ;
     RECT  24.358 27.904 24.373 30.56 ;
     RECT  24.117 22.272 24.427 22.304 ;
     RECT  24.373 26.496 24.427 30.56 ;
     RECT  24.427 26.496 24.437 27.808 ;
     RECT  23.461 24.129 24.491 24.928 ;
     RECT  24.437 26.24 24.491 27.808 ;
     RECT  24.373 18.729 24.563 20.512 ;
     RECT  22.979 33.28 24.563 33.312 ;
     RECT  20.579 2.529 24.661 4.128 ;
     RECT  23.699 38.464 25.139 38.944 ;
     RECT  23.507 34.929 25.515 36 ;
     RECT  24.491 26.24 27.251 26.784 ;
     RECT  25.515 34.929 27.301 35.744 ;
     RECT  24.427 29.529 27.371 30.56 ;
     RECT  27.301 34.24 27.371 35.744 ;
     RECT  17.987 7.929 27.701 8.601 ;
     RECT  25.621 43.84 27.781 43.872 ;
     RECT  16.019 45.729 27.781 46.401 ;
     RECT  27.781 43.84 27.829 46.401 ;
     RECT  24.491 24.129 27.877 24.801 ;
     RECT  27.371 34.929 27.877 35.744 ;
     RECT  27.829 43.328 27.883 46.401 ;
     RECT  24.661 2.529 27.95 4.384 ;
     RECT  27.701 7.808 27.971 8.601 ;
     RECT  18.603 179.584 28.194 181.401 ;
     RECT  27.95 2.304 28.213 4.384 ;
     RECT  27.883 43.328 28.501 43.36 ;
     RECT  27.877 23.296 28.523 24.801 ;
     RECT  28.453 183.488 28.587 183.52 ;
     RECT  28.213 1.728 28.595 4.384 ;
     RECT  27.251 26.432 28.661 26.464 ;
     RECT  28.194 179.584 28.837 181.536 ;
     RECT  28.661 26.432 28.843 27.296 ;
     RECT  28.595 2.529 28.853 4.384 ;
     RECT  28.837 179.584 28.907 181.792 ;
     RECT  28.843 27.264 28.981 27.296 ;
     RECT  27.371 29.529 28.981 30.201 ;
     RECT  25.139 38.912 28.981 38.944 ;
     RECT  23.699 40.329 28.981 41.001 ;
     RECT  28.501 42.944 29.035 43.36 ;
     RECT  28.981 27.264 29.075 30.201 ;
     RECT  28.261 0.192 29.102 0.224 ;
     RECT  28.469 21.632 29.123 21.664 ;
     RECT  29.102 0.192 29.173 0.352 ;
     RECT  29.173 0.192 29.747 0.608 ;
     RECT  27.877 34.929 29.749 36.96 ;
     RECT  29.075 27.264 29.843 27.872 ;
     RECT  29.749 32.96 29.843 32.992 ;
     RECT  29.749 34.304 29.843 36.96 ;
     RECT  29.843 34.752 29.867 36.96 ;
     RECT  28.853 2.529 29.941 4.576 ;
     RECT  24.563 18.729 30.133 19.401 ;
     RECT  29.941 2.304 30.254 4.576 ;
     RECT  28.907 179.584 30.254 181.664 ;
     RECT  29.747 0.576 30.325 0.608 ;
     RECT  30.254 2.304 30.325 5.152 ;
     RECT  28.523 24 30.325 24.801 ;
     RECT  30.325 24 30.379 25.504 ;
     RECT  28.981 38.912 30.389 41.001 ;
     RECT  30.389 38.336 30.443 41.001 ;
     RECT  29.843 27.84 30.517 27.872 ;
     RECT  29.075 29.529 30.517 30.201 ;
     RECT  30.325 0.576 30.613 5.152 ;
     RECT  29.867 34.929 30.763 36.96 ;
     RECT  29.035 43.328 30.805 43.36 ;
     RECT  30.805 43.328 30.851 43.744 ;
     RECT  30.254 179.584 30.97 181.792 ;
     RECT  27.971 7.929 31.349 8.601 ;
     RECT  30.133 18.729 31.349 19.936 ;
     RECT  30.613 0.576 31.403 5.984 ;
     RECT  31.403 0.576 31.406 4.704 ;
     RECT  31.349 7.488 31.427 8.601 ;
     RECT  31.427 7.616 31.467 8.601 ;
     RECT  30.517 27.84 31.467 30.201 ;
     RECT  31.406 0.192 31.475 4.704 ;
     RECT  31.285 134.528 31.598 134.56 ;
     RECT  30.443 38.336 31.667 38.944 ;
     RECT  31.598 134.528 31.667 135.072 ;
     RECT  30.379 24.129 31.955 25.504 ;
     RECT  30.763 34.929 31.955 36 ;
     RECT  30.97 179.584 32.293 181.536 ;
     RECT  31.467 27.84 32.531 27.872 ;
     RECT  30.851 43.712 32.531 43.744 ;
     RECT  31.349 18.729 32.757 20.512 ;
     RECT  32.757 18.729 32.867 21.152 ;
     RECT  31.475 0.576 33.011 4.704 ;
     RECT  32.293 179.584 33.011 181.792 ;
     RECT  31.667 38.912 33.077 38.944 ;
     RECT  30.443 40.329 33.077 41.001 ;
     RECT  32.757 22.656 33.107 22.688 ;
     RECT  33.077 38.912 33.131 41.001 ;
     RECT  33.011 0.576 33.203 1.184 ;
     RECT  31.667 134.528 33.387 134.56 ;
     RECT  2.16 110.529 33.493 111.201 ;
     RECT  33.203 0.576 33.525 0.608 ;
     RECT  33.333 123.648 33.525 123.68 ;
     RECT  33.493 110.529 33.579 112.288 ;
     RECT  33.525 123.456 33.579 123.68 ;
     RECT  33.131 39.04 33.589 41.001 ;
     RECT  33.579 110.529 33.658 112.16 ;
     RECT  33.525 0.064 33.683 0.608 ;
     RECT  32.867 18.729 33.971 20.512 ;
     RECT  33.011 2.529 34.286 4.704 ;
     RECT  34.286 2.529 34.355 5.152 ;
     RECT  33.011 179.584 34.357 181.536 ;
     RECT  31.467 29.529 34.53 30.201 ;
     RECT  33.683 0.192 34.549 0.608 ;
     RECT  34.53 29.529 34.603 30.368 ;
     RECT  31.467 7.929 34.693 8.601 ;
     RECT  31.955 24.129 34.693 24.801 ;
     RECT  34.549 0.192 34.862 0.736 ;
     RECT  34.355 2.529 34.862 4.704 ;
     RECT  34.862 0.192 34.931 4.704 ;
     RECT  34.931 0.192 34.997 1.184 ;
     RECT  31.955 34.929 35.173 35.744 ;
     RECT  35.173 34.929 35.189 36.256 ;
     RECT  33.013 31.872 35.243 31.904 ;
     RECT  35.189 33.728 35.267 36.256 ;
     RECT  35.267 34.176 35.307 36.256 ;
     RECT  33.589 39.04 35.381 41.184 ;
     RECT  35.307 34.929 35.435 36.256 ;
     RECT  35.381 37.568 35.499 41.184 ;
     RECT  34.357 179.584 35.627 181.792 ;
     RECT  34.997 0.064 35.891 1.184 ;
     RECT  34.693 6.784 35.939 8.601 ;
     RECT  34.693 24.129 36.213 25.12 ;
     RECT  36.213 24 36.267 25.12 ;
     RECT  36.267 24 36.323 24.801 ;
     RECT  36.213 21.12 36.419 21.152 ;
     RECT  34.931 2.529 36.469 4.704 ;
     RECT  35.891 0.064 36.515 0.096 ;
     RECT  34.603 29.529 36.709 30.201 ;
     RECT  36.709 31.936 36.779 31.968 ;
     RECT  36.469 1.728 36.899 4.704 ;
     RECT  36.899 1.728 36.907 4.576 ;
     RECT  36.421 183.488 37.099 183.52 ;
     RECT  36.907 1.728 37.139 3.872 ;
     RECT  35.627 179.584 37.379 181.536 ;
     RECT  37.602 27.648 37.621 27.68 ;
     RECT  36.709 28.992 37.621 30.201 ;
     RECT  37.621 27.648 37.675 30.201 ;
     RECT  35.435 34.929 37.749 35.744 ;
     RECT  35.499 37.568 37.749 37.6 ;
     RECT  37.749 34.816 37.803 37.6 ;
     RECT  37.803 34.816 37.859 36.832 ;
     RECT  35.499 39.04 37.995 41.184 ;
     RECT  37.379 179.584 38.133 181.401 ;
     RECT  38.133 178.56 38.187 181.401 ;
     RECT  37.859 34.929 38.291 36.832 ;
     RECT  37.995 40.192 38.398 41.184 ;
     RECT  38.005 26.496 39.155 26.528 ;
     RECT  36.323 24.129 39.829 24.801 ;
     RECT  37.675 28.544 39.877 30.201 ;
     RECT  39.877 28.544 39.973 31.328 ;
     RECT  39.829 24.129 40.043 26.336 ;
     RECT  39.973 28.352 40.043 31.328 ;
     RECT  38.291 34.929 40.053 36.512 ;
     RECT  40.053 34.432 40.069 36.512 ;
     RECT  40.043 28.8 40.107 31.328 ;
     RECT  40.069 34.432 40.235 37.664 ;
     RECT  39.829 5.568 40.643 5.6 ;
     RECT  37.139 2.529 41.075 3.872 ;
     RECT  38.398 40.329 41.075 41.184 ;
     RECT  40.107 28.8 41.909 30.201 ;
     RECT  41.909 28.8 41.987 31.392 ;
     RECT  2.16 56.529 42.133 57.201 ;
     RECT  40.043 24.129 42.179 25.952 ;
     RECT  36.213 22.656 42.227 22.688 ;
     RECT  40.235 37.632 42.227 37.664 ;
     RECT  33.971 18.729 42.469 19.401 ;
     RECT  42.179 24.129 42.485 24.801 ;
     RECT  42.469 18.729 42.539 19.936 ;
     RECT  2.16 88.929 42.869 89.601 ;
     RECT  42.853 91.84 42.923 91.872 ;
     RECT  2.16 121.329 43.189 122.001 ;
     RECT  33.579 123.456 43.189 123.488 ;
     RECT  42.133 56.529 43.243 57.568 ;
     RECT  43.17 92.032 43.243 92.064 ;
     RECT  41.075 40.329 43.477 41.001 ;
     RECT  43.243 56.529 43.763 57.312 ;
     RECT  41.075 2.529 43.909 3.201 ;
     RECT  38.187 178.56 44.483 178.592 ;
     RECT  41.987 29.529 44.629 30.201 ;
     RECT  40.235 34.929 44.965 35.744 ;
     RECT  43.765 27.904 45.301 27.936 ;
     RECT  44.629 29.529 45.301 30.752 ;
     RECT  45.301 27.904 45.355 30.752 ;
     RECT  42.485 23.296 45.429 24.801 ;
     RECT  45.301 26.112 45.429 26.144 ;
     RECT  45.422 38.784 45.491 38.816 ;
     RECT  45.429 23.296 45.502 26.144 ;
     RECT  35.939 7.929 46.069 8.601 ;
     RECT  42.539 18.729 46.117 19.401 ;
     RECT  46.069 7.424 46.163 8.601 ;
     RECT  43.189 121.329 46.211 123.488 ;
     RECT  46.163 7.929 46.325 8.601 ;
     RECT  46.325 7.929 46.403 9.76 ;
     RECT  45.502 23.296 46.595 24.801 ;
     RECT  43.909 2.529 46.645 4.32 ;
     RECT  45.355 28.864 46.833 30.752 ;
     RECT  44.965 34.929 46.835 36.512 ;
     RECT  38.187 180.729 46.965 181.401 ;
     RECT  46.965 0.192 47.221 0.224 ;
     RECT  46.833 29.529 47.221 30.752 ;
     RECT  46.835 34.929 47.269 35.744 ;
     RECT  46.645 2.529 47.285 4.576 ;
     RECT  47.221 29.529 47.363 31.392 ;
     RECT  45.502 26.112 47.459 26.144 ;
     RECT  46.595 24.129 47.653 24.801 ;
     RECT  47.653 24.129 47.723 25.632 ;
     RECT  47.221 0.192 47.861 0.288 ;
     RECT  47.285 1.728 47.861 4.576 ;
     RECT  46.965 180.729 47.861 181.536 ;
     RECT  47.861 0.192 47.866 4.576 ;
     RECT  48.053 6.272 48.131 6.304 ;
     RECT  46.117 18.729 48.181 20.64 ;
     RECT  48.181 18.729 48.227 20.768 ;
     RECT  47.669 38.336 48.227 38.368 ;
     RECT  46.403 7.929 48.309 8.601 ;
     RECT  47.866 0.192 48.515 4.384 ;
     RECT  48.309 7.929 48.515 9.184 ;
     RECT  43.477 40.329 48.661 42.272 ;
     RECT  48.661 40.329 48.663 42.784 ;
     RECT  48.663 40.192 48.747 42.784 ;
     RECT  48.515 7.929 48.885 8.601 ;
     RECT  47.723 24.129 49.013 24.801 ;
     RECT  49.013 22.848 49.091 24.801 ;
     RECT  49.205 10.816 49.283 10.848 ;
     RECT  47.269 34.816 49.506 35.744 ;
     RECT  49.506 33.728 49.579 35.744 ;
     RECT  49.525 31.872 49.619 31.904 ;
     RECT  48.515 1.728 49.835 4.384 ;
     RECT  48.885 7.808 50.03 8.601 ;
     RECT  49.091 24.129 50.037 24.801 ;
     RECT  50.03 7.808 50.099 9.184 ;
     RECT  50.03 27.968 50.099 28 ;
     RECT  50.037 24.129 50.195 26.016 ;
     RECT  48.629 0.064 50.222 0.096 ;
     RECT  48.421 38.4 50.293 38.432 ;
     RECT  48.747 40.192 50.347 41.001 ;
     RECT  50.293 37.12 50.357 38.432 ;
     RECT  50.357 37.056 50.531 38.432 ;
     RECT  48.747 42.752 50.771 42.784 ;
     RECT  47.861 180.729 50.859 181.792 ;
     RECT  48.227 20.736 50.915 20.768 ;
     RECT  50.099 7.808 50.987 8.736 ;
     RECT  50.869 11.328 51.243 11.36 ;
     RECT  51.253 183.488 51.435 183.52 ;
     RECT  50.222 0.064 51.443 0.608 ;
     RECT  51.374 5.696 51.443 5.728 ;
     RECT  50.987 7.929 51.765 8.736 ;
     RECT  49.579 34.688 51.923 35.744 ;
     RECT  51.443 0.192 51.95 0.608 ;
     RECT  47.363 29.529 52.117 30.201 ;
     RECT  50.859 180.729 52.277 181.664 ;
     RECT  49.835 2.529 52.334 4.384 ;
     RECT  52.277 180.729 52.355 181.792 ;
     RECT  52.085 10.816 52.499 10.848 ;
     RECT  50.531 37.056 52.499 37.088 ;
     RECT  48.227 18.729 52.661 19.401 ;
     RECT  52.645 6.208 52.715 6.24 ;
     RECT  51.765 7.929 53.075 9.184 ;
     RECT  52.661 18.729 53.075 20 ;
     RECT  52.117 29.529 53.429 31.008 ;
     RECT  53.365 27.328 53.483 27.36 ;
     RECT  53.429 29.376 53.507 31.328 ;
     RECT  53.075 7.929 53.653 8.601 ;
     RECT  52.355 180.729 53.749 181.536 ;
     RECT  53.749 180.729 53.818 181.792 ;
     RECT  51.95 0.192 53.843 1.184 ;
     RECT  53.507 29.529 53.845 31.328 ;
     RECT  51.923 34.929 53.877 35.744 ;
     RECT  53.845 29.529 53.931 32.48 ;
     RECT  50.195 24.129 54.277 24.801 ;
     RECT  54.277 24 54.325 24.801 ;
     RECT  54.306 22.144 54.379 22.176 ;
     RECT  54.325 24 54.379 24.928 ;
     RECT  53.653 7.808 54.389 8.601 ;
     RECT  54.389 7.616 54.467 8.601 ;
     RECT  46.211 123.456 54.709 123.488 ;
     RECT  54.709 123.456 54.955 123.616 ;
     RECT  52.334 2.529 54.965 4.576 ;
     RECT  54.901 107.2 54.97 108.256 ;
     RECT  54.955 123.584 55.019 123.616 ;
     RECT  54.965 2.529 55.043 5.152 ;
     RECT  50.347 40.329 55.141 41.001 ;
     RECT  53.843 0.192 55.157 0.608 ;
     RECT  53.877 34.929 55.221 35.808 ;
     RECT  50.531 38.4 55.275 38.432 ;
     RECT  55.141 40.192 55.285 41.001 ;
     RECT  53.125 42.624 55.285 42.656 ;
     RECT  53.931 29.529 55.477 30.201 ;
     RECT  55.477 29.529 55.546 30.752 ;
     RECT  55.285 40.192 55.619 42.656 ;
     RECT  55.221 34.929 55.797 36.832 ;
     RECT  55.797 34.929 55.907 37.6 ;
     RECT  55.157 0.064 55.955 0.608 ;
     RECT  55.955 0.576 56.147 0.608 ;
     RECT  53.818 180.729 56.147 181.536 ;
     RECT  54.379 24.129 56.245 24.928 ;
     RECT  53.075 18.729 56.293 19.401 ;
     RECT  56.245 27.392 56.314 27.424 ;
     RECT  56.245 24.129 56.339 25.376 ;
     RECT  55.619 40.192 56.819 41.376 ;
     RECT  55.546 29.529 56.965 30.496 ;
     RECT  56.293 18.729 57.157 20.512 ;
     RECT  57.157 18.729 57.205 21.664 ;
     RECT  57.205 18.729 57.259 21.728 ;
     RECT  56.339 24.129 57.333 25.056 ;
     RECT  57.259 21.632 57.515 21.728 ;
     RECT  57.333 23.872 57.515 25.056 ;
     RECT  55.043 2.529 58.101 4.128 ;
     RECT  54.965 129.408 58.146 129.44 ;
     RECT  58.101 2.529 58.155 4.832 ;
     RECT  58.146 129.408 58.163 129.632 ;
     RECT  56.147 180.729 58.165 181.401 ;
     RECT  58.163 129.6 58.219 129.632 ;
     RECT  56.965 29.529 58.859 31.008 ;
     RECT  58.789 32.512 58.859 32.672 ;
     RECT  58.859 32.64 58.923 32.672 ;
     RECT  55.907 34.929 59.173 36.832 ;
     RECT  58.859 29.529 59.315 30.368 ;
     RECT  56.819 40.329 59.315 41.376 ;
     RECT  59.253 27.328 59.326 27.36 ;
     RECT  57.515 21.632 59.555 21.664 ;
     RECT  57.515 24.129 59.765 25.056 ;
     RECT  59.173 34.929 60.398 37.216 ;
     RECT  60.398 34.816 60.405 37.216 ;
     RECT  59.765 24.129 60.467 25.184 ;
     RECT  60.405 34.816 60.467 37.344 ;
     RECT  60.467 24.129 60.613 24.801 ;
     RECT  59.315 40.329 61.333 41.001 ;
     RECT  61.333 39.104 61.557 41.001 ;
     RECT  61.557 39.104 61.611 41.632 ;
     RECT  58.155 4.8 61.669 4.832 ;
     RECT  59.315 29.529 61.669 30.201 ;
     RECT  57.259 18.729 62.773 19.401 ;
     RECT  60.467 34.929 62.819 37.344 ;
     RECT  62.773 18.729 62.955 20.256 ;
     RECT  60.613 22.912 62.955 24.801 ;
     RECT  61.669 32.384 63.205 32.416 ;
     RECT  63.205 31.552 63.278 32.416 ;
     RECT  62.819 34.929 63.278 37.088 ;
     RECT  61.611 40.329 63.299 41.632 ;
     RECT  63.278 31.552 63.339 37.088 ;
     RECT  63.339 33.664 63.347 37.088 ;
     RECT  62.955 24.129 63.397 24.801 ;
     RECT  61.669 29.376 63.731 30.201 ;
     RECT  64.43 1.152 64.693 1.184 ;
     RECT  58.155 2.529 64.693 3.201 ;
     RECT  63.347 34.929 64.747 37.088 ;
     RECT  64.693 1.152 64.787 3.201 ;
     RECT  64.787 1.152 65.006 1.184 ;
     RECT  64.693 38.784 65.027 38.816 ;
     RECT  61.669 4.8 65.205 4.896 ;
     RECT  65.205 4.8 65.269 5.152 ;
     RECT  65.269 4.544 65.315 5.152 ;
     RECT  62.955 18.729 65.509 19.401 ;
     RECT  58.165 179.584 65.701 181.401 ;
     RECT  65.315 4.544 65.939 4.96 ;
     RECT  65.509 18.729 65.973 19.936 ;
     RECT  63.397 24.129 65.973 25.696 ;
     RECT  65.966 27.392 65.973 27.424 ;
     RECT  65.973 24.129 66.027 27.424 ;
     RECT  66.027 26.88 66.035 27.424 ;
     RECT  65.973 18.729 66.037 21.92 ;
     RECT  66.037 18.729 66.083 22.24 ;
     RECT  66.027 24.129 66.083 25.056 ;
     RECT  66.083 24.129 66.091 24.928 ;
     RECT  66.083 22.208 66.106 22.24 ;
     RECT  64.787 2.529 66.421 3.201 ;
     RECT  65.006 0.064 66.613 1.184 ;
     RECT  66.421 2.529 66.613 3.488 ;
     RECT  65.939 4.864 66.661 4.96 ;
     RECT  66.613 0.064 66.803 3.488 ;
     RECT  65.701 179.584 67.189 181.536 ;
     RECT  66.803 0.064 67.258 3.201 ;
     RECT  67.258 0.064 67.379 1.184 ;
     RECT  67.189 179.584 67.571 181.792 ;
     RECT  66.661 4.864 67.573 5.792 ;
     RECT  64.747 34.929 67.619 35.808 ;
     RECT  63.299 40.329 67.619 41.12 ;
     RECT  66.083 18.729 67.859 20.64 ;
     RECT  67.379 0.192 67.907 1.184 ;
     RECT  66.091 24.129 67.957 24.801 ;
     RECT  67.573 4.544 68.149 5.792 ;
     RECT  54.467 7.929 68.149 8.601 ;
     RECT  67.258 2.529 68.213 3.201 ;
     RECT  68.149 4.544 68.213 8.601 ;
     RECT  68.213 2.529 68.218 8.601 ;
     RECT  67.907 0.192 68.435 0.608 ;
     RECT  67.957 24.129 68.629 24.928 ;
     RECT  68.629 24.129 68.725 25.376 ;
     RECT  66.035 26.88 68.725 26.912 ;
     RECT  68.725 24.129 68.779 28.064 ;
     RECT  67.093 42.432 69.059 42.464 ;
     RECT  63.731 29.529 69.157 30.201 ;
     RECT  69.157 29.529 69.227 30.368 ;
     RECT  67.619 34.929 69.253 35.744 ;
     RECT  68.218 2.529 69.299 6.048 ;
     RECT  66.949 33.472 69.491 33.504 ;
     RECT  69.253 34.929 69.557 36.704 ;
     RECT  67.765 38.208 69.557 38.24 ;
     RECT  67.571 179.584 69.557 181.536 ;
     RECT  69.557 34.929 69.611 38.24 ;
     RECT  69.557 179.584 69.635 181.792 ;
     RECT  67.619 40.329 69.666 41.001 ;
     RECT  69.611 37.184 69.739 38.24 ;
     RECT  69.666 39.616 69.739 41.001 ;
     RECT  68.435 0.576 69.806 0.608 ;
     RECT  69.299 2.529 69.806 3.201 ;
     RECT  70.357 22.208 70.389 22.24 ;
     RECT  68.779 24.129 70.389 25.76 ;
     RECT  70.389 22.208 70.443 25.76 ;
     RECT  69.806 0.576 70.835 3.201 ;
     RECT  69.635 179.584 71.285 181.536 ;
     RECT  68.779 28.032 71.315 28.064 ;
     RECT  69.611 34.929 71.349 35.744 ;
     RECT  71.317 31.872 71.403 31.904 ;
     RECT  68.218 7.929 71.605 8.601 ;
     RECT  69.739 37.184 71.747 37.216 ;
     RECT  70.443 23.04 71.843 25.76 ;
     RECT  71.349 34.816 71.843 35.744 ;
     RECT  71.285 179.584 72.227 181.792 ;
     RECT  72.227 179.904 72.25 181.792 ;
     RECT  69.299 4.544 72.325 6.048 ;
     RECT  71.605 7.424 72.325 8.601 ;
     RECT  71.843 23.04 72.419 24.801 ;
     RECT  70.835 0.576 72.421 1.184 ;
     RECT  70.835 2.529 72.421 3.201 ;
     RECT  67.859 18.729 72.469 19.401 ;
     RECT  69.739 40.329 72.469 41.001 ;
     RECT  69.493 42.496 72.469 42.528 ;
     RECT  72.421 0.576 72.491 3.201 ;
     RECT  27.883 45.729 72.629 46.401 ;
     RECT  72.469 40.329 72.683 42.528 ;
     RECT  72.25 179.904 72.811 181.6 ;
     RECT  72.325 4.544 72.875 8.601 ;
     RECT  72.469 18.729 72.875 20 ;
     RECT  69.227 29.529 72.997 30.201 ;
     RECT  72.491 2.529 73.013 3.201 ;
     RECT  72.875 4.544 73.013 6.048 ;
     RECT  73.013 2.529 73.091 6.048 ;
     RECT  72.491 0.576 73.397 1.184 ;
     RECT  73.091 4.544 73.427 6.048 ;
     RECT  73.397 0.192 73.571 1.184 ;
     RECT  72.997 28.416 73.845 30.201 ;
     RECT  71.843 34.929 73.845 35.744 ;
     RECT  73.845 28.416 73.899 31.136 ;
     RECT  73.899 29.529 73.955 31.136 ;
     RECT  72.629 44.864 74.053 46.401 ;
     RECT  73.571 0.576 74.222 1.184 ;
     RECT  73.091 2.529 74.222 3.201 ;
     RECT  72.811 179.904 74.222 181.536 ;
     RECT  74.222 0.576 74.291 3.201 ;
     RECT  74.222 179.904 74.291 181.792 ;
     RECT  73.427 4.928 74.387 6.048 ;
     RECT  74.291 0.576 74.579 1.184 ;
     RECT  72.419 24.129 74.629 24.801 ;
     RECT  72.683 40.329 74.629 41.001 ;
     RECT  74.579 1.152 74.867 1.184 ;
     RECT  73.845 33.728 74.869 35.744 ;
     RECT  74.291 179.904 74.878 181.536 ;
     RECT  74.869 33.728 74.923 36.96 ;
     RECT  72.875 7.929 75.701 8.601 ;
     RECT  75.685 21.12 75.755 21.152 ;
     RECT  73.955 29.529 75.925 30.201 ;
     RECT  74.629 24.129 76.011 25.376 ;
     RECT  75.925 28.544 76.011 30.201 ;
     RECT  74.053 44.672 76.661 46.401 ;
     RECT  74.629 40.329 76.715 41.952 ;
     RECT  76.661 43.52 76.715 46.401 ;
     RECT  74.923 34.929 76.725 36.96 ;
     RECT  76.715 40.329 76.739 41.12 ;
     RECT  76.739 40.329 76.837 41.001 ;
     RECT  76.837 39.36 76.907 41.001 ;
     RECT  75.957 26.752 76.979 26.784 ;
     RECT  76.725 34.816 77.291 36.96 ;
     RECT  77.221 38.784 77.291 38.816 ;
     RECT  77.291 34.816 77.315 36.128 ;
     RECT  76.715 45.729 77.893 46.401 ;
     RECT  76.011 29.529 78.613 30.201 ;
     RECT  73.269 48.704 78.851 48.736 ;
     RECT  77.315 34.816 78.949 35.601 ;
     RECT  77.461 33.344 78.965 33.376 ;
     RECT  78.965 33.088 79.019 33.376 ;
     RECT  78.949 34.816 79.019 35.744 ;
     RECT  78.613 29.248 80.034 30.201 ;
     RECT  80.034 29.248 80.053 30.56 ;
     RECT  80.053 28.992 80.107 30.56 ;
     RECT  76.715 43.52 80.117 43.552 ;
     RECT  77.893 45.729 80.149 46.816 ;
     RECT  80.117 42.624 80.171 43.552 ;
     RECT  80.149 45.568 80.235 46.816 ;
     RECT  74.291 2.529 80.293 3.201 ;
     RECT  74.387 4.928 80.293 4.96 ;
     RECT  75.701 7.68 80.309 8.601 ;
     RECT  80.293 2.529 80.363 4.96 ;
     RECT  80.171 42.624 80.435 42.72 ;
     RECT  80.435 42.624 80.531 42.656 ;
     RECT  74.878 179.904 80.917 181.401 ;
     RECT  80.107 28.992 80.963 30.201 ;
     RECT  78.901 48.768 80.963 48.8 ;
     RECT  80.917 179.584 81.061 181.401 ;
     RECT  81.061 178.368 81.131 181.401 ;
     RECT  80.309 7.424 81.539 8.601 ;
     RECT  81.539 7.68 81.587 8.601 ;
     RECT  81.131 179.904 81.637 181.401 ;
     RECT  79.019 33.088 81.685 33.12 ;
     RECT  79.019 34.816 81.685 35.601 ;
     RECT  81.685 33.088 81.717 35.601 ;
     RECT  81.717 31.872 81.771 35.601 ;
     RECT  81.771 31.872 82.115 31.904 ;
     RECT  81.771 34.929 82.453 35.601 ;
     RECT  80.235 45.729 82.453 46.401 ;
     RECT  82.453 45.729 82.539 46.56 ;
     RECT  81.637 179.904 82.547 182.368 ;
     RECT  76.907 40.329 82.597 41.001 ;
     RECT  82.453 34.929 82.667 36.448 ;
     RECT  80.341 38.592 82.667 38.624 ;
     RECT  82.597 40.329 82.667 41.312 ;
     RECT  82.485 44.224 82.691 44.256 ;
     RECT  80.363 2.529 82.805 3.201 ;
     RECT  82.805 2.529 82.931 4.064 ;
     RECT  82.597 1.152 82.981 1.184 ;
     RECT  82.981 0.576 83.269 1.184 ;
     RECT  82.931 2.529 83.269 4 ;
     RECT  83.269 0.576 83.843 4 ;
     RECT  81.587 7.929 84.24 8.601 ;
     RECT  2.16 13.329 84.24 14.001 ;
     RECT  72.875 18.729 84.24 19.401 ;
     RECT  76.011 24.129 84.24 24.801 ;
     RECT  80.963 29.529 84.24 30.201 ;
     RECT  82.667 34.929 84.24 35.601 ;
     RECT  82.667 40.329 84.24 41.001 ;
     RECT  82.539 45.729 84.24 46.401 ;
     RECT  2.16 51.129 84.24 51.801 ;
     RECT  43.763 56.529 84.24 57.201 ;
     RECT  2.16 61.929 84.24 62.601 ;
     RECT  2.16 67.329 84.24 68.001 ;
     RECT  2.16 72.729 84.24 73.401 ;
     RECT  2.16 78.129 84.24 78.801 ;
     RECT  2.16 83.529 84.24 84.201 ;
     RECT  42.869 88.704 84.24 89.601 ;
     RECT  2.16 94.329 84.24 95.001 ;
     RECT  2.16 99.729 84.24 100.401 ;
     RECT  2.16 105.129 84.24 105.801 ;
     RECT  33.658 110.529 84.24 111.201 ;
     RECT  2.16 115.929 84.24 116.601 ;
     RECT  46.211 121.329 84.24 122.001 ;
     RECT  2.16 126.729 84.24 127.401 ;
     RECT  2.16 132.129 84.24 132.801 ;
     RECT  2.16 137.529 84.24 138.201 ;
     RECT  2.16 142.929 84.24 143.601 ;
     RECT  2.16 148.329 84.24 149.001 ;
     RECT  2.16 153.729 84.24 154.401 ;
     RECT  2.16 159.129 84.24 159.801 ;
     RECT  2.16 164.529 84.24 165.201 ;
     RECT  2.16 169.929 84.24 170.601 ;
     RECT  2.16 175.329 84.24 176.001 ;
     RECT  82.547 180.729 84.24 182.368 ;
     RECT  83.843 0.576 84.267 3.488 ;
     RECT  84.267 0.576 84.277 0.928 ;
     RECT  84.277 0.32 84.325 0.928 ;
     RECT  84.24 181.76 84.949 182.368 ;
     RECT  84.267 2.304 85.163 3.488 ;
     RECT  84.949 181.76 85.419 183.008 ;
     RECT  85.163 3.328 85.477 3.488 ;
     RECT  84.325 0.192 85.483 0.928 ;
     RECT  85.419 181.76 85.69 182.944 ;
     RECT  85.483 0.32 85.739 0.928 ;
     RECT  85.739 0.576 85.909 0.928 ;
     RECT  85.909 0.576 85.995 1.184 ;
     RECT  85.69 181.76 85.995 181.92 ;
     RECT  85.477 3.328 86.059 4 ;
     RECT  84.24 88.704 86.243 88.736 ;
     RECT  86.059 3.328 86.251 3.36 ;
     RECT  85.995 181.888 86.251 181.92 ;
     RECT  85.995 0.576 86.315 0.608 ;
    LAYER M7 ;
     RECT  9.344 0.035 18.592 0.555 ;
     RECT  46.08 0.035 56.096 0.619 ;
     RECT  82.816 0.035 86.304 0.619 ;
     RECT  9.344 0.555 18.336 1.195 ;
     RECT  64.448 0.035 74.848 1.195 ;
     RECT  64.704 1.195 74.272 1.771 ;
     RECT  64.704 1.771 73.376 2.347 ;
     RECT  82.816 0.619 86.24 2.347 ;
     RECT  86.016 2.347 86.24 3.371 ;
     RECT  9.344 1.195 18.016 3.499 ;
     RECT  27.712 0.035 37.344 3.499 ;
     RECT  65.28 2.347 73.376 3.499 ;
     RECT  82.816 2.347 84.512 3.499 ;
     RECT  82.816 3.499 83.68 4.011 ;
     RECT  86.016 3.371 86.048 4.011 ;
     RECT  82.816 4.011 82.848 4.075 ;
     RECT  46.08 0.619 55.008 4.085 ;
     RECT  27.712 3.499 34.336 4.587 ;
     RECT  36.288 3.499 36.896 4.587 ;
     RECT  46.08 4.085 55.904 4.587 ;
     RECT  65.28 3.499 65.888 4.587 ;
     RECT  67.584 3.499 73.376 4.587 ;
     RECT  58.112 3.381 58.144 4.843 ;
     RECT  30.272 4.587 31.456 5.163 ;
     RECT  34.304 4.587 34.336 5.163 ;
     RECT  48.064 4.587 55.904 5.163 ;
     RECT  65.216 4.789 65.248 5.163 ;
     RECT  70.464 4.587 71.904 5.163 ;
     RECT  48.064 5.163 54.432 6.315 ;
     RECT  71.616 5.163 71.904 6.709 ;
     RECT  68.16 4.587 68.704 6.891 ;
     RECT  3.84 6.197 3.872 7.339 ;
     RECT  9.344 3.499 17.952 7.467 ;
     RECT  46.08 4.587 46.368 7.467 ;
     RECT  71.616 6.709 72.864 7.467 ;
     RECT  80.32 4.277 80.352 7.467 ;
     RECT  48.32 6.315 54.432 7.659 ;
     RECT  9.6 7.467 17.952 7.851 ;
     RECT  27.712 4.587 27.744 7.851 ;
     RECT  48.32 7.659 53.856 7.851 ;
     RECT  9.6 7.851 17.568 8.747 ;
     RECT  9.6 8.747 12.512 9.195 ;
     RECT  13.888 8.747 14.816 9.195 ;
     RECT  48.32 7.851 52.96 9.195 ;
     RECT  16.192 8.747 17.568 9.771 ;
     RECT  46.336 7.467 46.368 9.771 ;
     RECT  16.512 9.771 17.568 10.283 ;
     RECT  10.752 9.195 12.512 10.347 ;
     RECT  11.2 10.347 12.512 10.859 ;
     RECT  14.784 9.195 14.816 10.859 ;
     RECT  49.216 9.195 49.248 10.859 ;
     RECT  51.2 9.195 52.704 10.859 ;
     RECT  51.2 10.859 51.232 11.371 ;
     RECT  52.672 10.859 52.704 20.011 ;
     RECT  72.832 7.467 72.864 20.011 ;
     RECT  17.536 10.283 17.568 20.277 ;
     RECT  31.36 5.163 31.456 20.523 ;
     RECT  57.216 20.469 57.248 21.685 ;
     RECT  57.216 21.685 57.504 21.739 ;
     RECT  65.984 19.893 66.016 21.931 ;
     RECT  24.384 20.469 24.416 22.261 ;
     RECT  24.128 22.261 24.416 22.315 ;
     RECT  12.032 10.859 12.064 22.443 ;
     RECT  16.576 20.277 17.568 22.699 ;
     RECT  32.768 20.469 32.8 22.699 ;
     RECT  49.024 20.725 49.056 22.891 ;
     RECT  62.912 20.213 62.944 22.955 ;
     RECT  42.496 19.893 42.528 23.339 ;
     RECT  57.472 21.739 57.504 23.861 ;
     RECT  57.344 23.861 57.504 23.915 ;
     RECT  28.48 21.621 28.512 23.989 ;
     RECT  31.424 20.523 31.456 23.989 ;
     RECT  28.48 23.989 28.832 24.043 ;
     RECT  24.128 22.315 24.16 24.885 ;
     RECT  55.872 5.163 55.904 24.885 ;
     RECT  57.344 23.915 57.376 24.885 ;
     RECT  16.832 22.699 17.568 24.939 ;
     RECT  19.584 20.725 19.616 24.939 ;
     RECT  24.128 24.885 24.48 24.939 ;
     RECT  54.336 22.133 54.368 24.939 ;
     RECT  66.048 22.197 66.08 24.939 ;
     RECT  17.536 24.939 17.568 24.949 ;
     RECT  17.536 24.949 17.632 24.95 ;
     RECT  17.6 24.95 17.632 25.013 ;
     RECT  58.752 24.885 58.784 25.013 ;
     RECT  55.872 24.885 57.376 25.067 ;
     RECT  36.224 21.109 36.256 25.131 ;
     RECT  58.752 25.013 59.808 25.195 ;
     RECT  75.712 7.669 75.744 25.333 ;
     RECT  39.872 22.645 39.904 25.387 ;
     RECT  75.712 25.333 76 25.387 ;
     RECT  30.336 23.989 31.456 25.515 ;
     RECT  5.76 21.429 5.792 25.707 ;
     RECT  68.672 6.891 68.704 25.717 ;
     RECT  70.4 22.197 70.432 25.771 ;
     RECT  45.44 23.285 45.472 26.101 ;
     RECT  45.312 26.101 45.472 26.155 ;
     RECT  28.8 24.043 28.832 26.421 ;
     RECT  24.448 24.939 24.48 26.485 ;
     RECT  17.6 25.013 18.4 26.539 ;
     RECT  28.672 26.421 28.832 27.253 ;
     RECT  28.672 27.253 29.024 27.307 ;
     RECT  55.872 25.067 56.288 27.435 ;
     RECT  65.984 25.013 66.016 27.435 ;
     RECT  38.016 26.485 38.048 27.637 ;
     RECT  3.776 25.653 3.808 27.765 ;
     RECT  3.456 27.765 3.808 27.819 ;
     RECT  28.992 27.307 29.024 27.829 ;
     RECT  24.448 26.485 25.504 27.893 ;
     RECT  50.048 25.973 50.08 28.011 ;
     RECT  68.672 25.717 68.768 28.021 ;
     RECT  28.992 27.829 29.792 28.587 ;
     RECT  75.968 25.387 76 28.587 ;
     RECT  40 25.909 40.032 28.843 ;
     RECT  47.68 25.589 47.712 28.853 ;
     RECT  31.424 25.515 31.456 28.907 ;
     RECT  45.312 26.155 45.344 28.907 ;
     RECT  29.76 28.587 29.792 28.981 ;
     RECT  37.632 27.637 38.048 28.981 ;
     RECT  18.368 26.539 18.4 29.419 ;
     RECT  13.12 27.893 13.152 30.325 ;
     RECT  12.48 30.325 13.152 30.379 ;
     RECT  58.752 25.195 59.296 30.379 ;
     RECT  55.872 27.435 55.904 30.507 ;
     RECT  24.384 27.893 25.504 30.571 ;
     RECT  46.784 28.853 47.712 30.763 ;
     RECT  53.44 27.317 53.472 31.285 ;
     RECT  53.44 31.285 53.92 31.339 ;
     RECT  16.512 29.365 16.544 31.403 ;
     RECT  41.92 28.789 41.952 31.403 ;
     RECT  47.232 30.763 47.712 31.403 ;
     RECT  34.56 30.325 34.592 31.861 ;
     RECT  34.56 31.861 35.232 31.915 ;
     RECT  36.736 28.981 38.048 31.979 ;
     RECT  3.456 27.819 3.488 32.245 ;
     RECT  3.328 32.245 3.488 32.299 ;
     RECT  58.752 30.379 58.912 32.683 ;
     RECT  80.064 28.981 80.096 33.077 ;
     RECT  78.976 33.077 80.096 33.131 ;
     RECT  12.48 30.379 12.512 33.269 ;
     RECT  12.224 33.269 12.512 33.323 ;
     RECT  68.672 28.021 69.216 33.515 ;
     RECT  20.672 25.525 20.704 33.643 ;
     RECT  63.296 29.365 63.328 33.707 ;
     RECT  73.856 28.405 73.888 33.717 ;
     RECT  35.2 31.915 35.232 33.771 ;
     RECT  73.856 33.717 74.912 33.771 ;
     RECT  81.728 31.861 81.76 34.091 ;
     RECT  27.328 30.517 27.36 34.283 ;
     RECT  3.328 32.299 3.36 34.347 ;
     RECT  29.76 28.981 30.56 34.347 ;
     RECT  40.064 31.285 40.096 34.421 ;
     RECT  40.064 34.421 40.224 34.475 ;
     RECT  49.536 31.861 49.568 34.677 ;
     RECT  22.656 33.589 22.688 34.741 ;
     RECT  38.016 31.979 38.048 34.805 ;
     RECT  71.36 31.861 71.392 34.805 ;
     RECT  49.536 34.677 50.528 34.859 ;
     RECT  71.36 34.805 71.712 34.859 ;
     RECT  76.736 34.805 76.768 35.701 ;
     RECT  55.488 30.709 55.52 35.755 ;
     RECT  68.672 33.515 68.704 35.755 ;
     RECT  76.736 35.701 76.896 35.755 ;
     RECT  78.976 33.131 79.008 35.755 ;
     RECT  22.336 34.741 22.688 35.765 ;
     RECT  53.888 31.339 53.92 35.819 ;
     RECT  12.224 33.323 12.256 35.947 ;
     RECT  14.272 34.677 14.304 35.947 ;
     RECT  29.824 34.347 30.56 35.957 ;
     RECT  25.472 30.571 25.504 36.011 ;
     RECT  7.104 27.893 7.136 36.021 ;
     RECT  76.864 35.755 76.896 36.085 ;
     RECT  35.264 34.165 35.296 36.213 ;
     RECT  35.264 36.213 35.424 36.267 ;
     RECT  37.76 34.805 38.048 36.523 ;
     RECT  63.552 35.765 63.584 36.661 ;
     RECT  55.296 35.765 55.328 36.789 ;
     RECT  58.752 32.683 58.784 36.843 ;
     RECT  29.824 35.957 30.752 36.971 ;
     RECT  74.88 33.771 74.912 36.971 ;
     RECT  22.336 35.765 22.752 37.035 ;
     RECT  50.368 34.859 50.4 37.109 ;
     RECT  50.304 37.109 50.4 37.11 ;
     RECT  71.68 34.859 71.712 37.227 ;
     RECT  60.416 34.805 60.448 37.301 ;
     RECT  60.416 37.301 61.6 37.355 ;
     RECT  55.232 36.789 55.328 37.557 ;
     RECT  37.76 36.523 37.984 37.611 ;
     RECT  40.192 34.475 40.224 37.675 ;
     RECT  7.104 36.021 7.712 38.005 ;
     RECT  69.568 36.661 69.6 38.197 ;
     RECT  69.568 38.197 69.728 38.251 ;
     RECT  30.72 36.971 30.752 38.325 ;
     RECT  30.4 38.325 30.752 38.379 ;
     RECT  35.392 36.267 35.424 38.379 ;
     RECT  47.68 31.403 47.712 38.379 ;
     RECT  55.232 37.557 55.84 38.389 ;
     RECT  22.336 37.035 22.56 38.645 ;
     RECT  22.336 38.645 22.688 38.827 ;
     RECT  45.44 36.469 45.472 38.827 ;
     RECT  63.552 36.661 64.736 38.827 ;
     RECT  76.864 36.085 77.28 38.827 ;
     RECT  33.088 38.901 33.12 39.029 ;
     RECT  33.088 39.029 33.632 39.083 ;
     RECT  37.952 37.611 37.984 39.083 ;
     RECT  30.4 38.379 30.432 39.147 ;
     RECT  76.864 38.827 76.896 39.403 ;
     RECT  16 36.149 16.032 39.605 ;
     RECT  15.424 39.605 16.032 39.659 ;
     RECT  22.464 38.827 22.688 39.861 ;
     RECT  7.104 38.005 7.968 40.181 ;
     RECT  7.104 40.181 9.248 40.235 ;
     RECT  22.464 39.861 22.752 40.235 ;
     RECT  50.304 37.11 50.336 40.235 ;
     RECT  54.912 38.389 55.84 40.235 ;
     RECT  7.104 40.235 7.456 41.131 ;
     RECT  63.552 38.827 63.584 41.131 ;
     RECT  35.456 38.453 35.488 41.195 ;
     RECT  38.336 40.181 38.368 41.195 ;
     RECT  9.216 40.235 9.248 41.269 ;
     RECT  9.216 41.269 9.568 41.323 ;
     RECT  43.712 35.701 43.744 41.461 ;
     RECT  61.568 37.355 61.6 41.643 ;
     RECT  7.424 41.131 7.456 41.899 ;
     RECT  43.712 41.461 44.256 42.283 ;
     RECT  3.584 40.181 3.616 42.411 ;
     RECT  69.696 38.251 69.728 42.539 ;
     RECT  15.424 39.659 15.456 42.613 ;
     RECT  15.424 42.613 15.712 42.667 ;
     RECT  48.704 40.181 48.736 42.667 ;
     RECT  54.912 40.235 55.328 42.667 ;
     RECT  80.128 42.613 80.16 42.677 ;
     RECT  22.464 40.235 22.496 42.795 ;
     RECT  28.992 40.181 29.024 43.317 ;
     RECT  27.84 43.317 29.024 43.371 ;
     RECT  80.128 42.677 80.224 43.563 ;
     RECT  82.624 36.405 82.656 44.213 ;
     RECT  82.496 44.213 82.656 44.267 ;
     RECT  15.68 42.667 15.712 44.523 ;
     RECT  27.84 43.371 27.872 44.523 ;
     RECT  76.672 41.077 76.704 44.715 ;
     RECT  72.64 41.269 72.672 44.853 ;
     RECT  9.536 41.323 9.568 44.907 ;
     RECT  72.64 44.853 73.312 44.907 ;
     RECT  82.496 44.267 82.528 46.571 ;
     RECT  80.192 43.563 80.224 46.827 ;
     RECT  73.28 44.907 73.312 48.747 ;
     RECT  43.712 42.283 43.744 57.323 ;
     RECT  43.2 57.525 43.232 88.693 ;
     RECT  42.88 88.693 43.232 91.883 ;
     RECT  33.6 39.083 33.632 112.171 ;
     RECT  43.2 91.883 43.232 123.179 ;
     RECT  54.912 42.667 54.944 123.445 ;
     RECT  54.72 123.445 54.944 123.573 ;
     RECT  54.72 123.573 55.008 123.627 ;
     RECT  33.536 112.245 33.568 123.637 ;
     RECT  33.344 123.637 33.568 123.691 ;
     RECT  54.976 123.627 55.008 129.451 ;
     RECT  33.344 123.691 33.376 134.571 ;
     RECT  58.176 129.589 58.208 179.573 ;
     RECT  31.616 135.029 31.648 179.627 ;
     RECT  38.144 178.549 38.176 179.627 ;
     RECT  58.176 179.573 58.656 179.627 ;
     RECT  81.088 178.357 81.12 179.627 ;
     RECT  58.624 179.627 58.656 180.203 ;
     RECT  84.8 181.749 85.984 181.877 ;
     RECT  84.8 181.877 86.24 182.325 ;
     RECT  9.472 181.493 18.592 183.556 ;
     RECT  28.224 181.493 37.344 183.556 ;
     RECT  46.976 181.493 56.096 183.556 ;
     RECT  65.728 181.493 74.848 183.556 ;
     RECT  84.48 182.325 86.24 183.556 ;
  END
END ot_qkvd_kv_wq_leaf
END LIBRARY
